VERSION 5.8 ;
BUSBITCHARS "[]" ;
DIVIDERCHAR "/" ;
UNITS
    DATABASE MICRONS 1000 ;
END UNITS

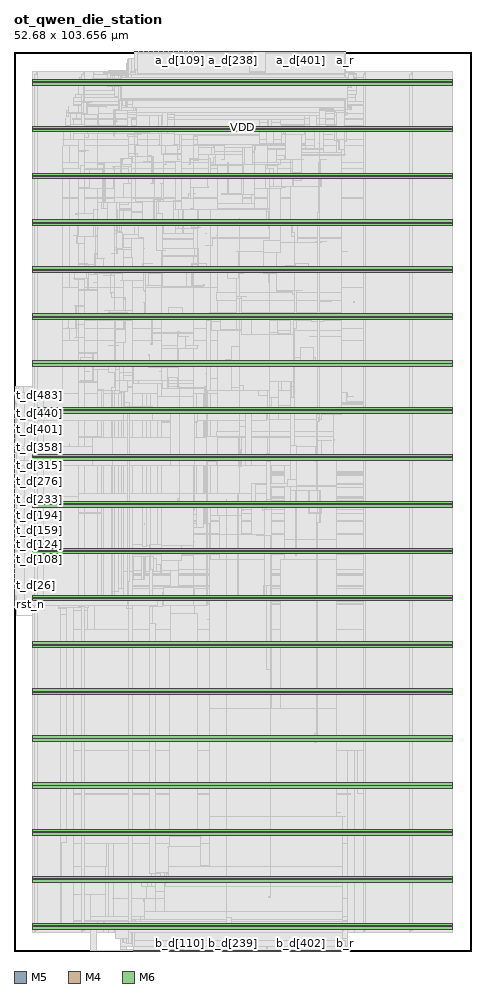
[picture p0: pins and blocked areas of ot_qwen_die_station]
MACRO ot_qwen_die_station
  FOREIGN ot_qwen_die_station 0 0 ;
  CLASS BLOCK ;
  SIZE 52.68 BY 103.656 ;
  PIN a_d[0]
    DIRECTION INPUT ;
    USE SIGNAL ;
    PORT
      LAYER M5 ;
        RECT  13.824 103.572 13.848 103.656 ;
    END
  END a_d[0]
  PIN a_d[100]
    DIRECTION INPUT ;
    USE SIGNAL ;
    PORT
      LAYER M5 ;
        RECT  18.624 103.572 18.648 103.656 ;
    END
  END a_d[100]
  PIN a_d[101]
    DIRECTION INPUT ;
    USE SIGNAL ;
    PORT
      LAYER M5 ;
        RECT  18.672 103.572 18.696 103.656 ;
    END
  END a_d[101]
  PIN a_d[102]
    DIRECTION INPUT ;
    USE SIGNAL ;
    PORT
      LAYER M5 ;
        RECT  18.72 103.572 18.744 103.656 ;
    END
  END a_d[102]
  PIN a_d[103]
    DIRECTION INPUT ;
    USE SIGNAL ;
    PORT
      LAYER M5 ;
        RECT  18.768 103.572 18.792 103.656 ;
    END
  END a_d[103]
  PIN a_d[104]
    DIRECTION INPUT ;
    USE SIGNAL ;
    PORT
      LAYER M5 ;
        RECT  18.816 103.572 18.84 103.656 ;
    END
  END a_d[104]
  PIN a_d[105]
    DIRECTION INPUT ;
    USE SIGNAL ;
    PORT
      LAYER M5 ;
        RECT  18.864 103.572 18.888 103.656 ;
    END
  END a_d[105]
  PIN a_d[106]
    DIRECTION INPUT ;
    USE SIGNAL ;
    PORT
      LAYER M5 ;
        RECT  18.912 103.572 18.936 103.656 ;
    END
  END a_d[106]
  PIN a_d[107]
    DIRECTION INPUT ;
    USE SIGNAL ;
    PORT
      LAYER M5 ;
        RECT  18.96 103.572 18.984 103.656 ;
    END
  END a_d[107]
  PIN a_d[108]
    DIRECTION INPUT ;
    USE SIGNAL ;
    PORT
      LAYER M5 ;
        RECT  19.008 103.572 19.032 103.656 ;
    END
  END a_d[108]
  PIN a_d[109]
    DIRECTION INPUT ;
    USE SIGNAL ;
    PORT
      LAYER M5 ;
        RECT  19.056 103.572 19.08 103.656 ;
    END
  END a_d[109]
  PIN a_d[10]
    DIRECTION INPUT ;
    USE SIGNAL ;
    PORT
      LAYER M5 ;
        RECT  14.304 103.572 14.328 103.656 ;
    END
  END a_d[10]
  PIN a_d[110]
    DIRECTION INPUT ;
    USE SIGNAL ;
    PORT
      LAYER M5 ;
        RECT  19.104 103.572 19.128 103.656 ;
    END
  END a_d[110]
  PIN a_d[111]
    DIRECTION INPUT ;
    USE SIGNAL ;
    PORT
      LAYER M5 ;
        RECT  19.152 103.572 19.176 103.656 ;
    END
  END a_d[111]
  PIN a_d[112]
    DIRECTION INPUT ;
    USE SIGNAL ;
    PORT
      LAYER M5 ;
        RECT  19.2 103.572 19.224 103.656 ;
    END
  END a_d[112]
  PIN a_d[113]
    DIRECTION INPUT ;
    USE SIGNAL ;
    PORT
      LAYER M5 ;
        RECT  19.248 103.572 19.272 103.656 ;
    END
  END a_d[113]
  PIN a_d[114]
    DIRECTION INPUT ;
    USE SIGNAL ;
    PORT
      LAYER M5 ;
        RECT  19.296 103.572 19.32 103.656 ;
    END
  END a_d[114]
  PIN a_d[115]
    DIRECTION INPUT ;
    USE SIGNAL ;
    PORT
      LAYER M5 ;
        RECT  19.344 103.572 19.368 103.656 ;
    END
  END a_d[115]
  PIN a_d[116]
    DIRECTION INPUT ;
    USE SIGNAL ;
    PORT
      LAYER M5 ;
        RECT  19.392 103.572 19.416 103.656 ;
    END
  END a_d[116]
  PIN a_d[117]
    DIRECTION INPUT ;
    USE SIGNAL ;
    PORT
      LAYER M5 ;
        RECT  19.44 103.572 19.464 103.656 ;
    END
  END a_d[117]
  PIN a_d[118]
    DIRECTION INPUT ;
    USE SIGNAL ;
    PORT
      LAYER M5 ;
        RECT  19.488 103.572 19.512 103.656 ;
    END
  END a_d[118]
  PIN a_d[119]
    DIRECTION INPUT ;
    USE SIGNAL ;
    PORT
      LAYER M5 ;
        RECT  19.536 103.572 19.56 103.656 ;
    END
  END a_d[119]
  PIN a_d[11]
    DIRECTION INPUT ;
    USE SIGNAL ;
    PORT
      LAYER M5 ;
        RECT  14.352 103.572 14.376 103.656 ;
    END
  END a_d[11]
  PIN a_d[120]
    DIRECTION INPUT ;
    USE SIGNAL ;
    PORT
      LAYER M5 ;
        RECT  19.584 103.572 19.608 103.656 ;
    END
  END a_d[120]
  PIN a_d[121]
    DIRECTION INPUT ;
    USE SIGNAL ;
    PORT
      LAYER M5 ;
        RECT  19.632 103.572 19.656 103.656 ;
    END
  END a_d[121]
  PIN a_d[122]
    DIRECTION INPUT ;
    USE SIGNAL ;
    PORT
      LAYER M5 ;
        RECT  19.68 103.572 19.704 103.656 ;
    END
  END a_d[122]
  PIN a_d[123]
    DIRECTION INPUT ;
    USE SIGNAL ;
    PORT
      LAYER M5 ;
        RECT  19.728 103.572 19.752 103.656 ;
    END
  END a_d[123]
  PIN a_d[124]
    DIRECTION INPUT ;
    USE SIGNAL ;
    PORT
      LAYER M5 ;
        RECT  19.776 103.572 19.8 103.656 ;
    END
  END a_d[124]
  PIN a_d[125]
    DIRECTION INPUT ;
    USE SIGNAL ;
    PORT
      LAYER M5 ;
        RECT  19.824 103.572 19.848 103.656 ;
    END
  END a_d[125]
  PIN a_d[126]
    DIRECTION INPUT ;
    USE SIGNAL ;
    PORT
      LAYER M5 ;
        RECT  19.872 103.572 19.896 103.656 ;
    END
  END a_d[126]
  PIN a_d[127]
    DIRECTION INPUT ;
    USE SIGNAL ;
    PORT
      LAYER M5 ;
        RECT  19.92 103.572 19.944 103.656 ;
    END
  END a_d[127]
  PIN a_d[128]
    DIRECTION INPUT ;
    USE SIGNAL ;
    PORT
      LAYER M5 ;
        RECT  19.968 103.572 19.992 103.656 ;
    END
  END a_d[128]
  PIN a_d[129]
    DIRECTION INPUT ;
    USE SIGNAL ;
    PORT
      LAYER M5 ;
        RECT  20.016 103.572 20.04 103.656 ;
    END
  END a_d[129]
  PIN a_d[12]
    DIRECTION INPUT ;
    USE SIGNAL ;
    PORT
      LAYER M5 ;
        RECT  14.4 103.572 14.424 103.656 ;
    END
  END a_d[12]
  PIN a_d[130]
    DIRECTION INPUT ;
    USE SIGNAL ;
    PORT
      LAYER M5 ;
        RECT  20.064 103.572 20.088 103.656 ;
    END
  END a_d[130]
  PIN a_d[131]
    DIRECTION INPUT ;
    USE SIGNAL ;
    PORT
      LAYER M5 ;
        RECT  20.112 103.572 20.136 103.656 ;
    END
  END a_d[131]
  PIN a_d[132]
    DIRECTION INPUT ;
    USE SIGNAL ;
    PORT
      LAYER M5 ;
        RECT  20.16 103.572 20.184 103.656 ;
    END
  END a_d[132]
  PIN a_d[133]
    DIRECTION INPUT ;
    USE SIGNAL ;
    PORT
      LAYER M5 ;
        RECT  20.208 103.572 20.232 103.656 ;
    END
  END a_d[133]
  PIN a_d[134]
    DIRECTION INPUT ;
    USE SIGNAL ;
    PORT
      LAYER M5 ;
        RECT  20.256 103.572 20.28 103.656 ;
    END
  END a_d[134]
  PIN a_d[135]
    DIRECTION INPUT ;
    USE SIGNAL ;
    PORT
      LAYER M5 ;
        RECT  20.304 103.572 20.328 103.656 ;
    END
  END a_d[135]
  PIN a_d[136]
    DIRECTION INPUT ;
    USE SIGNAL ;
    PORT
      LAYER M5 ;
        RECT  20.352 103.572 20.376 103.656 ;
    END
  END a_d[136]
  PIN a_d[137]
    DIRECTION INPUT ;
    USE SIGNAL ;
    PORT
      LAYER M5 ;
        RECT  20.4 103.572 20.424 103.656 ;
    END
  END a_d[137]
  PIN a_d[138]
    DIRECTION INPUT ;
    USE SIGNAL ;
    PORT
      LAYER M5 ;
        RECT  20.448 103.572 20.472 103.656 ;
    END
  END a_d[138]
  PIN a_d[139]
    DIRECTION INPUT ;
    USE SIGNAL ;
    PORT
      LAYER M5 ;
        RECT  20.496 103.572 20.52 103.656 ;
    END
  END a_d[139]
  PIN a_d[13]
    DIRECTION INPUT ;
    USE SIGNAL ;
    PORT
      LAYER M5 ;
        RECT  14.448 103.572 14.472 103.656 ;
    END
  END a_d[13]
  PIN a_d[140]
    DIRECTION INPUT ;
    USE SIGNAL ;
    PORT
      LAYER M5 ;
        RECT  20.544 103.572 20.568 103.656 ;
    END
  END a_d[140]
  PIN a_d[141]
    DIRECTION INPUT ;
    USE SIGNAL ;
    PORT
      LAYER M5 ;
        RECT  20.592 103.572 20.616 103.656 ;
    END
  END a_d[141]
  PIN a_d[142]
    DIRECTION INPUT ;
    USE SIGNAL ;
    PORT
      LAYER M5 ;
        RECT  20.64 103.572 20.664 103.656 ;
    END
  END a_d[142]
  PIN a_d[143]
    DIRECTION INPUT ;
    USE SIGNAL ;
    PORT
      LAYER M5 ;
        RECT  20.688 103.572 20.712 103.656 ;
    END
  END a_d[143]
  PIN a_d[144]
    DIRECTION INPUT ;
    USE SIGNAL ;
    PORT
      LAYER M5 ;
        RECT  20.736 103.572 20.76 103.656 ;
    END
  END a_d[144]
  PIN a_d[145]
    DIRECTION INPUT ;
    USE SIGNAL ;
    PORT
      LAYER M5 ;
        RECT  20.784 103.572 20.808 103.656 ;
    END
  END a_d[145]
  PIN a_d[146]
    DIRECTION INPUT ;
    USE SIGNAL ;
    PORT
      LAYER M5 ;
        RECT  20.832 103.572 20.856 103.656 ;
    END
  END a_d[146]
  PIN a_d[147]
    DIRECTION INPUT ;
    USE SIGNAL ;
    PORT
      LAYER M5 ;
        RECT  20.88 103.572 20.904 103.656 ;
    END
  END a_d[147]
  PIN a_d[148]
    DIRECTION INPUT ;
    USE SIGNAL ;
    PORT
      LAYER M5 ;
        RECT  20.928 103.572 20.952 103.656 ;
    END
  END a_d[148]
  PIN a_d[149]
    DIRECTION INPUT ;
    USE SIGNAL ;
    PORT
      LAYER M5 ;
        RECT  20.976 103.572 21 103.656 ;
    END
  END a_d[149]
  PIN a_d[14]
    DIRECTION INPUT ;
    USE SIGNAL ;
    PORT
      LAYER M5 ;
        RECT  14.496 103.572 14.52 103.656 ;
    END
  END a_d[14]
  PIN a_d[150]
    DIRECTION INPUT ;
    USE SIGNAL ;
    PORT
      LAYER M5 ;
        RECT  21.024 103.572 21.048 103.656 ;
    END
  END a_d[150]
  PIN a_d[151]
    DIRECTION INPUT ;
    USE SIGNAL ;
    PORT
      LAYER M5 ;
        RECT  21.072 103.572 21.096 103.656 ;
    END
  END a_d[151]
  PIN a_d[152]
    DIRECTION INPUT ;
    USE SIGNAL ;
    PORT
      LAYER M5 ;
        RECT  21.12 103.572 21.144 103.656 ;
    END
  END a_d[152]
  PIN a_d[153]
    DIRECTION INPUT ;
    USE SIGNAL ;
    PORT
      LAYER M5 ;
        RECT  21.168 103.572 21.192 103.656 ;
    END
  END a_d[153]
  PIN a_d[154]
    DIRECTION INPUT ;
    USE SIGNAL ;
    PORT
      LAYER M5 ;
        RECT  21.216 103.572 21.24 103.656 ;
    END
  END a_d[154]
  PIN a_d[155]
    DIRECTION INPUT ;
    USE SIGNAL ;
    PORT
      LAYER M5 ;
        RECT  21.264 103.572 21.288 103.656 ;
    END
  END a_d[155]
  PIN a_d[156]
    DIRECTION INPUT ;
    USE SIGNAL ;
    PORT
      LAYER M5 ;
        RECT  21.312 103.572 21.336 103.656 ;
    END
  END a_d[156]
  PIN a_d[157]
    DIRECTION INPUT ;
    USE SIGNAL ;
    PORT
      LAYER M5 ;
        RECT  21.36 103.572 21.384 103.656 ;
    END
  END a_d[157]
  PIN a_d[158]
    DIRECTION INPUT ;
    USE SIGNAL ;
    PORT
      LAYER M5 ;
        RECT  21.408 103.572 21.432 103.656 ;
    END
  END a_d[158]
  PIN a_d[159]
    DIRECTION INPUT ;
    USE SIGNAL ;
    PORT
      LAYER M5 ;
        RECT  21.456 103.572 21.48 103.656 ;
    END
  END a_d[159]
  PIN a_d[15]
    DIRECTION INPUT ;
    USE SIGNAL ;
    PORT
      LAYER M5 ;
        RECT  14.544 103.572 14.568 103.656 ;
    END
  END a_d[15]
  PIN a_d[160]
    DIRECTION INPUT ;
    USE SIGNAL ;
    PORT
      LAYER M5 ;
        RECT  21.504 103.572 21.528 103.656 ;
    END
  END a_d[160]
  PIN a_d[161]
    DIRECTION INPUT ;
    USE SIGNAL ;
    PORT
      LAYER M5 ;
        RECT  21.552 103.572 21.576 103.656 ;
    END
  END a_d[161]
  PIN a_d[162]
    DIRECTION INPUT ;
    USE SIGNAL ;
    PORT
      LAYER M5 ;
        RECT  21.6 103.572 21.624 103.656 ;
    END
  END a_d[162]
  PIN a_d[163]
    DIRECTION INPUT ;
    USE SIGNAL ;
    PORT
      LAYER M5 ;
        RECT  21.648 103.572 21.672 103.656 ;
    END
  END a_d[163]
  PIN a_d[164]
    DIRECTION INPUT ;
    USE SIGNAL ;
    PORT
      LAYER M5 ;
        RECT  21.696 103.572 21.72 103.656 ;
    END
  END a_d[164]
  PIN a_d[165]
    DIRECTION INPUT ;
    USE SIGNAL ;
    PORT
      LAYER M5 ;
        RECT  21.744 103.572 21.768 103.656 ;
    END
  END a_d[165]
  PIN a_d[166]
    DIRECTION INPUT ;
    USE SIGNAL ;
    PORT
      LAYER M5 ;
        RECT  21.792 103.572 21.816 103.656 ;
    END
  END a_d[166]
  PIN a_d[167]
    DIRECTION INPUT ;
    USE SIGNAL ;
    PORT
      LAYER M5 ;
        RECT  21.84 103.572 21.864 103.656 ;
    END
  END a_d[167]
  PIN a_d[168]
    DIRECTION INPUT ;
    USE SIGNAL ;
    PORT
      LAYER M5 ;
        RECT  21.888 103.572 21.912 103.656 ;
    END
  END a_d[168]
  PIN a_d[169]
    DIRECTION INPUT ;
    USE SIGNAL ;
    PORT
      LAYER M5 ;
        RECT  21.936 103.572 21.96 103.656 ;
    END
  END a_d[169]
  PIN a_d[16]
    DIRECTION INPUT ;
    USE SIGNAL ;
    PORT
      LAYER M5 ;
        RECT  14.592 103.572 14.616 103.656 ;
    END
  END a_d[16]
  PIN a_d[170]
    DIRECTION INPUT ;
    USE SIGNAL ;
    PORT
      LAYER M5 ;
        RECT  21.984 103.572 22.008 103.656 ;
    END
  END a_d[170]
  PIN a_d[171]
    DIRECTION INPUT ;
    USE SIGNAL ;
    PORT
      LAYER M5 ;
        RECT  22.032 103.572 22.056 103.656 ;
    END
  END a_d[171]
  PIN a_d[172]
    DIRECTION INPUT ;
    USE SIGNAL ;
    PORT
      LAYER M5 ;
        RECT  22.08 103.572 22.104 103.656 ;
    END
  END a_d[172]
  PIN a_d[173]
    DIRECTION INPUT ;
    USE SIGNAL ;
    PORT
      LAYER M5 ;
        RECT  22.128 103.572 22.152 103.656 ;
    END
  END a_d[173]
  PIN a_d[174]
    DIRECTION INPUT ;
    USE SIGNAL ;
    PORT
      LAYER M5 ;
        RECT  22.176 103.572 22.2 103.656 ;
    END
  END a_d[174]
  PIN a_d[175]
    DIRECTION INPUT ;
    USE SIGNAL ;
    PORT
      LAYER M5 ;
        RECT  22.224 103.572 22.248 103.656 ;
    END
  END a_d[175]
  PIN a_d[176]
    DIRECTION INPUT ;
    USE SIGNAL ;
    PORT
      LAYER M5 ;
        RECT  22.272 103.572 22.296 103.656 ;
    END
  END a_d[176]
  PIN a_d[177]
    DIRECTION INPUT ;
    USE SIGNAL ;
    PORT
      LAYER M5 ;
        RECT  22.32 103.572 22.344 103.656 ;
    END
  END a_d[177]
  PIN a_d[178]
    DIRECTION INPUT ;
    USE SIGNAL ;
    PORT
      LAYER M5 ;
        RECT  22.368 103.572 22.392 103.656 ;
    END
  END a_d[178]
  PIN a_d[179]
    DIRECTION INPUT ;
    USE SIGNAL ;
    PORT
      LAYER M5 ;
        RECT  22.416 103.572 22.44 103.656 ;
    END
  END a_d[179]
  PIN a_d[17]
    DIRECTION INPUT ;
    USE SIGNAL ;
    PORT
      LAYER M5 ;
        RECT  14.64 103.572 14.664 103.656 ;
    END
  END a_d[17]
  PIN a_d[180]
    DIRECTION INPUT ;
    USE SIGNAL ;
    PORT
      LAYER M5 ;
        RECT  22.464 103.572 22.488 103.656 ;
    END
  END a_d[180]
  PIN a_d[181]
    DIRECTION INPUT ;
    USE SIGNAL ;
    PORT
      LAYER M5 ;
        RECT  22.512 103.572 22.536 103.656 ;
    END
  END a_d[181]
  PIN a_d[182]
    DIRECTION INPUT ;
    USE SIGNAL ;
    PORT
      LAYER M5 ;
        RECT  22.56 103.572 22.584 103.656 ;
    END
  END a_d[182]
  PIN a_d[183]
    DIRECTION INPUT ;
    USE SIGNAL ;
    PORT
      LAYER M5 ;
        RECT  22.608 103.572 22.632 103.656 ;
    END
  END a_d[183]
  PIN a_d[184]
    DIRECTION INPUT ;
    USE SIGNAL ;
    PORT
      LAYER M5 ;
        RECT  22.656 103.572 22.68 103.656 ;
    END
  END a_d[184]
  PIN a_d[185]
    DIRECTION INPUT ;
    USE SIGNAL ;
    PORT
      LAYER M5 ;
        RECT  22.704 103.572 22.728 103.656 ;
    END
  END a_d[185]
  PIN a_d[186]
    DIRECTION INPUT ;
    USE SIGNAL ;
    PORT
      LAYER M5 ;
        RECT  22.752 103.572 22.776 103.656 ;
    END
  END a_d[186]
  PIN a_d[187]
    DIRECTION INPUT ;
    USE SIGNAL ;
    PORT
      LAYER M5 ;
        RECT  22.8 103.572 22.824 103.656 ;
    END
  END a_d[187]
  PIN a_d[188]
    DIRECTION INPUT ;
    USE SIGNAL ;
    PORT
      LAYER M5 ;
        RECT  22.848 103.572 22.872 103.656 ;
    END
  END a_d[188]
  PIN a_d[189]
    DIRECTION INPUT ;
    USE SIGNAL ;
    PORT
      LAYER M5 ;
        RECT  22.896 103.572 22.92 103.656 ;
    END
  END a_d[189]
  PIN a_d[18]
    DIRECTION INPUT ;
    USE SIGNAL ;
    PORT
      LAYER M5 ;
        RECT  14.688 103.572 14.712 103.656 ;
    END
  END a_d[18]
  PIN a_d[190]
    DIRECTION INPUT ;
    USE SIGNAL ;
    PORT
      LAYER M5 ;
        RECT  22.944 103.572 22.968 103.656 ;
    END
  END a_d[190]
  PIN a_d[191]
    DIRECTION INPUT ;
    USE SIGNAL ;
    PORT
      LAYER M5 ;
        RECT  22.992 103.572 23.016 103.656 ;
    END
  END a_d[191]
  PIN a_d[192]
    DIRECTION INPUT ;
    USE SIGNAL ;
    PORT
      LAYER M5 ;
        RECT  23.04 103.572 23.064 103.656 ;
    END
  END a_d[192]
  PIN a_d[193]
    DIRECTION INPUT ;
    USE SIGNAL ;
    PORT
      LAYER M5 ;
        RECT  23.088 103.572 23.112 103.656 ;
    END
  END a_d[193]
  PIN a_d[194]
    DIRECTION INPUT ;
    USE SIGNAL ;
    PORT
      LAYER M5 ;
        RECT  23.136 103.572 23.16 103.656 ;
    END
  END a_d[194]
  PIN a_d[195]
    DIRECTION INPUT ;
    USE SIGNAL ;
    PORT
      LAYER M5 ;
        RECT  23.184 103.572 23.208 103.656 ;
    END
  END a_d[195]
  PIN a_d[196]
    DIRECTION INPUT ;
    USE SIGNAL ;
    PORT
      LAYER M5 ;
        RECT  23.232 103.572 23.256 103.656 ;
    END
  END a_d[196]
  PIN a_d[197]
    DIRECTION INPUT ;
    USE SIGNAL ;
    PORT
      LAYER M5 ;
        RECT  23.28 103.572 23.304 103.656 ;
    END
  END a_d[197]
  PIN a_d[198]
    DIRECTION INPUT ;
    USE SIGNAL ;
    PORT
      LAYER M5 ;
        RECT  23.328 103.572 23.352 103.656 ;
    END
  END a_d[198]
  PIN a_d[199]
    DIRECTION INPUT ;
    USE SIGNAL ;
    PORT
      LAYER M5 ;
        RECT  23.376 103.572 23.4 103.656 ;
    END
  END a_d[199]
  PIN a_d[19]
    DIRECTION INPUT ;
    USE SIGNAL ;
    PORT
      LAYER M5 ;
        RECT  14.736 103.572 14.76 103.656 ;
    END
  END a_d[19]
  PIN a_d[1]
    DIRECTION INPUT ;
    USE SIGNAL ;
    PORT
      LAYER M5 ;
        RECT  13.872 103.572 13.896 103.656 ;
    END
  END a_d[1]
  PIN a_d[200]
    DIRECTION INPUT ;
    USE SIGNAL ;
    PORT
      LAYER M5 ;
        RECT  23.424 103.572 23.448 103.656 ;
    END
  END a_d[200]
  PIN a_d[201]
    DIRECTION INPUT ;
    USE SIGNAL ;
    PORT
      LAYER M5 ;
        RECT  23.472 103.572 23.496 103.656 ;
    END
  END a_d[201]
  PIN a_d[202]
    DIRECTION INPUT ;
    USE SIGNAL ;
    PORT
      LAYER M5 ;
        RECT  23.52 103.572 23.544 103.656 ;
    END
  END a_d[202]
  PIN a_d[203]
    DIRECTION INPUT ;
    USE SIGNAL ;
    PORT
      LAYER M5 ;
        RECT  23.568 103.572 23.592 103.656 ;
    END
  END a_d[203]
  PIN a_d[204]
    DIRECTION INPUT ;
    USE SIGNAL ;
    PORT
      LAYER M5 ;
        RECT  23.616 103.572 23.64 103.656 ;
    END
  END a_d[204]
  PIN a_d[205]
    DIRECTION INPUT ;
    USE SIGNAL ;
    PORT
      LAYER M5 ;
        RECT  23.664 103.572 23.688 103.656 ;
    END
  END a_d[205]
  PIN a_d[206]
    DIRECTION INPUT ;
    USE SIGNAL ;
    PORT
      LAYER M5 ;
        RECT  23.712 103.572 23.736 103.656 ;
    END
  END a_d[206]
  PIN a_d[207]
    DIRECTION INPUT ;
    USE SIGNAL ;
    PORT
      LAYER M5 ;
        RECT  23.76 103.572 23.784 103.656 ;
    END
  END a_d[207]
  PIN a_d[208]
    DIRECTION INPUT ;
    USE SIGNAL ;
    PORT
      LAYER M5 ;
        RECT  23.808 103.572 23.832 103.656 ;
    END
  END a_d[208]
  PIN a_d[209]
    DIRECTION INPUT ;
    USE SIGNAL ;
    PORT
      LAYER M5 ;
        RECT  23.856 103.572 23.88 103.656 ;
    END
  END a_d[209]
  PIN a_d[20]
    DIRECTION INPUT ;
    USE SIGNAL ;
    PORT
      LAYER M5 ;
        RECT  14.784 103.572 14.808 103.656 ;
    END
  END a_d[20]
  PIN a_d[210]
    DIRECTION INPUT ;
    USE SIGNAL ;
    PORT
      LAYER M5 ;
        RECT  23.904 103.572 23.928 103.656 ;
    END
  END a_d[210]
  PIN a_d[211]
    DIRECTION INPUT ;
    USE SIGNAL ;
    PORT
      LAYER M5 ;
        RECT  23.952 103.572 23.976 103.656 ;
    END
  END a_d[211]
  PIN a_d[212]
    DIRECTION INPUT ;
    USE SIGNAL ;
    PORT
      LAYER M5 ;
        RECT  24 103.572 24.024 103.656 ;
    END
  END a_d[212]
  PIN a_d[213]
    DIRECTION INPUT ;
    USE SIGNAL ;
    PORT
      LAYER M5 ;
        RECT  24.048 103.572 24.072 103.656 ;
    END
  END a_d[213]
  PIN a_d[214]
    DIRECTION INPUT ;
    USE SIGNAL ;
    PORT
      LAYER M5 ;
        RECT  24.096 103.572 24.12 103.656 ;
    END
  END a_d[214]
  PIN a_d[215]
    DIRECTION INPUT ;
    USE SIGNAL ;
    PORT
      LAYER M5 ;
        RECT  24.144 103.572 24.168 103.656 ;
    END
  END a_d[215]
  PIN a_d[216]
    DIRECTION INPUT ;
    USE SIGNAL ;
    PORT
      LAYER M5 ;
        RECT  24.192 103.572 24.216 103.656 ;
    END
  END a_d[216]
  PIN a_d[217]
    DIRECTION INPUT ;
    USE SIGNAL ;
    PORT
      LAYER M5 ;
        RECT  24.24 103.572 24.264 103.656 ;
    END
  END a_d[217]
  PIN a_d[218]
    DIRECTION INPUT ;
    USE SIGNAL ;
    PORT
      LAYER M5 ;
        RECT  24.288 103.572 24.312 103.656 ;
    END
  END a_d[218]
  PIN a_d[219]
    DIRECTION INPUT ;
    USE SIGNAL ;
    PORT
      LAYER M5 ;
        RECT  24.336 103.572 24.36 103.656 ;
    END
  END a_d[219]
  PIN a_d[21]
    DIRECTION INPUT ;
    USE SIGNAL ;
    PORT
      LAYER M5 ;
        RECT  14.832 103.572 14.856 103.656 ;
    END
  END a_d[21]
  PIN a_d[220]
    DIRECTION INPUT ;
    USE SIGNAL ;
    PORT
      LAYER M5 ;
        RECT  24.384 103.572 24.408 103.656 ;
    END
  END a_d[220]
  PIN a_d[221]
    DIRECTION INPUT ;
    USE SIGNAL ;
    PORT
      LAYER M5 ;
        RECT  24.432 103.572 24.456 103.656 ;
    END
  END a_d[221]
  PIN a_d[222]
    DIRECTION INPUT ;
    USE SIGNAL ;
    PORT
      LAYER M5 ;
        RECT  24.48 103.572 24.504 103.656 ;
    END
  END a_d[222]
  PIN a_d[223]
    DIRECTION INPUT ;
    USE SIGNAL ;
    PORT
      LAYER M5 ;
        RECT  24.528 103.572 24.552 103.656 ;
    END
  END a_d[223]
  PIN a_d[224]
    DIRECTION INPUT ;
    USE SIGNAL ;
    PORT
      LAYER M5 ;
        RECT  24.576 103.572 24.6 103.656 ;
    END
  END a_d[224]
  PIN a_d[225]
    DIRECTION INPUT ;
    USE SIGNAL ;
    PORT
      LAYER M5 ;
        RECT  24.624 103.572 24.648 103.656 ;
    END
  END a_d[225]
  PIN a_d[226]
    DIRECTION INPUT ;
    USE SIGNAL ;
    PORT
      LAYER M5 ;
        RECT  24.672 103.572 24.696 103.656 ;
    END
  END a_d[226]
  PIN a_d[227]
    DIRECTION INPUT ;
    USE SIGNAL ;
    PORT
      LAYER M5 ;
        RECT  24.72 103.572 24.744 103.656 ;
    END
  END a_d[227]
  PIN a_d[228]
    DIRECTION INPUT ;
    USE SIGNAL ;
    PORT
      LAYER M5 ;
        RECT  24.768 103.572 24.792 103.656 ;
    END
  END a_d[228]
  PIN a_d[229]
    DIRECTION INPUT ;
    USE SIGNAL ;
    PORT
      LAYER M5 ;
        RECT  24.816 103.572 24.84 103.656 ;
    END
  END a_d[229]
  PIN a_d[22]
    DIRECTION INPUT ;
    USE SIGNAL ;
    PORT
      LAYER M5 ;
        RECT  14.88 103.572 14.904 103.656 ;
    END
  END a_d[22]
  PIN a_d[230]
    DIRECTION INPUT ;
    USE SIGNAL ;
    PORT
      LAYER M5 ;
        RECT  24.864 103.572 24.888 103.656 ;
    END
  END a_d[230]
  PIN a_d[231]
    DIRECTION INPUT ;
    USE SIGNAL ;
    PORT
      LAYER M5 ;
        RECT  24.912 103.572 24.936 103.656 ;
    END
  END a_d[231]
  PIN a_d[232]
    DIRECTION INPUT ;
    USE SIGNAL ;
    PORT
      LAYER M5 ;
        RECT  24.96 103.572 24.984 103.656 ;
    END
  END a_d[232]
  PIN a_d[233]
    DIRECTION INPUT ;
    USE SIGNAL ;
    PORT
      LAYER M5 ;
        RECT  25.008 103.572 25.032 103.656 ;
    END
  END a_d[233]
  PIN a_d[234]
    DIRECTION INPUT ;
    USE SIGNAL ;
    PORT
      LAYER M5 ;
        RECT  25.056 103.572 25.08 103.656 ;
    END
  END a_d[234]
  PIN a_d[235]
    DIRECTION INPUT ;
    USE SIGNAL ;
    PORT
      LAYER M5 ;
        RECT  25.104 103.572 25.128 103.656 ;
    END
  END a_d[235]
  PIN a_d[236]
    DIRECTION INPUT ;
    USE SIGNAL ;
    PORT
      LAYER M5 ;
        RECT  25.152 103.572 25.176 103.656 ;
    END
  END a_d[236]
  PIN a_d[237]
    DIRECTION INPUT ;
    USE SIGNAL ;
    PORT
      LAYER M5 ;
        RECT  25.2 103.572 25.224 103.656 ;
    END
  END a_d[237]
  PIN a_d[238]
    DIRECTION INPUT ;
    USE SIGNAL ;
    PORT
      LAYER M5 ;
        RECT  25.248 103.572 25.272 103.656 ;
    END
  END a_d[238]
  PIN a_d[239]
    DIRECTION INPUT ;
    USE SIGNAL ;
    PORT
      LAYER M5 ;
        RECT  25.296 103.572 25.32 103.656 ;
    END
  END a_d[239]
  PIN a_d[23]
    DIRECTION INPUT ;
    USE SIGNAL ;
    PORT
      LAYER M5 ;
        RECT  14.928 103.572 14.952 103.656 ;
    END
  END a_d[23]
  PIN a_d[240]
    DIRECTION INPUT ;
    USE SIGNAL ;
    PORT
      LAYER M5 ;
        RECT  25.344 103.572 25.368 103.656 ;
    END
  END a_d[240]
  PIN a_d[241]
    DIRECTION INPUT ;
    USE SIGNAL ;
    PORT
      LAYER M5 ;
        RECT  25.392 103.572 25.416 103.656 ;
    END
  END a_d[241]
  PIN a_d[242]
    DIRECTION INPUT ;
    USE SIGNAL ;
    PORT
      LAYER M5 ;
        RECT  25.44 103.572 25.464 103.656 ;
    END
  END a_d[242]
  PIN a_d[243]
    DIRECTION INPUT ;
    USE SIGNAL ;
    PORT
      LAYER M5 ;
        RECT  25.488 103.572 25.512 103.656 ;
    END
  END a_d[243]
  PIN a_d[244]
    DIRECTION INPUT ;
    USE SIGNAL ;
    PORT
      LAYER M5 ;
        RECT  25.536 103.572 25.56 103.656 ;
    END
  END a_d[244]
  PIN a_d[245]
    DIRECTION INPUT ;
    USE SIGNAL ;
    PORT
      LAYER M5 ;
        RECT  25.584 103.572 25.608 103.656 ;
    END
  END a_d[245]
  PIN a_d[246]
    DIRECTION INPUT ;
    USE SIGNAL ;
    PORT
      LAYER M5 ;
        RECT  25.632 103.572 25.656 103.656 ;
    END
  END a_d[246]
  PIN a_d[247]
    DIRECTION INPUT ;
    USE SIGNAL ;
    PORT
      LAYER M5 ;
        RECT  25.68 103.572 25.704 103.656 ;
    END
  END a_d[247]
  PIN a_d[248]
    DIRECTION INPUT ;
    USE SIGNAL ;
    PORT
      LAYER M5 ;
        RECT  25.728 103.572 25.752 103.656 ;
    END
  END a_d[248]
  PIN a_d[249]
    DIRECTION INPUT ;
    USE SIGNAL ;
    PORT
      LAYER M5 ;
        RECT  25.776 103.572 25.8 103.656 ;
    END
  END a_d[249]
  PIN a_d[24]
    DIRECTION INPUT ;
    USE SIGNAL ;
    PORT
      LAYER M5 ;
        RECT  14.976 103.572 15 103.656 ;
    END
  END a_d[24]
  PIN a_d[250]
    DIRECTION INPUT ;
    USE SIGNAL ;
    PORT
      LAYER M5 ;
        RECT  25.824 103.572 25.848 103.656 ;
    END
  END a_d[250]
  PIN a_d[251]
    DIRECTION INPUT ;
    USE SIGNAL ;
    PORT
      LAYER M5 ;
        RECT  25.872 103.572 25.896 103.656 ;
    END
  END a_d[251]
  PIN a_d[252]
    DIRECTION INPUT ;
    USE SIGNAL ;
    PORT
      LAYER M5 ;
        RECT  25.92 103.572 25.944 103.656 ;
    END
  END a_d[252]
  PIN a_d[253]
    DIRECTION INPUT ;
    USE SIGNAL ;
    PORT
      LAYER M5 ;
        RECT  25.968 103.572 25.992 103.656 ;
    END
  END a_d[253]
  PIN a_d[254]
    DIRECTION INPUT ;
    USE SIGNAL ;
    PORT
      LAYER M5 ;
        RECT  26.016 103.572 26.04 103.656 ;
    END
  END a_d[254]
  PIN a_d[255]
    DIRECTION INPUT ;
    USE SIGNAL ;
    PORT
      LAYER M5 ;
        RECT  26.064 103.572 26.088 103.656 ;
    END
  END a_d[255]
  PIN a_d[256]
    DIRECTION INPUT ;
    USE SIGNAL ;
    PORT
      LAYER M5 ;
        RECT  26.112 103.572 26.136 103.656 ;
    END
  END a_d[256]
  PIN a_d[257]
    DIRECTION INPUT ;
    USE SIGNAL ;
    PORT
      LAYER M5 ;
        RECT  26.16 103.572 26.184 103.656 ;
    END
  END a_d[257]
  PIN a_d[258]
    DIRECTION INPUT ;
    USE SIGNAL ;
    PORT
      LAYER M5 ;
        RECT  26.208 103.572 26.232 103.656 ;
    END
  END a_d[258]
  PIN a_d[259]
    DIRECTION INPUT ;
    USE SIGNAL ;
    PORT
      LAYER M5 ;
        RECT  26.256 103.572 26.28 103.656 ;
    END
  END a_d[259]
  PIN a_d[25]
    DIRECTION INPUT ;
    USE SIGNAL ;
    PORT
      LAYER M5 ;
        RECT  15.024 103.572 15.048 103.656 ;
    END
  END a_d[25]
  PIN a_d[260]
    DIRECTION INPUT ;
    USE SIGNAL ;
    PORT
      LAYER M5 ;
        RECT  26.304 103.572 26.328 103.656 ;
    END
  END a_d[260]
  PIN a_d[261]
    DIRECTION INPUT ;
    USE SIGNAL ;
    PORT
      LAYER M5 ;
        RECT  26.352 103.572 26.376 103.656 ;
    END
  END a_d[261]
  PIN a_d[262]
    DIRECTION INPUT ;
    USE SIGNAL ;
    PORT
      LAYER M5 ;
        RECT  26.4 103.572 26.424 103.656 ;
    END
  END a_d[262]
  PIN a_d[263]
    DIRECTION INPUT ;
    USE SIGNAL ;
    PORT
      LAYER M5 ;
        RECT  26.448 103.572 26.472 103.656 ;
    END
  END a_d[263]
  PIN a_d[264]
    DIRECTION INPUT ;
    USE SIGNAL ;
    PORT
      LAYER M5 ;
        RECT  26.496 103.572 26.52 103.656 ;
    END
  END a_d[264]
  PIN a_d[265]
    DIRECTION INPUT ;
    USE SIGNAL ;
    PORT
      LAYER M5 ;
        RECT  26.544 103.572 26.568 103.656 ;
    END
  END a_d[265]
  PIN a_d[266]
    DIRECTION INPUT ;
    USE SIGNAL ;
    PORT
      LAYER M5 ;
        RECT  26.592 103.572 26.616 103.656 ;
    END
  END a_d[266]
  PIN a_d[267]
    DIRECTION INPUT ;
    USE SIGNAL ;
    PORT
      LAYER M5 ;
        RECT  26.64 103.572 26.664 103.656 ;
    END
  END a_d[267]
  PIN a_d[268]
    DIRECTION INPUT ;
    USE SIGNAL ;
    PORT
      LAYER M5 ;
        RECT  26.688 103.572 26.712 103.656 ;
    END
  END a_d[268]
  PIN a_d[269]
    DIRECTION INPUT ;
    USE SIGNAL ;
    PORT
      LAYER M5 ;
        RECT  26.736 103.572 26.76 103.656 ;
    END
  END a_d[269]
  PIN a_d[26]
    DIRECTION INPUT ;
    USE SIGNAL ;
    PORT
      LAYER M5 ;
        RECT  15.072 103.572 15.096 103.656 ;
    END
  END a_d[26]
  PIN a_d[270]
    DIRECTION INPUT ;
    USE SIGNAL ;
    PORT
      LAYER M5 ;
        RECT  26.784 103.572 26.808 103.656 ;
    END
  END a_d[270]
  PIN a_d[271]
    DIRECTION INPUT ;
    USE SIGNAL ;
    PORT
      LAYER M5 ;
        RECT  26.832 103.572 26.856 103.656 ;
    END
  END a_d[271]
  PIN a_d[272]
    DIRECTION INPUT ;
    USE SIGNAL ;
    PORT
      LAYER M5 ;
        RECT  26.88 103.572 26.904 103.656 ;
    END
  END a_d[272]
  PIN a_d[273]
    DIRECTION INPUT ;
    USE SIGNAL ;
    PORT
      LAYER M5 ;
        RECT  26.928 103.572 26.952 103.656 ;
    END
  END a_d[273]
  PIN a_d[274]
    DIRECTION INPUT ;
    USE SIGNAL ;
    PORT
      LAYER M5 ;
        RECT  26.976 103.572 27 103.656 ;
    END
  END a_d[274]
  PIN a_d[275]
    DIRECTION INPUT ;
    USE SIGNAL ;
    PORT
      LAYER M5 ;
        RECT  27.024 103.572 27.048 103.656 ;
    END
  END a_d[275]
  PIN a_d[276]
    DIRECTION INPUT ;
    USE SIGNAL ;
    PORT
      LAYER M5 ;
        RECT  27.072 103.572 27.096 103.656 ;
    END
  END a_d[276]
  PIN a_d[277]
    DIRECTION INPUT ;
    USE SIGNAL ;
    PORT
      LAYER M5 ;
        RECT  27.12 103.572 27.144 103.656 ;
    END
  END a_d[277]
  PIN a_d[278]
    DIRECTION INPUT ;
    USE SIGNAL ;
    PORT
      LAYER M5 ;
        RECT  27.168 103.572 27.192 103.656 ;
    END
  END a_d[278]
  PIN a_d[279]
    DIRECTION INPUT ;
    USE SIGNAL ;
    PORT
      LAYER M5 ;
        RECT  27.216 103.572 27.24 103.656 ;
    END
  END a_d[279]
  PIN a_d[27]
    DIRECTION INPUT ;
    USE SIGNAL ;
    PORT
      LAYER M5 ;
        RECT  15.12 103.572 15.144 103.656 ;
    END
  END a_d[27]
  PIN a_d[280]
    DIRECTION INPUT ;
    USE SIGNAL ;
    PORT
      LAYER M5 ;
        RECT  27.264 103.572 27.288 103.656 ;
    END
  END a_d[280]
  PIN a_d[281]
    DIRECTION INPUT ;
    USE SIGNAL ;
    PORT
      LAYER M5 ;
        RECT  27.312 103.572 27.336 103.656 ;
    END
  END a_d[281]
  PIN a_d[282]
    DIRECTION INPUT ;
    USE SIGNAL ;
    PORT
      LAYER M5 ;
        RECT  27.36 103.572 27.384 103.656 ;
    END
  END a_d[282]
  PIN a_d[283]
    DIRECTION INPUT ;
    USE SIGNAL ;
    PORT
      LAYER M5 ;
        RECT  27.408 103.572 27.432 103.656 ;
    END
  END a_d[283]
  PIN a_d[284]
    DIRECTION INPUT ;
    USE SIGNAL ;
    PORT
      LAYER M5 ;
        RECT  27.456 103.572 27.48 103.656 ;
    END
  END a_d[284]
  PIN a_d[285]
    DIRECTION INPUT ;
    USE SIGNAL ;
    PORT
      LAYER M5 ;
        RECT  27.504 103.572 27.528 103.656 ;
    END
  END a_d[285]
  PIN a_d[286]
    DIRECTION INPUT ;
    USE SIGNAL ;
    PORT
      LAYER M5 ;
        RECT  27.552 103.572 27.576 103.656 ;
    END
  END a_d[286]
  PIN a_d[287]
    DIRECTION INPUT ;
    USE SIGNAL ;
    PORT
      LAYER M5 ;
        RECT  27.6 103.572 27.624 103.656 ;
    END
  END a_d[287]
  PIN a_d[288]
    DIRECTION INPUT ;
    USE SIGNAL ;
    PORT
      LAYER M5 ;
        RECT  27.648 103.572 27.672 103.656 ;
    END
  END a_d[288]
  PIN a_d[289]
    DIRECTION INPUT ;
    USE SIGNAL ;
    PORT
      LAYER M5 ;
        RECT  27.696 103.572 27.72 103.656 ;
    END
  END a_d[289]
  PIN a_d[28]
    DIRECTION INPUT ;
    USE SIGNAL ;
    PORT
      LAYER M5 ;
        RECT  15.168 103.572 15.192 103.656 ;
    END
  END a_d[28]
  PIN a_d[290]
    DIRECTION INPUT ;
    USE SIGNAL ;
    PORT
      LAYER M5 ;
        RECT  27.744 103.572 27.768 103.656 ;
    END
  END a_d[290]
  PIN a_d[291]
    DIRECTION INPUT ;
    USE SIGNAL ;
    PORT
      LAYER M5 ;
        RECT  27.792 103.572 27.816 103.656 ;
    END
  END a_d[291]
  PIN a_d[292]
    DIRECTION INPUT ;
    USE SIGNAL ;
    PORT
      LAYER M5 ;
        RECT  27.84 103.572 27.864 103.656 ;
    END
  END a_d[292]
  PIN a_d[293]
    DIRECTION INPUT ;
    USE SIGNAL ;
    PORT
      LAYER M5 ;
        RECT  27.888 103.572 27.912 103.656 ;
    END
  END a_d[293]
  PIN a_d[294]
    DIRECTION INPUT ;
    USE SIGNAL ;
    PORT
      LAYER M5 ;
        RECT  27.936 103.572 27.96 103.656 ;
    END
  END a_d[294]
  PIN a_d[295]
    DIRECTION INPUT ;
    USE SIGNAL ;
    PORT
      LAYER M5 ;
        RECT  27.984 103.572 28.008 103.656 ;
    END
  END a_d[295]
  PIN a_d[296]
    DIRECTION INPUT ;
    USE SIGNAL ;
    PORT
      LAYER M5 ;
        RECT  28.032 103.572 28.056 103.656 ;
    END
  END a_d[296]
  PIN a_d[297]
    DIRECTION INPUT ;
    USE SIGNAL ;
    PORT
      LAYER M5 ;
        RECT  28.08 103.572 28.104 103.656 ;
    END
  END a_d[297]
  PIN a_d[298]
    DIRECTION INPUT ;
    USE SIGNAL ;
    PORT
      LAYER M5 ;
        RECT  28.128 103.572 28.152 103.656 ;
    END
  END a_d[298]
  PIN a_d[299]
    DIRECTION INPUT ;
    USE SIGNAL ;
    PORT
      LAYER M5 ;
        RECT  28.176 103.572 28.2 103.656 ;
    END
  END a_d[299]
  PIN a_d[29]
    DIRECTION INPUT ;
    USE SIGNAL ;
    PORT
      LAYER M5 ;
        RECT  15.216 103.572 15.24 103.656 ;
    END
  END a_d[29]
  PIN a_d[2]
    DIRECTION INPUT ;
    USE SIGNAL ;
    PORT
      LAYER M5 ;
        RECT  13.92 103.572 13.944 103.656 ;
    END
  END a_d[2]
  PIN a_d[300]
    DIRECTION INPUT ;
    USE SIGNAL ;
    PORT
      LAYER M5 ;
        RECT  28.224 103.572 28.248 103.656 ;
    END
  END a_d[300]
  PIN a_d[301]
    DIRECTION INPUT ;
    USE SIGNAL ;
    PORT
      LAYER M5 ;
        RECT  28.272 103.572 28.296 103.656 ;
    END
  END a_d[301]
  PIN a_d[302]
    DIRECTION INPUT ;
    USE SIGNAL ;
    PORT
      LAYER M5 ;
        RECT  28.32 103.572 28.344 103.656 ;
    END
  END a_d[302]
  PIN a_d[303]
    DIRECTION INPUT ;
    USE SIGNAL ;
    PORT
      LAYER M5 ;
        RECT  28.368 103.572 28.392 103.656 ;
    END
  END a_d[303]
  PIN a_d[304]
    DIRECTION INPUT ;
    USE SIGNAL ;
    PORT
      LAYER M5 ;
        RECT  28.416 103.572 28.44 103.656 ;
    END
  END a_d[304]
  PIN a_d[305]
    DIRECTION INPUT ;
    USE SIGNAL ;
    PORT
      LAYER M5 ;
        RECT  28.464 103.572 28.488 103.656 ;
    END
  END a_d[305]
  PIN a_d[306]
    DIRECTION INPUT ;
    USE SIGNAL ;
    PORT
      LAYER M5 ;
        RECT  28.512 103.572 28.536 103.656 ;
    END
  END a_d[306]
  PIN a_d[307]
    DIRECTION INPUT ;
    USE SIGNAL ;
    PORT
      LAYER M5 ;
        RECT  28.56 103.572 28.584 103.656 ;
    END
  END a_d[307]
  PIN a_d[308]
    DIRECTION INPUT ;
    USE SIGNAL ;
    PORT
      LAYER M5 ;
        RECT  28.608 103.572 28.632 103.656 ;
    END
  END a_d[308]
  PIN a_d[309]
    DIRECTION INPUT ;
    USE SIGNAL ;
    PORT
      LAYER M5 ;
        RECT  28.656 103.572 28.68 103.656 ;
    END
  END a_d[309]
  PIN a_d[30]
    DIRECTION INPUT ;
    USE SIGNAL ;
    PORT
      LAYER M5 ;
        RECT  15.264 103.572 15.288 103.656 ;
    END
  END a_d[30]
  PIN a_d[310]
    DIRECTION INPUT ;
    USE SIGNAL ;
    PORT
      LAYER M5 ;
        RECT  28.704 103.572 28.728 103.656 ;
    END
  END a_d[310]
  PIN a_d[311]
    DIRECTION INPUT ;
    USE SIGNAL ;
    PORT
      LAYER M5 ;
        RECT  28.752 103.572 28.776 103.656 ;
    END
  END a_d[311]
  PIN a_d[312]
    DIRECTION INPUT ;
    USE SIGNAL ;
    PORT
      LAYER M5 ;
        RECT  28.8 103.572 28.824 103.656 ;
    END
  END a_d[312]
  PIN a_d[313]
    DIRECTION INPUT ;
    USE SIGNAL ;
    PORT
      LAYER M5 ;
        RECT  28.848 103.572 28.872 103.656 ;
    END
  END a_d[313]
  PIN a_d[314]
    DIRECTION INPUT ;
    USE SIGNAL ;
    PORT
      LAYER M5 ;
        RECT  28.896 103.572 28.92 103.656 ;
    END
  END a_d[314]
  PIN a_d[315]
    DIRECTION INPUT ;
    USE SIGNAL ;
    PORT
      LAYER M5 ;
        RECT  28.944 103.572 28.968 103.656 ;
    END
  END a_d[315]
  PIN a_d[316]
    DIRECTION INPUT ;
    USE SIGNAL ;
    PORT
      LAYER M5 ;
        RECT  28.992 103.572 29.016 103.656 ;
    END
  END a_d[316]
  PIN a_d[317]
    DIRECTION INPUT ;
    USE SIGNAL ;
    PORT
      LAYER M5 ;
        RECT  29.04 103.572 29.064 103.656 ;
    END
  END a_d[317]
  PIN a_d[318]
    DIRECTION INPUT ;
    USE SIGNAL ;
    PORT
      LAYER M5 ;
        RECT  29.088 103.572 29.112 103.656 ;
    END
  END a_d[318]
  PIN a_d[319]
    DIRECTION INPUT ;
    USE SIGNAL ;
    PORT
      LAYER M5 ;
        RECT  29.136 103.572 29.16 103.656 ;
    END
  END a_d[319]
  PIN a_d[31]
    DIRECTION INPUT ;
    USE SIGNAL ;
    PORT
      LAYER M5 ;
        RECT  15.312 103.572 15.336 103.656 ;
    END
  END a_d[31]
  PIN a_d[320]
    DIRECTION INPUT ;
    USE SIGNAL ;
    PORT
      LAYER M5 ;
        RECT  29.184 103.572 29.208 103.656 ;
    END
  END a_d[320]
  PIN a_d[321]
    DIRECTION INPUT ;
    USE SIGNAL ;
    PORT
      LAYER M5 ;
        RECT  29.232 103.572 29.256 103.656 ;
    END
  END a_d[321]
  PIN a_d[322]
    DIRECTION INPUT ;
    USE SIGNAL ;
    PORT
      LAYER M5 ;
        RECT  29.28 103.572 29.304 103.656 ;
    END
  END a_d[322]
  PIN a_d[323]
    DIRECTION INPUT ;
    USE SIGNAL ;
    PORT
      LAYER M5 ;
        RECT  29.328 103.572 29.352 103.656 ;
    END
  END a_d[323]
  PIN a_d[324]
    DIRECTION INPUT ;
    USE SIGNAL ;
    PORT
      LAYER M5 ;
        RECT  29.376 103.572 29.4 103.656 ;
    END
  END a_d[324]
  PIN a_d[325]
    DIRECTION INPUT ;
    USE SIGNAL ;
    PORT
      LAYER M5 ;
        RECT  29.424 103.572 29.448 103.656 ;
    END
  END a_d[325]
  PIN a_d[326]
    DIRECTION INPUT ;
    USE SIGNAL ;
    PORT
      LAYER M5 ;
        RECT  29.472 103.572 29.496 103.656 ;
    END
  END a_d[326]
  PIN a_d[327]
    DIRECTION INPUT ;
    USE SIGNAL ;
    PORT
      LAYER M5 ;
        RECT  29.52 103.572 29.544 103.656 ;
    END
  END a_d[327]
  PIN a_d[328]
    DIRECTION INPUT ;
    USE SIGNAL ;
    PORT
      LAYER M5 ;
        RECT  29.568 103.572 29.592 103.656 ;
    END
  END a_d[328]
  PIN a_d[329]
    DIRECTION INPUT ;
    USE SIGNAL ;
    PORT
      LAYER M5 ;
        RECT  29.616 103.572 29.64 103.656 ;
    END
  END a_d[329]
  PIN a_d[32]
    DIRECTION INPUT ;
    USE SIGNAL ;
    PORT
      LAYER M5 ;
        RECT  15.36 103.572 15.384 103.656 ;
    END
  END a_d[32]
  PIN a_d[330]
    DIRECTION INPUT ;
    USE SIGNAL ;
    PORT
      LAYER M5 ;
        RECT  29.664 103.572 29.688 103.656 ;
    END
  END a_d[330]
  PIN a_d[331]
    DIRECTION INPUT ;
    USE SIGNAL ;
    PORT
      LAYER M5 ;
        RECT  29.712 103.572 29.736 103.656 ;
    END
  END a_d[331]
  PIN a_d[332]
    DIRECTION INPUT ;
    USE SIGNAL ;
    PORT
      LAYER M5 ;
        RECT  29.76 103.572 29.784 103.656 ;
    END
  END a_d[332]
  PIN a_d[333]
    DIRECTION INPUT ;
    USE SIGNAL ;
    PORT
      LAYER M5 ;
        RECT  29.808 103.572 29.832 103.656 ;
    END
  END a_d[333]
  PIN a_d[334]
    DIRECTION INPUT ;
    USE SIGNAL ;
    PORT
      LAYER M5 ;
        RECT  29.856 103.572 29.88 103.656 ;
    END
  END a_d[334]
  PIN a_d[335]
    DIRECTION INPUT ;
    USE SIGNAL ;
    PORT
      LAYER M5 ;
        RECT  29.904 103.572 29.928 103.656 ;
    END
  END a_d[335]
  PIN a_d[336]
    DIRECTION INPUT ;
    USE SIGNAL ;
    PORT
      LAYER M5 ;
        RECT  29.952 103.572 29.976 103.656 ;
    END
  END a_d[336]
  PIN a_d[337]
    DIRECTION INPUT ;
    USE SIGNAL ;
    PORT
      LAYER M5 ;
        RECT  30 103.572 30.024 103.656 ;
    END
  END a_d[337]
  PIN a_d[338]
    DIRECTION INPUT ;
    USE SIGNAL ;
    PORT
      LAYER M5 ;
        RECT  30.048 103.572 30.072 103.656 ;
    END
  END a_d[338]
  PIN a_d[339]
    DIRECTION INPUT ;
    USE SIGNAL ;
    PORT
      LAYER M5 ;
        RECT  30.096 103.572 30.12 103.656 ;
    END
  END a_d[339]
  PIN a_d[33]
    DIRECTION INPUT ;
    USE SIGNAL ;
    PORT
      LAYER M5 ;
        RECT  15.408 103.572 15.432 103.656 ;
    END
  END a_d[33]
  PIN a_d[340]
    DIRECTION INPUT ;
    USE SIGNAL ;
    PORT
      LAYER M5 ;
        RECT  30.144 103.572 30.168 103.656 ;
    END
  END a_d[340]
  PIN a_d[341]
    DIRECTION INPUT ;
    USE SIGNAL ;
    PORT
      LAYER M5 ;
        RECT  30.192 103.572 30.216 103.656 ;
    END
  END a_d[341]
  PIN a_d[342]
    DIRECTION INPUT ;
    USE SIGNAL ;
    PORT
      LAYER M5 ;
        RECT  30.24 103.572 30.264 103.656 ;
    END
  END a_d[342]
  PIN a_d[343]
    DIRECTION INPUT ;
    USE SIGNAL ;
    PORT
      LAYER M5 ;
        RECT  30.288 103.572 30.312 103.656 ;
    END
  END a_d[343]
  PIN a_d[344]
    DIRECTION INPUT ;
    USE SIGNAL ;
    PORT
      LAYER M5 ;
        RECT  30.336 103.572 30.36 103.656 ;
    END
  END a_d[344]
  PIN a_d[345]
    DIRECTION INPUT ;
    USE SIGNAL ;
    PORT
      LAYER M5 ;
        RECT  30.384 103.572 30.408 103.656 ;
    END
  END a_d[345]
  PIN a_d[346]
    DIRECTION INPUT ;
    USE SIGNAL ;
    PORT
      LAYER M5 ;
        RECT  30.432 103.572 30.456 103.656 ;
    END
  END a_d[346]
  PIN a_d[347]
    DIRECTION INPUT ;
    USE SIGNAL ;
    PORT
      LAYER M5 ;
        RECT  30.48 103.572 30.504 103.656 ;
    END
  END a_d[347]
  PIN a_d[348]
    DIRECTION INPUT ;
    USE SIGNAL ;
    PORT
      LAYER M5 ;
        RECT  30.528 103.572 30.552 103.656 ;
    END
  END a_d[348]
  PIN a_d[349]
    DIRECTION INPUT ;
    USE SIGNAL ;
    PORT
      LAYER M5 ;
        RECT  30.576 103.572 30.6 103.656 ;
    END
  END a_d[349]
  PIN a_d[34]
    DIRECTION INPUT ;
    USE SIGNAL ;
    PORT
      LAYER M5 ;
        RECT  15.456 103.572 15.48 103.656 ;
    END
  END a_d[34]
  PIN a_d[350]
    DIRECTION INPUT ;
    USE SIGNAL ;
    PORT
      LAYER M5 ;
        RECT  30.624 103.572 30.648 103.656 ;
    END
  END a_d[350]
  PIN a_d[351]
    DIRECTION INPUT ;
    USE SIGNAL ;
    PORT
      LAYER M5 ;
        RECT  30.672 103.572 30.696 103.656 ;
    END
  END a_d[351]
  PIN a_d[352]
    DIRECTION INPUT ;
    USE SIGNAL ;
    PORT
      LAYER M5 ;
        RECT  30.72 103.572 30.744 103.656 ;
    END
  END a_d[352]
  PIN a_d[353]
    DIRECTION INPUT ;
    USE SIGNAL ;
    PORT
      LAYER M5 ;
        RECT  30.768 103.572 30.792 103.656 ;
    END
  END a_d[353]
  PIN a_d[354]
    DIRECTION INPUT ;
    USE SIGNAL ;
    PORT
      LAYER M5 ;
        RECT  30.816 103.572 30.84 103.656 ;
    END
  END a_d[354]
  PIN a_d[355]
    DIRECTION INPUT ;
    USE SIGNAL ;
    PORT
      LAYER M5 ;
        RECT  30.864 103.572 30.888 103.656 ;
    END
  END a_d[355]
  PIN a_d[356]
    DIRECTION INPUT ;
    USE SIGNAL ;
    PORT
      LAYER M5 ;
        RECT  30.912 103.572 30.936 103.656 ;
    END
  END a_d[356]
  PIN a_d[357]
    DIRECTION INPUT ;
    USE SIGNAL ;
    PORT
      LAYER M5 ;
        RECT  30.96 103.572 30.984 103.656 ;
    END
  END a_d[357]
  PIN a_d[358]
    DIRECTION INPUT ;
    USE SIGNAL ;
    PORT
      LAYER M5 ;
        RECT  31.008 103.572 31.032 103.656 ;
    END
  END a_d[358]
  PIN a_d[359]
    DIRECTION INPUT ;
    USE SIGNAL ;
    PORT
      LAYER M5 ;
        RECT  31.056 103.572 31.08 103.656 ;
    END
  END a_d[359]
  PIN a_d[35]
    DIRECTION INPUT ;
    USE SIGNAL ;
    PORT
      LAYER M5 ;
        RECT  15.504 103.572 15.528 103.656 ;
    END
  END a_d[35]
  PIN a_d[360]
    DIRECTION INPUT ;
    USE SIGNAL ;
    PORT
      LAYER M5 ;
        RECT  31.104 103.572 31.128 103.656 ;
    END
  END a_d[360]
  PIN a_d[361]
    DIRECTION INPUT ;
    USE SIGNAL ;
    PORT
      LAYER M5 ;
        RECT  31.152 103.572 31.176 103.656 ;
    END
  END a_d[361]
  PIN a_d[362]
    DIRECTION INPUT ;
    USE SIGNAL ;
    PORT
      LAYER M5 ;
        RECT  31.2 103.572 31.224 103.656 ;
    END
  END a_d[362]
  PIN a_d[363]
    DIRECTION INPUT ;
    USE SIGNAL ;
    PORT
      LAYER M5 ;
        RECT  31.248 103.572 31.272 103.656 ;
    END
  END a_d[363]
  PIN a_d[364]
    DIRECTION INPUT ;
    USE SIGNAL ;
    PORT
      LAYER M5 ;
        RECT  31.296 103.572 31.32 103.656 ;
    END
  END a_d[364]
  PIN a_d[365]
    DIRECTION INPUT ;
    USE SIGNAL ;
    PORT
      LAYER M5 ;
        RECT  31.344 103.572 31.368 103.656 ;
    END
  END a_d[365]
  PIN a_d[366]
    DIRECTION INPUT ;
    USE SIGNAL ;
    PORT
      LAYER M5 ;
        RECT  31.392 103.572 31.416 103.656 ;
    END
  END a_d[366]
  PIN a_d[367]
    DIRECTION INPUT ;
    USE SIGNAL ;
    PORT
      LAYER M5 ;
        RECT  31.44 103.572 31.464 103.656 ;
    END
  END a_d[367]
  PIN a_d[368]
    DIRECTION INPUT ;
    USE SIGNAL ;
    PORT
      LAYER M5 ;
        RECT  31.488 103.572 31.512 103.656 ;
    END
  END a_d[368]
  PIN a_d[369]
    DIRECTION INPUT ;
    USE SIGNAL ;
    PORT
      LAYER M5 ;
        RECT  31.536 103.572 31.56 103.656 ;
    END
  END a_d[369]
  PIN a_d[36]
    DIRECTION INPUT ;
    USE SIGNAL ;
    PORT
      LAYER M5 ;
        RECT  15.552 103.572 15.576 103.656 ;
    END
  END a_d[36]
  PIN a_d[370]
    DIRECTION INPUT ;
    USE SIGNAL ;
    PORT
      LAYER M5 ;
        RECT  31.584 103.572 31.608 103.656 ;
    END
  END a_d[370]
  PIN a_d[371]
    DIRECTION INPUT ;
    USE SIGNAL ;
    PORT
      LAYER M5 ;
        RECT  31.632 103.572 31.656 103.656 ;
    END
  END a_d[371]
  PIN a_d[372]
    DIRECTION INPUT ;
    USE SIGNAL ;
    PORT
      LAYER M5 ;
        RECT  31.68 103.572 31.704 103.656 ;
    END
  END a_d[372]
  PIN a_d[373]
    DIRECTION INPUT ;
    USE SIGNAL ;
    PORT
      LAYER M5 ;
        RECT  31.728 103.572 31.752 103.656 ;
    END
  END a_d[373]
  PIN a_d[374]
    DIRECTION INPUT ;
    USE SIGNAL ;
    PORT
      LAYER M5 ;
        RECT  31.776 103.572 31.8 103.656 ;
    END
  END a_d[374]
  PIN a_d[375]
    DIRECTION INPUT ;
    USE SIGNAL ;
    PORT
      LAYER M5 ;
        RECT  31.824 103.572 31.848 103.656 ;
    END
  END a_d[375]
  PIN a_d[376]
    DIRECTION INPUT ;
    USE SIGNAL ;
    PORT
      LAYER M5 ;
        RECT  31.872 103.572 31.896 103.656 ;
    END
  END a_d[376]
  PIN a_d[377]
    DIRECTION INPUT ;
    USE SIGNAL ;
    PORT
      LAYER M5 ;
        RECT  31.92 103.572 31.944 103.656 ;
    END
  END a_d[377]
  PIN a_d[378]
    DIRECTION INPUT ;
    USE SIGNAL ;
    PORT
      LAYER M5 ;
        RECT  31.968 103.572 31.992 103.656 ;
    END
  END a_d[378]
  PIN a_d[379]
    DIRECTION INPUT ;
    USE SIGNAL ;
    PORT
      LAYER M5 ;
        RECT  32.016 103.572 32.04 103.656 ;
    END
  END a_d[379]
  PIN a_d[37]
    DIRECTION INPUT ;
    USE SIGNAL ;
    PORT
      LAYER M5 ;
        RECT  15.6 103.572 15.624 103.656 ;
    END
  END a_d[37]
  PIN a_d[380]
    DIRECTION INPUT ;
    USE SIGNAL ;
    PORT
      LAYER M5 ;
        RECT  32.064 103.572 32.088 103.656 ;
    END
  END a_d[380]
  PIN a_d[381]
    DIRECTION INPUT ;
    USE SIGNAL ;
    PORT
      LAYER M5 ;
        RECT  32.112 103.572 32.136 103.656 ;
    END
  END a_d[381]
  PIN a_d[382]
    DIRECTION INPUT ;
    USE SIGNAL ;
    PORT
      LAYER M5 ;
        RECT  32.16 103.572 32.184 103.656 ;
    END
  END a_d[382]
  PIN a_d[383]
    DIRECTION INPUT ;
    USE SIGNAL ;
    PORT
      LAYER M5 ;
        RECT  32.208 103.572 32.232 103.656 ;
    END
  END a_d[383]
  PIN a_d[384]
    DIRECTION INPUT ;
    USE SIGNAL ;
    PORT
      LAYER M5 ;
        RECT  32.256 103.572 32.28 103.656 ;
    END
  END a_d[384]
  PIN a_d[385]
    DIRECTION INPUT ;
    USE SIGNAL ;
    PORT
      LAYER M5 ;
        RECT  32.304 103.572 32.328 103.656 ;
    END
  END a_d[385]
  PIN a_d[386]
    DIRECTION INPUT ;
    USE SIGNAL ;
    PORT
      LAYER M5 ;
        RECT  32.352 103.572 32.376 103.656 ;
    END
  END a_d[386]
  PIN a_d[387]
    DIRECTION INPUT ;
    USE SIGNAL ;
    PORT
      LAYER M5 ;
        RECT  32.4 103.572 32.424 103.656 ;
    END
  END a_d[387]
  PIN a_d[388]
    DIRECTION INPUT ;
    USE SIGNAL ;
    PORT
      LAYER M5 ;
        RECT  32.448 103.572 32.472 103.656 ;
    END
  END a_d[388]
  PIN a_d[389]
    DIRECTION INPUT ;
    USE SIGNAL ;
    PORT
      LAYER M5 ;
        RECT  32.496 103.572 32.52 103.656 ;
    END
  END a_d[389]
  PIN a_d[38]
    DIRECTION INPUT ;
    USE SIGNAL ;
    PORT
      LAYER M5 ;
        RECT  15.648 103.572 15.672 103.656 ;
    END
  END a_d[38]
  PIN a_d[390]
    DIRECTION INPUT ;
    USE SIGNAL ;
    PORT
      LAYER M5 ;
        RECT  32.544 103.572 32.568 103.656 ;
    END
  END a_d[390]
  PIN a_d[391]
    DIRECTION INPUT ;
    USE SIGNAL ;
    PORT
      LAYER M5 ;
        RECT  32.592 103.572 32.616 103.656 ;
    END
  END a_d[391]
  PIN a_d[392]
    DIRECTION INPUT ;
    USE SIGNAL ;
    PORT
      LAYER M5 ;
        RECT  32.64 103.572 32.664 103.656 ;
    END
  END a_d[392]
  PIN a_d[393]
    DIRECTION INPUT ;
    USE SIGNAL ;
    PORT
      LAYER M5 ;
        RECT  32.688 103.572 32.712 103.656 ;
    END
  END a_d[393]
  PIN a_d[394]
    DIRECTION INPUT ;
    USE SIGNAL ;
    PORT
      LAYER M5 ;
        RECT  32.736 103.572 32.76 103.656 ;
    END
  END a_d[394]
  PIN a_d[395]
    DIRECTION INPUT ;
    USE SIGNAL ;
    PORT
      LAYER M5 ;
        RECT  32.784 103.572 32.808 103.656 ;
    END
  END a_d[395]
  PIN a_d[396]
    DIRECTION INPUT ;
    USE SIGNAL ;
    PORT
      LAYER M5 ;
        RECT  32.832 103.572 32.856 103.656 ;
    END
  END a_d[396]
  PIN a_d[397]
    DIRECTION INPUT ;
    USE SIGNAL ;
    PORT
      LAYER M5 ;
        RECT  32.88 103.572 32.904 103.656 ;
    END
  END a_d[397]
  PIN a_d[398]
    DIRECTION INPUT ;
    USE SIGNAL ;
    PORT
      LAYER M5 ;
        RECT  32.928 103.572 32.952 103.656 ;
    END
  END a_d[398]
  PIN a_d[399]
    DIRECTION INPUT ;
    USE SIGNAL ;
    PORT
      LAYER M5 ;
        RECT  32.976 103.572 33 103.656 ;
    END
  END a_d[399]
  PIN a_d[39]
    DIRECTION INPUT ;
    USE SIGNAL ;
    PORT
      LAYER M5 ;
        RECT  15.696 103.572 15.72 103.656 ;
    END
  END a_d[39]
  PIN a_d[3]
    DIRECTION INPUT ;
    USE SIGNAL ;
    PORT
      LAYER M5 ;
        RECT  13.968 103.572 13.992 103.656 ;
    END
  END a_d[3]
  PIN a_d[400]
    DIRECTION INPUT ;
    USE SIGNAL ;
    PORT
      LAYER M5 ;
        RECT  33.024 103.572 33.048 103.656 ;
    END
  END a_d[400]
  PIN a_d[401]
    DIRECTION INPUT ;
    USE SIGNAL ;
    PORT
      LAYER M5 ;
        RECT  33.072 103.572 33.096 103.656 ;
    END
  END a_d[401]
  PIN a_d[402]
    DIRECTION INPUT ;
    USE SIGNAL ;
    PORT
      LAYER M5 ;
        RECT  33.12 103.572 33.144 103.656 ;
    END
  END a_d[402]
  PIN a_d[403]
    DIRECTION INPUT ;
    USE SIGNAL ;
    PORT
      LAYER M5 ;
        RECT  33.168 103.572 33.192 103.656 ;
    END
  END a_d[403]
  PIN a_d[404]
    DIRECTION INPUT ;
    USE SIGNAL ;
    PORT
      LAYER M5 ;
        RECT  33.216 103.572 33.24 103.656 ;
    END
  END a_d[404]
  PIN a_d[405]
    DIRECTION INPUT ;
    USE SIGNAL ;
    PORT
      LAYER M5 ;
        RECT  33.264 103.572 33.288 103.656 ;
    END
  END a_d[405]
  PIN a_d[406]
    DIRECTION INPUT ;
    USE SIGNAL ;
    PORT
      LAYER M5 ;
        RECT  33.312 103.572 33.336 103.656 ;
    END
  END a_d[406]
  PIN a_d[407]
    DIRECTION INPUT ;
    USE SIGNAL ;
    PORT
      LAYER M5 ;
        RECT  33.36 103.572 33.384 103.656 ;
    END
  END a_d[407]
  PIN a_d[408]
    DIRECTION INPUT ;
    USE SIGNAL ;
    PORT
      LAYER M5 ;
        RECT  33.408 103.572 33.432 103.656 ;
    END
  END a_d[408]
  PIN a_d[409]
    DIRECTION INPUT ;
    USE SIGNAL ;
    PORT
      LAYER M5 ;
        RECT  33.456 103.572 33.48 103.656 ;
    END
  END a_d[409]
  PIN a_d[40]
    DIRECTION INPUT ;
    USE SIGNAL ;
    PORT
      LAYER M5 ;
        RECT  15.744 103.572 15.768 103.656 ;
    END
  END a_d[40]
  PIN a_d[410]
    DIRECTION INPUT ;
    USE SIGNAL ;
    PORT
      LAYER M5 ;
        RECT  33.504 103.572 33.528 103.656 ;
    END
  END a_d[410]
  PIN a_d[411]
    DIRECTION INPUT ;
    USE SIGNAL ;
    PORT
      LAYER M5 ;
        RECT  33.552 103.572 33.576 103.656 ;
    END
  END a_d[411]
  PIN a_d[412]
    DIRECTION INPUT ;
    USE SIGNAL ;
    PORT
      LAYER M5 ;
        RECT  33.6 103.572 33.624 103.656 ;
    END
  END a_d[412]
  PIN a_d[413]
    DIRECTION INPUT ;
    USE SIGNAL ;
    PORT
      LAYER M5 ;
        RECT  33.648 103.572 33.672 103.656 ;
    END
  END a_d[413]
  PIN a_d[414]
    DIRECTION INPUT ;
    USE SIGNAL ;
    PORT
      LAYER M5 ;
        RECT  33.696 103.572 33.72 103.656 ;
    END
  END a_d[414]
  PIN a_d[415]
    DIRECTION INPUT ;
    USE SIGNAL ;
    PORT
      LAYER M5 ;
        RECT  33.744 103.572 33.768 103.656 ;
    END
  END a_d[415]
  PIN a_d[416]
    DIRECTION INPUT ;
    USE SIGNAL ;
    PORT
      LAYER M5 ;
        RECT  33.792 103.572 33.816 103.656 ;
    END
  END a_d[416]
  PIN a_d[417]
    DIRECTION INPUT ;
    USE SIGNAL ;
    PORT
      LAYER M5 ;
        RECT  33.84 103.572 33.864 103.656 ;
    END
  END a_d[417]
  PIN a_d[418]
    DIRECTION INPUT ;
    USE SIGNAL ;
    PORT
      LAYER M5 ;
        RECT  33.888 103.572 33.912 103.656 ;
    END
  END a_d[418]
  PIN a_d[419]
    DIRECTION INPUT ;
    USE SIGNAL ;
    PORT
      LAYER M5 ;
        RECT  33.936 103.572 33.96 103.656 ;
    END
  END a_d[419]
  PIN a_d[41]
    DIRECTION INPUT ;
    USE SIGNAL ;
    PORT
      LAYER M5 ;
        RECT  15.792 103.572 15.816 103.656 ;
    END
  END a_d[41]
  PIN a_d[420]
    DIRECTION INPUT ;
    USE SIGNAL ;
    PORT
      LAYER M5 ;
        RECT  33.984 103.572 34.008 103.656 ;
    END
  END a_d[420]
  PIN a_d[421]
    DIRECTION INPUT ;
    USE SIGNAL ;
    PORT
      LAYER M5 ;
        RECT  34.032 103.572 34.056 103.656 ;
    END
  END a_d[421]
  PIN a_d[422]
    DIRECTION INPUT ;
    USE SIGNAL ;
    PORT
      LAYER M5 ;
        RECT  34.08 103.572 34.104 103.656 ;
    END
  END a_d[422]
  PIN a_d[423]
    DIRECTION INPUT ;
    USE SIGNAL ;
    PORT
      LAYER M5 ;
        RECT  34.128 103.572 34.152 103.656 ;
    END
  END a_d[423]
  PIN a_d[424]
    DIRECTION INPUT ;
    USE SIGNAL ;
    PORT
      LAYER M5 ;
        RECT  34.176 103.572 34.2 103.656 ;
    END
  END a_d[424]
  PIN a_d[425]
    DIRECTION INPUT ;
    USE SIGNAL ;
    PORT
      LAYER M5 ;
        RECT  34.224 103.572 34.248 103.656 ;
    END
  END a_d[425]
  PIN a_d[426]
    DIRECTION INPUT ;
    USE SIGNAL ;
    PORT
      LAYER M5 ;
        RECT  34.272 103.572 34.296 103.656 ;
    END
  END a_d[426]
  PIN a_d[427]
    DIRECTION INPUT ;
    USE SIGNAL ;
    PORT
      LAYER M5 ;
        RECT  34.32 103.572 34.344 103.656 ;
    END
  END a_d[427]
  PIN a_d[428]
    DIRECTION INPUT ;
    USE SIGNAL ;
    PORT
      LAYER M5 ;
        RECT  34.368 103.572 34.392 103.656 ;
    END
  END a_d[428]
  PIN a_d[429]
    DIRECTION INPUT ;
    USE SIGNAL ;
    PORT
      LAYER M5 ;
        RECT  34.416 103.572 34.44 103.656 ;
    END
  END a_d[429]
  PIN a_d[42]
    DIRECTION INPUT ;
    USE SIGNAL ;
    PORT
      LAYER M5 ;
        RECT  15.84 103.572 15.864 103.656 ;
    END
  END a_d[42]
  PIN a_d[430]
    DIRECTION INPUT ;
    USE SIGNAL ;
    PORT
      LAYER M5 ;
        RECT  34.464 103.572 34.488 103.656 ;
    END
  END a_d[430]
  PIN a_d[431]
    DIRECTION INPUT ;
    USE SIGNAL ;
    PORT
      LAYER M5 ;
        RECT  34.512 103.572 34.536 103.656 ;
    END
  END a_d[431]
  PIN a_d[432]
    DIRECTION INPUT ;
    USE SIGNAL ;
    PORT
      LAYER M5 ;
        RECT  34.56 103.572 34.584 103.656 ;
    END
  END a_d[432]
  PIN a_d[433]
    DIRECTION INPUT ;
    USE SIGNAL ;
    PORT
      LAYER M5 ;
        RECT  34.608 103.572 34.632 103.656 ;
    END
  END a_d[433]
  PIN a_d[434]
    DIRECTION INPUT ;
    USE SIGNAL ;
    PORT
      LAYER M5 ;
        RECT  34.656 103.572 34.68 103.656 ;
    END
  END a_d[434]
  PIN a_d[435]
    DIRECTION INPUT ;
    USE SIGNAL ;
    PORT
      LAYER M5 ;
        RECT  34.704 103.572 34.728 103.656 ;
    END
  END a_d[435]
  PIN a_d[436]
    DIRECTION INPUT ;
    USE SIGNAL ;
    PORT
      LAYER M5 ;
        RECT  34.752 103.572 34.776 103.656 ;
    END
  END a_d[436]
  PIN a_d[437]
    DIRECTION INPUT ;
    USE SIGNAL ;
    PORT
      LAYER M5 ;
        RECT  34.8 103.572 34.824 103.656 ;
    END
  END a_d[437]
  PIN a_d[438]
    DIRECTION INPUT ;
    USE SIGNAL ;
    PORT
      LAYER M5 ;
        RECT  34.848 103.572 34.872 103.656 ;
    END
  END a_d[438]
  PIN a_d[439]
    DIRECTION INPUT ;
    USE SIGNAL ;
    PORT
      LAYER M5 ;
        RECT  34.896 103.572 34.92 103.656 ;
    END
  END a_d[439]
  PIN a_d[43]
    DIRECTION INPUT ;
    USE SIGNAL ;
    PORT
      LAYER M5 ;
        RECT  15.888 103.572 15.912 103.656 ;
    END
  END a_d[43]
  PIN a_d[440]
    DIRECTION INPUT ;
    USE SIGNAL ;
    PORT
      LAYER M5 ;
        RECT  34.944 103.572 34.968 103.656 ;
    END
  END a_d[440]
  PIN a_d[441]
    DIRECTION INPUT ;
    USE SIGNAL ;
    PORT
      LAYER M5 ;
        RECT  34.992 103.572 35.016 103.656 ;
    END
  END a_d[441]
  PIN a_d[442]
    DIRECTION INPUT ;
    USE SIGNAL ;
    PORT
      LAYER M5 ;
        RECT  35.04 103.572 35.064 103.656 ;
    END
  END a_d[442]
  PIN a_d[443]
    DIRECTION INPUT ;
    USE SIGNAL ;
    PORT
      LAYER M5 ;
        RECT  35.088 103.572 35.112 103.656 ;
    END
  END a_d[443]
  PIN a_d[444]
    DIRECTION INPUT ;
    USE SIGNAL ;
    PORT
      LAYER M5 ;
        RECT  35.136 103.572 35.16 103.656 ;
    END
  END a_d[444]
  PIN a_d[445]
    DIRECTION INPUT ;
    USE SIGNAL ;
    PORT
      LAYER M5 ;
        RECT  35.184 103.572 35.208 103.656 ;
    END
  END a_d[445]
  PIN a_d[446]
    DIRECTION INPUT ;
    USE SIGNAL ;
    PORT
      LAYER M5 ;
        RECT  35.232 103.572 35.256 103.656 ;
    END
  END a_d[446]
  PIN a_d[447]
    DIRECTION INPUT ;
    USE SIGNAL ;
    PORT
      LAYER M5 ;
        RECT  35.28 103.572 35.304 103.656 ;
    END
  END a_d[447]
  PIN a_d[448]
    DIRECTION INPUT ;
    USE SIGNAL ;
    PORT
      LAYER M5 ;
        RECT  35.328 103.572 35.352 103.656 ;
    END
  END a_d[448]
  PIN a_d[449]
    DIRECTION INPUT ;
    USE SIGNAL ;
    PORT
      LAYER M5 ;
        RECT  35.376 103.572 35.4 103.656 ;
    END
  END a_d[449]
  PIN a_d[44]
    DIRECTION INPUT ;
    USE SIGNAL ;
    PORT
      LAYER M5 ;
        RECT  15.936 103.572 15.96 103.656 ;
    END
  END a_d[44]
  PIN a_d[450]
    DIRECTION INPUT ;
    USE SIGNAL ;
    PORT
      LAYER M5 ;
        RECT  35.424 103.572 35.448 103.656 ;
    END
  END a_d[450]
  PIN a_d[451]
    DIRECTION INPUT ;
    USE SIGNAL ;
    PORT
      LAYER M5 ;
        RECT  35.472 103.572 35.496 103.656 ;
    END
  END a_d[451]
  PIN a_d[452]
    DIRECTION INPUT ;
    USE SIGNAL ;
    PORT
      LAYER M5 ;
        RECT  35.52 103.572 35.544 103.656 ;
    END
  END a_d[452]
  PIN a_d[453]
    DIRECTION INPUT ;
    USE SIGNAL ;
    PORT
      LAYER M5 ;
        RECT  35.568 103.572 35.592 103.656 ;
    END
  END a_d[453]
  PIN a_d[454]
    DIRECTION INPUT ;
    USE SIGNAL ;
    PORT
      LAYER M5 ;
        RECT  35.616 103.572 35.64 103.656 ;
    END
  END a_d[454]
  PIN a_d[455]
    DIRECTION INPUT ;
    USE SIGNAL ;
    PORT
      LAYER M5 ;
        RECT  35.664 103.572 35.688 103.656 ;
    END
  END a_d[455]
  PIN a_d[456]
    DIRECTION INPUT ;
    USE SIGNAL ;
    PORT
      LAYER M5 ;
        RECT  35.712 103.572 35.736 103.656 ;
    END
  END a_d[456]
  PIN a_d[457]
    DIRECTION INPUT ;
    USE SIGNAL ;
    PORT
      LAYER M5 ;
        RECT  35.76 103.572 35.784 103.656 ;
    END
  END a_d[457]
  PIN a_d[458]
    DIRECTION INPUT ;
    USE SIGNAL ;
    PORT
      LAYER M5 ;
        RECT  35.808 103.572 35.832 103.656 ;
    END
  END a_d[458]
  PIN a_d[459]
    DIRECTION INPUT ;
    USE SIGNAL ;
    PORT
      LAYER M5 ;
        RECT  35.856 103.572 35.88 103.656 ;
    END
  END a_d[459]
  PIN a_d[45]
    DIRECTION INPUT ;
    USE SIGNAL ;
    PORT
      LAYER M5 ;
        RECT  15.984 103.572 16.008 103.656 ;
    END
  END a_d[45]
  PIN a_d[460]
    DIRECTION INPUT ;
    USE SIGNAL ;
    PORT
      LAYER M5 ;
        RECT  35.904 103.572 35.928 103.656 ;
    END
  END a_d[460]
  PIN a_d[461]
    DIRECTION INPUT ;
    USE SIGNAL ;
    PORT
      LAYER M5 ;
        RECT  35.952 103.572 35.976 103.656 ;
    END
  END a_d[461]
  PIN a_d[462]
    DIRECTION INPUT ;
    USE SIGNAL ;
    PORT
      LAYER M5 ;
        RECT  36 103.572 36.024 103.656 ;
    END
  END a_d[462]
  PIN a_d[463]
    DIRECTION INPUT ;
    USE SIGNAL ;
    PORT
      LAYER M5 ;
        RECT  36.048 103.572 36.072 103.656 ;
    END
  END a_d[463]
  PIN a_d[464]
    DIRECTION INPUT ;
    USE SIGNAL ;
    PORT
      LAYER M5 ;
        RECT  36.096 103.572 36.12 103.656 ;
    END
  END a_d[464]
  PIN a_d[465]
    DIRECTION INPUT ;
    USE SIGNAL ;
    PORT
      LAYER M5 ;
        RECT  36.144 103.572 36.168 103.656 ;
    END
  END a_d[465]
  PIN a_d[466]
    DIRECTION INPUT ;
    USE SIGNAL ;
    PORT
      LAYER M5 ;
        RECT  36.192 103.572 36.216 103.656 ;
    END
  END a_d[466]
  PIN a_d[467]
    DIRECTION INPUT ;
    USE SIGNAL ;
    PORT
      LAYER M5 ;
        RECT  36.24 103.572 36.264 103.656 ;
    END
  END a_d[467]
  PIN a_d[468]
    DIRECTION INPUT ;
    USE SIGNAL ;
    PORT
      LAYER M5 ;
        RECT  36.288 103.572 36.312 103.656 ;
    END
  END a_d[468]
  PIN a_d[469]
    DIRECTION INPUT ;
    USE SIGNAL ;
    PORT
      LAYER M5 ;
        RECT  36.336 103.572 36.36 103.656 ;
    END
  END a_d[469]
  PIN a_d[46]
    DIRECTION INPUT ;
    USE SIGNAL ;
    PORT
      LAYER M5 ;
        RECT  16.032 103.572 16.056 103.656 ;
    END
  END a_d[46]
  PIN a_d[470]
    DIRECTION INPUT ;
    USE SIGNAL ;
    PORT
      LAYER M5 ;
        RECT  36.384 103.572 36.408 103.656 ;
    END
  END a_d[470]
  PIN a_d[471]
    DIRECTION INPUT ;
    USE SIGNAL ;
    PORT
      LAYER M5 ;
        RECT  36.432 103.572 36.456 103.656 ;
    END
  END a_d[471]
  PIN a_d[472]
    DIRECTION INPUT ;
    USE SIGNAL ;
    PORT
      LAYER M5 ;
        RECT  36.48 103.572 36.504 103.656 ;
    END
  END a_d[472]
  PIN a_d[473]
    DIRECTION INPUT ;
    USE SIGNAL ;
    PORT
      LAYER M5 ;
        RECT  36.528 103.572 36.552 103.656 ;
    END
  END a_d[473]
  PIN a_d[474]
    DIRECTION INPUT ;
    USE SIGNAL ;
    PORT
      LAYER M5 ;
        RECT  36.576 103.572 36.6 103.656 ;
    END
  END a_d[474]
  PIN a_d[475]
    DIRECTION INPUT ;
    USE SIGNAL ;
    PORT
      LAYER M5 ;
        RECT  36.624 103.572 36.648 103.656 ;
    END
  END a_d[475]
  PIN a_d[476]
    DIRECTION INPUT ;
    USE SIGNAL ;
    PORT
      LAYER M5 ;
        RECT  36.672 103.572 36.696 103.656 ;
    END
  END a_d[476]
  PIN a_d[477]
    DIRECTION INPUT ;
    USE SIGNAL ;
    PORT
      LAYER M5 ;
        RECT  36.72 103.572 36.744 103.656 ;
    END
  END a_d[477]
  PIN a_d[478]
    DIRECTION INPUT ;
    USE SIGNAL ;
    PORT
      LAYER M5 ;
        RECT  36.768 103.572 36.792 103.656 ;
    END
  END a_d[478]
  PIN a_d[479]
    DIRECTION INPUT ;
    USE SIGNAL ;
    PORT
      LAYER M5 ;
        RECT  36.816 103.572 36.84 103.656 ;
    END
  END a_d[479]
  PIN a_d[47]
    DIRECTION INPUT ;
    USE SIGNAL ;
    PORT
      LAYER M5 ;
        RECT  16.08 103.572 16.104 103.656 ;
    END
  END a_d[47]
  PIN a_d[480]
    DIRECTION INPUT ;
    USE SIGNAL ;
    PORT
      LAYER M5 ;
        RECT  36.864 103.572 36.888 103.656 ;
    END
  END a_d[480]
  PIN a_d[481]
    DIRECTION INPUT ;
    USE SIGNAL ;
    PORT
      LAYER M5 ;
        RECT  36.912 103.572 36.936 103.656 ;
    END
  END a_d[481]
  PIN a_d[482]
    DIRECTION INPUT ;
    USE SIGNAL ;
    PORT
      LAYER M5 ;
        RECT  36.96 103.572 36.984 103.656 ;
    END
  END a_d[482]
  PIN a_d[483]
    DIRECTION INPUT ;
    USE SIGNAL ;
    PORT
      LAYER M5 ;
        RECT  37.008 103.572 37.032 103.656 ;
    END
  END a_d[483]
  PIN a_d[484]
    DIRECTION INPUT ;
    USE SIGNAL ;
    PORT
      LAYER M5 ;
        RECT  37.056 103.572 37.08 103.656 ;
    END
  END a_d[484]
  PIN a_d[485]
    DIRECTION INPUT ;
    USE SIGNAL ;
    PORT
      LAYER M5 ;
        RECT  37.104 103.572 37.128 103.656 ;
    END
  END a_d[485]
  PIN a_d[486]
    DIRECTION INPUT ;
    USE SIGNAL ;
    PORT
      LAYER M5 ;
        RECT  37.152 103.572 37.176 103.656 ;
    END
  END a_d[486]
  PIN a_d[487]
    DIRECTION INPUT ;
    USE SIGNAL ;
    PORT
      LAYER M5 ;
        RECT  37.2 103.572 37.224 103.656 ;
    END
  END a_d[487]
  PIN a_d[488]
    DIRECTION INPUT ;
    USE SIGNAL ;
    PORT
      LAYER M5 ;
        RECT  37.248 103.572 37.272 103.656 ;
    END
  END a_d[488]
  PIN a_d[489]
    DIRECTION INPUT ;
    USE SIGNAL ;
    PORT
      LAYER M5 ;
        RECT  37.296 103.572 37.32 103.656 ;
    END
  END a_d[489]
  PIN a_d[48]
    DIRECTION INPUT ;
    USE SIGNAL ;
    PORT
      LAYER M5 ;
        RECT  16.128 103.572 16.152 103.656 ;
    END
  END a_d[48]
  PIN a_d[490]
    DIRECTION INPUT ;
    USE SIGNAL ;
    PORT
      LAYER M5 ;
        RECT  37.344 103.572 37.368 103.656 ;
    END
  END a_d[490]
  PIN a_d[491]
    DIRECTION INPUT ;
    USE SIGNAL ;
    PORT
      LAYER M5 ;
        RECT  37.392 103.572 37.416 103.656 ;
    END
  END a_d[491]
  PIN a_d[492]
    DIRECTION INPUT ;
    USE SIGNAL ;
    PORT
      LAYER M5 ;
        RECT  37.44 103.572 37.464 103.656 ;
    END
  END a_d[492]
  PIN a_d[493]
    DIRECTION INPUT ;
    USE SIGNAL ;
    PORT
      LAYER M5 ;
        RECT  37.488 103.572 37.512 103.656 ;
    END
  END a_d[493]
  PIN a_d[494]
    DIRECTION INPUT ;
    USE SIGNAL ;
    PORT
      LAYER M5 ;
        RECT  37.536 103.572 37.56 103.656 ;
    END
  END a_d[494]
  PIN a_d[495]
    DIRECTION INPUT ;
    USE SIGNAL ;
    PORT
      LAYER M5 ;
        RECT  37.584 103.572 37.608 103.656 ;
    END
  END a_d[495]
  PIN a_d[496]
    DIRECTION INPUT ;
    USE SIGNAL ;
    PORT
      LAYER M5 ;
        RECT  37.632 103.572 37.656 103.656 ;
    END
  END a_d[496]
  PIN a_d[497]
    DIRECTION INPUT ;
    USE SIGNAL ;
    PORT
      LAYER M5 ;
        RECT  37.68 103.572 37.704 103.656 ;
    END
  END a_d[497]
  PIN a_d[498]
    DIRECTION INPUT ;
    USE SIGNAL ;
    PORT
      LAYER M5 ;
        RECT  37.728 103.572 37.752 103.656 ;
    END
  END a_d[498]
  PIN a_d[499]
    DIRECTION INPUT ;
    USE SIGNAL ;
    PORT
      LAYER M5 ;
        RECT  37.776 103.572 37.8 103.656 ;
    END
  END a_d[499]
  PIN a_d[49]
    DIRECTION INPUT ;
    USE SIGNAL ;
    PORT
      LAYER M5 ;
        RECT  16.176 103.572 16.2 103.656 ;
    END
  END a_d[49]
  PIN a_d[4]
    DIRECTION INPUT ;
    USE SIGNAL ;
    PORT
      LAYER M5 ;
        RECT  14.016 103.572 14.04 103.656 ;
    END
  END a_d[4]
  PIN a_d[500]
    DIRECTION INPUT ;
    USE SIGNAL ;
    PORT
      LAYER M5 ;
        RECT  37.824 103.572 37.848 103.656 ;
    END
  END a_d[500]
  PIN a_d[501]
    DIRECTION INPUT ;
    USE SIGNAL ;
    PORT
      LAYER M5 ;
        RECT  37.872 103.572 37.896 103.656 ;
    END
  END a_d[501]
  PIN a_d[502]
    DIRECTION INPUT ;
    USE SIGNAL ;
    PORT
      LAYER M5 ;
        RECT  37.92 103.572 37.944 103.656 ;
    END
  END a_d[502]
  PIN a_d[503]
    DIRECTION INPUT ;
    USE SIGNAL ;
    PORT
      LAYER M5 ;
        RECT  37.968 103.572 37.992 103.656 ;
    END
  END a_d[503]
  PIN a_d[504]
    DIRECTION INPUT ;
    USE SIGNAL ;
    PORT
      LAYER M5 ;
        RECT  38.016 103.572 38.04 103.656 ;
    END
  END a_d[504]
  PIN a_d[505]
    DIRECTION INPUT ;
    USE SIGNAL ;
    PORT
      LAYER M5 ;
        RECT  38.064 103.572 38.088 103.656 ;
    END
  END a_d[505]
  PIN a_d[506]
    DIRECTION INPUT ;
    USE SIGNAL ;
    PORT
      LAYER M5 ;
        RECT  38.112 103.572 38.136 103.656 ;
    END
  END a_d[506]
  PIN a_d[507]
    DIRECTION INPUT ;
    USE SIGNAL ;
    PORT
      LAYER M5 ;
        RECT  38.16 103.572 38.184 103.656 ;
    END
  END a_d[507]
  PIN a_d[50]
    DIRECTION INPUT ;
    USE SIGNAL ;
    PORT
      LAYER M5 ;
        RECT  16.224 103.572 16.248 103.656 ;
    END
  END a_d[50]
  PIN a_d[51]
    DIRECTION INPUT ;
    USE SIGNAL ;
    PORT
      LAYER M5 ;
        RECT  16.272 103.572 16.296 103.656 ;
    END
  END a_d[51]
  PIN a_d[52]
    DIRECTION INPUT ;
    USE SIGNAL ;
    PORT
      LAYER M5 ;
        RECT  16.32 103.572 16.344 103.656 ;
    END
  END a_d[52]
  PIN a_d[53]
    DIRECTION INPUT ;
    USE SIGNAL ;
    PORT
      LAYER M5 ;
        RECT  16.368 103.572 16.392 103.656 ;
    END
  END a_d[53]
  PIN a_d[54]
    DIRECTION INPUT ;
    USE SIGNAL ;
    PORT
      LAYER M5 ;
        RECT  16.416 103.572 16.44 103.656 ;
    END
  END a_d[54]
  PIN a_d[55]
    DIRECTION INPUT ;
    USE SIGNAL ;
    PORT
      LAYER M5 ;
        RECT  16.464 103.572 16.488 103.656 ;
    END
  END a_d[55]
  PIN a_d[56]
    DIRECTION INPUT ;
    USE SIGNAL ;
    PORT
      LAYER M5 ;
        RECT  16.512 103.572 16.536 103.656 ;
    END
  END a_d[56]
  PIN a_d[57]
    DIRECTION INPUT ;
    USE SIGNAL ;
    PORT
      LAYER M5 ;
        RECT  16.56 103.572 16.584 103.656 ;
    END
  END a_d[57]
  PIN a_d[58]
    DIRECTION INPUT ;
    USE SIGNAL ;
    PORT
      LAYER M5 ;
        RECT  16.608 103.572 16.632 103.656 ;
    END
  END a_d[58]
  PIN a_d[59]
    DIRECTION INPUT ;
    USE SIGNAL ;
    PORT
      LAYER M5 ;
        RECT  16.656 103.572 16.68 103.656 ;
    END
  END a_d[59]
  PIN a_d[5]
    DIRECTION INPUT ;
    USE SIGNAL ;
    PORT
      LAYER M5 ;
        RECT  14.064 103.572 14.088 103.656 ;
    END
  END a_d[5]
  PIN a_d[60]
    DIRECTION INPUT ;
    USE SIGNAL ;
    PORT
      LAYER M5 ;
        RECT  16.704 103.572 16.728 103.656 ;
    END
  END a_d[60]
  PIN a_d[61]
    DIRECTION INPUT ;
    USE SIGNAL ;
    PORT
      LAYER M5 ;
        RECT  16.752 103.572 16.776 103.656 ;
    END
  END a_d[61]
  PIN a_d[62]
    DIRECTION INPUT ;
    USE SIGNAL ;
    PORT
      LAYER M5 ;
        RECT  16.8 103.572 16.824 103.656 ;
    END
  END a_d[62]
  PIN a_d[63]
    DIRECTION INPUT ;
    USE SIGNAL ;
    PORT
      LAYER M5 ;
        RECT  16.848 103.572 16.872 103.656 ;
    END
  END a_d[63]
  PIN a_d[64]
    DIRECTION INPUT ;
    USE SIGNAL ;
    PORT
      LAYER M5 ;
        RECT  16.896 103.572 16.92 103.656 ;
    END
  END a_d[64]
  PIN a_d[65]
    DIRECTION INPUT ;
    USE SIGNAL ;
    PORT
      LAYER M5 ;
        RECT  16.944 103.572 16.968 103.656 ;
    END
  END a_d[65]
  PIN a_d[66]
    DIRECTION INPUT ;
    USE SIGNAL ;
    PORT
      LAYER M5 ;
        RECT  16.992 103.572 17.016 103.656 ;
    END
  END a_d[66]
  PIN a_d[67]
    DIRECTION INPUT ;
    USE SIGNAL ;
    PORT
      LAYER M5 ;
        RECT  17.04 103.572 17.064 103.656 ;
    END
  END a_d[67]
  PIN a_d[68]
    DIRECTION INPUT ;
    USE SIGNAL ;
    PORT
      LAYER M5 ;
        RECT  17.088 103.572 17.112 103.656 ;
    END
  END a_d[68]
  PIN a_d[69]
    DIRECTION INPUT ;
    USE SIGNAL ;
    PORT
      LAYER M5 ;
        RECT  17.136 103.572 17.16 103.656 ;
    END
  END a_d[69]
  PIN a_d[6]
    DIRECTION INPUT ;
    USE SIGNAL ;
    PORT
      LAYER M5 ;
        RECT  14.112 103.572 14.136 103.656 ;
    END
  END a_d[6]
  PIN a_d[70]
    DIRECTION INPUT ;
    USE SIGNAL ;
    PORT
      LAYER M5 ;
        RECT  17.184 103.572 17.208 103.656 ;
    END
  END a_d[70]
  PIN a_d[71]
    DIRECTION INPUT ;
    USE SIGNAL ;
    PORT
      LAYER M5 ;
        RECT  17.232 103.572 17.256 103.656 ;
    END
  END a_d[71]
  PIN a_d[72]
    DIRECTION INPUT ;
    USE SIGNAL ;
    PORT
      LAYER M5 ;
        RECT  17.28 103.572 17.304 103.656 ;
    END
  END a_d[72]
  PIN a_d[73]
    DIRECTION INPUT ;
    USE SIGNAL ;
    PORT
      LAYER M5 ;
        RECT  17.328 103.572 17.352 103.656 ;
    END
  END a_d[73]
  PIN a_d[74]
    DIRECTION INPUT ;
    USE SIGNAL ;
    PORT
      LAYER M5 ;
        RECT  17.376 103.572 17.4 103.656 ;
    END
  END a_d[74]
  PIN a_d[75]
    DIRECTION INPUT ;
    USE SIGNAL ;
    PORT
      LAYER M5 ;
        RECT  17.424 103.572 17.448 103.656 ;
    END
  END a_d[75]
  PIN a_d[76]
    DIRECTION INPUT ;
    USE SIGNAL ;
    PORT
      LAYER M5 ;
        RECT  17.472 103.572 17.496 103.656 ;
    END
  END a_d[76]
  PIN a_d[77]
    DIRECTION INPUT ;
    USE SIGNAL ;
    PORT
      LAYER M5 ;
        RECT  17.52 103.572 17.544 103.656 ;
    END
  END a_d[77]
  PIN a_d[78]
    DIRECTION INPUT ;
    USE SIGNAL ;
    PORT
      LAYER M5 ;
        RECT  17.568 103.572 17.592 103.656 ;
    END
  END a_d[78]
  PIN a_d[79]
    DIRECTION INPUT ;
    USE SIGNAL ;
    PORT
      LAYER M5 ;
        RECT  17.616 103.572 17.64 103.656 ;
    END
  END a_d[79]
  PIN a_d[7]
    DIRECTION INPUT ;
    USE SIGNAL ;
    PORT
      LAYER M5 ;
        RECT  14.16 103.572 14.184 103.656 ;
    END
  END a_d[7]
  PIN a_d[80]
    DIRECTION INPUT ;
    USE SIGNAL ;
    PORT
      LAYER M5 ;
        RECT  17.664 103.572 17.688 103.656 ;
    END
  END a_d[80]
  PIN a_d[81]
    DIRECTION INPUT ;
    USE SIGNAL ;
    PORT
      LAYER M5 ;
        RECT  17.712 103.572 17.736 103.656 ;
    END
  END a_d[81]
  PIN a_d[82]
    DIRECTION INPUT ;
    USE SIGNAL ;
    PORT
      LAYER M5 ;
        RECT  17.76 103.572 17.784 103.656 ;
    END
  END a_d[82]
  PIN a_d[83]
    DIRECTION INPUT ;
    USE SIGNAL ;
    PORT
      LAYER M5 ;
        RECT  17.808 103.572 17.832 103.656 ;
    END
  END a_d[83]
  PIN a_d[84]
    DIRECTION INPUT ;
    USE SIGNAL ;
    PORT
      LAYER M5 ;
        RECT  17.856 103.572 17.88 103.656 ;
    END
  END a_d[84]
  PIN a_d[85]
    DIRECTION INPUT ;
    USE SIGNAL ;
    PORT
      LAYER M5 ;
        RECT  17.904 103.572 17.928 103.656 ;
    END
  END a_d[85]
  PIN a_d[86]
    DIRECTION INPUT ;
    USE SIGNAL ;
    PORT
      LAYER M5 ;
        RECT  17.952 103.572 17.976 103.656 ;
    END
  END a_d[86]
  PIN a_d[87]
    DIRECTION INPUT ;
    USE SIGNAL ;
    PORT
      LAYER M5 ;
        RECT  18 103.572 18.024 103.656 ;
    END
  END a_d[87]
  PIN a_d[88]
    DIRECTION INPUT ;
    USE SIGNAL ;
    PORT
      LAYER M5 ;
        RECT  18.048 103.572 18.072 103.656 ;
    END
  END a_d[88]
  PIN a_d[89]
    DIRECTION INPUT ;
    USE SIGNAL ;
    PORT
      LAYER M5 ;
        RECT  18.096 103.572 18.12 103.656 ;
    END
  END a_d[89]
  PIN a_d[8]
    DIRECTION INPUT ;
    USE SIGNAL ;
    PORT
      LAYER M5 ;
        RECT  14.208 103.572 14.232 103.656 ;
    END
  END a_d[8]
  PIN a_d[90]
    DIRECTION INPUT ;
    USE SIGNAL ;
    PORT
      LAYER M5 ;
        RECT  18.144 103.572 18.168 103.656 ;
    END
  END a_d[90]
  PIN a_d[91]
    DIRECTION INPUT ;
    USE SIGNAL ;
    PORT
      LAYER M5 ;
        RECT  18.192 103.572 18.216 103.656 ;
    END
  END a_d[91]
  PIN a_d[92]
    DIRECTION INPUT ;
    USE SIGNAL ;
    PORT
      LAYER M5 ;
        RECT  18.24 103.572 18.264 103.656 ;
    END
  END a_d[92]
  PIN a_d[93]
    DIRECTION INPUT ;
    USE SIGNAL ;
    PORT
      LAYER M5 ;
        RECT  18.288 103.572 18.312 103.656 ;
    END
  END a_d[93]
  PIN a_d[94]
    DIRECTION INPUT ;
    USE SIGNAL ;
    PORT
      LAYER M5 ;
        RECT  18.336 103.572 18.36 103.656 ;
    END
  END a_d[94]
  PIN a_d[95]
    DIRECTION INPUT ;
    USE SIGNAL ;
    PORT
      LAYER M5 ;
        RECT  18.384 103.572 18.408 103.656 ;
    END
  END a_d[95]
  PIN a_d[96]
    DIRECTION INPUT ;
    USE SIGNAL ;
    PORT
      LAYER M5 ;
        RECT  18.432 103.572 18.456 103.656 ;
    END
  END a_d[96]
  PIN a_d[97]
    DIRECTION INPUT ;
    USE SIGNAL ;
    PORT
      LAYER M5 ;
        RECT  18.48 103.572 18.504 103.656 ;
    END
  END a_d[97]
  PIN a_d[98]
    DIRECTION INPUT ;
    USE SIGNAL ;
    PORT
      LAYER M5 ;
        RECT  18.528 103.572 18.552 103.656 ;
    END
  END a_d[98]
  PIN a_d[99]
    DIRECTION INPUT ;
    USE SIGNAL ;
    PORT
      LAYER M5 ;
        RECT  18.576 103.572 18.6 103.656 ;
    END
  END a_d[99]
  PIN a_d[9]
    DIRECTION INPUT ;
    USE SIGNAL ;
    PORT
      LAYER M5 ;
        RECT  14.256 103.572 14.28 103.656 ;
    END
  END a_d[9]
  PIN a_r
    DIRECTION OUTPUT ;
    USE SIGNAL ;
    PORT
      LAYER M5 ;
        RECT  38.208 103.572 38.232 103.656 ;
    END
  END a_r
  PIN b_d[0]
    DIRECTION OUTPUT ;
    USE SIGNAL ;
    PORT
      LAYER M5 ;
        RECT  13.776 0 13.8 0.084 ;
    END
  END b_d[0]
  PIN b_d[100]
    DIRECTION OUTPUT ;
    USE SIGNAL ;
    PORT
      LAYER M5 ;
        RECT  18.576 0 18.6 0.084 ;
    END
  END b_d[100]
  PIN b_d[101]
    DIRECTION OUTPUT ;
    USE SIGNAL ;
    PORT
      LAYER M5 ;
        RECT  18.624 0 18.648 0.084 ;
    END
  END b_d[101]
  PIN b_d[102]
    DIRECTION OUTPUT ;
    USE SIGNAL ;
    PORT
      LAYER M5 ;
        RECT  18.672 0 18.696 0.084 ;
    END
  END b_d[102]
  PIN b_d[103]
    DIRECTION OUTPUT ;
    USE SIGNAL ;
    PORT
      LAYER M5 ;
        RECT  18.72 0 18.744 0.084 ;
    END
  END b_d[103]
  PIN b_d[104]
    DIRECTION OUTPUT ;
    USE SIGNAL ;
    PORT
      LAYER M5 ;
        RECT  18.768 0 18.792 0.084 ;
    END
  END b_d[104]
  PIN b_d[105]
    DIRECTION OUTPUT ;
    USE SIGNAL ;
    PORT
      LAYER M5 ;
        RECT  18.816 0 18.84 0.084 ;
    END
  END b_d[105]
  PIN b_d[106]
    DIRECTION OUTPUT ;
    USE SIGNAL ;
    PORT
      LAYER M5 ;
        RECT  18.864 0 18.888 0.084 ;
    END
  END b_d[106]
  PIN b_d[107]
    DIRECTION OUTPUT ;
    USE SIGNAL ;
    PORT
      LAYER M5 ;
        RECT  18.912 0 18.936 0.084 ;
    END
  END b_d[107]
  PIN b_d[108]
    DIRECTION OUTPUT ;
    USE SIGNAL ;
    PORT
      LAYER M5 ;
        RECT  18.96 0 18.984 0.084 ;
    END
  END b_d[108]
  PIN b_d[109]
    DIRECTION OUTPUT ;
    USE SIGNAL ;
    PORT
      LAYER M5 ;
        RECT  19.008 0 19.032 0.084 ;
    END
  END b_d[109]
  PIN b_d[10]
    DIRECTION OUTPUT ;
    USE SIGNAL ;
    PORT
      LAYER M5 ;
        RECT  14.256 0 14.28 0.084 ;
    END
  END b_d[10]
  PIN b_d[110]
    DIRECTION OUTPUT ;
    USE SIGNAL ;
    PORT
      LAYER M5 ;
        RECT  19.056 0 19.08 0.084 ;
    END
  END b_d[110]
  PIN b_d[111]
    DIRECTION OUTPUT ;
    USE SIGNAL ;
    PORT
      LAYER M5 ;
        RECT  19.104 0 19.128 0.084 ;
    END
  END b_d[111]
  PIN b_d[112]
    DIRECTION OUTPUT ;
    USE SIGNAL ;
    PORT
      LAYER M5 ;
        RECT  19.152 0 19.176 0.084 ;
    END
  END b_d[112]
  PIN b_d[113]
    DIRECTION OUTPUT ;
    USE SIGNAL ;
    PORT
      LAYER M5 ;
        RECT  19.2 0 19.224 0.084 ;
    END
  END b_d[113]
  PIN b_d[114]
    DIRECTION OUTPUT ;
    USE SIGNAL ;
    PORT
      LAYER M5 ;
        RECT  19.248 0 19.272 0.084 ;
    END
  END b_d[114]
  PIN b_d[115]
    DIRECTION OUTPUT ;
    USE SIGNAL ;
    PORT
      LAYER M5 ;
        RECT  19.296 0 19.32 0.084 ;
    END
  END b_d[115]
  PIN b_d[116]
    DIRECTION OUTPUT ;
    USE SIGNAL ;
    PORT
      LAYER M5 ;
        RECT  19.344 0 19.368 0.084 ;
    END
  END b_d[116]
  PIN b_d[117]
    DIRECTION OUTPUT ;
    USE SIGNAL ;
    PORT
      LAYER M5 ;
        RECT  19.392 0 19.416 0.084 ;
    END
  END b_d[117]
  PIN b_d[118]
    DIRECTION OUTPUT ;
    USE SIGNAL ;
    PORT
      LAYER M5 ;
        RECT  19.44 0 19.464 0.084 ;
    END
  END b_d[118]
  PIN b_d[119]
    DIRECTION OUTPUT ;
    USE SIGNAL ;
    PORT
      LAYER M5 ;
        RECT  19.488 0 19.512 0.084 ;
    END
  END b_d[119]
  PIN b_d[11]
    DIRECTION OUTPUT ;
    USE SIGNAL ;
    PORT
      LAYER M5 ;
        RECT  14.304 0 14.328 0.084 ;
    END
  END b_d[11]
  PIN b_d[120]
    DIRECTION OUTPUT ;
    USE SIGNAL ;
    PORT
      LAYER M5 ;
        RECT  19.536 0 19.56 0.084 ;
    END
  END b_d[120]
  PIN b_d[121]
    DIRECTION OUTPUT ;
    USE SIGNAL ;
    PORT
      LAYER M5 ;
        RECT  19.584 0 19.608 0.084 ;
    END
  END b_d[121]
  PIN b_d[122]
    DIRECTION OUTPUT ;
    USE SIGNAL ;
    PORT
      LAYER M5 ;
        RECT  19.632 0 19.656 0.084 ;
    END
  END b_d[122]
  PIN b_d[123]
    DIRECTION OUTPUT ;
    USE SIGNAL ;
    PORT
      LAYER M5 ;
        RECT  19.68 0 19.704 0.084 ;
    END
  END b_d[123]
  PIN b_d[124]
    DIRECTION OUTPUT ;
    USE SIGNAL ;
    PORT
      LAYER M5 ;
        RECT  19.728 0 19.752 0.084 ;
    END
  END b_d[124]
  PIN b_d[125]
    DIRECTION OUTPUT ;
    USE SIGNAL ;
    PORT
      LAYER M5 ;
        RECT  19.776 0 19.8 0.084 ;
    END
  END b_d[125]
  PIN b_d[126]
    DIRECTION OUTPUT ;
    USE SIGNAL ;
    PORT
      LAYER M5 ;
        RECT  19.824 0 19.848 0.084 ;
    END
  END b_d[126]
  PIN b_d[127]
    DIRECTION OUTPUT ;
    USE SIGNAL ;
    PORT
      LAYER M5 ;
        RECT  19.872 0 19.896 0.084 ;
    END
  END b_d[127]
  PIN b_d[128]
    DIRECTION OUTPUT ;
    USE SIGNAL ;
    PORT
      LAYER M5 ;
        RECT  19.92 0 19.944 0.084 ;
    END
  END b_d[128]
  PIN b_d[129]
    DIRECTION OUTPUT ;
    USE SIGNAL ;
    PORT
      LAYER M5 ;
        RECT  19.968 0 19.992 0.084 ;
    END
  END b_d[129]
  PIN b_d[12]
    DIRECTION OUTPUT ;
    USE SIGNAL ;
    PORT
      LAYER M5 ;
        RECT  14.352 0 14.376 0.084 ;
    END
  END b_d[12]
  PIN b_d[130]
    DIRECTION OUTPUT ;
    USE SIGNAL ;
    PORT
      LAYER M5 ;
        RECT  20.016 0 20.04 0.084 ;
    END
  END b_d[130]
  PIN b_d[131]
    DIRECTION OUTPUT ;
    USE SIGNAL ;
    PORT
      LAYER M5 ;
        RECT  20.064 0 20.088 0.084 ;
    END
  END b_d[131]
  PIN b_d[132]
    DIRECTION OUTPUT ;
    USE SIGNAL ;
    PORT
      LAYER M5 ;
        RECT  20.112 0 20.136 0.084 ;
    END
  END b_d[132]
  PIN b_d[133]
    DIRECTION OUTPUT ;
    USE SIGNAL ;
    PORT
      LAYER M5 ;
        RECT  20.16 0 20.184 0.084 ;
    END
  END b_d[133]
  PIN b_d[134]
    DIRECTION OUTPUT ;
    USE SIGNAL ;
    PORT
      LAYER M5 ;
        RECT  20.208 0 20.232 0.084 ;
    END
  END b_d[134]
  PIN b_d[135]
    DIRECTION OUTPUT ;
    USE SIGNAL ;
    PORT
      LAYER M5 ;
        RECT  20.256 0 20.28 0.084 ;
    END
  END b_d[135]
  PIN b_d[136]
    DIRECTION OUTPUT ;
    USE SIGNAL ;
    PORT
      LAYER M5 ;
        RECT  20.304 0 20.328 0.084 ;
    END
  END b_d[136]
  PIN b_d[137]
    DIRECTION OUTPUT ;
    USE SIGNAL ;
    PORT
      LAYER M5 ;
        RECT  20.352 0 20.376 0.084 ;
    END
  END b_d[137]
  PIN b_d[138]
    DIRECTION OUTPUT ;
    USE SIGNAL ;
    PORT
      LAYER M5 ;
        RECT  20.4 0 20.424 0.084 ;
    END
  END b_d[138]
  PIN b_d[139]
    DIRECTION OUTPUT ;
    USE SIGNAL ;
    PORT
      LAYER M5 ;
        RECT  20.448 0 20.472 0.084 ;
    END
  END b_d[139]
  PIN b_d[13]
    DIRECTION OUTPUT ;
    USE SIGNAL ;
    PORT
      LAYER M5 ;
        RECT  14.4 0 14.424 0.084 ;
    END
  END b_d[13]
  PIN b_d[140]
    DIRECTION OUTPUT ;
    USE SIGNAL ;
    PORT
      LAYER M5 ;
        RECT  20.496 0 20.52 0.084 ;
    END
  END b_d[140]
  PIN b_d[141]
    DIRECTION OUTPUT ;
    USE SIGNAL ;
    PORT
      LAYER M5 ;
        RECT  20.544 0 20.568 0.084 ;
    END
  END b_d[141]
  PIN b_d[142]
    DIRECTION OUTPUT ;
    USE SIGNAL ;
    PORT
      LAYER M5 ;
        RECT  20.592 0 20.616 0.084 ;
    END
  END b_d[142]
  PIN b_d[143]
    DIRECTION OUTPUT ;
    USE SIGNAL ;
    PORT
      LAYER M5 ;
        RECT  20.64 0 20.664 0.084 ;
    END
  END b_d[143]
  PIN b_d[144]
    DIRECTION OUTPUT ;
    USE SIGNAL ;
    PORT
      LAYER M5 ;
        RECT  20.688 0 20.712 0.084 ;
    END
  END b_d[144]
  PIN b_d[145]
    DIRECTION OUTPUT ;
    USE SIGNAL ;
    PORT
      LAYER M5 ;
        RECT  20.736 0 20.76 0.084 ;
    END
  END b_d[145]
  PIN b_d[146]
    DIRECTION OUTPUT ;
    USE SIGNAL ;
    PORT
      LAYER M5 ;
        RECT  20.784 0 20.808 0.084 ;
    END
  END b_d[146]
  PIN b_d[147]
    DIRECTION OUTPUT ;
    USE SIGNAL ;
    PORT
      LAYER M5 ;
        RECT  20.832 0 20.856 0.084 ;
    END
  END b_d[147]
  PIN b_d[148]
    DIRECTION OUTPUT ;
    USE SIGNAL ;
    PORT
      LAYER M5 ;
        RECT  20.88 0 20.904 0.084 ;
    END
  END b_d[148]
  PIN b_d[149]
    DIRECTION OUTPUT ;
    USE SIGNAL ;
    PORT
      LAYER M5 ;
        RECT  20.928 0 20.952 0.084 ;
    END
  END b_d[149]
  PIN b_d[14]
    DIRECTION OUTPUT ;
    USE SIGNAL ;
    PORT
      LAYER M5 ;
        RECT  14.448 0 14.472 0.084 ;
    END
  END b_d[14]
  PIN b_d[150]
    DIRECTION OUTPUT ;
    USE SIGNAL ;
    PORT
      LAYER M5 ;
        RECT  20.976 0 21 0.084 ;
    END
  END b_d[150]
  PIN b_d[151]
    DIRECTION OUTPUT ;
    USE SIGNAL ;
    PORT
      LAYER M5 ;
        RECT  21.024 0 21.048 0.084 ;
    END
  END b_d[151]
  PIN b_d[152]
    DIRECTION OUTPUT ;
    USE SIGNAL ;
    PORT
      LAYER M5 ;
        RECT  21.072 0 21.096 0.084 ;
    END
  END b_d[152]
  PIN b_d[153]
    DIRECTION OUTPUT ;
    USE SIGNAL ;
    PORT
      LAYER M5 ;
        RECT  21.12 0 21.144 0.084 ;
    END
  END b_d[153]
  PIN b_d[154]
    DIRECTION OUTPUT ;
    USE SIGNAL ;
    PORT
      LAYER M5 ;
        RECT  21.168 0 21.192 0.084 ;
    END
  END b_d[154]
  PIN b_d[155]
    DIRECTION OUTPUT ;
    USE SIGNAL ;
    PORT
      LAYER M5 ;
        RECT  21.216 0 21.24 0.084 ;
    END
  END b_d[155]
  PIN b_d[156]
    DIRECTION OUTPUT ;
    USE SIGNAL ;
    PORT
      LAYER M5 ;
        RECT  21.264 0 21.288 0.084 ;
    END
  END b_d[156]
  PIN b_d[157]
    DIRECTION OUTPUT ;
    USE SIGNAL ;
    PORT
      LAYER M5 ;
        RECT  21.312 0 21.336 0.084 ;
    END
  END b_d[157]
  PIN b_d[158]
    DIRECTION OUTPUT ;
    USE SIGNAL ;
    PORT
      LAYER M5 ;
        RECT  21.36 0 21.384 0.084 ;
    END
  END b_d[158]
  PIN b_d[159]
    DIRECTION OUTPUT ;
    USE SIGNAL ;
    PORT
      LAYER M5 ;
        RECT  21.408 0 21.432 0.084 ;
    END
  END b_d[159]
  PIN b_d[15]
    DIRECTION OUTPUT ;
    USE SIGNAL ;
    PORT
      LAYER M5 ;
        RECT  14.496 0 14.52 0.084 ;
    END
  END b_d[15]
  PIN b_d[160]
    DIRECTION OUTPUT ;
    USE SIGNAL ;
    PORT
      LAYER M5 ;
        RECT  21.456 0 21.48 0.084 ;
    END
  END b_d[160]
  PIN b_d[161]
    DIRECTION OUTPUT ;
    USE SIGNAL ;
    PORT
      LAYER M5 ;
        RECT  21.504 0 21.528 0.084 ;
    END
  END b_d[161]
  PIN b_d[162]
    DIRECTION OUTPUT ;
    USE SIGNAL ;
    PORT
      LAYER M5 ;
        RECT  21.552 0 21.576 0.084 ;
    END
  END b_d[162]
  PIN b_d[163]
    DIRECTION OUTPUT ;
    USE SIGNAL ;
    PORT
      LAYER M5 ;
        RECT  21.6 0 21.624 0.084 ;
    END
  END b_d[163]
  PIN b_d[164]
    DIRECTION OUTPUT ;
    USE SIGNAL ;
    PORT
      LAYER M5 ;
        RECT  21.648 0 21.672 0.084 ;
    END
  END b_d[164]
  PIN b_d[165]
    DIRECTION OUTPUT ;
    USE SIGNAL ;
    PORT
      LAYER M5 ;
        RECT  21.696 0 21.72 0.084 ;
    END
  END b_d[165]
  PIN b_d[166]
    DIRECTION OUTPUT ;
    USE SIGNAL ;
    PORT
      LAYER M5 ;
        RECT  21.744 0 21.768 0.084 ;
    END
  END b_d[166]
  PIN b_d[167]
    DIRECTION OUTPUT ;
    USE SIGNAL ;
    PORT
      LAYER M5 ;
        RECT  21.792 0 21.816 0.084 ;
    END
  END b_d[167]
  PIN b_d[168]
    DIRECTION OUTPUT ;
    USE SIGNAL ;
    PORT
      LAYER M5 ;
        RECT  21.84 0 21.864 0.084 ;
    END
  END b_d[168]
  PIN b_d[169]
    DIRECTION OUTPUT ;
    USE SIGNAL ;
    PORT
      LAYER M5 ;
        RECT  21.888 0 21.912 0.084 ;
    END
  END b_d[169]
  PIN b_d[16]
    DIRECTION OUTPUT ;
    USE SIGNAL ;
    PORT
      LAYER M5 ;
        RECT  14.544 0 14.568 0.084 ;
    END
  END b_d[16]
  PIN b_d[170]
    DIRECTION OUTPUT ;
    USE SIGNAL ;
    PORT
      LAYER M5 ;
        RECT  21.936 0 21.96 0.084 ;
    END
  END b_d[170]
  PIN b_d[171]
    DIRECTION OUTPUT ;
    USE SIGNAL ;
    PORT
      LAYER M5 ;
        RECT  21.984 0 22.008 0.084 ;
    END
  END b_d[171]
  PIN b_d[172]
    DIRECTION OUTPUT ;
    USE SIGNAL ;
    PORT
      LAYER M5 ;
        RECT  22.032 0 22.056 0.084 ;
    END
  END b_d[172]
  PIN b_d[173]
    DIRECTION OUTPUT ;
    USE SIGNAL ;
    PORT
      LAYER M5 ;
        RECT  22.08 0 22.104 0.084 ;
    END
  END b_d[173]
  PIN b_d[174]
    DIRECTION OUTPUT ;
    USE SIGNAL ;
    PORT
      LAYER M5 ;
        RECT  22.128 0 22.152 0.084 ;
    END
  END b_d[174]
  PIN b_d[175]
    DIRECTION OUTPUT ;
    USE SIGNAL ;
    PORT
      LAYER M5 ;
        RECT  22.176 0 22.2 0.084 ;
    END
  END b_d[175]
  PIN b_d[176]
    DIRECTION OUTPUT ;
    USE SIGNAL ;
    PORT
      LAYER M5 ;
        RECT  22.224 0 22.248 0.084 ;
    END
  END b_d[176]
  PIN b_d[177]
    DIRECTION OUTPUT ;
    USE SIGNAL ;
    PORT
      LAYER M5 ;
        RECT  22.272 0 22.296 0.084 ;
    END
  END b_d[177]
  PIN b_d[178]
    DIRECTION OUTPUT ;
    USE SIGNAL ;
    PORT
      LAYER M5 ;
        RECT  22.32 0 22.344 0.084 ;
    END
  END b_d[178]
  PIN b_d[179]
    DIRECTION OUTPUT ;
    USE SIGNAL ;
    PORT
      LAYER M5 ;
        RECT  22.368 0 22.392 0.084 ;
    END
  END b_d[179]
  PIN b_d[17]
    DIRECTION OUTPUT ;
    USE SIGNAL ;
    PORT
      LAYER M5 ;
        RECT  14.592 0 14.616 0.084 ;
    END
  END b_d[17]
  PIN b_d[180]
    DIRECTION OUTPUT ;
    USE SIGNAL ;
    PORT
      LAYER M5 ;
        RECT  22.416 0 22.44 0.084 ;
    END
  END b_d[180]
  PIN b_d[181]
    DIRECTION OUTPUT ;
    USE SIGNAL ;
    PORT
      LAYER M5 ;
        RECT  22.464 0 22.488 0.084 ;
    END
  END b_d[181]
  PIN b_d[182]
    DIRECTION OUTPUT ;
    USE SIGNAL ;
    PORT
      LAYER M5 ;
        RECT  22.512 0 22.536 0.084 ;
    END
  END b_d[182]
  PIN b_d[183]
    DIRECTION OUTPUT ;
    USE SIGNAL ;
    PORT
      LAYER M5 ;
        RECT  22.56 0 22.584 0.084 ;
    END
  END b_d[183]
  PIN b_d[184]
    DIRECTION OUTPUT ;
    USE SIGNAL ;
    PORT
      LAYER M5 ;
        RECT  22.608 0 22.632 0.084 ;
    END
  END b_d[184]
  PIN b_d[185]
    DIRECTION OUTPUT ;
    USE SIGNAL ;
    PORT
      LAYER M5 ;
        RECT  22.656 0 22.68 0.084 ;
    END
  END b_d[185]
  PIN b_d[186]
    DIRECTION OUTPUT ;
    USE SIGNAL ;
    PORT
      LAYER M5 ;
        RECT  22.704 0 22.728 0.084 ;
    END
  END b_d[186]
  PIN b_d[187]
    DIRECTION OUTPUT ;
    USE SIGNAL ;
    PORT
      LAYER M5 ;
        RECT  22.752 0 22.776 0.084 ;
    END
  END b_d[187]
  PIN b_d[188]
    DIRECTION OUTPUT ;
    USE SIGNAL ;
    PORT
      LAYER M5 ;
        RECT  22.8 0 22.824 0.084 ;
    END
  END b_d[188]
  PIN b_d[189]
    DIRECTION OUTPUT ;
    USE SIGNAL ;
    PORT
      LAYER M5 ;
        RECT  22.848 0 22.872 0.084 ;
    END
  END b_d[189]
  PIN b_d[18]
    DIRECTION OUTPUT ;
    USE SIGNAL ;
    PORT
      LAYER M5 ;
        RECT  14.64 0 14.664 0.084 ;
    END
  END b_d[18]
  PIN b_d[190]
    DIRECTION OUTPUT ;
    USE SIGNAL ;
    PORT
      LAYER M5 ;
        RECT  22.896 0 22.92 0.084 ;
    END
  END b_d[190]
  PIN b_d[191]
    DIRECTION OUTPUT ;
    USE SIGNAL ;
    PORT
      LAYER M5 ;
        RECT  22.944 0 22.968 0.084 ;
    END
  END b_d[191]
  PIN b_d[192]
    DIRECTION OUTPUT ;
    USE SIGNAL ;
    PORT
      LAYER M5 ;
        RECT  22.992 0 23.016 0.084 ;
    END
  END b_d[192]
  PIN b_d[193]
    DIRECTION OUTPUT ;
    USE SIGNAL ;
    PORT
      LAYER M5 ;
        RECT  23.04 0 23.064 0.084 ;
    END
  END b_d[193]
  PIN b_d[194]
    DIRECTION OUTPUT ;
    USE SIGNAL ;
    PORT
      LAYER M5 ;
        RECT  23.088 0 23.112 0.084 ;
    END
  END b_d[194]
  PIN b_d[195]
    DIRECTION OUTPUT ;
    USE SIGNAL ;
    PORT
      LAYER M5 ;
        RECT  23.136 0 23.16 0.084 ;
    END
  END b_d[195]
  PIN b_d[196]
    DIRECTION OUTPUT ;
    USE SIGNAL ;
    PORT
      LAYER M5 ;
        RECT  23.184 0 23.208 0.084 ;
    END
  END b_d[196]
  PIN b_d[197]
    DIRECTION OUTPUT ;
    USE SIGNAL ;
    PORT
      LAYER M5 ;
        RECT  23.232 0 23.256 0.084 ;
    END
  END b_d[197]
  PIN b_d[198]
    DIRECTION OUTPUT ;
    USE SIGNAL ;
    PORT
      LAYER M5 ;
        RECT  23.28 0 23.304 0.084 ;
    END
  END b_d[198]
  PIN b_d[199]
    DIRECTION OUTPUT ;
    USE SIGNAL ;
    PORT
      LAYER M5 ;
        RECT  23.328 0 23.352 0.084 ;
    END
  END b_d[199]
  PIN b_d[19]
    DIRECTION OUTPUT ;
    USE SIGNAL ;
    PORT
      LAYER M5 ;
        RECT  14.688 0 14.712 0.084 ;
    END
  END b_d[19]
  PIN b_d[1]
    DIRECTION OUTPUT ;
    USE SIGNAL ;
    PORT
      LAYER M5 ;
        RECT  13.824 0 13.848 0.084 ;
    END
  END b_d[1]
  PIN b_d[200]
    DIRECTION OUTPUT ;
    USE SIGNAL ;
    PORT
      LAYER M5 ;
        RECT  23.376 0 23.4 0.084 ;
    END
  END b_d[200]
  PIN b_d[201]
    DIRECTION OUTPUT ;
    USE SIGNAL ;
    PORT
      LAYER M5 ;
        RECT  23.424 0 23.448 0.084 ;
    END
  END b_d[201]
  PIN b_d[202]
    DIRECTION OUTPUT ;
    USE SIGNAL ;
    PORT
      LAYER M5 ;
        RECT  23.472 0 23.496 0.084 ;
    END
  END b_d[202]
  PIN b_d[203]
    DIRECTION OUTPUT ;
    USE SIGNAL ;
    PORT
      LAYER M5 ;
        RECT  23.52 0 23.544 0.084 ;
    END
  END b_d[203]
  PIN b_d[204]
    DIRECTION OUTPUT ;
    USE SIGNAL ;
    PORT
      LAYER M5 ;
        RECT  23.568 0 23.592 0.084 ;
    END
  END b_d[204]
  PIN b_d[205]
    DIRECTION OUTPUT ;
    USE SIGNAL ;
    PORT
      LAYER M5 ;
        RECT  23.616 0 23.64 0.084 ;
    END
  END b_d[205]
  PIN b_d[206]
    DIRECTION OUTPUT ;
    USE SIGNAL ;
    PORT
      LAYER M5 ;
        RECT  23.664 0 23.688 0.084 ;
    END
  END b_d[206]
  PIN b_d[207]
    DIRECTION OUTPUT ;
    USE SIGNAL ;
    PORT
      LAYER M5 ;
        RECT  23.712 0 23.736 0.084 ;
    END
  END b_d[207]
  PIN b_d[208]
    DIRECTION OUTPUT ;
    USE SIGNAL ;
    PORT
      LAYER M5 ;
        RECT  23.76 0 23.784 0.084 ;
    END
  END b_d[208]
  PIN b_d[209]
    DIRECTION OUTPUT ;
    USE SIGNAL ;
    PORT
      LAYER M5 ;
        RECT  23.808 0 23.832 0.084 ;
    END
  END b_d[209]
  PIN b_d[20]
    DIRECTION OUTPUT ;
    USE SIGNAL ;
    PORT
      LAYER M5 ;
        RECT  14.736 0 14.76 0.084 ;
    END
  END b_d[20]
  PIN b_d[210]
    DIRECTION OUTPUT ;
    USE SIGNAL ;
    PORT
      LAYER M5 ;
        RECT  23.856 0 23.88 0.084 ;
    END
  END b_d[210]
  PIN b_d[211]
    DIRECTION OUTPUT ;
    USE SIGNAL ;
    PORT
      LAYER M5 ;
        RECT  23.904 0 23.928 0.084 ;
    END
  END b_d[211]
  PIN b_d[212]
    DIRECTION OUTPUT ;
    USE SIGNAL ;
    PORT
      LAYER M5 ;
        RECT  23.952 0 23.976 0.084 ;
    END
  END b_d[212]
  PIN b_d[213]
    DIRECTION OUTPUT ;
    USE SIGNAL ;
    PORT
      LAYER M5 ;
        RECT  24 0 24.024 0.084 ;
    END
  END b_d[213]
  PIN b_d[214]
    DIRECTION OUTPUT ;
    USE SIGNAL ;
    PORT
      LAYER M5 ;
        RECT  24.048 0 24.072 0.084 ;
    END
  END b_d[214]
  PIN b_d[215]
    DIRECTION OUTPUT ;
    USE SIGNAL ;
    PORT
      LAYER M5 ;
        RECT  24.096 0 24.12 0.084 ;
    END
  END b_d[215]
  PIN b_d[216]
    DIRECTION OUTPUT ;
    USE SIGNAL ;
    PORT
      LAYER M5 ;
        RECT  24.144 0 24.168 0.084 ;
    END
  END b_d[216]
  PIN b_d[217]
    DIRECTION OUTPUT ;
    USE SIGNAL ;
    PORT
      LAYER M5 ;
        RECT  24.192 0 24.216 0.084 ;
    END
  END b_d[217]
  PIN b_d[218]
    DIRECTION OUTPUT ;
    USE SIGNAL ;
    PORT
      LAYER M5 ;
        RECT  24.24 0 24.264 0.084 ;
    END
  END b_d[218]
  PIN b_d[219]
    DIRECTION OUTPUT ;
    USE SIGNAL ;
    PORT
      LAYER M5 ;
        RECT  24.288 0 24.312 0.084 ;
    END
  END b_d[219]
  PIN b_d[21]
    DIRECTION OUTPUT ;
    USE SIGNAL ;
    PORT
      LAYER M5 ;
        RECT  14.784 0 14.808 0.084 ;
    END
  END b_d[21]
  PIN b_d[220]
    DIRECTION OUTPUT ;
    USE SIGNAL ;
    PORT
      LAYER M5 ;
        RECT  24.336 0 24.36 0.084 ;
    END
  END b_d[220]
  PIN b_d[221]
    DIRECTION OUTPUT ;
    USE SIGNAL ;
    PORT
      LAYER M5 ;
        RECT  24.384 0 24.408 0.084 ;
    END
  END b_d[221]
  PIN b_d[222]
    DIRECTION OUTPUT ;
    USE SIGNAL ;
    PORT
      LAYER M5 ;
        RECT  24.432 0 24.456 0.084 ;
    END
  END b_d[222]
  PIN b_d[223]
    DIRECTION OUTPUT ;
    USE SIGNAL ;
    PORT
      LAYER M5 ;
        RECT  24.48 0 24.504 0.084 ;
    END
  END b_d[223]
  PIN b_d[224]
    DIRECTION OUTPUT ;
    USE SIGNAL ;
    PORT
      LAYER M5 ;
        RECT  24.528 0 24.552 0.084 ;
    END
  END b_d[224]
  PIN b_d[225]
    DIRECTION OUTPUT ;
    USE SIGNAL ;
    PORT
      LAYER M5 ;
        RECT  24.576 0 24.6 0.084 ;
    END
  END b_d[225]
  PIN b_d[226]
    DIRECTION OUTPUT ;
    USE SIGNAL ;
    PORT
      LAYER M5 ;
        RECT  24.624 0 24.648 0.084 ;
    END
  END b_d[226]
  PIN b_d[227]
    DIRECTION OUTPUT ;
    USE SIGNAL ;
    PORT
      LAYER M5 ;
        RECT  24.672 0 24.696 0.084 ;
    END
  END b_d[227]
  PIN b_d[228]
    DIRECTION OUTPUT ;
    USE SIGNAL ;
    PORT
      LAYER M5 ;
        RECT  24.72 0 24.744 0.084 ;
    END
  END b_d[228]
  PIN b_d[229]
    DIRECTION OUTPUT ;
    USE SIGNAL ;
    PORT
      LAYER M5 ;
        RECT  24.768 0 24.792 0.084 ;
    END
  END b_d[229]
  PIN b_d[22]
    DIRECTION OUTPUT ;
    USE SIGNAL ;
    PORT
      LAYER M5 ;
        RECT  14.832 0 14.856 0.084 ;
    END
  END b_d[22]
  PIN b_d[230]
    DIRECTION OUTPUT ;
    USE SIGNAL ;
    PORT
      LAYER M5 ;
        RECT  24.816 0 24.84 0.084 ;
    END
  END b_d[230]
  PIN b_d[231]
    DIRECTION OUTPUT ;
    USE SIGNAL ;
    PORT
      LAYER M5 ;
        RECT  24.864 0 24.888 0.084 ;
    END
  END b_d[231]
  PIN b_d[232]
    DIRECTION OUTPUT ;
    USE SIGNAL ;
    PORT
      LAYER M5 ;
        RECT  24.912 0 24.936 0.084 ;
    END
  END b_d[232]
  PIN b_d[233]
    DIRECTION OUTPUT ;
    USE SIGNAL ;
    PORT
      LAYER M5 ;
        RECT  24.96 0 24.984 0.084 ;
    END
  END b_d[233]
  PIN b_d[234]
    DIRECTION OUTPUT ;
    USE SIGNAL ;
    PORT
      LAYER M5 ;
        RECT  25.008 0 25.032 0.084 ;
    END
  END b_d[234]
  PIN b_d[235]
    DIRECTION OUTPUT ;
    USE SIGNAL ;
    PORT
      LAYER M5 ;
        RECT  25.056 0 25.08 0.084 ;
    END
  END b_d[235]
  PIN b_d[236]
    DIRECTION OUTPUT ;
    USE SIGNAL ;
    PORT
      LAYER M5 ;
        RECT  25.104 0 25.128 0.084 ;
    END
  END b_d[236]
  PIN b_d[237]
    DIRECTION OUTPUT ;
    USE SIGNAL ;
    PORT
      LAYER M5 ;
        RECT  25.152 0 25.176 0.084 ;
    END
  END b_d[237]
  PIN b_d[238]
    DIRECTION OUTPUT ;
    USE SIGNAL ;
    PORT
      LAYER M5 ;
        RECT  25.2 0 25.224 0.084 ;
    END
  END b_d[238]
  PIN b_d[239]
    DIRECTION OUTPUT ;
    USE SIGNAL ;
    PORT
      LAYER M5 ;
        RECT  25.248 0 25.272 0.084 ;
    END
  END b_d[239]
  PIN b_d[23]
    DIRECTION OUTPUT ;
    USE SIGNAL ;
    PORT
      LAYER M5 ;
        RECT  14.88 0 14.904 0.084 ;
    END
  END b_d[23]
  PIN b_d[240]
    DIRECTION OUTPUT ;
    USE SIGNAL ;
    PORT
      LAYER M5 ;
        RECT  25.296 0 25.32 0.084 ;
    END
  END b_d[240]
  PIN b_d[241]
    DIRECTION OUTPUT ;
    USE SIGNAL ;
    PORT
      LAYER M5 ;
        RECT  25.344 0 25.368 0.084 ;
    END
  END b_d[241]
  PIN b_d[242]
    DIRECTION OUTPUT ;
    USE SIGNAL ;
    PORT
      LAYER M5 ;
        RECT  25.392 0 25.416 0.084 ;
    END
  END b_d[242]
  PIN b_d[243]
    DIRECTION OUTPUT ;
    USE SIGNAL ;
    PORT
      LAYER M5 ;
        RECT  25.44 0 25.464 0.084 ;
    END
  END b_d[243]
  PIN b_d[244]
    DIRECTION OUTPUT ;
    USE SIGNAL ;
    PORT
      LAYER M5 ;
        RECT  25.488 0 25.512 0.084 ;
    END
  END b_d[244]
  PIN b_d[245]
    DIRECTION OUTPUT ;
    USE SIGNAL ;
    PORT
      LAYER M5 ;
        RECT  25.536 0 25.56 0.084 ;
    END
  END b_d[245]
  PIN b_d[246]
    DIRECTION OUTPUT ;
    USE SIGNAL ;
    PORT
      LAYER M5 ;
        RECT  25.584 0 25.608 0.084 ;
    END
  END b_d[246]
  PIN b_d[247]
    DIRECTION OUTPUT ;
    USE SIGNAL ;
    PORT
      LAYER M5 ;
        RECT  25.632 0 25.656 0.084 ;
    END
  END b_d[247]
  PIN b_d[248]
    DIRECTION OUTPUT ;
    USE SIGNAL ;
    PORT
      LAYER M5 ;
        RECT  25.68 0 25.704 0.084 ;
    END
  END b_d[248]
  PIN b_d[249]
    DIRECTION OUTPUT ;
    USE SIGNAL ;
    PORT
      LAYER M5 ;
        RECT  25.728 0 25.752 0.084 ;
    END
  END b_d[249]
  PIN b_d[24]
    DIRECTION OUTPUT ;
    USE SIGNAL ;
    PORT
      LAYER M5 ;
        RECT  14.928 0 14.952 0.084 ;
    END
  END b_d[24]
  PIN b_d[250]
    DIRECTION OUTPUT ;
    USE SIGNAL ;
    PORT
      LAYER M5 ;
        RECT  25.776 0 25.8 0.084 ;
    END
  END b_d[250]
  PIN b_d[251]
    DIRECTION OUTPUT ;
    USE SIGNAL ;
    PORT
      LAYER M5 ;
        RECT  25.824 0 25.848 0.084 ;
    END
  END b_d[251]
  PIN b_d[252]
    DIRECTION OUTPUT ;
    USE SIGNAL ;
    PORT
      LAYER M5 ;
        RECT  25.872 0 25.896 0.084 ;
    END
  END b_d[252]
  PIN b_d[253]
    DIRECTION OUTPUT ;
    USE SIGNAL ;
    PORT
      LAYER M5 ;
        RECT  25.92 0 25.944 0.084 ;
    END
  END b_d[253]
  PIN b_d[254]
    DIRECTION OUTPUT ;
    USE SIGNAL ;
    PORT
      LAYER M5 ;
        RECT  25.968 0 25.992 0.084 ;
    END
  END b_d[254]
  PIN b_d[255]
    DIRECTION OUTPUT ;
    USE SIGNAL ;
    PORT
      LAYER M5 ;
        RECT  26.016 0 26.04 0.084 ;
    END
  END b_d[255]
  PIN b_d[256]
    DIRECTION OUTPUT ;
    USE SIGNAL ;
    PORT
      LAYER M5 ;
        RECT  26.064 0 26.088 0.084 ;
    END
  END b_d[256]
  PIN b_d[257]
    DIRECTION OUTPUT ;
    USE SIGNAL ;
    PORT
      LAYER M5 ;
        RECT  26.112 0 26.136 0.084 ;
    END
  END b_d[257]
  PIN b_d[258]
    DIRECTION OUTPUT ;
    USE SIGNAL ;
    PORT
      LAYER M5 ;
        RECT  26.16 0 26.184 0.084 ;
    END
  END b_d[258]
  PIN b_d[259]
    DIRECTION OUTPUT ;
    USE SIGNAL ;
    PORT
      LAYER M5 ;
        RECT  26.208 0 26.232 0.084 ;
    END
  END b_d[259]
  PIN b_d[25]
    DIRECTION OUTPUT ;
    USE SIGNAL ;
    PORT
      LAYER M5 ;
        RECT  14.976 0 15 0.084 ;
    END
  END b_d[25]
  PIN b_d[260]
    DIRECTION OUTPUT ;
    USE SIGNAL ;
    PORT
      LAYER M5 ;
        RECT  26.256 0 26.28 0.084 ;
    END
  END b_d[260]
  PIN b_d[261]
    DIRECTION OUTPUT ;
    USE SIGNAL ;
    PORT
      LAYER M5 ;
        RECT  26.304 0 26.328 0.084 ;
    END
  END b_d[261]
  PIN b_d[262]
    DIRECTION OUTPUT ;
    USE SIGNAL ;
    PORT
      LAYER M5 ;
        RECT  26.352 0 26.376 0.084 ;
    END
  END b_d[262]
  PIN b_d[263]
    DIRECTION OUTPUT ;
    USE SIGNAL ;
    PORT
      LAYER M5 ;
        RECT  26.4 0 26.424 0.084 ;
    END
  END b_d[263]
  PIN b_d[264]
    DIRECTION OUTPUT ;
    USE SIGNAL ;
    PORT
      LAYER M5 ;
        RECT  26.448 0 26.472 0.084 ;
    END
  END b_d[264]
  PIN b_d[265]
    DIRECTION OUTPUT ;
    USE SIGNAL ;
    PORT
      LAYER M5 ;
        RECT  26.496 0 26.52 0.084 ;
    END
  END b_d[265]
  PIN b_d[266]
    DIRECTION OUTPUT ;
    USE SIGNAL ;
    PORT
      LAYER M5 ;
        RECT  26.544 0 26.568 0.084 ;
    END
  END b_d[266]
  PIN b_d[267]
    DIRECTION OUTPUT ;
    USE SIGNAL ;
    PORT
      LAYER M5 ;
        RECT  26.592 0 26.616 0.084 ;
    END
  END b_d[267]
  PIN b_d[268]
    DIRECTION OUTPUT ;
    USE SIGNAL ;
    PORT
      LAYER M5 ;
        RECT  26.64 0 26.664 0.084 ;
    END
  END b_d[268]
  PIN b_d[269]
    DIRECTION OUTPUT ;
    USE SIGNAL ;
    PORT
      LAYER M5 ;
        RECT  26.688 0 26.712 0.084 ;
    END
  END b_d[269]
  PIN b_d[26]
    DIRECTION OUTPUT ;
    USE SIGNAL ;
    PORT
      LAYER M5 ;
        RECT  15.024 0 15.048 0.084 ;
    END
  END b_d[26]
  PIN b_d[270]
    DIRECTION OUTPUT ;
    USE SIGNAL ;
    PORT
      LAYER M5 ;
        RECT  26.736 0 26.76 0.084 ;
    END
  END b_d[270]
  PIN b_d[271]
    DIRECTION OUTPUT ;
    USE SIGNAL ;
    PORT
      LAYER M5 ;
        RECT  26.784 0 26.808 0.084 ;
    END
  END b_d[271]
  PIN b_d[272]
    DIRECTION OUTPUT ;
    USE SIGNAL ;
    PORT
      LAYER M5 ;
        RECT  26.832 0 26.856 0.084 ;
    END
  END b_d[272]
  PIN b_d[273]
    DIRECTION OUTPUT ;
    USE SIGNAL ;
    PORT
      LAYER M5 ;
        RECT  26.88 0 26.904 0.084 ;
    END
  END b_d[273]
  PIN b_d[274]
    DIRECTION OUTPUT ;
    USE SIGNAL ;
    PORT
      LAYER M5 ;
        RECT  26.928 0 26.952 0.084 ;
    END
  END b_d[274]
  PIN b_d[275]
    DIRECTION OUTPUT ;
    USE SIGNAL ;
    PORT
      LAYER M5 ;
        RECT  26.976 0 27 0.084 ;
    END
  END b_d[275]
  PIN b_d[276]
    DIRECTION OUTPUT ;
    USE SIGNAL ;
    PORT
      LAYER M5 ;
        RECT  27.024 0 27.048 0.084 ;
    END
  END b_d[276]
  PIN b_d[277]
    DIRECTION OUTPUT ;
    USE SIGNAL ;
    PORT
      LAYER M5 ;
        RECT  27.072 0 27.096 0.084 ;
    END
  END b_d[277]
  PIN b_d[278]
    DIRECTION OUTPUT ;
    USE SIGNAL ;
    PORT
      LAYER M5 ;
        RECT  27.12 0 27.144 0.084 ;
    END
  END b_d[278]
  PIN b_d[279]
    DIRECTION OUTPUT ;
    USE SIGNAL ;
    PORT
      LAYER M5 ;
        RECT  27.168 0 27.192 0.084 ;
    END
  END b_d[279]
  PIN b_d[27]
    DIRECTION OUTPUT ;
    USE SIGNAL ;
    PORT
      LAYER M5 ;
        RECT  15.072 0 15.096 0.084 ;
    END
  END b_d[27]
  PIN b_d[280]
    DIRECTION OUTPUT ;
    USE SIGNAL ;
    PORT
      LAYER M5 ;
        RECT  27.216 0 27.24 0.084 ;
    END
  END b_d[280]
  PIN b_d[281]
    DIRECTION OUTPUT ;
    USE SIGNAL ;
    PORT
      LAYER M5 ;
        RECT  27.264 0 27.288 0.084 ;
    END
  END b_d[281]
  PIN b_d[282]
    DIRECTION OUTPUT ;
    USE SIGNAL ;
    PORT
      LAYER M5 ;
        RECT  27.312 0 27.336 0.084 ;
    END
  END b_d[282]
  PIN b_d[283]
    DIRECTION OUTPUT ;
    USE SIGNAL ;
    PORT
      LAYER M5 ;
        RECT  27.36 0 27.384 0.084 ;
    END
  END b_d[283]
  PIN b_d[284]
    DIRECTION OUTPUT ;
    USE SIGNAL ;
    PORT
      LAYER M5 ;
        RECT  27.408 0 27.432 0.084 ;
    END
  END b_d[284]
  PIN b_d[285]
    DIRECTION OUTPUT ;
    USE SIGNAL ;
    PORT
      LAYER M5 ;
        RECT  27.456 0 27.48 0.084 ;
    END
  END b_d[285]
  PIN b_d[286]
    DIRECTION OUTPUT ;
    USE SIGNAL ;
    PORT
      LAYER M5 ;
        RECT  27.504 0 27.528 0.084 ;
    END
  END b_d[286]
  PIN b_d[287]
    DIRECTION OUTPUT ;
    USE SIGNAL ;
    PORT
      LAYER M5 ;
        RECT  27.552 0 27.576 0.084 ;
    END
  END b_d[287]
  PIN b_d[288]
    DIRECTION OUTPUT ;
    USE SIGNAL ;
    PORT
      LAYER M5 ;
        RECT  27.6 0 27.624 0.084 ;
    END
  END b_d[288]
  PIN b_d[289]
    DIRECTION OUTPUT ;
    USE SIGNAL ;
    PORT
      LAYER M5 ;
        RECT  27.648 0 27.672 0.084 ;
    END
  END b_d[289]
  PIN b_d[28]
    DIRECTION OUTPUT ;
    USE SIGNAL ;
    PORT
      LAYER M5 ;
        RECT  15.12 0 15.144 0.084 ;
    END
  END b_d[28]
  PIN b_d[290]
    DIRECTION OUTPUT ;
    USE SIGNAL ;
    PORT
      LAYER M5 ;
        RECT  27.696 0 27.72 0.084 ;
    END
  END b_d[290]
  PIN b_d[291]
    DIRECTION OUTPUT ;
    USE SIGNAL ;
    PORT
      LAYER M5 ;
        RECT  27.744 0 27.768 0.084 ;
    END
  END b_d[291]
  PIN b_d[292]
    DIRECTION OUTPUT ;
    USE SIGNAL ;
    PORT
      LAYER M5 ;
        RECT  27.792 0 27.816 0.084 ;
    END
  END b_d[292]
  PIN b_d[293]
    DIRECTION OUTPUT ;
    USE SIGNAL ;
    PORT
      LAYER M5 ;
        RECT  27.84 0 27.864 0.084 ;
    END
  END b_d[293]
  PIN b_d[294]
    DIRECTION OUTPUT ;
    USE SIGNAL ;
    PORT
      LAYER M5 ;
        RECT  27.888 0 27.912 0.084 ;
    END
  END b_d[294]
  PIN b_d[295]
    DIRECTION OUTPUT ;
    USE SIGNAL ;
    PORT
      LAYER M5 ;
        RECT  27.936 0 27.96 0.084 ;
    END
  END b_d[295]
  PIN b_d[296]
    DIRECTION OUTPUT ;
    USE SIGNAL ;
    PORT
      LAYER M5 ;
        RECT  27.984 0 28.008 0.084 ;
    END
  END b_d[296]
  PIN b_d[297]
    DIRECTION OUTPUT ;
    USE SIGNAL ;
    PORT
      LAYER M5 ;
        RECT  28.032 0 28.056 0.084 ;
    END
  END b_d[297]
  PIN b_d[298]
    DIRECTION OUTPUT ;
    USE SIGNAL ;
    PORT
      LAYER M5 ;
        RECT  28.08 0 28.104 0.084 ;
    END
  END b_d[298]
  PIN b_d[299]
    DIRECTION OUTPUT ;
    USE SIGNAL ;
    PORT
      LAYER M5 ;
        RECT  28.128 0 28.152 0.084 ;
    END
  END b_d[299]
  PIN b_d[29]
    DIRECTION OUTPUT ;
    USE SIGNAL ;
    PORT
      LAYER M5 ;
        RECT  15.168 0 15.192 0.084 ;
    END
  END b_d[29]
  PIN b_d[2]
    DIRECTION OUTPUT ;
    USE SIGNAL ;
    PORT
      LAYER M5 ;
        RECT  13.872 0 13.896 0.084 ;
    END
  END b_d[2]
  PIN b_d[300]
    DIRECTION OUTPUT ;
    USE SIGNAL ;
    PORT
      LAYER M5 ;
        RECT  28.176 0 28.2 0.084 ;
    END
  END b_d[300]
  PIN b_d[301]
    DIRECTION OUTPUT ;
    USE SIGNAL ;
    PORT
      LAYER M5 ;
        RECT  28.224 0 28.248 0.084 ;
    END
  END b_d[301]
  PIN b_d[302]
    DIRECTION OUTPUT ;
    USE SIGNAL ;
    PORT
      LAYER M5 ;
        RECT  28.272 0 28.296 0.084 ;
    END
  END b_d[302]
  PIN b_d[303]
    DIRECTION OUTPUT ;
    USE SIGNAL ;
    PORT
      LAYER M5 ;
        RECT  28.32 0 28.344 0.084 ;
    END
  END b_d[303]
  PIN b_d[304]
    DIRECTION OUTPUT ;
    USE SIGNAL ;
    PORT
      LAYER M5 ;
        RECT  28.368 0 28.392 0.084 ;
    END
  END b_d[304]
  PIN b_d[305]
    DIRECTION OUTPUT ;
    USE SIGNAL ;
    PORT
      LAYER M5 ;
        RECT  28.416 0 28.44 0.084 ;
    END
  END b_d[305]
  PIN b_d[306]
    DIRECTION OUTPUT ;
    USE SIGNAL ;
    PORT
      LAYER M5 ;
        RECT  28.464 0 28.488 0.084 ;
    END
  END b_d[306]
  PIN b_d[307]
    DIRECTION OUTPUT ;
    USE SIGNAL ;
    PORT
      LAYER M5 ;
        RECT  28.512 0 28.536 0.084 ;
    END
  END b_d[307]
  PIN b_d[308]
    DIRECTION OUTPUT ;
    USE SIGNAL ;
    PORT
      LAYER M5 ;
        RECT  28.56 0 28.584 0.084 ;
    END
  END b_d[308]
  PIN b_d[309]
    DIRECTION OUTPUT ;
    USE SIGNAL ;
    PORT
      LAYER M5 ;
        RECT  28.608 0 28.632 0.084 ;
    END
  END b_d[309]
  PIN b_d[30]
    DIRECTION OUTPUT ;
    USE SIGNAL ;
    PORT
      LAYER M5 ;
        RECT  15.216 0 15.24 0.084 ;
    END
  END b_d[30]
  PIN b_d[310]
    DIRECTION OUTPUT ;
    USE SIGNAL ;
    PORT
      LAYER M5 ;
        RECT  28.656 0 28.68 0.084 ;
    END
  END b_d[310]
  PIN b_d[311]
    DIRECTION OUTPUT ;
    USE SIGNAL ;
    PORT
      LAYER M5 ;
        RECT  28.704 0 28.728 0.084 ;
    END
  END b_d[311]
  PIN b_d[312]
    DIRECTION OUTPUT ;
    USE SIGNAL ;
    PORT
      LAYER M5 ;
        RECT  28.752 0 28.776 0.084 ;
    END
  END b_d[312]
  PIN b_d[313]
    DIRECTION OUTPUT ;
    USE SIGNAL ;
    PORT
      LAYER M5 ;
        RECT  28.8 0 28.824 0.084 ;
    END
  END b_d[313]
  PIN b_d[314]
    DIRECTION OUTPUT ;
    USE SIGNAL ;
    PORT
      LAYER M5 ;
        RECT  28.848 0 28.872 0.084 ;
    END
  END b_d[314]
  PIN b_d[315]
    DIRECTION OUTPUT ;
    USE SIGNAL ;
    PORT
      LAYER M5 ;
        RECT  28.896 0 28.92 0.084 ;
    END
  END b_d[315]
  PIN b_d[316]
    DIRECTION OUTPUT ;
    USE SIGNAL ;
    PORT
      LAYER M5 ;
        RECT  28.944 0 28.968 0.084 ;
    END
  END b_d[316]
  PIN b_d[317]
    DIRECTION OUTPUT ;
    USE SIGNAL ;
    PORT
      LAYER M5 ;
        RECT  28.992 0 29.016 0.084 ;
    END
  END b_d[317]
  PIN b_d[318]
    DIRECTION OUTPUT ;
    USE SIGNAL ;
    PORT
      LAYER M5 ;
        RECT  29.04 0 29.064 0.084 ;
    END
  END b_d[318]
  PIN b_d[319]
    DIRECTION OUTPUT ;
    USE SIGNAL ;
    PORT
      LAYER M5 ;
        RECT  29.088 0 29.112 0.084 ;
    END
  END b_d[319]
  PIN b_d[31]
    DIRECTION OUTPUT ;
    USE SIGNAL ;
    PORT
      LAYER M5 ;
        RECT  15.264 0 15.288 0.084 ;
    END
  END b_d[31]
  PIN b_d[320]
    DIRECTION OUTPUT ;
    USE SIGNAL ;
    PORT
      LAYER M5 ;
        RECT  29.136 0 29.16 0.084 ;
    END
  END b_d[320]
  PIN b_d[321]
    DIRECTION OUTPUT ;
    USE SIGNAL ;
    PORT
      LAYER M5 ;
        RECT  29.184 0 29.208 0.084 ;
    END
  END b_d[321]
  PIN b_d[322]
    DIRECTION OUTPUT ;
    USE SIGNAL ;
    PORT
      LAYER M5 ;
        RECT  29.232 0 29.256 0.084 ;
    END
  END b_d[322]
  PIN b_d[323]
    DIRECTION OUTPUT ;
    USE SIGNAL ;
    PORT
      LAYER M5 ;
        RECT  29.28 0 29.304 0.084 ;
    END
  END b_d[323]
  PIN b_d[324]
    DIRECTION OUTPUT ;
    USE SIGNAL ;
    PORT
      LAYER M5 ;
        RECT  29.328 0 29.352 0.084 ;
    END
  END b_d[324]
  PIN b_d[325]
    DIRECTION OUTPUT ;
    USE SIGNAL ;
    PORT
      LAYER M5 ;
        RECT  29.376 0 29.4 0.084 ;
    END
  END b_d[325]
  PIN b_d[326]
    DIRECTION OUTPUT ;
    USE SIGNAL ;
    PORT
      LAYER M5 ;
        RECT  29.424 0 29.448 0.084 ;
    END
  END b_d[326]
  PIN b_d[327]
    DIRECTION OUTPUT ;
    USE SIGNAL ;
    PORT
      LAYER M5 ;
        RECT  29.472 0 29.496 0.084 ;
    END
  END b_d[327]
  PIN b_d[328]
    DIRECTION OUTPUT ;
    USE SIGNAL ;
    PORT
      LAYER M5 ;
        RECT  29.52 0 29.544 0.084 ;
    END
  END b_d[328]
  PIN b_d[329]
    DIRECTION OUTPUT ;
    USE SIGNAL ;
    PORT
      LAYER M5 ;
        RECT  29.568 0 29.592 0.084 ;
    END
  END b_d[329]
  PIN b_d[32]
    DIRECTION OUTPUT ;
    USE SIGNAL ;
    PORT
      LAYER M5 ;
        RECT  15.312 0 15.336 0.084 ;
    END
  END b_d[32]
  PIN b_d[330]
    DIRECTION OUTPUT ;
    USE SIGNAL ;
    PORT
      LAYER M5 ;
        RECT  29.616 0 29.64 0.084 ;
    END
  END b_d[330]
  PIN b_d[331]
    DIRECTION OUTPUT ;
    USE SIGNAL ;
    PORT
      LAYER M5 ;
        RECT  29.664 0 29.688 0.084 ;
    END
  END b_d[331]
  PIN b_d[332]
    DIRECTION OUTPUT ;
    USE SIGNAL ;
    PORT
      LAYER M5 ;
        RECT  29.712 0 29.736 0.084 ;
    END
  END b_d[332]
  PIN b_d[333]
    DIRECTION OUTPUT ;
    USE SIGNAL ;
    PORT
      LAYER M5 ;
        RECT  29.76 0 29.784 0.084 ;
    END
  END b_d[333]
  PIN b_d[334]
    DIRECTION OUTPUT ;
    USE SIGNAL ;
    PORT
      LAYER M5 ;
        RECT  29.808 0 29.832 0.084 ;
    END
  END b_d[334]
  PIN b_d[335]
    DIRECTION OUTPUT ;
    USE SIGNAL ;
    PORT
      LAYER M5 ;
        RECT  29.856 0 29.88 0.084 ;
    END
  END b_d[335]
  PIN b_d[336]
    DIRECTION OUTPUT ;
    USE SIGNAL ;
    PORT
      LAYER M5 ;
        RECT  29.904 0 29.928 0.084 ;
    END
  END b_d[336]
  PIN b_d[337]
    DIRECTION OUTPUT ;
    USE SIGNAL ;
    PORT
      LAYER M5 ;
        RECT  29.952 0 29.976 0.084 ;
    END
  END b_d[337]
  PIN b_d[338]
    DIRECTION OUTPUT ;
    USE SIGNAL ;
    PORT
      LAYER M5 ;
        RECT  30 0 30.024 0.084 ;
    END
  END b_d[338]
  PIN b_d[339]
    DIRECTION OUTPUT ;
    USE SIGNAL ;
    PORT
      LAYER M5 ;
        RECT  30.048 0 30.072 0.084 ;
    END
  END b_d[339]
  PIN b_d[33]
    DIRECTION OUTPUT ;
    USE SIGNAL ;
    PORT
      LAYER M5 ;
        RECT  15.36 0 15.384 0.084 ;
    END
  END b_d[33]
  PIN b_d[340]
    DIRECTION OUTPUT ;
    USE SIGNAL ;
    PORT
      LAYER M5 ;
        RECT  30.096 0 30.12 0.084 ;
    END
  END b_d[340]
  PIN b_d[341]
    DIRECTION OUTPUT ;
    USE SIGNAL ;
    PORT
      LAYER M5 ;
        RECT  30.144 0 30.168 0.084 ;
    END
  END b_d[341]
  PIN b_d[342]
    DIRECTION OUTPUT ;
    USE SIGNAL ;
    PORT
      LAYER M5 ;
        RECT  30.192 0 30.216 0.084 ;
    END
  END b_d[342]
  PIN b_d[343]
    DIRECTION OUTPUT ;
    USE SIGNAL ;
    PORT
      LAYER M5 ;
        RECT  30.24 0 30.264 0.084 ;
    END
  END b_d[343]
  PIN b_d[344]
    DIRECTION OUTPUT ;
    USE SIGNAL ;
    PORT
      LAYER M5 ;
        RECT  30.288 0 30.312 0.084 ;
    END
  END b_d[344]
  PIN b_d[345]
    DIRECTION OUTPUT ;
    USE SIGNAL ;
    PORT
      LAYER M5 ;
        RECT  30.336 0 30.36 0.084 ;
    END
  END b_d[345]
  PIN b_d[346]
    DIRECTION OUTPUT ;
    USE SIGNAL ;
    PORT
      LAYER M5 ;
        RECT  30.384 0 30.408 0.084 ;
    END
  END b_d[346]
  PIN b_d[347]
    DIRECTION OUTPUT ;
    USE SIGNAL ;
    PORT
      LAYER M5 ;
        RECT  30.432 0 30.456 0.084 ;
    END
  END b_d[347]
  PIN b_d[348]
    DIRECTION OUTPUT ;
    USE SIGNAL ;
    PORT
      LAYER M5 ;
        RECT  30.48 0 30.504 0.084 ;
    END
  END b_d[348]
  PIN b_d[349]
    DIRECTION OUTPUT ;
    USE SIGNAL ;
    PORT
      LAYER M5 ;
        RECT  30.528 0 30.552 0.084 ;
    END
  END b_d[349]
  PIN b_d[34]
    DIRECTION OUTPUT ;
    USE SIGNAL ;
    PORT
      LAYER M5 ;
        RECT  15.408 0 15.432 0.084 ;
    END
  END b_d[34]
  PIN b_d[350]
    DIRECTION OUTPUT ;
    USE SIGNAL ;
    PORT
      LAYER M5 ;
        RECT  30.576 0 30.6 0.084 ;
    END
  END b_d[350]
  PIN b_d[351]
    DIRECTION OUTPUT ;
    USE SIGNAL ;
    PORT
      LAYER M5 ;
        RECT  30.624 0 30.648 0.084 ;
    END
  END b_d[351]
  PIN b_d[352]
    DIRECTION OUTPUT ;
    USE SIGNAL ;
    PORT
      LAYER M5 ;
        RECT  30.672 0 30.696 0.084 ;
    END
  END b_d[352]
  PIN b_d[353]
    DIRECTION OUTPUT ;
    USE SIGNAL ;
    PORT
      LAYER M5 ;
        RECT  30.72 0 30.744 0.084 ;
    END
  END b_d[353]
  PIN b_d[354]
    DIRECTION OUTPUT ;
    USE SIGNAL ;
    PORT
      LAYER M5 ;
        RECT  30.768 0 30.792 0.084 ;
    END
  END b_d[354]
  PIN b_d[355]
    DIRECTION OUTPUT ;
    USE SIGNAL ;
    PORT
      LAYER M5 ;
        RECT  30.816 0 30.84 0.084 ;
    END
  END b_d[355]
  PIN b_d[356]
    DIRECTION OUTPUT ;
    USE SIGNAL ;
    PORT
      LAYER M5 ;
        RECT  30.864 0 30.888 0.084 ;
    END
  END b_d[356]
  PIN b_d[357]
    DIRECTION OUTPUT ;
    USE SIGNAL ;
    PORT
      LAYER M5 ;
        RECT  30.912 0 30.936 0.084 ;
    END
  END b_d[357]
  PIN b_d[358]
    DIRECTION OUTPUT ;
    USE SIGNAL ;
    PORT
      LAYER M5 ;
        RECT  30.96 0 30.984 0.084 ;
    END
  END b_d[358]
  PIN b_d[359]
    DIRECTION OUTPUT ;
    USE SIGNAL ;
    PORT
      LAYER M5 ;
        RECT  31.008 0 31.032 0.084 ;
    END
  END b_d[359]
  PIN b_d[35]
    DIRECTION OUTPUT ;
    USE SIGNAL ;
    PORT
      LAYER M5 ;
        RECT  15.456 0 15.48 0.084 ;
    END
  END b_d[35]
  PIN b_d[360]
    DIRECTION OUTPUT ;
    USE SIGNAL ;
    PORT
      LAYER M5 ;
        RECT  31.056 0 31.08 0.084 ;
    END
  END b_d[360]
  PIN b_d[361]
    DIRECTION OUTPUT ;
    USE SIGNAL ;
    PORT
      LAYER M5 ;
        RECT  31.104 0 31.128 0.084 ;
    END
  END b_d[361]
  PIN b_d[362]
    DIRECTION OUTPUT ;
    USE SIGNAL ;
    PORT
      LAYER M5 ;
        RECT  31.152 0 31.176 0.084 ;
    END
  END b_d[362]
  PIN b_d[363]
    DIRECTION OUTPUT ;
    USE SIGNAL ;
    PORT
      LAYER M5 ;
        RECT  31.2 0 31.224 0.084 ;
    END
  END b_d[363]
  PIN b_d[364]
    DIRECTION OUTPUT ;
    USE SIGNAL ;
    PORT
      LAYER M5 ;
        RECT  31.248 0 31.272 0.084 ;
    END
  END b_d[364]
  PIN b_d[365]
    DIRECTION OUTPUT ;
    USE SIGNAL ;
    PORT
      LAYER M5 ;
        RECT  31.296 0 31.32 0.084 ;
    END
  END b_d[365]
  PIN b_d[366]
    DIRECTION OUTPUT ;
    USE SIGNAL ;
    PORT
      LAYER M5 ;
        RECT  31.344 0 31.368 0.084 ;
    END
  END b_d[366]
  PIN b_d[367]
    DIRECTION OUTPUT ;
    USE SIGNAL ;
    PORT
      LAYER M5 ;
        RECT  31.392 0 31.416 0.084 ;
    END
  END b_d[367]
  PIN b_d[368]
    DIRECTION OUTPUT ;
    USE SIGNAL ;
    PORT
      LAYER M5 ;
        RECT  31.44 0 31.464 0.084 ;
    END
  END b_d[368]
  PIN b_d[369]
    DIRECTION OUTPUT ;
    USE SIGNAL ;
    PORT
      LAYER M5 ;
        RECT  31.488 0 31.512 0.084 ;
    END
  END b_d[369]
  PIN b_d[36]
    DIRECTION OUTPUT ;
    USE SIGNAL ;
    PORT
      LAYER M5 ;
        RECT  15.504 0 15.528 0.084 ;
    END
  END b_d[36]
  PIN b_d[370]
    DIRECTION OUTPUT ;
    USE SIGNAL ;
    PORT
      LAYER M5 ;
        RECT  31.536 0 31.56 0.084 ;
    END
  END b_d[370]
  PIN b_d[371]
    DIRECTION OUTPUT ;
    USE SIGNAL ;
    PORT
      LAYER M5 ;
        RECT  31.584 0 31.608 0.084 ;
    END
  END b_d[371]
  PIN b_d[372]
    DIRECTION OUTPUT ;
    USE SIGNAL ;
    PORT
      LAYER M5 ;
        RECT  31.632 0 31.656 0.084 ;
    END
  END b_d[372]
  PIN b_d[373]
    DIRECTION OUTPUT ;
    USE SIGNAL ;
    PORT
      LAYER M5 ;
        RECT  31.68 0 31.704 0.084 ;
    END
  END b_d[373]
  PIN b_d[374]
    DIRECTION OUTPUT ;
    USE SIGNAL ;
    PORT
      LAYER M5 ;
        RECT  31.728 0 31.752 0.084 ;
    END
  END b_d[374]
  PIN b_d[375]
    DIRECTION OUTPUT ;
    USE SIGNAL ;
    PORT
      LAYER M5 ;
        RECT  31.776 0 31.8 0.084 ;
    END
  END b_d[375]
  PIN b_d[376]
    DIRECTION OUTPUT ;
    USE SIGNAL ;
    PORT
      LAYER M5 ;
        RECT  31.824 0 31.848 0.084 ;
    END
  END b_d[376]
  PIN b_d[377]
    DIRECTION OUTPUT ;
    USE SIGNAL ;
    PORT
      LAYER M5 ;
        RECT  31.872 0 31.896 0.084 ;
    END
  END b_d[377]
  PIN b_d[378]
    DIRECTION OUTPUT ;
    USE SIGNAL ;
    PORT
      LAYER M5 ;
        RECT  31.92 0 31.944 0.084 ;
    END
  END b_d[378]
  PIN b_d[379]
    DIRECTION OUTPUT ;
    USE SIGNAL ;
    PORT
      LAYER M5 ;
        RECT  31.968 0 31.992 0.084 ;
    END
  END b_d[379]
  PIN b_d[37]
    DIRECTION OUTPUT ;
    USE SIGNAL ;
    PORT
      LAYER M5 ;
        RECT  15.552 0 15.576 0.084 ;
    END
  END b_d[37]
  PIN b_d[380]
    DIRECTION OUTPUT ;
    USE SIGNAL ;
    PORT
      LAYER M5 ;
        RECT  32.016 0 32.04 0.084 ;
    END
  END b_d[380]
  PIN b_d[381]
    DIRECTION OUTPUT ;
    USE SIGNAL ;
    PORT
      LAYER M5 ;
        RECT  32.064 0 32.088 0.084 ;
    END
  END b_d[381]
  PIN b_d[382]
    DIRECTION OUTPUT ;
    USE SIGNAL ;
    PORT
      LAYER M5 ;
        RECT  32.112 0 32.136 0.084 ;
    END
  END b_d[382]
  PIN b_d[383]
    DIRECTION OUTPUT ;
    USE SIGNAL ;
    PORT
      LAYER M5 ;
        RECT  32.16 0 32.184 0.084 ;
    END
  END b_d[383]
  PIN b_d[384]
    DIRECTION OUTPUT ;
    USE SIGNAL ;
    PORT
      LAYER M5 ;
        RECT  32.208 0 32.232 0.084 ;
    END
  END b_d[384]
  PIN b_d[385]
    DIRECTION OUTPUT ;
    USE SIGNAL ;
    PORT
      LAYER M5 ;
        RECT  32.256 0 32.28 0.084 ;
    END
  END b_d[385]
  PIN b_d[386]
    DIRECTION OUTPUT ;
    USE SIGNAL ;
    PORT
      LAYER M5 ;
        RECT  32.304 0 32.328 0.084 ;
    END
  END b_d[386]
  PIN b_d[387]
    DIRECTION OUTPUT ;
    USE SIGNAL ;
    PORT
      LAYER M5 ;
        RECT  32.352 0 32.376 0.084 ;
    END
  END b_d[387]
  PIN b_d[388]
    DIRECTION OUTPUT ;
    USE SIGNAL ;
    PORT
      LAYER M5 ;
        RECT  32.4 0 32.424 0.084 ;
    END
  END b_d[388]
  PIN b_d[389]
    DIRECTION OUTPUT ;
    USE SIGNAL ;
    PORT
      LAYER M5 ;
        RECT  32.448 0 32.472 0.084 ;
    END
  END b_d[389]
  PIN b_d[38]
    DIRECTION OUTPUT ;
    USE SIGNAL ;
    PORT
      LAYER M5 ;
        RECT  15.6 0 15.624 0.084 ;
    END
  END b_d[38]
  PIN b_d[390]
    DIRECTION OUTPUT ;
    USE SIGNAL ;
    PORT
      LAYER M5 ;
        RECT  32.496 0 32.52 0.084 ;
    END
  END b_d[390]
  PIN b_d[391]
    DIRECTION OUTPUT ;
    USE SIGNAL ;
    PORT
      LAYER M5 ;
        RECT  32.544 0 32.568 0.084 ;
    END
  END b_d[391]
  PIN b_d[392]
    DIRECTION OUTPUT ;
    USE SIGNAL ;
    PORT
      LAYER M5 ;
        RECT  32.592 0 32.616 0.084 ;
    END
  END b_d[392]
  PIN b_d[393]
    DIRECTION OUTPUT ;
    USE SIGNAL ;
    PORT
      LAYER M5 ;
        RECT  32.64 0 32.664 0.084 ;
    END
  END b_d[393]
  PIN b_d[394]
    DIRECTION OUTPUT ;
    USE SIGNAL ;
    PORT
      LAYER M5 ;
        RECT  32.688 0 32.712 0.084 ;
    END
  END b_d[394]
  PIN b_d[395]
    DIRECTION OUTPUT ;
    USE SIGNAL ;
    PORT
      LAYER M5 ;
        RECT  32.736 0 32.76 0.084 ;
    END
  END b_d[395]
  PIN b_d[396]
    DIRECTION OUTPUT ;
    USE SIGNAL ;
    PORT
      LAYER M5 ;
        RECT  32.784 0 32.808 0.084 ;
    END
  END b_d[396]
  PIN b_d[397]
    DIRECTION OUTPUT ;
    USE SIGNAL ;
    PORT
      LAYER M5 ;
        RECT  32.832 0 32.856 0.084 ;
    END
  END b_d[397]
  PIN b_d[398]
    DIRECTION OUTPUT ;
    USE SIGNAL ;
    PORT
      LAYER M5 ;
        RECT  32.88 0 32.904 0.084 ;
    END
  END b_d[398]
  PIN b_d[399]
    DIRECTION OUTPUT ;
    USE SIGNAL ;
    PORT
      LAYER M5 ;
        RECT  32.928 0 32.952 0.084 ;
    END
  END b_d[399]
  PIN b_d[39]
    DIRECTION OUTPUT ;
    USE SIGNAL ;
    PORT
      LAYER M5 ;
        RECT  15.648 0 15.672 0.084 ;
    END
  END b_d[39]
  PIN b_d[3]
    DIRECTION OUTPUT ;
    USE SIGNAL ;
    PORT
      LAYER M5 ;
        RECT  13.92 0 13.944 0.084 ;
    END
  END b_d[3]
  PIN b_d[400]
    DIRECTION OUTPUT ;
    USE SIGNAL ;
    PORT
      LAYER M5 ;
        RECT  32.976 0 33 0.084 ;
    END
  END b_d[400]
  PIN b_d[401]
    DIRECTION OUTPUT ;
    USE SIGNAL ;
    PORT
      LAYER M5 ;
        RECT  33.024 0 33.048 0.084 ;
    END
  END b_d[401]
  PIN b_d[402]
    DIRECTION OUTPUT ;
    USE SIGNAL ;
    PORT
      LAYER M5 ;
        RECT  33.072 0 33.096 0.084 ;
    END
  END b_d[402]
  PIN b_d[403]
    DIRECTION OUTPUT ;
    USE SIGNAL ;
    PORT
      LAYER M5 ;
        RECT  33.12 0 33.144 0.084 ;
    END
  END b_d[403]
  PIN b_d[404]
    DIRECTION OUTPUT ;
    USE SIGNAL ;
    PORT
      LAYER M5 ;
        RECT  33.168 0 33.192 0.084 ;
    END
  END b_d[404]
  PIN b_d[405]
    DIRECTION OUTPUT ;
    USE SIGNAL ;
    PORT
      LAYER M5 ;
        RECT  33.216 0 33.24 0.084 ;
    END
  END b_d[405]
  PIN b_d[406]
    DIRECTION OUTPUT ;
    USE SIGNAL ;
    PORT
      LAYER M5 ;
        RECT  33.264 0 33.288 0.084 ;
    END
  END b_d[406]
  PIN b_d[407]
    DIRECTION OUTPUT ;
    USE SIGNAL ;
    PORT
      LAYER M5 ;
        RECT  33.312 0 33.336 0.084 ;
    END
  END b_d[407]
  PIN b_d[408]
    DIRECTION OUTPUT ;
    USE SIGNAL ;
    PORT
      LAYER M5 ;
        RECT  33.36 0 33.384 0.084 ;
    END
  END b_d[408]
  PIN b_d[409]
    DIRECTION OUTPUT ;
    USE SIGNAL ;
    PORT
      LAYER M5 ;
        RECT  33.408 0 33.432 0.084 ;
    END
  END b_d[409]
  PIN b_d[40]
    DIRECTION OUTPUT ;
    USE SIGNAL ;
    PORT
      LAYER M5 ;
        RECT  15.696 0 15.72 0.084 ;
    END
  END b_d[40]
  PIN b_d[410]
    DIRECTION OUTPUT ;
    USE SIGNAL ;
    PORT
      LAYER M5 ;
        RECT  33.456 0 33.48 0.084 ;
    END
  END b_d[410]
  PIN b_d[411]
    DIRECTION OUTPUT ;
    USE SIGNAL ;
    PORT
      LAYER M5 ;
        RECT  33.504 0 33.528 0.084 ;
    END
  END b_d[411]
  PIN b_d[412]
    DIRECTION OUTPUT ;
    USE SIGNAL ;
    PORT
      LAYER M5 ;
        RECT  33.552 0 33.576 0.084 ;
    END
  END b_d[412]
  PIN b_d[413]
    DIRECTION OUTPUT ;
    USE SIGNAL ;
    PORT
      LAYER M5 ;
        RECT  33.6 0 33.624 0.084 ;
    END
  END b_d[413]
  PIN b_d[414]
    DIRECTION OUTPUT ;
    USE SIGNAL ;
    PORT
      LAYER M5 ;
        RECT  33.648 0 33.672 0.084 ;
    END
  END b_d[414]
  PIN b_d[415]
    DIRECTION OUTPUT ;
    USE SIGNAL ;
    PORT
      LAYER M5 ;
        RECT  33.696 0 33.72 0.084 ;
    END
  END b_d[415]
  PIN b_d[416]
    DIRECTION OUTPUT ;
    USE SIGNAL ;
    PORT
      LAYER M5 ;
        RECT  33.744 0 33.768 0.084 ;
    END
  END b_d[416]
  PIN b_d[417]
    DIRECTION OUTPUT ;
    USE SIGNAL ;
    PORT
      LAYER M5 ;
        RECT  33.792 0 33.816 0.084 ;
    END
  END b_d[417]
  PIN b_d[418]
    DIRECTION OUTPUT ;
    USE SIGNAL ;
    PORT
      LAYER M5 ;
        RECT  33.84 0 33.864 0.084 ;
    END
  END b_d[418]
  PIN b_d[419]
    DIRECTION OUTPUT ;
    USE SIGNAL ;
    PORT
      LAYER M5 ;
        RECT  33.888 0 33.912 0.084 ;
    END
  END b_d[419]
  PIN b_d[41]
    DIRECTION OUTPUT ;
    USE SIGNAL ;
    PORT
      LAYER M5 ;
        RECT  15.744 0 15.768 0.084 ;
    END
  END b_d[41]
  PIN b_d[420]
    DIRECTION OUTPUT ;
    USE SIGNAL ;
    PORT
      LAYER M5 ;
        RECT  33.936 0 33.96 0.084 ;
    END
  END b_d[420]
  PIN b_d[421]
    DIRECTION OUTPUT ;
    USE SIGNAL ;
    PORT
      LAYER M5 ;
        RECT  33.984 0 34.008 0.084 ;
    END
  END b_d[421]
  PIN b_d[422]
    DIRECTION OUTPUT ;
    USE SIGNAL ;
    PORT
      LAYER M5 ;
        RECT  34.032 0 34.056 0.084 ;
    END
  END b_d[422]
  PIN b_d[423]
    DIRECTION OUTPUT ;
    USE SIGNAL ;
    PORT
      LAYER M5 ;
        RECT  34.08 0 34.104 0.084 ;
    END
  END b_d[423]
  PIN b_d[424]
    DIRECTION OUTPUT ;
    USE SIGNAL ;
    PORT
      LAYER M5 ;
        RECT  34.128 0 34.152 0.084 ;
    END
  END b_d[424]
  PIN b_d[425]
    DIRECTION OUTPUT ;
    USE SIGNAL ;
    PORT
      LAYER M5 ;
        RECT  34.176 0 34.2 0.084 ;
    END
  END b_d[425]
  PIN b_d[426]
    DIRECTION OUTPUT ;
    USE SIGNAL ;
    PORT
      LAYER M5 ;
        RECT  34.224 0 34.248 0.084 ;
    END
  END b_d[426]
  PIN b_d[427]
    DIRECTION OUTPUT ;
    USE SIGNAL ;
    PORT
      LAYER M5 ;
        RECT  34.272 0 34.296 0.084 ;
    END
  END b_d[427]
  PIN b_d[428]
    DIRECTION OUTPUT ;
    USE SIGNAL ;
    PORT
      LAYER M5 ;
        RECT  34.32 0 34.344 0.084 ;
    END
  END b_d[428]
  PIN b_d[429]
    DIRECTION OUTPUT ;
    USE SIGNAL ;
    PORT
      LAYER M5 ;
        RECT  34.368 0 34.392 0.084 ;
    END
  END b_d[429]
  PIN b_d[42]
    DIRECTION OUTPUT ;
    USE SIGNAL ;
    PORT
      LAYER M5 ;
        RECT  15.792 0 15.816 0.084 ;
    END
  END b_d[42]
  PIN b_d[430]
    DIRECTION OUTPUT ;
    USE SIGNAL ;
    PORT
      LAYER M5 ;
        RECT  34.416 0 34.44 0.084 ;
    END
  END b_d[430]
  PIN b_d[431]
    DIRECTION OUTPUT ;
    USE SIGNAL ;
    PORT
      LAYER M5 ;
        RECT  34.464 0 34.488 0.084 ;
    END
  END b_d[431]
  PIN b_d[432]
    DIRECTION OUTPUT ;
    USE SIGNAL ;
    PORT
      LAYER M5 ;
        RECT  34.512 0 34.536 0.084 ;
    END
  END b_d[432]
  PIN b_d[433]
    DIRECTION OUTPUT ;
    USE SIGNAL ;
    PORT
      LAYER M5 ;
        RECT  34.56 0 34.584 0.084 ;
    END
  END b_d[433]
  PIN b_d[434]
    DIRECTION OUTPUT ;
    USE SIGNAL ;
    PORT
      LAYER M5 ;
        RECT  34.608 0 34.632 0.084 ;
    END
  END b_d[434]
  PIN b_d[435]
    DIRECTION OUTPUT ;
    USE SIGNAL ;
    PORT
      LAYER M5 ;
        RECT  34.656 0 34.68 0.084 ;
    END
  END b_d[435]
  PIN b_d[436]
    DIRECTION OUTPUT ;
    USE SIGNAL ;
    PORT
      LAYER M5 ;
        RECT  34.704 0 34.728 0.084 ;
    END
  END b_d[436]
  PIN b_d[437]
    DIRECTION OUTPUT ;
    USE SIGNAL ;
    PORT
      LAYER M5 ;
        RECT  34.752 0 34.776 0.084 ;
    END
  END b_d[437]
  PIN b_d[438]
    DIRECTION OUTPUT ;
    USE SIGNAL ;
    PORT
      LAYER M5 ;
        RECT  34.8 0 34.824 0.084 ;
    END
  END b_d[438]
  PIN b_d[439]
    DIRECTION OUTPUT ;
    USE SIGNAL ;
    PORT
      LAYER M5 ;
        RECT  34.848 0 34.872 0.084 ;
    END
  END b_d[439]
  PIN b_d[43]
    DIRECTION OUTPUT ;
    USE SIGNAL ;
    PORT
      LAYER M5 ;
        RECT  15.84 0 15.864 0.084 ;
    END
  END b_d[43]
  PIN b_d[440]
    DIRECTION OUTPUT ;
    USE SIGNAL ;
    PORT
      LAYER M5 ;
        RECT  34.896 0 34.92 0.084 ;
    END
  END b_d[440]
  PIN b_d[441]
    DIRECTION OUTPUT ;
    USE SIGNAL ;
    PORT
      LAYER M5 ;
        RECT  34.944 0 34.968 0.084 ;
    END
  END b_d[441]
  PIN b_d[442]
    DIRECTION OUTPUT ;
    USE SIGNAL ;
    PORT
      LAYER M5 ;
        RECT  34.992 0 35.016 0.084 ;
    END
  END b_d[442]
  PIN b_d[443]
    DIRECTION OUTPUT ;
    USE SIGNAL ;
    PORT
      LAYER M5 ;
        RECT  35.04 0 35.064 0.084 ;
    END
  END b_d[443]
  PIN b_d[444]
    DIRECTION OUTPUT ;
    USE SIGNAL ;
    PORT
      LAYER M5 ;
        RECT  35.088 0 35.112 0.084 ;
    END
  END b_d[444]
  PIN b_d[445]
    DIRECTION OUTPUT ;
    USE SIGNAL ;
    PORT
      LAYER M5 ;
        RECT  35.136 0 35.16 0.084 ;
    END
  END b_d[445]
  PIN b_d[446]
    DIRECTION OUTPUT ;
    USE SIGNAL ;
    PORT
      LAYER M5 ;
        RECT  35.184 0 35.208 0.084 ;
    END
  END b_d[446]
  PIN b_d[447]
    DIRECTION OUTPUT ;
    USE SIGNAL ;
    PORT
      LAYER M5 ;
        RECT  35.232 0 35.256 0.084 ;
    END
  END b_d[447]
  PIN b_d[448]
    DIRECTION OUTPUT ;
    USE SIGNAL ;
    PORT
      LAYER M5 ;
        RECT  35.28 0 35.304 0.084 ;
    END
  END b_d[448]
  PIN b_d[449]
    DIRECTION OUTPUT ;
    USE SIGNAL ;
    PORT
      LAYER M5 ;
        RECT  35.328 0 35.352 0.084 ;
    END
  END b_d[449]
  PIN b_d[44]
    DIRECTION OUTPUT ;
    USE SIGNAL ;
    PORT
      LAYER M5 ;
        RECT  15.888 0 15.912 0.084 ;
    END
  END b_d[44]
  PIN b_d[450]
    DIRECTION OUTPUT ;
    USE SIGNAL ;
    PORT
      LAYER M5 ;
        RECT  35.376 0 35.4 0.084 ;
    END
  END b_d[450]
  PIN b_d[451]
    DIRECTION OUTPUT ;
    USE SIGNAL ;
    PORT
      LAYER M5 ;
        RECT  35.424 0 35.448 0.084 ;
    END
  END b_d[451]
  PIN b_d[452]
    DIRECTION OUTPUT ;
    USE SIGNAL ;
    PORT
      LAYER M5 ;
        RECT  35.472 0 35.496 0.084 ;
    END
  END b_d[452]
  PIN b_d[453]
    DIRECTION OUTPUT ;
    USE SIGNAL ;
    PORT
      LAYER M5 ;
        RECT  35.52 0 35.544 0.084 ;
    END
  END b_d[453]
  PIN b_d[454]
    DIRECTION OUTPUT ;
    USE SIGNAL ;
    PORT
      LAYER M5 ;
        RECT  35.568 0 35.592 0.084 ;
    END
  END b_d[454]
  PIN b_d[455]
    DIRECTION OUTPUT ;
    USE SIGNAL ;
    PORT
      LAYER M5 ;
        RECT  35.616 0 35.64 0.084 ;
    END
  END b_d[455]
  PIN b_d[456]
    DIRECTION OUTPUT ;
    USE SIGNAL ;
    PORT
      LAYER M5 ;
        RECT  35.664 0 35.688 0.084 ;
    END
  END b_d[456]
  PIN b_d[457]
    DIRECTION OUTPUT ;
    USE SIGNAL ;
    PORT
      LAYER M5 ;
        RECT  35.712 0 35.736 0.084 ;
    END
  END b_d[457]
  PIN b_d[458]
    DIRECTION OUTPUT ;
    USE SIGNAL ;
    PORT
      LAYER M5 ;
        RECT  35.76 0 35.784 0.084 ;
    END
  END b_d[458]
  PIN b_d[459]
    DIRECTION OUTPUT ;
    USE SIGNAL ;
    PORT
      LAYER M5 ;
        RECT  35.808 0 35.832 0.084 ;
    END
  END b_d[459]
  PIN b_d[45]
    DIRECTION OUTPUT ;
    USE SIGNAL ;
    PORT
      LAYER M5 ;
        RECT  15.936 0 15.96 0.084 ;
    END
  END b_d[45]
  PIN b_d[460]
    DIRECTION OUTPUT ;
    USE SIGNAL ;
    PORT
      LAYER M5 ;
        RECT  35.856 0 35.88 0.084 ;
    END
  END b_d[460]
  PIN b_d[461]
    DIRECTION OUTPUT ;
    USE SIGNAL ;
    PORT
      LAYER M5 ;
        RECT  35.904 0 35.928 0.084 ;
    END
  END b_d[461]
  PIN b_d[462]
    DIRECTION OUTPUT ;
    USE SIGNAL ;
    PORT
      LAYER M5 ;
        RECT  35.952 0 35.976 0.084 ;
    END
  END b_d[462]
  PIN b_d[463]
    DIRECTION OUTPUT ;
    USE SIGNAL ;
    PORT
      LAYER M5 ;
        RECT  36 0 36.024 0.084 ;
    END
  END b_d[463]
  PIN b_d[464]
    DIRECTION OUTPUT ;
    USE SIGNAL ;
    PORT
      LAYER M5 ;
        RECT  36.048 0 36.072 0.084 ;
    END
  END b_d[464]
  PIN b_d[465]
    DIRECTION OUTPUT ;
    USE SIGNAL ;
    PORT
      LAYER M5 ;
        RECT  36.096 0 36.12 0.084 ;
    END
  END b_d[465]
  PIN b_d[466]
    DIRECTION OUTPUT ;
    USE SIGNAL ;
    PORT
      LAYER M5 ;
        RECT  36.144 0 36.168 0.084 ;
    END
  END b_d[466]
  PIN b_d[467]
    DIRECTION OUTPUT ;
    USE SIGNAL ;
    PORT
      LAYER M5 ;
        RECT  36.192 0 36.216 0.084 ;
    END
  END b_d[467]
  PIN b_d[468]
    DIRECTION OUTPUT ;
    USE SIGNAL ;
    PORT
      LAYER M5 ;
        RECT  36.24 0 36.264 0.084 ;
    END
  END b_d[468]
  PIN b_d[469]
    DIRECTION OUTPUT ;
    USE SIGNAL ;
    PORT
      LAYER M5 ;
        RECT  36.288 0 36.312 0.084 ;
    END
  END b_d[469]
  PIN b_d[46]
    DIRECTION OUTPUT ;
    USE SIGNAL ;
    PORT
      LAYER M5 ;
        RECT  15.984 0 16.008 0.084 ;
    END
  END b_d[46]
  PIN b_d[470]
    DIRECTION OUTPUT ;
    USE SIGNAL ;
    PORT
      LAYER M5 ;
        RECT  36.336 0 36.36 0.084 ;
    END
  END b_d[470]
  PIN b_d[471]
    DIRECTION OUTPUT ;
    USE SIGNAL ;
    PORT
      LAYER M5 ;
        RECT  36.384 0 36.408 0.084 ;
    END
  END b_d[471]
  PIN b_d[472]
    DIRECTION OUTPUT ;
    USE SIGNAL ;
    PORT
      LAYER M5 ;
        RECT  36.432 0 36.456 0.084 ;
    END
  END b_d[472]
  PIN b_d[473]
    DIRECTION OUTPUT ;
    USE SIGNAL ;
    PORT
      LAYER M5 ;
        RECT  36.48 0 36.504 0.084 ;
    END
  END b_d[473]
  PIN b_d[474]
    DIRECTION OUTPUT ;
    USE SIGNAL ;
    PORT
      LAYER M5 ;
        RECT  36.528 0 36.552 0.084 ;
    END
  END b_d[474]
  PIN b_d[475]
    DIRECTION OUTPUT ;
    USE SIGNAL ;
    PORT
      LAYER M5 ;
        RECT  36.576 0 36.6 0.084 ;
    END
  END b_d[475]
  PIN b_d[476]
    DIRECTION OUTPUT ;
    USE SIGNAL ;
    PORT
      LAYER M5 ;
        RECT  36.624 0 36.648 0.084 ;
    END
  END b_d[476]
  PIN b_d[477]
    DIRECTION OUTPUT ;
    USE SIGNAL ;
    PORT
      LAYER M5 ;
        RECT  36.672 0 36.696 0.084 ;
    END
  END b_d[477]
  PIN b_d[478]
    DIRECTION OUTPUT ;
    USE SIGNAL ;
    PORT
      LAYER M5 ;
        RECT  36.72 0 36.744 0.084 ;
    END
  END b_d[478]
  PIN b_d[479]
    DIRECTION OUTPUT ;
    USE SIGNAL ;
    PORT
      LAYER M5 ;
        RECT  36.768 0 36.792 0.084 ;
    END
  END b_d[479]
  PIN b_d[47]
    DIRECTION OUTPUT ;
    USE SIGNAL ;
    PORT
      LAYER M5 ;
        RECT  16.032 0 16.056 0.084 ;
    END
  END b_d[47]
  PIN b_d[480]
    DIRECTION OUTPUT ;
    USE SIGNAL ;
    PORT
      LAYER M5 ;
        RECT  36.816 0 36.84 0.084 ;
    END
  END b_d[480]
  PIN b_d[481]
    DIRECTION OUTPUT ;
    USE SIGNAL ;
    PORT
      LAYER M5 ;
        RECT  36.864 0 36.888 0.084 ;
    END
  END b_d[481]
  PIN b_d[482]
    DIRECTION OUTPUT ;
    USE SIGNAL ;
    PORT
      LAYER M5 ;
        RECT  36.912 0 36.936 0.084 ;
    END
  END b_d[482]
  PIN b_d[483]
    DIRECTION OUTPUT ;
    USE SIGNAL ;
    PORT
      LAYER M5 ;
        RECT  36.96 0 36.984 0.084 ;
    END
  END b_d[483]
  PIN b_d[484]
    DIRECTION OUTPUT ;
    USE SIGNAL ;
    PORT
      LAYER M5 ;
        RECT  37.008 0 37.032 0.084 ;
    END
  END b_d[484]
  PIN b_d[485]
    DIRECTION OUTPUT ;
    USE SIGNAL ;
    PORT
      LAYER M5 ;
        RECT  37.056 0 37.08 0.084 ;
    END
  END b_d[485]
  PIN b_d[486]
    DIRECTION OUTPUT ;
    USE SIGNAL ;
    PORT
      LAYER M5 ;
        RECT  37.104 0 37.128 0.084 ;
    END
  END b_d[486]
  PIN b_d[487]
    DIRECTION OUTPUT ;
    USE SIGNAL ;
    PORT
      LAYER M5 ;
        RECT  37.152 0 37.176 0.084 ;
    END
  END b_d[487]
  PIN b_d[488]
    DIRECTION OUTPUT ;
    USE SIGNAL ;
    PORT
      LAYER M5 ;
        RECT  37.2 0 37.224 0.084 ;
    END
  END b_d[488]
  PIN b_d[489]
    DIRECTION OUTPUT ;
    USE SIGNAL ;
    PORT
      LAYER M5 ;
        RECT  37.248 0 37.272 0.084 ;
    END
  END b_d[489]
  PIN b_d[48]
    DIRECTION OUTPUT ;
    USE SIGNAL ;
    PORT
      LAYER M5 ;
        RECT  16.08 0 16.104 0.084 ;
    END
  END b_d[48]
  PIN b_d[490]
    DIRECTION OUTPUT ;
    USE SIGNAL ;
    PORT
      LAYER M5 ;
        RECT  37.296 0 37.32 0.084 ;
    END
  END b_d[490]
  PIN b_d[491]
    DIRECTION OUTPUT ;
    USE SIGNAL ;
    PORT
      LAYER M5 ;
        RECT  37.344 0 37.368 0.084 ;
    END
  END b_d[491]
  PIN b_d[492]
    DIRECTION OUTPUT ;
    USE SIGNAL ;
    PORT
      LAYER M5 ;
        RECT  37.392 0 37.416 0.084 ;
    END
  END b_d[492]
  PIN b_d[493]
    DIRECTION OUTPUT ;
    USE SIGNAL ;
    PORT
      LAYER M5 ;
        RECT  37.44 0 37.464 0.084 ;
    END
  END b_d[493]
  PIN b_d[494]
    DIRECTION OUTPUT ;
    USE SIGNAL ;
    PORT
      LAYER M5 ;
        RECT  37.488 0 37.512 0.084 ;
    END
  END b_d[494]
  PIN b_d[495]
    DIRECTION OUTPUT ;
    USE SIGNAL ;
    PORT
      LAYER M5 ;
        RECT  37.536 0 37.56 0.084 ;
    END
  END b_d[495]
  PIN b_d[496]
    DIRECTION OUTPUT ;
    USE SIGNAL ;
    PORT
      LAYER M5 ;
        RECT  37.584 0 37.608 0.084 ;
    END
  END b_d[496]
  PIN b_d[497]
    DIRECTION OUTPUT ;
    USE SIGNAL ;
    PORT
      LAYER M5 ;
        RECT  37.632 0 37.656 0.084 ;
    END
  END b_d[497]
  PIN b_d[498]
    DIRECTION OUTPUT ;
    USE SIGNAL ;
    PORT
      LAYER M5 ;
        RECT  37.68 0 37.704 0.084 ;
    END
  END b_d[498]
  PIN b_d[499]
    DIRECTION OUTPUT ;
    USE SIGNAL ;
    PORT
      LAYER M5 ;
        RECT  37.728 0 37.752 0.084 ;
    END
  END b_d[499]
  PIN b_d[49]
    DIRECTION OUTPUT ;
    USE SIGNAL ;
    PORT
      LAYER M5 ;
        RECT  16.128 0 16.152 0.084 ;
    END
  END b_d[49]
  PIN b_d[4]
    DIRECTION OUTPUT ;
    USE SIGNAL ;
    PORT
      LAYER M5 ;
        RECT  13.968 0 13.992 0.084 ;
    END
  END b_d[4]
  PIN b_d[500]
    DIRECTION OUTPUT ;
    USE SIGNAL ;
    PORT
      LAYER M5 ;
        RECT  37.776 0 37.8 0.084 ;
    END
  END b_d[500]
  PIN b_d[501]
    DIRECTION OUTPUT ;
    USE SIGNAL ;
    PORT
      LAYER M5 ;
        RECT  37.824 0 37.848 0.084 ;
    END
  END b_d[501]
  PIN b_d[502]
    DIRECTION OUTPUT ;
    USE SIGNAL ;
    PORT
      LAYER M5 ;
        RECT  37.872 0 37.896 0.084 ;
    END
  END b_d[502]
  PIN b_d[503]
    DIRECTION OUTPUT ;
    USE SIGNAL ;
    PORT
      LAYER M5 ;
        RECT  37.92 0 37.944 0.084 ;
    END
  END b_d[503]
  PIN b_d[504]
    DIRECTION OUTPUT ;
    USE SIGNAL ;
    PORT
      LAYER M5 ;
        RECT  37.968 0 37.992 0.084 ;
    END
  END b_d[504]
  PIN b_d[505]
    DIRECTION OUTPUT ;
    USE SIGNAL ;
    PORT
      LAYER M5 ;
        RECT  38.016 0 38.04 0.084 ;
    END
  END b_d[505]
  PIN b_d[506]
    DIRECTION OUTPUT ;
    USE SIGNAL ;
    PORT
      LAYER M5 ;
        RECT  38.064 0 38.088 0.084 ;
    END
  END b_d[506]
  PIN b_d[507]
    DIRECTION OUTPUT ;
    USE SIGNAL ;
    PORT
      LAYER M5 ;
        RECT  38.112 0 38.136 0.084 ;
    END
  END b_d[507]
  PIN b_d[50]
    DIRECTION OUTPUT ;
    USE SIGNAL ;
    PORT
      LAYER M5 ;
        RECT  16.176 0 16.2 0.084 ;
    END
  END b_d[50]
  PIN b_d[51]
    DIRECTION OUTPUT ;
    USE SIGNAL ;
    PORT
      LAYER M5 ;
        RECT  16.224 0 16.248 0.084 ;
    END
  END b_d[51]
  PIN b_d[52]
    DIRECTION OUTPUT ;
    USE SIGNAL ;
    PORT
      LAYER M5 ;
        RECT  16.272 0 16.296 0.084 ;
    END
  END b_d[52]
  PIN b_d[53]
    DIRECTION OUTPUT ;
    USE SIGNAL ;
    PORT
      LAYER M5 ;
        RECT  16.32 0 16.344 0.084 ;
    END
  END b_d[53]
  PIN b_d[54]
    DIRECTION OUTPUT ;
    USE SIGNAL ;
    PORT
      LAYER M5 ;
        RECT  16.368 0 16.392 0.084 ;
    END
  END b_d[54]
  PIN b_d[55]
    DIRECTION OUTPUT ;
    USE SIGNAL ;
    PORT
      LAYER M5 ;
        RECT  16.416 0 16.44 0.084 ;
    END
  END b_d[55]
  PIN b_d[56]
    DIRECTION OUTPUT ;
    USE SIGNAL ;
    PORT
      LAYER M5 ;
        RECT  16.464 0 16.488 0.084 ;
    END
  END b_d[56]
  PIN b_d[57]
    DIRECTION OUTPUT ;
    USE SIGNAL ;
    PORT
      LAYER M5 ;
        RECT  16.512 0 16.536 0.084 ;
    END
  END b_d[57]
  PIN b_d[58]
    DIRECTION OUTPUT ;
    USE SIGNAL ;
    PORT
      LAYER M5 ;
        RECT  16.56 0 16.584 0.084 ;
    END
  END b_d[58]
  PIN b_d[59]
    DIRECTION OUTPUT ;
    USE SIGNAL ;
    PORT
      LAYER M5 ;
        RECT  16.608 0 16.632 0.084 ;
    END
  END b_d[59]
  PIN b_d[5]
    DIRECTION OUTPUT ;
    USE SIGNAL ;
    PORT
      LAYER M5 ;
        RECT  14.016 0 14.04 0.084 ;
    END
  END b_d[5]
  PIN b_d[60]
    DIRECTION OUTPUT ;
    USE SIGNAL ;
    PORT
      LAYER M5 ;
        RECT  16.656 0 16.68 0.084 ;
    END
  END b_d[60]
  PIN b_d[61]
    DIRECTION OUTPUT ;
    USE SIGNAL ;
    PORT
      LAYER M5 ;
        RECT  16.704 0 16.728 0.084 ;
    END
  END b_d[61]
  PIN b_d[62]
    DIRECTION OUTPUT ;
    USE SIGNAL ;
    PORT
      LAYER M5 ;
        RECT  16.752 0 16.776 0.084 ;
    END
  END b_d[62]
  PIN b_d[63]
    DIRECTION OUTPUT ;
    USE SIGNAL ;
    PORT
      LAYER M5 ;
        RECT  16.8 0 16.824 0.084 ;
    END
  END b_d[63]
  PIN b_d[64]
    DIRECTION OUTPUT ;
    USE SIGNAL ;
    PORT
      LAYER M5 ;
        RECT  16.848 0 16.872 0.084 ;
    END
  END b_d[64]
  PIN b_d[65]
    DIRECTION OUTPUT ;
    USE SIGNAL ;
    PORT
      LAYER M5 ;
        RECT  16.896 0 16.92 0.084 ;
    END
  END b_d[65]
  PIN b_d[66]
    DIRECTION OUTPUT ;
    USE SIGNAL ;
    PORT
      LAYER M5 ;
        RECT  16.944 0 16.968 0.084 ;
    END
  END b_d[66]
  PIN b_d[67]
    DIRECTION OUTPUT ;
    USE SIGNAL ;
    PORT
      LAYER M5 ;
        RECT  16.992 0 17.016 0.084 ;
    END
  END b_d[67]
  PIN b_d[68]
    DIRECTION OUTPUT ;
    USE SIGNAL ;
    PORT
      LAYER M5 ;
        RECT  17.04 0 17.064 0.084 ;
    END
  END b_d[68]
  PIN b_d[69]
    DIRECTION OUTPUT ;
    USE SIGNAL ;
    PORT
      LAYER M5 ;
        RECT  17.088 0 17.112 0.084 ;
    END
  END b_d[69]
  PIN b_d[6]
    DIRECTION OUTPUT ;
    USE SIGNAL ;
    PORT
      LAYER M5 ;
        RECT  14.064 0 14.088 0.084 ;
    END
  END b_d[6]
  PIN b_d[70]
    DIRECTION OUTPUT ;
    USE SIGNAL ;
    PORT
      LAYER M5 ;
        RECT  17.136 0 17.16 0.084 ;
    END
  END b_d[70]
  PIN b_d[71]
    DIRECTION OUTPUT ;
    USE SIGNAL ;
    PORT
      LAYER M5 ;
        RECT  17.184 0 17.208 0.084 ;
    END
  END b_d[71]
  PIN b_d[72]
    DIRECTION OUTPUT ;
    USE SIGNAL ;
    PORT
      LAYER M5 ;
        RECT  17.232 0 17.256 0.084 ;
    END
  END b_d[72]
  PIN b_d[73]
    DIRECTION OUTPUT ;
    USE SIGNAL ;
    PORT
      LAYER M5 ;
        RECT  17.28 0 17.304 0.084 ;
    END
  END b_d[73]
  PIN b_d[74]
    DIRECTION OUTPUT ;
    USE SIGNAL ;
    PORT
      LAYER M5 ;
        RECT  17.328 0 17.352 0.084 ;
    END
  END b_d[74]
  PIN b_d[75]
    DIRECTION OUTPUT ;
    USE SIGNAL ;
    PORT
      LAYER M5 ;
        RECT  17.376 0 17.4 0.084 ;
    END
  END b_d[75]
  PIN b_d[76]
    DIRECTION OUTPUT ;
    USE SIGNAL ;
    PORT
      LAYER M5 ;
        RECT  17.424 0 17.448 0.084 ;
    END
  END b_d[76]
  PIN b_d[77]
    DIRECTION OUTPUT ;
    USE SIGNAL ;
    PORT
      LAYER M5 ;
        RECT  17.472 0 17.496 0.084 ;
    END
  END b_d[77]
  PIN b_d[78]
    DIRECTION OUTPUT ;
    USE SIGNAL ;
    PORT
      LAYER M5 ;
        RECT  17.52 0 17.544 0.084 ;
    END
  END b_d[78]
  PIN b_d[79]
    DIRECTION OUTPUT ;
    USE SIGNAL ;
    PORT
      LAYER M5 ;
        RECT  17.568 0 17.592 0.084 ;
    END
  END b_d[79]
  PIN b_d[7]
    DIRECTION OUTPUT ;
    USE SIGNAL ;
    PORT
      LAYER M5 ;
        RECT  14.112 0 14.136 0.084 ;
    END
  END b_d[7]
  PIN b_d[80]
    DIRECTION OUTPUT ;
    USE SIGNAL ;
    PORT
      LAYER M5 ;
        RECT  17.616 0 17.64 0.084 ;
    END
  END b_d[80]
  PIN b_d[81]
    DIRECTION OUTPUT ;
    USE SIGNAL ;
    PORT
      LAYER M5 ;
        RECT  17.664 0 17.688 0.084 ;
    END
  END b_d[81]
  PIN b_d[82]
    DIRECTION OUTPUT ;
    USE SIGNAL ;
    PORT
      LAYER M5 ;
        RECT  17.712 0 17.736 0.084 ;
    END
  END b_d[82]
  PIN b_d[83]
    DIRECTION OUTPUT ;
    USE SIGNAL ;
    PORT
      LAYER M5 ;
        RECT  17.76 0 17.784 0.084 ;
    END
  END b_d[83]
  PIN b_d[84]
    DIRECTION OUTPUT ;
    USE SIGNAL ;
    PORT
      LAYER M5 ;
        RECT  17.808 0 17.832 0.084 ;
    END
  END b_d[84]
  PIN b_d[85]
    DIRECTION OUTPUT ;
    USE SIGNAL ;
    PORT
      LAYER M5 ;
        RECT  17.856 0 17.88 0.084 ;
    END
  END b_d[85]
  PIN b_d[86]
    DIRECTION OUTPUT ;
    USE SIGNAL ;
    PORT
      LAYER M5 ;
        RECT  17.904 0 17.928 0.084 ;
    END
  END b_d[86]
  PIN b_d[87]
    DIRECTION OUTPUT ;
    USE SIGNAL ;
    PORT
      LAYER M5 ;
        RECT  17.952 0 17.976 0.084 ;
    END
  END b_d[87]
  PIN b_d[88]
    DIRECTION OUTPUT ;
    USE SIGNAL ;
    PORT
      LAYER M5 ;
        RECT  18 0 18.024 0.084 ;
    END
  END b_d[88]
  PIN b_d[89]
    DIRECTION OUTPUT ;
    USE SIGNAL ;
    PORT
      LAYER M5 ;
        RECT  18.048 0 18.072 0.084 ;
    END
  END b_d[89]
  PIN b_d[8]
    DIRECTION OUTPUT ;
    USE SIGNAL ;
    PORT
      LAYER M5 ;
        RECT  14.16 0 14.184 0.084 ;
    END
  END b_d[8]
  PIN b_d[90]
    DIRECTION OUTPUT ;
    USE SIGNAL ;
    PORT
      LAYER M5 ;
        RECT  18.096 0 18.12 0.084 ;
    END
  END b_d[90]
  PIN b_d[91]
    DIRECTION OUTPUT ;
    USE SIGNAL ;
    PORT
      LAYER M5 ;
        RECT  18.144 0 18.168 0.084 ;
    END
  END b_d[91]
  PIN b_d[92]
    DIRECTION OUTPUT ;
    USE SIGNAL ;
    PORT
      LAYER M5 ;
        RECT  18.192 0 18.216 0.084 ;
    END
  END b_d[92]
  PIN b_d[93]
    DIRECTION OUTPUT ;
    USE SIGNAL ;
    PORT
      LAYER M5 ;
        RECT  18.24 0 18.264 0.084 ;
    END
  END b_d[93]
  PIN b_d[94]
    DIRECTION OUTPUT ;
    USE SIGNAL ;
    PORT
      LAYER M5 ;
        RECT  18.288 0 18.312 0.084 ;
    END
  END b_d[94]
  PIN b_d[95]
    DIRECTION OUTPUT ;
    USE SIGNAL ;
    PORT
      LAYER M5 ;
        RECT  18.336 0 18.36 0.084 ;
    END
  END b_d[95]
  PIN b_d[96]
    DIRECTION OUTPUT ;
    USE SIGNAL ;
    PORT
      LAYER M5 ;
        RECT  18.384 0 18.408 0.084 ;
    END
  END b_d[96]
  PIN b_d[97]
    DIRECTION OUTPUT ;
    USE SIGNAL ;
    PORT
      LAYER M5 ;
        RECT  18.432 0 18.456 0.084 ;
    END
  END b_d[97]
  PIN b_d[98]
    DIRECTION OUTPUT ;
    USE SIGNAL ;
    PORT
      LAYER M5 ;
        RECT  18.48 0 18.504 0.084 ;
    END
  END b_d[98]
  PIN b_d[99]
    DIRECTION OUTPUT ;
    USE SIGNAL ;
    PORT
      LAYER M5 ;
        RECT  18.528 0 18.552 0.084 ;
    END
  END b_d[99]
  PIN b_d[9]
    DIRECTION OUTPUT ;
    USE SIGNAL ;
    PORT
      LAYER M5 ;
        RECT  14.208 0 14.232 0.084 ;
    END
  END b_d[9]
  PIN b_r
    DIRECTION INPUT ;
    USE SIGNAL ;
    PORT
      LAYER M5 ;
        RECT  38.16 0 38.184 0.084 ;
    END
  END b_r
  PIN c_d[0]
    DIRECTION OUTPUT ;
    USE SIGNAL ;
    PORT
      LAYER M4 ;
        RECT  0 39.696 0.084 39.72 ;
    END
  END c_d[0]
  PIN c_r
    DIRECTION INPUT ;
    USE SIGNAL ;
    PORT
      LAYER M4 ;
        RECT  0 39.744 0.084 39.768 ;
    END
  END c_r
  PIN clk
    DIRECTION INPUT ;
    USE SIGNAL ;
    PORT
      LAYER M4 ;
        RECT  0 39.792 0.084 39.816 ;
    END
  END clk
  PIN rst_n
    DIRECTION INPUT ;
    USE SIGNAL ;
    PORT
      LAYER M4 ;
        RECT  0 39.84 0.084 39.864 ;
    END
  END rst_n
  PIN t_d[0]
    DIRECTION OUTPUT ;
    USE SIGNAL ;
    PORT
      LAYER M4 ;
        RECT  0 39.888 0.084 39.912 ;
    END
  END t_d[0]
  PIN t_d[100]
    DIRECTION OUTPUT ;
    USE SIGNAL ;
    PORT
      LAYER M4 ;
        RECT  0 44.688 0.084 44.712 ;
    END
  END t_d[100]
  PIN t_d[101]
    DIRECTION OUTPUT ;
    USE SIGNAL ;
    PORT
      LAYER M4 ;
        RECT  0 44.736 0.084 44.76 ;
    END
  END t_d[101]
  PIN t_d[102]
    DIRECTION OUTPUT ;
    USE SIGNAL ;
    PORT
      LAYER M4 ;
        RECT  0 44.784 0.084 44.808 ;
    END
  END t_d[102]
  PIN t_d[103]
    DIRECTION OUTPUT ;
    USE SIGNAL ;
    PORT
      LAYER M4 ;
        RECT  0 44.832 0.084 44.856 ;
    END
  END t_d[103]
  PIN t_d[104]
    DIRECTION OUTPUT ;
    USE SIGNAL ;
    PORT
      LAYER M4 ;
        RECT  0 44.88 0.084 44.904 ;
    END
  END t_d[104]
  PIN t_d[105]
    DIRECTION OUTPUT ;
    USE SIGNAL ;
    PORT
      LAYER M4 ;
        RECT  0 44.928 0.084 44.952 ;
    END
  END t_d[105]
  PIN t_d[106]
    DIRECTION OUTPUT ;
    USE SIGNAL ;
    PORT
      LAYER M4 ;
        RECT  0 44.976 0.084 45 ;
    END
  END t_d[106]
  PIN t_d[107]
    DIRECTION OUTPUT ;
    USE SIGNAL ;
    PORT
      LAYER M4 ;
        RECT  0 45.024 0.084 45.048 ;
    END
  END t_d[107]
  PIN t_d[108]
    DIRECTION OUTPUT ;
    USE SIGNAL ;
    PORT
      LAYER M4 ;
        RECT  0 45.072 0.084 45.096 ;
    END
  END t_d[108]
  PIN t_d[109]
    DIRECTION OUTPUT ;
    USE SIGNAL ;
    PORT
      LAYER M4 ;
        RECT  0 45.12 0.084 45.144 ;
    END
  END t_d[109]
  PIN t_d[10]
    DIRECTION OUTPUT ;
    USE SIGNAL ;
    PORT
      LAYER M4 ;
        RECT  0 40.368 0.084 40.392 ;
    END
  END t_d[10]
  PIN t_d[110]
    DIRECTION OUTPUT ;
    USE SIGNAL ;
    PORT
      LAYER M4 ;
        RECT  0 45.168 0.084 45.192 ;
    END
  END t_d[110]
  PIN t_d[111]
    DIRECTION OUTPUT ;
    USE SIGNAL ;
    PORT
      LAYER M4 ;
        RECT  0 45.216 0.084 45.24 ;
    END
  END t_d[111]
  PIN t_d[112]
    DIRECTION OUTPUT ;
    USE SIGNAL ;
    PORT
      LAYER M4 ;
        RECT  0 45.264 0.084 45.288 ;
    END
  END t_d[112]
  PIN t_d[113]
    DIRECTION OUTPUT ;
    USE SIGNAL ;
    PORT
      LAYER M4 ;
        RECT  0 45.312 0.084 45.336 ;
    END
  END t_d[113]
  PIN t_d[114]
    DIRECTION OUTPUT ;
    USE SIGNAL ;
    PORT
      LAYER M4 ;
        RECT  0 45.36 0.084 45.384 ;
    END
  END t_d[114]
  PIN t_d[115]
    DIRECTION OUTPUT ;
    USE SIGNAL ;
    PORT
      LAYER M4 ;
        RECT  0 45.408 0.084 45.432 ;
    END
  END t_d[115]
  PIN t_d[116]
    DIRECTION OUTPUT ;
    USE SIGNAL ;
    PORT
      LAYER M4 ;
        RECT  0 45.456 0.084 45.48 ;
    END
  END t_d[116]
  PIN t_d[117]
    DIRECTION OUTPUT ;
    USE SIGNAL ;
    PORT
      LAYER M4 ;
        RECT  0 45.504 0.084 45.528 ;
    END
  END t_d[117]
  PIN t_d[118]
    DIRECTION OUTPUT ;
    USE SIGNAL ;
    PORT
      LAYER M4 ;
        RECT  0 45.552 0.084 45.576 ;
    END
  END t_d[118]
  PIN t_d[119]
    DIRECTION OUTPUT ;
    USE SIGNAL ;
    PORT
      LAYER M4 ;
        RECT  0 45.6 0.084 45.624 ;
    END
  END t_d[119]
  PIN t_d[11]
    DIRECTION OUTPUT ;
    USE SIGNAL ;
    PORT
      LAYER M4 ;
        RECT  0 40.416 0.084 40.44 ;
    END
  END t_d[11]
  PIN t_d[120]
    DIRECTION OUTPUT ;
    USE SIGNAL ;
    PORT
      LAYER M4 ;
        RECT  0 45.648 0.084 45.672 ;
    END
  END t_d[120]
  PIN t_d[121]
    DIRECTION OUTPUT ;
    USE SIGNAL ;
    PORT
      LAYER M4 ;
        RECT  0 45.696 0.084 45.72 ;
    END
  END t_d[121]
  PIN t_d[122]
    DIRECTION OUTPUT ;
    USE SIGNAL ;
    PORT
      LAYER M4 ;
        RECT  0 45.744 0.084 45.768 ;
    END
  END t_d[122]
  PIN t_d[123]
    DIRECTION OUTPUT ;
    USE SIGNAL ;
    PORT
      LAYER M4 ;
        RECT  0 45.792 0.084 45.816 ;
    END
  END t_d[123]
  PIN t_d[124]
    DIRECTION OUTPUT ;
    USE SIGNAL ;
    PORT
      LAYER M4 ;
        RECT  0 45.84 0.084 45.864 ;
    END
  END t_d[124]
  PIN t_d[125]
    DIRECTION OUTPUT ;
    USE SIGNAL ;
    PORT
      LAYER M4 ;
        RECT  0 45.888 0.084 45.912 ;
    END
  END t_d[125]
  PIN t_d[126]
    DIRECTION OUTPUT ;
    USE SIGNAL ;
    PORT
      LAYER M4 ;
        RECT  0 45.936 0.084 45.96 ;
    END
  END t_d[126]
  PIN t_d[127]
    DIRECTION OUTPUT ;
    USE SIGNAL ;
    PORT
      LAYER M4 ;
        RECT  0 45.984 0.084 46.008 ;
    END
  END t_d[127]
  PIN t_d[128]
    DIRECTION OUTPUT ;
    USE SIGNAL ;
    PORT
      LAYER M4 ;
        RECT  0 46.032 0.084 46.056 ;
    END
  END t_d[128]
  PIN t_d[129]
    DIRECTION OUTPUT ;
    USE SIGNAL ;
    PORT
      LAYER M4 ;
        RECT  0 46.08 0.084 46.104 ;
    END
  END t_d[129]
  PIN t_d[12]
    DIRECTION OUTPUT ;
    USE SIGNAL ;
    PORT
      LAYER M4 ;
        RECT  0 40.464 0.084 40.488 ;
    END
  END t_d[12]
  PIN t_d[130]
    DIRECTION OUTPUT ;
    USE SIGNAL ;
    PORT
      LAYER M4 ;
        RECT  0 46.128 0.084 46.152 ;
    END
  END t_d[130]
  PIN t_d[131]
    DIRECTION OUTPUT ;
    USE SIGNAL ;
    PORT
      LAYER M4 ;
        RECT  0 46.176 0.084 46.2 ;
    END
  END t_d[131]
  PIN t_d[132]
    DIRECTION OUTPUT ;
    USE SIGNAL ;
    PORT
      LAYER M4 ;
        RECT  0 46.224 0.084 46.248 ;
    END
  END t_d[132]
  PIN t_d[133]
    DIRECTION OUTPUT ;
    USE SIGNAL ;
    PORT
      LAYER M4 ;
        RECT  0 46.272 0.084 46.296 ;
    END
  END t_d[133]
  PIN t_d[134]
    DIRECTION OUTPUT ;
    USE SIGNAL ;
    PORT
      LAYER M4 ;
        RECT  0 46.32 0.084 46.344 ;
    END
  END t_d[134]
  PIN t_d[135]
    DIRECTION OUTPUT ;
    USE SIGNAL ;
    PORT
      LAYER M4 ;
        RECT  0 46.368 0.084 46.392 ;
    END
  END t_d[135]
  PIN t_d[136]
    DIRECTION OUTPUT ;
    USE SIGNAL ;
    PORT
      LAYER M4 ;
        RECT  0 46.416 0.084 46.44 ;
    END
  END t_d[136]
  PIN t_d[137]
    DIRECTION OUTPUT ;
    USE SIGNAL ;
    PORT
      LAYER M4 ;
        RECT  0 46.464 0.084 46.488 ;
    END
  END t_d[137]
  PIN t_d[138]
    DIRECTION OUTPUT ;
    USE SIGNAL ;
    PORT
      LAYER M4 ;
        RECT  0 46.512 0.084 46.536 ;
    END
  END t_d[138]
  PIN t_d[139]
    DIRECTION OUTPUT ;
    USE SIGNAL ;
    PORT
      LAYER M4 ;
        RECT  0 46.56 0.084 46.584 ;
    END
  END t_d[139]
  PIN t_d[13]
    DIRECTION OUTPUT ;
    USE SIGNAL ;
    PORT
      LAYER M4 ;
        RECT  0 40.512 0.084 40.536 ;
    END
  END t_d[13]
  PIN t_d[140]
    DIRECTION OUTPUT ;
    USE SIGNAL ;
    PORT
      LAYER M4 ;
        RECT  0 46.608 0.084 46.632 ;
    END
  END t_d[140]
  PIN t_d[141]
    DIRECTION OUTPUT ;
    USE SIGNAL ;
    PORT
      LAYER M4 ;
        RECT  0 46.656 0.084 46.68 ;
    END
  END t_d[141]
  PIN t_d[142]
    DIRECTION OUTPUT ;
    USE SIGNAL ;
    PORT
      LAYER M4 ;
        RECT  0 46.704 0.084 46.728 ;
    END
  END t_d[142]
  PIN t_d[143]
    DIRECTION OUTPUT ;
    USE SIGNAL ;
    PORT
      LAYER M4 ;
        RECT  0 46.752 0.084 46.776 ;
    END
  END t_d[143]
  PIN t_d[144]
    DIRECTION OUTPUT ;
    USE SIGNAL ;
    PORT
      LAYER M4 ;
        RECT  0 46.8 0.084 46.824 ;
    END
  END t_d[144]
  PIN t_d[145]
    DIRECTION OUTPUT ;
    USE SIGNAL ;
    PORT
      LAYER M4 ;
        RECT  0 46.848 0.084 46.872 ;
    END
  END t_d[145]
  PIN t_d[146]
    DIRECTION OUTPUT ;
    USE SIGNAL ;
    PORT
      LAYER M4 ;
        RECT  0 46.896 0.084 46.92 ;
    END
  END t_d[146]
  PIN t_d[147]
    DIRECTION OUTPUT ;
    USE SIGNAL ;
    PORT
      LAYER M4 ;
        RECT  0 46.944 0.084 46.968 ;
    END
  END t_d[147]
  PIN t_d[148]
    DIRECTION OUTPUT ;
    USE SIGNAL ;
    PORT
      LAYER M4 ;
        RECT  0 46.992 0.084 47.016 ;
    END
  END t_d[148]
  PIN t_d[149]
    DIRECTION OUTPUT ;
    USE SIGNAL ;
    PORT
      LAYER M4 ;
        RECT  0 47.04 0.084 47.064 ;
    END
  END t_d[149]
  PIN t_d[14]
    DIRECTION OUTPUT ;
    USE SIGNAL ;
    PORT
      LAYER M4 ;
        RECT  0 40.56 0.084 40.584 ;
    END
  END t_d[14]
  PIN t_d[150]
    DIRECTION OUTPUT ;
    USE SIGNAL ;
    PORT
      LAYER M4 ;
        RECT  0 47.088 0.084 47.112 ;
    END
  END t_d[150]
  PIN t_d[151]
    DIRECTION OUTPUT ;
    USE SIGNAL ;
    PORT
      LAYER M4 ;
        RECT  0 47.136 0.084 47.16 ;
    END
  END t_d[151]
  PIN t_d[152]
    DIRECTION OUTPUT ;
    USE SIGNAL ;
    PORT
      LAYER M4 ;
        RECT  0 47.184 0.084 47.208 ;
    END
  END t_d[152]
  PIN t_d[153]
    DIRECTION OUTPUT ;
    USE SIGNAL ;
    PORT
      LAYER M4 ;
        RECT  0 47.232 0.084 47.256 ;
    END
  END t_d[153]
  PIN t_d[154]
    DIRECTION OUTPUT ;
    USE SIGNAL ;
    PORT
      LAYER M4 ;
        RECT  0 47.28 0.084 47.304 ;
    END
  END t_d[154]
  PIN t_d[155]
    DIRECTION OUTPUT ;
    USE SIGNAL ;
    PORT
      LAYER M4 ;
        RECT  0 47.328 0.084 47.352 ;
    END
  END t_d[155]
  PIN t_d[156]
    DIRECTION OUTPUT ;
    USE SIGNAL ;
    PORT
      LAYER M4 ;
        RECT  0 47.376 0.084 47.4 ;
    END
  END t_d[156]
  PIN t_d[157]
    DIRECTION OUTPUT ;
    USE SIGNAL ;
    PORT
      LAYER M4 ;
        RECT  0 47.424 0.084 47.448 ;
    END
  END t_d[157]
  PIN t_d[158]
    DIRECTION OUTPUT ;
    USE SIGNAL ;
    PORT
      LAYER M4 ;
        RECT  0 47.472 0.084 47.496 ;
    END
  END t_d[158]
  PIN t_d[159]
    DIRECTION OUTPUT ;
    USE SIGNAL ;
    PORT
      LAYER M4 ;
        RECT  0 47.52 0.084 47.544 ;
    END
  END t_d[159]
  PIN t_d[15]
    DIRECTION OUTPUT ;
    USE SIGNAL ;
    PORT
      LAYER M4 ;
        RECT  0 40.608 0.084 40.632 ;
    END
  END t_d[15]
  PIN t_d[160]
    DIRECTION OUTPUT ;
    USE SIGNAL ;
    PORT
      LAYER M4 ;
        RECT  0 47.568 0.084 47.592 ;
    END
  END t_d[160]
  PIN t_d[161]
    DIRECTION OUTPUT ;
    USE SIGNAL ;
    PORT
      LAYER M4 ;
        RECT  0 47.616 0.084 47.64 ;
    END
  END t_d[161]
  PIN t_d[162]
    DIRECTION OUTPUT ;
    USE SIGNAL ;
    PORT
      LAYER M4 ;
        RECT  0 47.664 0.084 47.688 ;
    END
  END t_d[162]
  PIN t_d[163]
    DIRECTION OUTPUT ;
    USE SIGNAL ;
    PORT
      LAYER M4 ;
        RECT  0 47.712 0.084 47.736 ;
    END
  END t_d[163]
  PIN t_d[164]
    DIRECTION OUTPUT ;
    USE SIGNAL ;
    PORT
      LAYER M4 ;
        RECT  0 47.76 0.084 47.784 ;
    END
  END t_d[164]
  PIN t_d[165]
    DIRECTION OUTPUT ;
    USE SIGNAL ;
    PORT
      LAYER M4 ;
        RECT  0 47.808 0.084 47.832 ;
    END
  END t_d[165]
  PIN t_d[166]
    DIRECTION OUTPUT ;
    USE SIGNAL ;
    PORT
      LAYER M4 ;
        RECT  0 47.856 0.084 47.88 ;
    END
  END t_d[166]
  PIN t_d[167]
    DIRECTION OUTPUT ;
    USE SIGNAL ;
    PORT
      LAYER M4 ;
        RECT  0 47.904 0.084 47.928 ;
    END
  END t_d[167]
  PIN t_d[168]
    DIRECTION OUTPUT ;
    USE SIGNAL ;
    PORT
      LAYER M4 ;
        RECT  0 47.952 0.084 47.976 ;
    END
  END t_d[168]
  PIN t_d[169]
    DIRECTION OUTPUT ;
    USE SIGNAL ;
    PORT
      LAYER M4 ;
        RECT  0 48 0.084 48.024 ;
    END
  END t_d[169]
  PIN t_d[16]
    DIRECTION OUTPUT ;
    USE SIGNAL ;
    PORT
      LAYER M4 ;
        RECT  0 40.656 0.084 40.68 ;
    END
  END t_d[16]
  PIN t_d[170]
    DIRECTION OUTPUT ;
    USE SIGNAL ;
    PORT
      LAYER M4 ;
        RECT  0 48.048 0.084 48.072 ;
    END
  END t_d[170]
  PIN t_d[171]
    DIRECTION OUTPUT ;
    USE SIGNAL ;
    PORT
      LAYER M4 ;
        RECT  0 48.096 0.084 48.12 ;
    END
  END t_d[171]
  PIN t_d[172]
    DIRECTION OUTPUT ;
    USE SIGNAL ;
    PORT
      LAYER M4 ;
        RECT  0 48.144 0.084 48.168 ;
    END
  END t_d[172]
  PIN t_d[173]
    DIRECTION OUTPUT ;
    USE SIGNAL ;
    PORT
      LAYER M4 ;
        RECT  0 48.192 0.084 48.216 ;
    END
  END t_d[173]
  PIN t_d[174]
    DIRECTION OUTPUT ;
    USE SIGNAL ;
    PORT
      LAYER M4 ;
        RECT  0 48.24 0.084 48.264 ;
    END
  END t_d[174]
  PIN t_d[175]
    DIRECTION OUTPUT ;
    USE SIGNAL ;
    PORT
      LAYER M4 ;
        RECT  0 48.288 0.084 48.312 ;
    END
  END t_d[175]
  PIN t_d[176]
    DIRECTION OUTPUT ;
    USE SIGNAL ;
    PORT
      LAYER M4 ;
        RECT  0 48.336 0.084 48.36 ;
    END
  END t_d[176]
  PIN t_d[177]
    DIRECTION OUTPUT ;
    USE SIGNAL ;
    PORT
      LAYER M4 ;
        RECT  0 48.384 0.084 48.408 ;
    END
  END t_d[177]
  PIN t_d[178]
    DIRECTION OUTPUT ;
    USE SIGNAL ;
    PORT
      LAYER M4 ;
        RECT  0 48.432 0.084 48.456 ;
    END
  END t_d[178]
  PIN t_d[179]
    DIRECTION OUTPUT ;
    USE SIGNAL ;
    PORT
      LAYER M4 ;
        RECT  0 48.48 0.084 48.504 ;
    END
  END t_d[179]
  PIN t_d[17]
    DIRECTION OUTPUT ;
    USE SIGNAL ;
    PORT
      LAYER M4 ;
        RECT  0 40.704 0.084 40.728 ;
    END
  END t_d[17]
  PIN t_d[180]
    DIRECTION OUTPUT ;
    USE SIGNAL ;
    PORT
      LAYER M4 ;
        RECT  0 48.528 0.084 48.552 ;
    END
  END t_d[180]
  PIN t_d[181]
    DIRECTION OUTPUT ;
    USE SIGNAL ;
    PORT
      LAYER M4 ;
        RECT  0 48.576 0.084 48.6 ;
    END
  END t_d[181]
  PIN t_d[182]
    DIRECTION OUTPUT ;
    USE SIGNAL ;
    PORT
      LAYER M4 ;
        RECT  0 48.624 0.084 48.648 ;
    END
  END t_d[182]
  PIN t_d[183]
    DIRECTION OUTPUT ;
    USE SIGNAL ;
    PORT
      LAYER M4 ;
        RECT  0 48.672 0.084 48.696 ;
    END
  END t_d[183]
  PIN t_d[184]
    DIRECTION OUTPUT ;
    USE SIGNAL ;
    PORT
      LAYER M4 ;
        RECT  0 48.72 0.084 48.744 ;
    END
  END t_d[184]
  PIN t_d[185]
    DIRECTION OUTPUT ;
    USE SIGNAL ;
    PORT
      LAYER M4 ;
        RECT  0 48.768 0.084 48.792 ;
    END
  END t_d[185]
  PIN t_d[186]
    DIRECTION OUTPUT ;
    USE SIGNAL ;
    PORT
      LAYER M4 ;
        RECT  0 48.816 0.084 48.84 ;
    END
  END t_d[186]
  PIN t_d[187]
    DIRECTION OUTPUT ;
    USE SIGNAL ;
    PORT
      LAYER M4 ;
        RECT  0 48.864 0.084 48.888 ;
    END
  END t_d[187]
  PIN t_d[188]
    DIRECTION OUTPUT ;
    USE SIGNAL ;
    PORT
      LAYER M4 ;
        RECT  0 48.912 0.084 48.936 ;
    END
  END t_d[188]
  PIN t_d[189]
    DIRECTION OUTPUT ;
    USE SIGNAL ;
    PORT
      LAYER M4 ;
        RECT  0 48.96 0.084 48.984 ;
    END
  END t_d[189]
  PIN t_d[18]
    DIRECTION OUTPUT ;
    USE SIGNAL ;
    PORT
      LAYER M4 ;
        RECT  0 40.752 0.084 40.776 ;
    END
  END t_d[18]
  PIN t_d[190]
    DIRECTION OUTPUT ;
    USE SIGNAL ;
    PORT
      LAYER M4 ;
        RECT  0 49.008 0.084 49.032 ;
    END
  END t_d[190]
  PIN t_d[191]
    DIRECTION OUTPUT ;
    USE SIGNAL ;
    PORT
      LAYER M4 ;
        RECT  0 49.056 0.084 49.08 ;
    END
  END t_d[191]
  PIN t_d[192]
    DIRECTION OUTPUT ;
    USE SIGNAL ;
    PORT
      LAYER M4 ;
        RECT  0 49.104 0.084 49.128 ;
    END
  END t_d[192]
  PIN t_d[193]
    DIRECTION OUTPUT ;
    USE SIGNAL ;
    PORT
      LAYER M4 ;
        RECT  0 49.152 0.084 49.176 ;
    END
  END t_d[193]
  PIN t_d[194]
    DIRECTION OUTPUT ;
    USE SIGNAL ;
    PORT
      LAYER M4 ;
        RECT  0 49.2 0.084 49.224 ;
    END
  END t_d[194]
  PIN t_d[195]
    DIRECTION OUTPUT ;
    USE SIGNAL ;
    PORT
      LAYER M4 ;
        RECT  0 49.248 0.084 49.272 ;
    END
  END t_d[195]
  PIN t_d[196]
    DIRECTION OUTPUT ;
    USE SIGNAL ;
    PORT
      LAYER M4 ;
        RECT  0 49.296 0.084 49.32 ;
    END
  END t_d[196]
  PIN t_d[197]
    DIRECTION OUTPUT ;
    USE SIGNAL ;
    PORT
      LAYER M4 ;
        RECT  0 49.344 0.084 49.368 ;
    END
  END t_d[197]
  PIN t_d[198]
    DIRECTION OUTPUT ;
    USE SIGNAL ;
    PORT
      LAYER M4 ;
        RECT  0 49.392 0.084 49.416 ;
    END
  END t_d[198]
  PIN t_d[199]
    DIRECTION OUTPUT ;
    USE SIGNAL ;
    PORT
      LAYER M4 ;
        RECT  0 49.44 0.084 49.464 ;
    END
  END t_d[199]
  PIN t_d[19]
    DIRECTION OUTPUT ;
    USE SIGNAL ;
    PORT
      LAYER M4 ;
        RECT  0 40.8 0.084 40.824 ;
    END
  END t_d[19]
  PIN t_d[1]
    DIRECTION OUTPUT ;
    USE SIGNAL ;
    PORT
      LAYER M4 ;
        RECT  0 39.936 0.084 39.96 ;
    END
  END t_d[1]
  PIN t_d[200]
    DIRECTION OUTPUT ;
    USE SIGNAL ;
    PORT
      LAYER M4 ;
        RECT  0 49.488 0.084 49.512 ;
    END
  END t_d[200]
  PIN t_d[201]
    DIRECTION OUTPUT ;
    USE SIGNAL ;
    PORT
      LAYER M4 ;
        RECT  0 49.536 0.084 49.56 ;
    END
  END t_d[201]
  PIN t_d[202]
    DIRECTION OUTPUT ;
    USE SIGNAL ;
    PORT
      LAYER M4 ;
        RECT  0 49.584 0.084 49.608 ;
    END
  END t_d[202]
  PIN t_d[203]
    DIRECTION OUTPUT ;
    USE SIGNAL ;
    PORT
      LAYER M4 ;
        RECT  0 49.632 0.084 49.656 ;
    END
  END t_d[203]
  PIN t_d[204]
    DIRECTION OUTPUT ;
    USE SIGNAL ;
    PORT
      LAYER M4 ;
        RECT  0 49.68 0.084 49.704 ;
    END
  END t_d[204]
  PIN t_d[205]
    DIRECTION OUTPUT ;
    USE SIGNAL ;
    PORT
      LAYER M4 ;
        RECT  0 49.728 0.084 49.752 ;
    END
  END t_d[205]
  PIN t_d[206]
    DIRECTION OUTPUT ;
    USE SIGNAL ;
    PORT
      LAYER M4 ;
        RECT  0 49.776 0.084 49.8 ;
    END
  END t_d[206]
  PIN t_d[207]
    DIRECTION OUTPUT ;
    USE SIGNAL ;
    PORT
      LAYER M4 ;
        RECT  0 49.824 0.084 49.848 ;
    END
  END t_d[207]
  PIN t_d[208]
    DIRECTION OUTPUT ;
    USE SIGNAL ;
    PORT
      LAYER M4 ;
        RECT  0 49.872 0.084 49.896 ;
    END
  END t_d[208]
  PIN t_d[209]
    DIRECTION OUTPUT ;
    USE SIGNAL ;
    PORT
      LAYER M4 ;
        RECT  0 49.92 0.084 49.944 ;
    END
  END t_d[209]
  PIN t_d[20]
    DIRECTION OUTPUT ;
    USE SIGNAL ;
    PORT
      LAYER M4 ;
        RECT  0 40.848 0.084 40.872 ;
    END
  END t_d[20]
  PIN t_d[210]
    DIRECTION OUTPUT ;
    USE SIGNAL ;
    PORT
      LAYER M4 ;
        RECT  0 49.968 0.084 49.992 ;
    END
  END t_d[210]
  PIN t_d[211]
    DIRECTION OUTPUT ;
    USE SIGNAL ;
    PORT
      LAYER M4 ;
        RECT  0 50.016 0.084 50.04 ;
    END
  END t_d[211]
  PIN t_d[212]
    DIRECTION OUTPUT ;
    USE SIGNAL ;
    PORT
      LAYER M4 ;
        RECT  0 50.064 0.084 50.088 ;
    END
  END t_d[212]
  PIN t_d[213]
    DIRECTION OUTPUT ;
    USE SIGNAL ;
    PORT
      LAYER M4 ;
        RECT  0 50.112 0.084 50.136 ;
    END
  END t_d[213]
  PIN t_d[214]
    DIRECTION OUTPUT ;
    USE SIGNAL ;
    PORT
      LAYER M4 ;
        RECT  0 50.16 0.084 50.184 ;
    END
  END t_d[214]
  PIN t_d[215]
    DIRECTION OUTPUT ;
    USE SIGNAL ;
    PORT
      LAYER M4 ;
        RECT  0 50.208 0.084 50.232 ;
    END
  END t_d[215]
  PIN t_d[216]
    DIRECTION OUTPUT ;
    USE SIGNAL ;
    PORT
      LAYER M4 ;
        RECT  0 50.256 0.084 50.28 ;
    END
  END t_d[216]
  PIN t_d[217]
    DIRECTION OUTPUT ;
    USE SIGNAL ;
    PORT
      LAYER M4 ;
        RECT  0 50.304 0.084 50.328 ;
    END
  END t_d[217]
  PIN t_d[218]
    DIRECTION OUTPUT ;
    USE SIGNAL ;
    PORT
      LAYER M4 ;
        RECT  0 50.352 0.084 50.376 ;
    END
  END t_d[218]
  PIN t_d[219]
    DIRECTION OUTPUT ;
    USE SIGNAL ;
    PORT
      LAYER M4 ;
        RECT  0 50.4 0.084 50.424 ;
    END
  END t_d[219]
  PIN t_d[21]
    DIRECTION OUTPUT ;
    USE SIGNAL ;
    PORT
      LAYER M4 ;
        RECT  0 40.896 0.084 40.92 ;
    END
  END t_d[21]
  PIN t_d[220]
    DIRECTION OUTPUT ;
    USE SIGNAL ;
    PORT
      LAYER M4 ;
        RECT  0 50.448 0.084 50.472 ;
    END
  END t_d[220]
  PIN t_d[221]
    DIRECTION OUTPUT ;
    USE SIGNAL ;
    PORT
      LAYER M4 ;
        RECT  0 50.496 0.084 50.52 ;
    END
  END t_d[221]
  PIN t_d[222]
    DIRECTION OUTPUT ;
    USE SIGNAL ;
    PORT
      LAYER M4 ;
        RECT  0 50.544 0.084 50.568 ;
    END
  END t_d[222]
  PIN t_d[223]
    DIRECTION OUTPUT ;
    USE SIGNAL ;
    PORT
      LAYER M4 ;
        RECT  0 50.592 0.084 50.616 ;
    END
  END t_d[223]
  PIN t_d[224]
    DIRECTION OUTPUT ;
    USE SIGNAL ;
    PORT
      LAYER M4 ;
        RECT  0 50.64 0.084 50.664 ;
    END
  END t_d[224]
  PIN t_d[225]
    DIRECTION OUTPUT ;
    USE SIGNAL ;
    PORT
      LAYER M4 ;
        RECT  0 50.688 0.084 50.712 ;
    END
  END t_d[225]
  PIN t_d[226]
    DIRECTION OUTPUT ;
    USE SIGNAL ;
    PORT
      LAYER M4 ;
        RECT  0 50.736 0.084 50.76 ;
    END
  END t_d[226]
  PIN t_d[227]
    DIRECTION OUTPUT ;
    USE SIGNAL ;
    PORT
      LAYER M4 ;
        RECT  0 50.784 0.084 50.808 ;
    END
  END t_d[227]
  PIN t_d[228]
    DIRECTION OUTPUT ;
    USE SIGNAL ;
    PORT
      LAYER M4 ;
        RECT  0 50.832 0.084 50.856 ;
    END
  END t_d[228]
  PIN t_d[229]
    DIRECTION OUTPUT ;
    USE SIGNAL ;
    PORT
      LAYER M4 ;
        RECT  0 50.88 0.084 50.904 ;
    END
  END t_d[229]
  PIN t_d[22]
    DIRECTION OUTPUT ;
    USE SIGNAL ;
    PORT
      LAYER M4 ;
        RECT  0 40.944 0.084 40.968 ;
    END
  END t_d[22]
  PIN t_d[230]
    DIRECTION OUTPUT ;
    USE SIGNAL ;
    PORT
      LAYER M4 ;
        RECT  0 50.928 0.084 50.952 ;
    END
  END t_d[230]
  PIN t_d[231]
    DIRECTION OUTPUT ;
    USE SIGNAL ;
    PORT
      LAYER M4 ;
        RECT  0 50.976 0.084 51 ;
    END
  END t_d[231]
  PIN t_d[232]
    DIRECTION OUTPUT ;
    USE SIGNAL ;
    PORT
      LAYER M4 ;
        RECT  0 51.024 0.084 51.048 ;
    END
  END t_d[232]
  PIN t_d[233]
    DIRECTION OUTPUT ;
    USE SIGNAL ;
    PORT
      LAYER M4 ;
        RECT  0 51.072 0.084 51.096 ;
    END
  END t_d[233]
  PIN t_d[234]
    DIRECTION OUTPUT ;
    USE SIGNAL ;
    PORT
      LAYER M4 ;
        RECT  0 51.12 0.084 51.144 ;
    END
  END t_d[234]
  PIN t_d[235]
    DIRECTION OUTPUT ;
    USE SIGNAL ;
    PORT
      LAYER M4 ;
        RECT  0 51.168 0.084 51.192 ;
    END
  END t_d[235]
  PIN t_d[236]
    DIRECTION OUTPUT ;
    USE SIGNAL ;
    PORT
      LAYER M4 ;
        RECT  0 51.216 0.084 51.24 ;
    END
  END t_d[236]
  PIN t_d[237]
    DIRECTION OUTPUT ;
    USE SIGNAL ;
    PORT
      LAYER M4 ;
        RECT  0 51.264 0.084 51.288 ;
    END
  END t_d[237]
  PIN t_d[238]
    DIRECTION OUTPUT ;
    USE SIGNAL ;
    PORT
      LAYER M4 ;
        RECT  0 51.312 0.084 51.336 ;
    END
  END t_d[238]
  PIN t_d[239]
    DIRECTION OUTPUT ;
    USE SIGNAL ;
    PORT
      LAYER M4 ;
        RECT  0 51.36 0.084 51.384 ;
    END
  END t_d[239]
  PIN t_d[23]
    DIRECTION OUTPUT ;
    USE SIGNAL ;
    PORT
      LAYER M4 ;
        RECT  0 40.992 0.084 41.016 ;
    END
  END t_d[23]
  PIN t_d[240]
    DIRECTION OUTPUT ;
    USE SIGNAL ;
    PORT
      LAYER M4 ;
        RECT  0 51.408 0.084 51.432 ;
    END
  END t_d[240]
  PIN t_d[241]
    DIRECTION OUTPUT ;
    USE SIGNAL ;
    PORT
      LAYER M4 ;
        RECT  0 51.456 0.084 51.48 ;
    END
  END t_d[241]
  PIN t_d[242]
    DIRECTION OUTPUT ;
    USE SIGNAL ;
    PORT
      LAYER M4 ;
        RECT  0 51.504 0.084 51.528 ;
    END
  END t_d[242]
  PIN t_d[243]
    DIRECTION OUTPUT ;
    USE SIGNAL ;
    PORT
      LAYER M4 ;
        RECT  0 51.552 0.084 51.576 ;
    END
  END t_d[243]
  PIN t_d[244]
    DIRECTION OUTPUT ;
    USE SIGNAL ;
    PORT
      LAYER M4 ;
        RECT  0 51.6 0.084 51.624 ;
    END
  END t_d[244]
  PIN t_d[245]
    DIRECTION OUTPUT ;
    USE SIGNAL ;
    PORT
      LAYER M4 ;
        RECT  0 51.648 0.084 51.672 ;
    END
  END t_d[245]
  PIN t_d[246]
    DIRECTION OUTPUT ;
    USE SIGNAL ;
    PORT
      LAYER M4 ;
        RECT  0 51.696 0.084 51.72 ;
    END
  END t_d[246]
  PIN t_d[247]
    DIRECTION OUTPUT ;
    USE SIGNAL ;
    PORT
      LAYER M4 ;
        RECT  0 51.744 0.084 51.768 ;
    END
  END t_d[247]
  PIN t_d[248]
    DIRECTION OUTPUT ;
    USE SIGNAL ;
    PORT
      LAYER M4 ;
        RECT  0 51.792 0.084 51.816 ;
    END
  END t_d[248]
  PIN t_d[249]
    DIRECTION OUTPUT ;
    USE SIGNAL ;
    PORT
      LAYER M4 ;
        RECT  0 51.84 0.084 51.864 ;
    END
  END t_d[249]
  PIN t_d[24]
    DIRECTION OUTPUT ;
    USE SIGNAL ;
    PORT
      LAYER M4 ;
        RECT  0 41.04 0.084 41.064 ;
    END
  END t_d[24]
  PIN t_d[250]
    DIRECTION OUTPUT ;
    USE SIGNAL ;
    PORT
      LAYER M4 ;
        RECT  0 51.888 0.084 51.912 ;
    END
  END t_d[250]
  PIN t_d[251]
    DIRECTION OUTPUT ;
    USE SIGNAL ;
    PORT
      LAYER M4 ;
        RECT  0 51.936 0.084 51.96 ;
    END
  END t_d[251]
  PIN t_d[252]
    DIRECTION OUTPUT ;
    USE SIGNAL ;
    PORT
      LAYER M4 ;
        RECT  0 51.984 0.084 52.008 ;
    END
  END t_d[252]
  PIN t_d[253]
    DIRECTION OUTPUT ;
    USE SIGNAL ;
    PORT
      LAYER M4 ;
        RECT  0 52.032 0.084 52.056 ;
    END
  END t_d[253]
  PIN t_d[254]
    DIRECTION OUTPUT ;
    USE SIGNAL ;
    PORT
      LAYER M4 ;
        RECT  0 52.08 0.084 52.104 ;
    END
  END t_d[254]
  PIN t_d[255]
    DIRECTION OUTPUT ;
    USE SIGNAL ;
    PORT
      LAYER M4 ;
        RECT  0 52.128 0.084 52.152 ;
    END
  END t_d[255]
  PIN t_d[256]
    DIRECTION OUTPUT ;
    USE SIGNAL ;
    PORT
      LAYER M4 ;
        RECT  0 52.176 0.084 52.2 ;
    END
  END t_d[256]
  PIN t_d[257]
    DIRECTION OUTPUT ;
    USE SIGNAL ;
    PORT
      LAYER M4 ;
        RECT  0 52.224 0.084 52.248 ;
    END
  END t_d[257]
  PIN t_d[258]
    DIRECTION OUTPUT ;
    USE SIGNAL ;
    PORT
      LAYER M4 ;
        RECT  0 52.272 0.084 52.296 ;
    END
  END t_d[258]
  PIN t_d[259]
    DIRECTION OUTPUT ;
    USE SIGNAL ;
    PORT
      LAYER M4 ;
        RECT  0 52.32 0.084 52.344 ;
    END
  END t_d[259]
  PIN t_d[25]
    DIRECTION OUTPUT ;
    USE SIGNAL ;
    PORT
      LAYER M4 ;
        RECT  0 41.088 0.084 41.112 ;
    END
  END t_d[25]
  PIN t_d[260]
    DIRECTION OUTPUT ;
    USE SIGNAL ;
    PORT
      LAYER M4 ;
        RECT  0 52.368 0.084 52.392 ;
    END
  END t_d[260]
  PIN t_d[261]
    DIRECTION OUTPUT ;
    USE SIGNAL ;
    PORT
      LAYER M4 ;
        RECT  0 52.416 0.084 52.44 ;
    END
  END t_d[261]
  PIN t_d[262]
    DIRECTION OUTPUT ;
    USE SIGNAL ;
    PORT
      LAYER M4 ;
        RECT  0 52.464 0.084 52.488 ;
    END
  END t_d[262]
  PIN t_d[263]
    DIRECTION OUTPUT ;
    USE SIGNAL ;
    PORT
      LAYER M4 ;
        RECT  0 52.512 0.084 52.536 ;
    END
  END t_d[263]
  PIN t_d[264]
    DIRECTION OUTPUT ;
    USE SIGNAL ;
    PORT
      LAYER M4 ;
        RECT  0 52.56 0.084 52.584 ;
    END
  END t_d[264]
  PIN t_d[265]
    DIRECTION OUTPUT ;
    USE SIGNAL ;
    PORT
      LAYER M4 ;
        RECT  0 52.608 0.084 52.632 ;
    END
  END t_d[265]
  PIN t_d[266]
    DIRECTION OUTPUT ;
    USE SIGNAL ;
    PORT
      LAYER M4 ;
        RECT  0 52.656 0.084 52.68 ;
    END
  END t_d[266]
  PIN t_d[267]
    DIRECTION OUTPUT ;
    USE SIGNAL ;
    PORT
      LAYER M4 ;
        RECT  0 52.704 0.084 52.728 ;
    END
  END t_d[267]
  PIN t_d[268]
    DIRECTION OUTPUT ;
    USE SIGNAL ;
    PORT
      LAYER M4 ;
        RECT  0 52.752 0.084 52.776 ;
    END
  END t_d[268]
  PIN t_d[269]
    DIRECTION OUTPUT ;
    USE SIGNAL ;
    PORT
      LAYER M4 ;
        RECT  0 52.8 0.084 52.824 ;
    END
  END t_d[269]
  PIN t_d[26]
    DIRECTION OUTPUT ;
    USE SIGNAL ;
    PORT
      LAYER M4 ;
        RECT  0 41.136 0.084 41.16 ;
    END
  END t_d[26]
  PIN t_d[270]
    DIRECTION OUTPUT ;
    USE SIGNAL ;
    PORT
      LAYER M4 ;
        RECT  0 52.848 0.084 52.872 ;
    END
  END t_d[270]
  PIN t_d[271]
    DIRECTION OUTPUT ;
    USE SIGNAL ;
    PORT
      LAYER M4 ;
        RECT  0 52.896 0.084 52.92 ;
    END
  END t_d[271]
  PIN t_d[272]
    DIRECTION OUTPUT ;
    USE SIGNAL ;
    PORT
      LAYER M4 ;
        RECT  0 52.944 0.084 52.968 ;
    END
  END t_d[272]
  PIN t_d[273]
    DIRECTION OUTPUT ;
    USE SIGNAL ;
    PORT
      LAYER M4 ;
        RECT  0 52.992 0.084 53.016 ;
    END
  END t_d[273]
  PIN t_d[274]
    DIRECTION OUTPUT ;
    USE SIGNAL ;
    PORT
      LAYER M4 ;
        RECT  0 53.04 0.084 53.064 ;
    END
  END t_d[274]
  PIN t_d[275]
    DIRECTION OUTPUT ;
    USE SIGNAL ;
    PORT
      LAYER M4 ;
        RECT  0 53.088 0.084 53.112 ;
    END
  END t_d[275]
  PIN t_d[276]
    DIRECTION OUTPUT ;
    USE SIGNAL ;
    PORT
      LAYER M4 ;
        RECT  0 53.136 0.084 53.16 ;
    END
  END t_d[276]
  PIN t_d[277]
    DIRECTION OUTPUT ;
    USE SIGNAL ;
    PORT
      LAYER M4 ;
        RECT  0 53.184 0.084 53.208 ;
    END
  END t_d[277]
  PIN t_d[278]
    DIRECTION OUTPUT ;
    USE SIGNAL ;
    PORT
      LAYER M4 ;
        RECT  0 53.232 0.084 53.256 ;
    END
  END t_d[278]
  PIN t_d[279]
    DIRECTION OUTPUT ;
    USE SIGNAL ;
    PORT
      LAYER M4 ;
        RECT  0 53.28 0.084 53.304 ;
    END
  END t_d[279]
  PIN t_d[27]
    DIRECTION OUTPUT ;
    USE SIGNAL ;
    PORT
      LAYER M4 ;
        RECT  0 41.184 0.084 41.208 ;
    END
  END t_d[27]
  PIN t_d[280]
    DIRECTION OUTPUT ;
    USE SIGNAL ;
    PORT
      LAYER M4 ;
        RECT  0 53.328 0.084 53.352 ;
    END
  END t_d[280]
  PIN t_d[281]
    DIRECTION OUTPUT ;
    USE SIGNAL ;
    PORT
      LAYER M4 ;
        RECT  0 53.376 0.084 53.4 ;
    END
  END t_d[281]
  PIN t_d[282]
    DIRECTION OUTPUT ;
    USE SIGNAL ;
    PORT
      LAYER M4 ;
        RECT  0 53.424 0.084 53.448 ;
    END
  END t_d[282]
  PIN t_d[283]
    DIRECTION OUTPUT ;
    USE SIGNAL ;
    PORT
      LAYER M4 ;
        RECT  0 53.472 0.084 53.496 ;
    END
  END t_d[283]
  PIN t_d[284]
    DIRECTION OUTPUT ;
    USE SIGNAL ;
    PORT
      LAYER M4 ;
        RECT  0 53.52 0.084 53.544 ;
    END
  END t_d[284]
  PIN t_d[285]
    DIRECTION OUTPUT ;
    USE SIGNAL ;
    PORT
      LAYER M4 ;
        RECT  0 53.568 0.084 53.592 ;
    END
  END t_d[285]
  PIN t_d[286]
    DIRECTION OUTPUT ;
    USE SIGNAL ;
    PORT
      LAYER M4 ;
        RECT  0 53.616 0.084 53.64 ;
    END
  END t_d[286]
  PIN t_d[287]
    DIRECTION OUTPUT ;
    USE SIGNAL ;
    PORT
      LAYER M4 ;
        RECT  0 53.664 0.084 53.688 ;
    END
  END t_d[287]
  PIN t_d[288]
    DIRECTION OUTPUT ;
    USE SIGNAL ;
    PORT
      LAYER M4 ;
        RECT  0 53.712 0.084 53.736 ;
    END
  END t_d[288]
  PIN t_d[289]
    DIRECTION OUTPUT ;
    USE SIGNAL ;
    PORT
      LAYER M4 ;
        RECT  0 53.76 0.084 53.784 ;
    END
  END t_d[289]
  PIN t_d[28]
    DIRECTION OUTPUT ;
    USE SIGNAL ;
    PORT
      LAYER M4 ;
        RECT  0 41.232 0.084 41.256 ;
    END
  END t_d[28]
  PIN t_d[290]
    DIRECTION OUTPUT ;
    USE SIGNAL ;
    PORT
      LAYER M4 ;
        RECT  0 53.808 0.084 53.832 ;
    END
  END t_d[290]
  PIN t_d[291]
    DIRECTION OUTPUT ;
    USE SIGNAL ;
    PORT
      LAYER M4 ;
        RECT  0 53.856 0.084 53.88 ;
    END
  END t_d[291]
  PIN t_d[292]
    DIRECTION OUTPUT ;
    USE SIGNAL ;
    PORT
      LAYER M4 ;
        RECT  0 53.904 0.084 53.928 ;
    END
  END t_d[292]
  PIN t_d[293]
    DIRECTION OUTPUT ;
    USE SIGNAL ;
    PORT
      LAYER M4 ;
        RECT  0 53.952 0.084 53.976 ;
    END
  END t_d[293]
  PIN t_d[294]
    DIRECTION OUTPUT ;
    USE SIGNAL ;
    PORT
      LAYER M4 ;
        RECT  0 54 0.084 54.024 ;
    END
  END t_d[294]
  PIN t_d[295]
    DIRECTION OUTPUT ;
    USE SIGNAL ;
    PORT
      LAYER M4 ;
        RECT  0 54.048 0.084 54.072 ;
    END
  END t_d[295]
  PIN t_d[296]
    DIRECTION OUTPUT ;
    USE SIGNAL ;
    PORT
      LAYER M4 ;
        RECT  0 54.096 0.084 54.12 ;
    END
  END t_d[296]
  PIN t_d[297]
    DIRECTION OUTPUT ;
    USE SIGNAL ;
    PORT
      LAYER M4 ;
        RECT  0 54.144 0.084 54.168 ;
    END
  END t_d[297]
  PIN t_d[298]
    DIRECTION OUTPUT ;
    USE SIGNAL ;
    PORT
      LAYER M4 ;
        RECT  0 54.192 0.084 54.216 ;
    END
  END t_d[298]
  PIN t_d[299]
    DIRECTION OUTPUT ;
    USE SIGNAL ;
    PORT
      LAYER M4 ;
        RECT  0 54.24 0.084 54.264 ;
    END
  END t_d[299]
  PIN t_d[29]
    DIRECTION OUTPUT ;
    USE SIGNAL ;
    PORT
      LAYER M4 ;
        RECT  0 41.28 0.084 41.304 ;
    END
  END t_d[29]
  PIN t_d[2]
    DIRECTION OUTPUT ;
    USE SIGNAL ;
    PORT
      LAYER M4 ;
        RECT  0 39.984 0.084 40.008 ;
    END
  END t_d[2]
  PIN t_d[300]
    DIRECTION OUTPUT ;
    USE SIGNAL ;
    PORT
      LAYER M4 ;
        RECT  0 54.288 0.084 54.312 ;
    END
  END t_d[300]
  PIN t_d[301]
    DIRECTION OUTPUT ;
    USE SIGNAL ;
    PORT
      LAYER M4 ;
        RECT  0 54.336 0.084 54.36 ;
    END
  END t_d[301]
  PIN t_d[302]
    DIRECTION OUTPUT ;
    USE SIGNAL ;
    PORT
      LAYER M4 ;
        RECT  0 54.384 0.084 54.408 ;
    END
  END t_d[302]
  PIN t_d[303]
    DIRECTION OUTPUT ;
    USE SIGNAL ;
    PORT
      LAYER M4 ;
        RECT  0 54.432 0.084 54.456 ;
    END
  END t_d[303]
  PIN t_d[304]
    DIRECTION OUTPUT ;
    USE SIGNAL ;
    PORT
      LAYER M4 ;
        RECT  0 54.48 0.084 54.504 ;
    END
  END t_d[304]
  PIN t_d[305]
    DIRECTION OUTPUT ;
    USE SIGNAL ;
    PORT
      LAYER M4 ;
        RECT  0 54.528 0.084 54.552 ;
    END
  END t_d[305]
  PIN t_d[306]
    DIRECTION OUTPUT ;
    USE SIGNAL ;
    PORT
      LAYER M4 ;
        RECT  0 54.576 0.084 54.6 ;
    END
  END t_d[306]
  PIN t_d[307]
    DIRECTION OUTPUT ;
    USE SIGNAL ;
    PORT
      LAYER M4 ;
        RECT  0 54.624 0.084 54.648 ;
    END
  END t_d[307]
  PIN t_d[308]
    DIRECTION OUTPUT ;
    USE SIGNAL ;
    PORT
      LAYER M4 ;
        RECT  0 54.672 0.084 54.696 ;
    END
  END t_d[308]
  PIN t_d[309]
    DIRECTION OUTPUT ;
    USE SIGNAL ;
    PORT
      LAYER M4 ;
        RECT  0 54.72 0.084 54.744 ;
    END
  END t_d[309]
  PIN t_d[30]
    DIRECTION OUTPUT ;
    USE SIGNAL ;
    PORT
      LAYER M4 ;
        RECT  0 41.328 0.084 41.352 ;
    END
  END t_d[30]
  PIN t_d[310]
    DIRECTION OUTPUT ;
    USE SIGNAL ;
    PORT
      LAYER M4 ;
        RECT  0 54.768 0.084 54.792 ;
    END
  END t_d[310]
  PIN t_d[311]
    DIRECTION OUTPUT ;
    USE SIGNAL ;
    PORT
      LAYER M4 ;
        RECT  0 54.816 0.084 54.84 ;
    END
  END t_d[311]
  PIN t_d[312]
    DIRECTION OUTPUT ;
    USE SIGNAL ;
    PORT
      LAYER M4 ;
        RECT  0 54.864 0.084 54.888 ;
    END
  END t_d[312]
  PIN t_d[313]
    DIRECTION OUTPUT ;
    USE SIGNAL ;
    PORT
      LAYER M4 ;
        RECT  0 54.912 0.084 54.936 ;
    END
  END t_d[313]
  PIN t_d[314]
    DIRECTION OUTPUT ;
    USE SIGNAL ;
    PORT
      LAYER M4 ;
        RECT  0 54.96 0.084 54.984 ;
    END
  END t_d[314]
  PIN t_d[315]
    DIRECTION OUTPUT ;
    USE SIGNAL ;
    PORT
      LAYER M4 ;
        RECT  0 55.008 0.084 55.032 ;
    END
  END t_d[315]
  PIN t_d[316]
    DIRECTION OUTPUT ;
    USE SIGNAL ;
    PORT
      LAYER M4 ;
        RECT  0 55.056 0.084 55.08 ;
    END
  END t_d[316]
  PIN t_d[317]
    DIRECTION OUTPUT ;
    USE SIGNAL ;
    PORT
      LAYER M4 ;
        RECT  0 55.104 0.084 55.128 ;
    END
  END t_d[317]
  PIN t_d[318]
    DIRECTION OUTPUT ;
    USE SIGNAL ;
    PORT
      LAYER M4 ;
        RECT  0 55.152 0.084 55.176 ;
    END
  END t_d[318]
  PIN t_d[319]
    DIRECTION OUTPUT ;
    USE SIGNAL ;
    PORT
      LAYER M4 ;
        RECT  0 55.2 0.084 55.224 ;
    END
  END t_d[319]
  PIN t_d[31]
    DIRECTION OUTPUT ;
    USE SIGNAL ;
    PORT
      LAYER M4 ;
        RECT  0 41.376 0.084 41.4 ;
    END
  END t_d[31]
  PIN t_d[320]
    DIRECTION OUTPUT ;
    USE SIGNAL ;
    PORT
      LAYER M4 ;
        RECT  0 55.248 0.084 55.272 ;
    END
  END t_d[320]
  PIN t_d[321]
    DIRECTION OUTPUT ;
    USE SIGNAL ;
    PORT
      LAYER M4 ;
        RECT  0 55.296 0.084 55.32 ;
    END
  END t_d[321]
  PIN t_d[322]
    DIRECTION OUTPUT ;
    USE SIGNAL ;
    PORT
      LAYER M4 ;
        RECT  0 55.344 0.084 55.368 ;
    END
  END t_d[322]
  PIN t_d[323]
    DIRECTION OUTPUT ;
    USE SIGNAL ;
    PORT
      LAYER M4 ;
        RECT  0 55.392 0.084 55.416 ;
    END
  END t_d[323]
  PIN t_d[324]
    DIRECTION OUTPUT ;
    USE SIGNAL ;
    PORT
      LAYER M4 ;
        RECT  0 55.44 0.084 55.464 ;
    END
  END t_d[324]
  PIN t_d[325]
    DIRECTION OUTPUT ;
    USE SIGNAL ;
    PORT
      LAYER M4 ;
        RECT  0 55.488 0.084 55.512 ;
    END
  END t_d[325]
  PIN t_d[326]
    DIRECTION OUTPUT ;
    USE SIGNAL ;
    PORT
      LAYER M4 ;
        RECT  0 55.536 0.084 55.56 ;
    END
  END t_d[326]
  PIN t_d[327]
    DIRECTION OUTPUT ;
    USE SIGNAL ;
    PORT
      LAYER M4 ;
        RECT  0 55.584 0.084 55.608 ;
    END
  END t_d[327]
  PIN t_d[328]
    DIRECTION OUTPUT ;
    USE SIGNAL ;
    PORT
      LAYER M4 ;
        RECT  0 55.632 0.084 55.656 ;
    END
  END t_d[328]
  PIN t_d[329]
    DIRECTION OUTPUT ;
    USE SIGNAL ;
    PORT
      LAYER M4 ;
        RECT  0 55.68 0.084 55.704 ;
    END
  END t_d[329]
  PIN t_d[32]
    DIRECTION OUTPUT ;
    USE SIGNAL ;
    PORT
      LAYER M4 ;
        RECT  0 41.424 0.084 41.448 ;
    END
  END t_d[32]
  PIN t_d[330]
    DIRECTION OUTPUT ;
    USE SIGNAL ;
    PORT
      LAYER M4 ;
        RECT  0 55.728 0.084 55.752 ;
    END
  END t_d[330]
  PIN t_d[331]
    DIRECTION OUTPUT ;
    USE SIGNAL ;
    PORT
      LAYER M4 ;
        RECT  0 55.776 0.084 55.8 ;
    END
  END t_d[331]
  PIN t_d[332]
    DIRECTION OUTPUT ;
    USE SIGNAL ;
    PORT
      LAYER M4 ;
        RECT  0 55.824 0.084 55.848 ;
    END
  END t_d[332]
  PIN t_d[333]
    DIRECTION OUTPUT ;
    USE SIGNAL ;
    PORT
      LAYER M4 ;
        RECT  0 55.872 0.084 55.896 ;
    END
  END t_d[333]
  PIN t_d[334]
    DIRECTION OUTPUT ;
    USE SIGNAL ;
    PORT
      LAYER M4 ;
        RECT  0 55.92 0.084 55.944 ;
    END
  END t_d[334]
  PIN t_d[335]
    DIRECTION OUTPUT ;
    USE SIGNAL ;
    PORT
      LAYER M4 ;
        RECT  0 55.968 0.084 55.992 ;
    END
  END t_d[335]
  PIN t_d[336]
    DIRECTION OUTPUT ;
    USE SIGNAL ;
    PORT
      LAYER M4 ;
        RECT  0 56.016 0.084 56.04 ;
    END
  END t_d[336]
  PIN t_d[337]
    DIRECTION OUTPUT ;
    USE SIGNAL ;
    PORT
      LAYER M4 ;
        RECT  0 56.064 0.084 56.088 ;
    END
  END t_d[337]
  PIN t_d[338]
    DIRECTION OUTPUT ;
    USE SIGNAL ;
    PORT
      LAYER M4 ;
        RECT  0 56.112 0.084 56.136 ;
    END
  END t_d[338]
  PIN t_d[339]
    DIRECTION OUTPUT ;
    USE SIGNAL ;
    PORT
      LAYER M4 ;
        RECT  0 56.16 0.084 56.184 ;
    END
  END t_d[339]
  PIN t_d[33]
    DIRECTION OUTPUT ;
    USE SIGNAL ;
    PORT
      LAYER M4 ;
        RECT  0 41.472 0.084 41.496 ;
    END
  END t_d[33]
  PIN t_d[340]
    DIRECTION OUTPUT ;
    USE SIGNAL ;
    PORT
      LAYER M4 ;
        RECT  0 56.208 0.084 56.232 ;
    END
  END t_d[340]
  PIN t_d[341]
    DIRECTION OUTPUT ;
    USE SIGNAL ;
    PORT
      LAYER M4 ;
        RECT  0 56.256 0.084 56.28 ;
    END
  END t_d[341]
  PIN t_d[342]
    DIRECTION OUTPUT ;
    USE SIGNAL ;
    PORT
      LAYER M4 ;
        RECT  0 56.304 0.084 56.328 ;
    END
  END t_d[342]
  PIN t_d[343]
    DIRECTION OUTPUT ;
    USE SIGNAL ;
    PORT
      LAYER M4 ;
        RECT  0 56.352 0.084 56.376 ;
    END
  END t_d[343]
  PIN t_d[344]
    DIRECTION OUTPUT ;
    USE SIGNAL ;
    PORT
      LAYER M4 ;
        RECT  0 56.4 0.084 56.424 ;
    END
  END t_d[344]
  PIN t_d[345]
    DIRECTION OUTPUT ;
    USE SIGNAL ;
    PORT
      LAYER M4 ;
        RECT  0 56.448 0.084 56.472 ;
    END
  END t_d[345]
  PIN t_d[346]
    DIRECTION OUTPUT ;
    USE SIGNAL ;
    PORT
      LAYER M4 ;
        RECT  0 56.496 0.084 56.52 ;
    END
  END t_d[346]
  PIN t_d[347]
    DIRECTION OUTPUT ;
    USE SIGNAL ;
    PORT
      LAYER M4 ;
        RECT  0 56.544 0.084 56.568 ;
    END
  END t_d[347]
  PIN t_d[348]
    DIRECTION OUTPUT ;
    USE SIGNAL ;
    PORT
      LAYER M4 ;
        RECT  0 56.592 0.084 56.616 ;
    END
  END t_d[348]
  PIN t_d[349]
    DIRECTION OUTPUT ;
    USE SIGNAL ;
    PORT
      LAYER M4 ;
        RECT  0 56.64 0.084 56.664 ;
    END
  END t_d[349]
  PIN t_d[34]
    DIRECTION OUTPUT ;
    USE SIGNAL ;
    PORT
      LAYER M4 ;
        RECT  0 41.52 0.084 41.544 ;
    END
  END t_d[34]
  PIN t_d[350]
    DIRECTION OUTPUT ;
    USE SIGNAL ;
    PORT
      LAYER M4 ;
        RECT  0 56.688 0.084 56.712 ;
    END
  END t_d[350]
  PIN t_d[351]
    DIRECTION OUTPUT ;
    USE SIGNAL ;
    PORT
      LAYER M4 ;
        RECT  0 56.736 0.084 56.76 ;
    END
  END t_d[351]
  PIN t_d[352]
    DIRECTION OUTPUT ;
    USE SIGNAL ;
    PORT
      LAYER M4 ;
        RECT  0 56.784 0.084 56.808 ;
    END
  END t_d[352]
  PIN t_d[353]
    DIRECTION OUTPUT ;
    USE SIGNAL ;
    PORT
      LAYER M4 ;
        RECT  0 56.832 0.084 56.856 ;
    END
  END t_d[353]
  PIN t_d[354]
    DIRECTION OUTPUT ;
    USE SIGNAL ;
    PORT
      LAYER M4 ;
        RECT  0 56.88 0.084 56.904 ;
    END
  END t_d[354]
  PIN t_d[355]
    DIRECTION OUTPUT ;
    USE SIGNAL ;
    PORT
      LAYER M4 ;
        RECT  0 56.928 0.084 56.952 ;
    END
  END t_d[355]
  PIN t_d[356]
    DIRECTION OUTPUT ;
    USE SIGNAL ;
    PORT
      LAYER M4 ;
        RECT  0 56.976 0.084 57 ;
    END
  END t_d[356]
  PIN t_d[357]
    DIRECTION OUTPUT ;
    USE SIGNAL ;
    PORT
      LAYER M4 ;
        RECT  0 57.024 0.084 57.048 ;
    END
  END t_d[357]
  PIN t_d[358]
    DIRECTION OUTPUT ;
    USE SIGNAL ;
    PORT
      LAYER M4 ;
        RECT  0 57.072 0.084 57.096 ;
    END
  END t_d[358]
  PIN t_d[359]
    DIRECTION OUTPUT ;
    USE SIGNAL ;
    PORT
      LAYER M4 ;
        RECT  0 57.12 0.084 57.144 ;
    END
  END t_d[359]
  PIN t_d[35]
    DIRECTION OUTPUT ;
    USE SIGNAL ;
    PORT
      LAYER M4 ;
        RECT  0 41.568 0.084 41.592 ;
    END
  END t_d[35]
  PIN t_d[360]
    DIRECTION OUTPUT ;
    USE SIGNAL ;
    PORT
      LAYER M4 ;
        RECT  0 57.168 0.084 57.192 ;
    END
  END t_d[360]
  PIN t_d[361]
    DIRECTION OUTPUT ;
    USE SIGNAL ;
    PORT
      LAYER M4 ;
        RECT  0 57.216 0.084 57.24 ;
    END
  END t_d[361]
  PIN t_d[362]
    DIRECTION OUTPUT ;
    USE SIGNAL ;
    PORT
      LAYER M4 ;
        RECT  0 57.264 0.084 57.288 ;
    END
  END t_d[362]
  PIN t_d[363]
    DIRECTION OUTPUT ;
    USE SIGNAL ;
    PORT
      LAYER M4 ;
        RECT  0 57.312 0.084 57.336 ;
    END
  END t_d[363]
  PIN t_d[364]
    DIRECTION OUTPUT ;
    USE SIGNAL ;
    PORT
      LAYER M4 ;
        RECT  0 57.36 0.084 57.384 ;
    END
  END t_d[364]
  PIN t_d[365]
    DIRECTION OUTPUT ;
    USE SIGNAL ;
    PORT
      LAYER M4 ;
        RECT  0 57.408 0.084 57.432 ;
    END
  END t_d[365]
  PIN t_d[366]
    DIRECTION OUTPUT ;
    USE SIGNAL ;
    PORT
      LAYER M4 ;
        RECT  0 57.456 0.084 57.48 ;
    END
  END t_d[366]
  PIN t_d[367]
    DIRECTION OUTPUT ;
    USE SIGNAL ;
    PORT
      LAYER M4 ;
        RECT  0 57.504 0.084 57.528 ;
    END
  END t_d[367]
  PIN t_d[368]
    DIRECTION OUTPUT ;
    USE SIGNAL ;
    PORT
      LAYER M4 ;
        RECT  0 57.552 0.084 57.576 ;
    END
  END t_d[368]
  PIN t_d[369]
    DIRECTION OUTPUT ;
    USE SIGNAL ;
    PORT
      LAYER M4 ;
        RECT  0 57.6 0.084 57.624 ;
    END
  END t_d[369]
  PIN t_d[36]
    DIRECTION OUTPUT ;
    USE SIGNAL ;
    PORT
      LAYER M4 ;
        RECT  0 41.616 0.084 41.64 ;
    END
  END t_d[36]
  PIN t_d[370]
    DIRECTION OUTPUT ;
    USE SIGNAL ;
    PORT
      LAYER M4 ;
        RECT  0 57.648 0.084 57.672 ;
    END
  END t_d[370]
  PIN t_d[371]
    DIRECTION OUTPUT ;
    USE SIGNAL ;
    PORT
      LAYER M4 ;
        RECT  0 57.696 0.084 57.72 ;
    END
  END t_d[371]
  PIN t_d[372]
    DIRECTION OUTPUT ;
    USE SIGNAL ;
    PORT
      LAYER M4 ;
        RECT  0 57.744 0.084 57.768 ;
    END
  END t_d[372]
  PIN t_d[373]
    DIRECTION OUTPUT ;
    USE SIGNAL ;
    PORT
      LAYER M4 ;
        RECT  0 57.792 0.084 57.816 ;
    END
  END t_d[373]
  PIN t_d[374]
    DIRECTION OUTPUT ;
    USE SIGNAL ;
    PORT
      LAYER M4 ;
        RECT  0 57.84 0.084 57.864 ;
    END
  END t_d[374]
  PIN t_d[375]
    DIRECTION OUTPUT ;
    USE SIGNAL ;
    PORT
      LAYER M4 ;
        RECT  0 57.888 0.084 57.912 ;
    END
  END t_d[375]
  PIN t_d[376]
    DIRECTION OUTPUT ;
    USE SIGNAL ;
    PORT
      LAYER M4 ;
        RECT  0 57.936 0.084 57.96 ;
    END
  END t_d[376]
  PIN t_d[377]
    DIRECTION OUTPUT ;
    USE SIGNAL ;
    PORT
      LAYER M4 ;
        RECT  0 57.984 0.084 58.008 ;
    END
  END t_d[377]
  PIN t_d[378]
    DIRECTION OUTPUT ;
    USE SIGNAL ;
    PORT
      LAYER M4 ;
        RECT  0 58.032 0.084 58.056 ;
    END
  END t_d[378]
  PIN t_d[379]
    DIRECTION OUTPUT ;
    USE SIGNAL ;
    PORT
      LAYER M4 ;
        RECT  0 58.08 0.084 58.104 ;
    END
  END t_d[379]
  PIN t_d[37]
    DIRECTION OUTPUT ;
    USE SIGNAL ;
    PORT
      LAYER M4 ;
        RECT  0 41.664 0.084 41.688 ;
    END
  END t_d[37]
  PIN t_d[380]
    DIRECTION OUTPUT ;
    USE SIGNAL ;
    PORT
      LAYER M4 ;
        RECT  0 58.128 0.084 58.152 ;
    END
  END t_d[380]
  PIN t_d[381]
    DIRECTION OUTPUT ;
    USE SIGNAL ;
    PORT
      LAYER M4 ;
        RECT  0 58.176 0.084 58.2 ;
    END
  END t_d[381]
  PIN t_d[382]
    DIRECTION OUTPUT ;
    USE SIGNAL ;
    PORT
      LAYER M4 ;
        RECT  0 58.224 0.084 58.248 ;
    END
  END t_d[382]
  PIN t_d[383]
    DIRECTION OUTPUT ;
    USE SIGNAL ;
    PORT
      LAYER M4 ;
        RECT  0 58.272 0.084 58.296 ;
    END
  END t_d[383]
  PIN t_d[384]
    DIRECTION OUTPUT ;
    USE SIGNAL ;
    PORT
      LAYER M4 ;
        RECT  0 58.32 0.084 58.344 ;
    END
  END t_d[384]
  PIN t_d[385]
    DIRECTION OUTPUT ;
    USE SIGNAL ;
    PORT
      LAYER M4 ;
        RECT  0 58.368 0.084 58.392 ;
    END
  END t_d[385]
  PIN t_d[386]
    DIRECTION OUTPUT ;
    USE SIGNAL ;
    PORT
      LAYER M4 ;
        RECT  0 58.416 0.084 58.44 ;
    END
  END t_d[386]
  PIN t_d[387]
    DIRECTION OUTPUT ;
    USE SIGNAL ;
    PORT
      LAYER M4 ;
        RECT  0 58.464 0.084 58.488 ;
    END
  END t_d[387]
  PIN t_d[388]
    DIRECTION OUTPUT ;
    USE SIGNAL ;
    PORT
      LAYER M4 ;
        RECT  0 58.512 0.084 58.536 ;
    END
  END t_d[388]
  PIN t_d[389]
    DIRECTION OUTPUT ;
    USE SIGNAL ;
    PORT
      LAYER M4 ;
        RECT  0 58.56 0.084 58.584 ;
    END
  END t_d[389]
  PIN t_d[38]
    DIRECTION OUTPUT ;
    USE SIGNAL ;
    PORT
      LAYER M4 ;
        RECT  0 41.712 0.084 41.736 ;
    END
  END t_d[38]
  PIN t_d[390]
    DIRECTION OUTPUT ;
    USE SIGNAL ;
    PORT
      LAYER M4 ;
        RECT  0 58.608 0.084 58.632 ;
    END
  END t_d[390]
  PIN t_d[391]
    DIRECTION OUTPUT ;
    USE SIGNAL ;
    PORT
      LAYER M4 ;
        RECT  0 58.656 0.084 58.68 ;
    END
  END t_d[391]
  PIN t_d[392]
    DIRECTION OUTPUT ;
    USE SIGNAL ;
    PORT
      LAYER M4 ;
        RECT  0 58.704 0.084 58.728 ;
    END
  END t_d[392]
  PIN t_d[393]
    DIRECTION OUTPUT ;
    USE SIGNAL ;
    PORT
      LAYER M4 ;
        RECT  0 58.752 0.084 58.776 ;
    END
  END t_d[393]
  PIN t_d[394]
    DIRECTION OUTPUT ;
    USE SIGNAL ;
    PORT
      LAYER M4 ;
        RECT  0 58.8 0.084 58.824 ;
    END
  END t_d[394]
  PIN t_d[395]
    DIRECTION OUTPUT ;
    USE SIGNAL ;
    PORT
      LAYER M4 ;
        RECT  0 58.848 0.084 58.872 ;
    END
  END t_d[395]
  PIN t_d[396]
    DIRECTION OUTPUT ;
    USE SIGNAL ;
    PORT
      LAYER M4 ;
        RECT  0 58.896 0.084 58.92 ;
    END
  END t_d[396]
  PIN t_d[397]
    DIRECTION OUTPUT ;
    USE SIGNAL ;
    PORT
      LAYER M4 ;
        RECT  0 58.944 0.084 58.968 ;
    END
  END t_d[397]
  PIN t_d[398]
    DIRECTION OUTPUT ;
    USE SIGNAL ;
    PORT
      LAYER M4 ;
        RECT  0 58.992 0.084 59.016 ;
    END
  END t_d[398]
  PIN t_d[399]
    DIRECTION OUTPUT ;
    USE SIGNAL ;
    PORT
      LAYER M4 ;
        RECT  0 59.04 0.084 59.064 ;
    END
  END t_d[399]
  PIN t_d[39]
    DIRECTION OUTPUT ;
    USE SIGNAL ;
    PORT
      LAYER M4 ;
        RECT  0 41.76 0.084 41.784 ;
    END
  END t_d[39]
  PIN t_d[3]
    DIRECTION OUTPUT ;
    USE SIGNAL ;
    PORT
      LAYER M4 ;
        RECT  0 40.032 0.084 40.056 ;
    END
  END t_d[3]
  PIN t_d[400]
    DIRECTION OUTPUT ;
    USE SIGNAL ;
    PORT
      LAYER M4 ;
        RECT  0 59.088 0.084 59.112 ;
    END
  END t_d[400]
  PIN t_d[401]
    DIRECTION OUTPUT ;
    USE SIGNAL ;
    PORT
      LAYER M4 ;
        RECT  0 59.136 0.084 59.16 ;
    END
  END t_d[401]
  PIN t_d[402]
    DIRECTION OUTPUT ;
    USE SIGNAL ;
    PORT
      LAYER M4 ;
        RECT  0 59.184 0.084 59.208 ;
    END
  END t_d[402]
  PIN t_d[403]
    DIRECTION OUTPUT ;
    USE SIGNAL ;
    PORT
      LAYER M4 ;
        RECT  0 59.232 0.084 59.256 ;
    END
  END t_d[403]
  PIN t_d[404]
    DIRECTION OUTPUT ;
    USE SIGNAL ;
    PORT
      LAYER M4 ;
        RECT  0 59.28 0.084 59.304 ;
    END
  END t_d[404]
  PIN t_d[405]
    DIRECTION OUTPUT ;
    USE SIGNAL ;
    PORT
      LAYER M4 ;
        RECT  0 59.328 0.084 59.352 ;
    END
  END t_d[405]
  PIN t_d[406]
    DIRECTION OUTPUT ;
    USE SIGNAL ;
    PORT
      LAYER M4 ;
        RECT  0 59.376 0.084 59.4 ;
    END
  END t_d[406]
  PIN t_d[407]
    DIRECTION OUTPUT ;
    USE SIGNAL ;
    PORT
      LAYER M4 ;
        RECT  0 59.424 0.084 59.448 ;
    END
  END t_d[407]
  PIN t_d[408]
    DIRECTION OUTPUT ;
    USE SIGNAL ;
    PORT
      LAYER M4 ;
        RECT  0 59.472 0.084 59.496 ;
    END
  END t_d[408]
  PIN t_d[409]
    DIRECTION OUTPUT ;
    USE SIGNAL ;
    PORT
      LAYER M4 ;
        RECT  0 59.52 0.084 59.544 ;
    END
  END t_d[409]
  PIN t_d[40]
    DIRECTION OUTPUT ;
    USE SIGNAL ;
    PORT
      LAYER M4 ;
        RECT  0 41.808 0.084 41.832 ;
    END
  END t_d[40]
  PIN t_d[410]
    DIRECTION OUTPUT ;
    USE SIGNAL ;
    PORT
      LAYER M4 ;
        RECT  0 59.568 0.084 59.592 ;
    END
  END t_d[410]
  PIN t_d[411]
    DIRECTION OUTPUT ;
    USE SIGNAL ;
    PORT
      LAYER M4 ;
        RECT  0 59.616 0.084 59.64 ;
    END
  END t_d[411]
  PIN t_d[412]
    DIRECTION OUTPUT ;
    USE SIGNAL ;
    PORT
      LAYER M4 ;
        RECT  0 59.664 0.084 59.688 ;
    END
  END t_d[412]
  PIN t_d[413]
    DIRECTION OUTPUT ;
    USE SIGNAL ;
    PORT
      LAYER M4 ;
        RECT  0 59.712 0.084 59.736 ;
    END
  END t_d[413]
  PIN t_d[414]
    DIRECTION OUTPUT ;
    USE SIGNAL ;
    PORT
      LAYER M4 ;
        RECT  0 59.76 0.084 59.784 ;
    END
  END t_d[414]
  PIN t_d[415]
    DIRECTION OUTPUT ;
    USE SIGNAL ;
    PORT
      LAYER M4 ;
        RECT  0 59.808 0.084 59.832 ;
    END
  END t_d[415]
  PIN t_d[416]
    DIRECTION OUTPUT ;
    USE SIGNAL ;
    PORT
      LAYER M4 ;
        RECT  0 59.856 0.084 59.88 ;
    END
  END t_d[416]
  PIN t_d[417]
    DIRECTION OUTPUT ;
    USE SIGNAL ;
    PORT
      LAYER M4 ;
        RECT  0 59.904 0.084 59.928 ;
    END
  END t_d[417]
  PIN t_d[418]
    DIRECTION OUTPUT ;
    USE SIGNAL ;
    PORT
      LAYER M4 ;
        RECT  0 59.952 0.084 59.976 ;
    END
  END t_d[418]
  PIN t_d[419]
    DIRECTION OUTPUT ;
    USE SIGNAL ;
    PORT
      LAYER M4 ;
        RECT  0 60 0.084 60.024 ;
    END
  END t_d[419]
  PIN t_d[41]
    DIRECTION OUTPUT ;
    USE SIGNAL ;
    PORT
      LAYER M4 ;
        RECT  0 41.856 0.084 41.88 ;
    END
  END t_d[41]
  PIN t_d[420]
    DIRECTION OUTPUT ;
    USE SIGNAL ;
    PORT
      LAYER M4 ;
        RECT  0 60.048 0.084 60.072 ;
    END
  END t_d[420]
  PIN t_d[421]
    DIRECTION OUTPUT ;
    USE SIGNAL ;
    PORT
      LAYER M4 ;
        RECT  0 60.096 0.084 60.12 ;
    END
  END t_d[421]
  PIN t_d[422]
    DIRECTION OUTPUT ;
    USE SIGNAL ;
    PORT
      LAYER M4 ;
        RECT  0 60.144 0.084 60.168 ;
    END
  END t_d[422]
  PIN t_d[423]
    DIRECTION OUTPUT ;
    USE SIGNAL ;
    PORT
      LAYER M4 ;
        RECT  0 60.192 0.084 60.216 ;
    END
  END t_d[423]
  PIN t_d[424]
    DIRECTION OUTPUT ;
    USE SIGNAL ;
    PORT
      LAYER M4 ;
        RECT  0 60.24 0.084 60.264 ;
    END
  END t_d[424]
  PIN t_d[425]
    DIRECTION OUTPUT ;
    USE SIGNAL ;
    PORT
      LAYER M4 ;
        RECT  0 60.288 0.084 60.312 ;
    END
  END t_d[425]
  PIN t_d[426]
    DIRECTION OUTPUT ;
    USE SIGNAL ;
    PORT
      LAYER M4 ;
        RECT  0 60.336 0.084 60.36 ;
    END
  END t_d[426]
  PIN t_d[427]
    DIRECTION OUTPUT ;
    USE SIGNAL ;
    PORT
      LAYER M4 ;
        RECT  0 60.384 0.084 60.408 ;
    END
  END t_d[427]
  PIN t_d[428]
    DIRECTION OUTPUT ;
    USE SIGNAL ;
    PORT
      LAYER M4 ;
        RECT  0 60.432 0.084 60.456 ;
    END
  END t_d[428]
  PIN t_d[429]
    DIRECTION OUTPUT ;
    USE SIGNAL ;
    PORT
      LAYER M4 ;
        RECT  0 60.48 0.084 60.504 ;
    END
  END t_d[429]
  PIN t_d[42]
    DIRECTION OUTPUT ;
    USE SIGNAL ;
    PORT
      LAYER M4 ;
        RECT  0 41.904 0.084 41.928 ;
    END
  END t_d[42]
  PIN t_d[430]
    DIRECTION OUTPUT ;
    USE SIGNAL ;
    PORT
      LAYER M4 ;
        RECT  0 60.528 0.084 60.552 ;
    END
  END t_d[430]
  PIN t_d[431]
    DIRECTION OUTPUT ;
    USE SIGNAL ;
    PORT
      LAYER M4 ;
        RECT  0 60.576 0.084 60.6 ;
    END
  END t_d[431]
  PIN t_d[432]
    DIRECTION OUTPUT ;
    USE SIGNAL ;
    PORT
      LAYER M4 ;
        RECT  0 60.624 0.084 60.648 ;
    END
  END t_d[432]
  PIN t_d[433]
    DIRECTION OUTPUT ;
    USE SIGNAL ;
    PORT
      LAYER M4 ;
        RECT  0 60.672 0.084 60.696 ;
    END
  END t_d[433]
  PIN t_d[434]
    DIRECTION OUTPUT ;
    USE SIGNAL ;
    PORT
      LAYER M4 ;
        RECT  0 60.72 0.084 60.744 ;
    END
  END t_d[434]
  PIN t_d[435]
    DIRECTION OUTPUT ;
    USE SIGNAL ;
    PORT
      LAYER M4 ;
        RECT  0 60.768 0.084 60.792 ;
    END
  END t_d[435]
  PIN t_d[436]
    DIRECTION OUTPUT ;
    USE SIGNAL ;
    PORT
      LAYER M4 ;
        RECT  0 60.816 0.084 60.84 ;
    END
  END t_d[436]
  PIN t_d[437]
    DIRECTION OUTPUT ;
    USE SIGNAL ;
    PORT
      LAYER M4 ;
        RECT  0 60.864 0.084 60.888 ;
    END
  END t_d[437]
  PIN t_d[438]
    DIRECTION OUTPUT ;
    USE SIGNAL ;
    PORT
      LAYER M4 ;
        RECT  0 60.912 0.084 60.936 ;
    END
  END t_d[438]
  PIN t_d[439]
    DIRECTION OUTPUT ;
    USE SIGNAL ;
    PORT
      LAYER M4 ;
        RECT  0 60.96 0.084 60.984 ;
    END
  END t_d[439]
  PIN t_d[43]
    DIRECTION OUTPUT ;
    USE SIGNAL ;
    PORT
      LAYER M4 ;
        RECT  0 41.952 0.084 41.976 ;
    END
  END t_d[43]
  PIN t_d[440]
    DIRECTION OUTPUT ;
    USE SIGNAL ;
    PORT
      LAYER M4 ;
        RECT  0 61.008 0.084 61.032 ;
    END
  END t_d[440]
  PIN t_d[441]
    DIRECTION OUTPUT ;
    USE SIGNAL ;
    PORT
      LAYER M4 ;
        RECT  0 61.056 0.084 61.08 ;
    END
  END t_d[441]
  PIN t_d[442]
    DIRECTION OUTPUT ;
    USE SIGNAL ;
    PORT
      LAYER M4 ;
        RECT  0 61.104 0.084 61.128 ;
    END
  END t_d[442]
  PIN t_d[443]
    DIRECTION OUTPUT ;
    USE SIGNAL ;
    PORT
      LAYER M4 ;
        RECT  0 61.152 0.084 61.176 ;
    END
  END t_d[443]
  PIN t_d[444]
    DIRECTION OUTPUT ;
    USE SIGNAL ;
    PORT
      LAYER M4 ;
        RECT  0 61.2 0.084 61.224 ;
    END
  END t_d[444]
  PIN t_d[445]
    DIRECTION OUTPUT ;
    USE SIGNAL ;
    PORT
      LAYER M4 ;
        RECT  0 61.248 0.084 61.272 ;
    END
  END t_d[445]
  PIN t_d[446]
    DIRECTION OUTPUT ;
    USE SIGNAL ;
    PORT
      LAYER M4 ;
        RECT  0 61.296 0.084 61.32 ;
    END
  END t_d[446]
  PIN t_d[447]
    DIRECTION OUTPUT ;
    USE SIGNAL ;
    PORT
      LAYER M4 ;
        RECT  0 61.344 0.084 61.368 ;
    END
  END t_d[447]
  PIN t_d[448]
    DIRECTION OUTPUT ;
    USE SIGNAL ;
    PORT
      LAYER M4 ;
        RECT  0 61.392 0.084 61.416 ;
    END
  END t_d[448]
  PIN t_d[449]
    DIRECTION OUTPUT ;
    USE SIGNAL ;
    PORT
      LAYER M4 ;
        RECT  0 61.44 0.084 61.464 ;
    END
  END t_d[449]
  PIN t_d[44]
    DIRECTION OUTPUT ;
    USE SIGNAL ;
    PORT
      LAYER M4 ;
        RECT  0 42 0.084 42.024 ;
    END
  END t_d[44]
  PIN t_d[450]
    DIRECTION OUTPUT ;
    USE SIGNAL ;
    PORT
      LAYER M4 ;
        RECT  0 61.488 0.084 61.512 ;
    END
  END t_d[450]
  PIN t_d[451]
    DIRECTION OUTPUT ;
    USE SIGNAL ;
    PORT
      LAYER M4 ;
        RECT  0 61.536 0.084 61.56 ;
    END
  END t_d[451]
  PIN t_d[452]
    DIRECTION OUTPUT ;
    USE SIGNAL ;
    PORT
      LAYER M4 ;
        RECT  0 61.584 0.084 61.608 ;
    END
  END t_d[452]
  PIN t_d[453]
    DIRECTION OUTPUT ;
    USE SIGNAL ;
    PORT
      LAYER M4 ;
        RECT  0 61.632 0.084 61.656 ;
    END
  END t_d[453]
  PIN t_d[454]
    DIRECTION OUTPUT ;
    USE SIGNAL ;
    PORT
      LAYER M4 ;
        RECT  0 61.68 0.084 61.704 ;
    END
  END t_d[454]
  PIN t_d[455]
    DIRECTION OUTPUT ;
    USE SIGNAL ;
    PORT
      LAYER M4 ;
        RECT  0 61.728 0.084 61.752 ;
    END
  END t_d[455]
  PIN t_d[456]
    DIRECTION OUTPUT ;
    USE SIGNAL ;
    PORT
      LAYER M4 ;
        RECT  0 61.776 0.084 61.8 ;
    END
  END t_d[456]
  PIN t_d[457]
    DIRECTION OUTPUT ;
    USE SIGNAL ;
    PORT
      LAYER M4 ;
        RECT  0 61.824 0.084 61.848 ;
    END
  END t_d[457]
  PIN t_d[458]
    DIRECTION OUTPUT ;
    USE SIGNAL ;
    PORT
      LAYER M4 ;
        RECT  0 61.872 0.084 61.896 ;
    END
  END t_d[458]
  PIN t_d[459]
    DIRECTION OUTPUT ;
    USE SIGNAL ;
    PORT
      LAYER M4 ;
        RECT  0 61.92 0.084 61.944 ;
    END
  END t_d[459]
  PIN t_d[45]
    DIRECTION OUTPUT ;
    USE SIGNAL ;
    PORT
      LAYER M4 ;
        RECT  0 42.048 0.084 42.072 ;
    END
  END t_d[45]
  PIN t_d[460]
    DIRECTION OUTPUT ;
    USE SIGNAL ;
    PORT
      LAYER M4 ;
        RECT  0 61.968 0.084 61.992 ;
    END
  END t_d[460]
  PIN t_d[461]
    DIRECTION OUTPUT ;
    USE SIGNAL ;
    PORT
      LAYER M4 ;
        RECT  0 62.016 0.084 62.04 ;
    END
  END t_d[461]
  PIN t_d[462]
    DIRECTION OUTPUT ;
    USE SIGNAL ;
    PORT
      LAYER M4 ;
        RECT  0 62.064 0.084 62.088 ;
    END
  END t_d[462]
  PIN t_d[463]
    DIRECTION OUTPUT ;
    USE SIGNAL ;
    PORT
      LAYER M4 ;
        RECT  0 62.112 0.084 62.136 ;
    END
  END t_d[463]
  PIN t_d[464]
    DIRECTION OUTPUT ;
    USE SIGNAL ;
    PORT
      LAYER M4 ;
        RECT  0 62.16 0.084 62.184 ;
    END
  END t_d[464]
  PIN t_d[465]
    DIRECTION OUTPUT ;
    USE SIGNAL ;
    PORT
      LAYER M4 ;
        RECT  0 62.208 0.084 62.232 ;
    END
  END t_d[465]
  PIN t_d[466]
    DIRECTION OUTPUT ;
    USE SIGNAL ;
    PORT
      LAYER M4 ;
        RECT  0 62.256 0.084 62.28 ;
    END
  END t_d[466]
  PIN t_d[467]
    DIRECTION OUTPUT ;
    USE SIGNAL ;
    PORT
      LAYER M4 ;
        RECT  0 62.304 0.084 62.328 ;
    END
  END t_d[467]
  PIN t_d[468]
    DIRECTION OUTPUT ;
    USE SIGNAL ;
    PORT
      LAYER M4 ;
        RECT  0 62.352 0.084 62.376 ;
    END
  END t_d[468]
  PIN t_d[469]
    DIRECTION OUTPUT ;
    USE SIGNAL ;
    PORT
      LAYER M4 ;
        RECT  0 62.4 0.084 62.424 ;
    END
  END t_d[469]
  PIN t_d[46]
    DIRECTION OUTPUT ;
    USE SIGNAL ;
    PORT
      LAYER M4 ;
        RECT  0 42.096 0.084 42.12 ;
    END
  END t_d[46]
  PIN t_d[470]
    DIRECTION OUTPUT ;
    USE SIGNAL ;
    PORT
      LAYER M4 ;
        RECT  0 62.448 0.084 62.472 ;
    END
  END t_d[470]
  PIN t_d[471]
    DIRECTION OUTPUT ;
    USE SIGNAL ;
    PORT
      LAYER M4 ;
        RECT  0 62.496 0.084 62.52 ;
    END
  END t_d[471]
  PIN t_d[472]
    DIRECTION OUTPUT ;
    USE SIGNAL ;
    PORT
      LAYER M4 ;
        RECT  0 62.544 0.084 62.568 ;
    END
  END t_d[472]
  PIN t_d[473]
    DIRECTION OUTPUT ;
    USE SIGNAL ;
    PORT
      LAYER M4 ;
        RECT  0 62.592 0.084 62.616 ;
    END
  END t_d[473]
  PIN t_d[474]
    DIRECTION OUTPUT ;
    USE SIGNAL ;
    PORT
      LAYER M4 ;
        RECT  0 62.64 0.084 62.664 ;
    END
  END t_d[474]
  PIN t_d[475]
    DIRECTION OUTPUT ;
    USE SIGNAL ;
    PORT
      LAYER M4 ;
        RECT  0 62.688 0.084 62.712 ;
    END
  END t_d[475]
  PIN t_d[476]
    DIRECTION OUTPUT ;
    USE SIGNAL ;
    PORT
      LAYER M4 ;
        RECT  0 62.736 0.084 62.76 ;
    END
  END t_d[476]
  PIN t_d[477]
    DIRECTION OUTPUT ;
    USE SIGNAL ;
    PORT
      LAYER M4 ;
        RECT  0 62.784 0.084 62.808 ;
    END
  END t_d[477]
  PIN t_d[478]
    DIRECTION OUTPUT ;
    USE SIGNAL ;
    PORT
      LAYER M4 ;
        RECT  0 62.832 0.084 62.856 ;
    END
  END t_d[478]
  PIN t_d[479]
    DIRECTION OUTPUT ;
    USE SIGNAL ;
    PORT
      LAYER M4 ;
        RECT  0 62.88 0.084 62.904 ;
    END
  END t_d[479]
  PIN t_d[47]
    DIRECTION OUTPUT ;
    USE SIGNAL ;
    PORT
      LAYER M4 ;
        RECT  0 42.144 0.084 42.168 ;
    END
  END t_d[47]
  PIN t_d[480]
    DIRECTION OUTPUT ;
    USE SIGNAL ;
    PORT
      LAYER M4 ;
        RECT  0 62.928 0.084 62.952 ;
    END
  END t_d[480]
  PIN t_d[481]
    DIRECTION OUTPUT ;
    USE SIGNAL ;
    PORT
      LAYER M4 ;
        RECT  0 62.976 0.084 63 ;
    END
  END t_d[481]
  PIN t_d[482]
    DIRECTION OUTPUT ;
    USE SIGNAL ;
    PORT
      LAYER M4 ;
        RECT  0 63.024 0.084 63.048 ;
    END
  END t_d[482]
  PIN t_d[483]
    DIRECTION OUTPUT ;
    USE SIGNAL ;
    PORT
      LAYER M4 ;
        RECT  0 63.072 0.084 63.096 ;
    END
  END t_d[483]
  PIN t_d[484]
    DIRECTION OUTPUT ;
    USE SIGNAL ;
    PORT
      LAYER M4 ;
        RECT  0 63.12 0.084 63.144 ;
    END
  END t_d[484]
  PIN t_d[485]
    DIRECTION OUTPUT ;
    USE SIGNAL ;
    PORT
      LAYER M4 ;
        RECT  0 63.168 0.084 63.192 ;
    END
  END t_d[485]
  PIN t_d[486]
    DIRECTION OUTPUT ;
    USE SIGNAL ;
    PORT
      LAYER M4 ;
        RECT  0 63.216 0.084 63.24 ;
    END
  END t_d[486]
  PIN t_d[487]
    DIRECTION OUTPUT ;
    USE SIGNAL ;
    PORT
      LAYER M4 ;
        RECT  0 63.264 0.084 63.288 ;
    END
  END t_d[487]
  PIN t_d[488]
    DIRECTION OUTPUT ;
    USE SIGNAL ;
    PORT
      LAYER M4 ;
        RECT  0 63.312 0.084 63.336 ;
    END
  END t_d[488]
  PIN t_d[489]
    DIRECTION OUTPUT ;
    USE SIGNAL ;
    PORT
      LAYER M4 ;
        RECT  0 63.36 0.084 63.384 ;
    END
  END t_d[489]
  PIN t_d[48]
    DIRECTION OUTPUT ;
    USE SIGNAL ;
    PORT
      LAYER M4 ;
        RECT  0 42.192 0.084 42.216 ;
    END
  END t_d[48]
  PIN t_d[490]
    DIRECTION OUTPUT ;
    USE SIGNAL ;
    PORT
      LAYER M4 ;
        RECT  0 63.408 0.084 63.432 ;
    END
  END t_d[490]
  PIN t_d[491]
    DIRECTION OUTPUT ;
    USE SIGNAL ;
    PORT
      LAYER M4 ;
        RECT  0 63.456 0.084 63.48 ;
    END
  END t_d[491]
  PIN t_d[492]
    DIRECTION OUTPUT ;
    USE SIGNAL ;
    PORT
      LAYER M4 ;
        RECT  0 63.504 0.084 63.528 ;
    END
  END t_d[492]
  PIN t_d[493]
    DIRECTION OUTPUT ;
    USE SIGNAL ;
    PORT
      LAYER M4 ;
        RECT  0 63.552 0.084 63.576 ;
    END
  END t_d[493]
  PIN t_d[494]
    DIRECTION OUTPUT ;
    USE SIGNAL ;
    PORT
      LAYER M4 ;
        RECT  0 63.6 0.084 63.624 ;
    END
  END t_d[494]
  PIN t_d[495]
    DIRECTION OUTPUT ;
    USE SIGNAL ;
    PORT
      LAYER M4 ;
        RECT  0 63.648 0.084 63.672 ;
    END
  END t_d[495]
  PIN t_d[496]
    DIRECTION OUTPUT ;
    USE SIGNAL ;
    PORT
      LAYER M4 ;
        RECT  0 63.696 0.084 63.72 ;
    END
  END t_d[496]
  PIN t_d[497]
    DIRECTION OUTPUT ;
    USE SIGNAL ;
    PORT
      LAYER M4 ;
        RECT  0 63.744 0.084 63.768 ;
    END
  END t_d[497]
  PIN t_d[498]
    DIRECTION OUTPUT ;
    USE SIGNAL ;
    PORT
      LAYER M4 ;
        RECT  0 63.792 0.084 63.816 ;
    END
  END t_d[498]
  PIN t_d[499]
    DIRECTION OUTPUT ;
    USE SIGNAL ;
    PORT
      LAYER M4 ;
        RECT  0 63.84 0.084 63.864 ;
    END
  END t_d[499]
  PIN t_d[49]
    DIRECTION OUTPUT ;
    USE SIGNAL ;
    PORT
      LAYER M4 ;
        RECT  0 42.24 0.084 42.264 ;
    END
  END t_d[49]
  PIN t_d[4]
    DIRECTION OUTPUT ;
    USE SIGNAL ;
    PORT
      LAYER M4 ;
        RECT  0 40.08 0.084 40.104 ;
    END
  END t_d[4]
  PIN t_d[500]
    DIRECTION OUTPUT ;
    USE SIGNAL ;
    PORT
      LAYER M4 ;
        RECT  0 63.888 0.084 63.912 ;
    END
  END t_d[500]
  PIN t_d[501]
    DIRECTION OUTPUT ;
    USE SIGNAL ;
    PORT
      LAYER M4 ;
        RECT  0 63.936 0.084 63.96 ;
    END
  END t_d[501]
  PIN t_d[502]
    DIRECTION OUTPUT ;
    USE SIGNAL ;
    PORT
      LAYER M4 ;
        RECT  0 63.984 0.084 64.008 ;
    END
  END t_d[502]
  PIN t_d[503]
    DIRECTION OUTPUT ;
    USE SIGNAL ;
    PORT
      LAYER M4 ;
        RECT  0 64.032 0.084 64.056 ;
    END
  END t_d[503]
  PIN t_d[504]
    DIRECTION OUTPUT ;
    USE SIGNAL ;
    PORT
      LAYER M4 ;
        RECT  0 64.08 0.084 64.104 ;
    END
  END t_d[504]
  PIN t_d[505]
    DIRECTION OUTPUT ;
    USE SIGNAL ;
    PORT
      LAYER M4 ;
        RECT  0 64.128 0.084 64.152 ;
    END
  END t_d[505]
  PIN t_d[506]
    DIRECTION OUTPUT ;
    USE SIGNAL ;
    PORT
      LAYER M4 ;
        RECT  0 64.176 0.084 64.2 ;
    END
  END t_d[506]
  PIN t_d[507]
    DIRECTION OUTPUT ;
    USE SIGNAL ;
    PORT
      LAYER M4 ;
        RECT  0 64.224 0.084 64.248 ;
    END
  END t_d[507]
  PIN t_d[50]
    DIRECTION OUTPUT ;
    USE SIGNAL ;
    PORT
      LAYER M4 ;
        RECT  0 42.288 0.084 42.312 ;
    END
  END t_d[50]
  PIN t_d[51]
    DIRECTION OUTPUT ;
    USE SIGNAL ;
    PORT
      LAYER M4 ;
        RECT  0 42.336 0.084 42.36 ;
    END
  END t_d[51]
  PIN t_d[52]
    DIRECTION OUTPUT ;
    USE SIGNAL ;
    PORT
      LAYER M4 ;
        RECT  0 42.384 0.084 42.408 ;
    END
  END t_d[52]
  PIN t_d[53]
    DIRECTION OUTPUT ;
    USE SIGNAL ;
    PORT
      LAYER M4 ;
        RECT  0 42.432 0.084 42.456 ;
    END
  END t_d[53]
  PIN t_d[54]
    DIRECTION OUTPUT ;
    USE SIGNAL ;
    PORT
      LAYER M4 ;
        RECT  0 42.48 0.084 42.504 ;
    END
  END t_d[54]
  PIN t_d[55]
    DIRECTION OUTPUT ;
    USE SIGNAL ;
    PORT
      LAYER M4 ;
        RECT  0 42.528 0.084 42.552 ;
    END
  END t_d[55]
  PIN t_d[56]
    DIRECTION OUTPUT ;
    USE SIGNAL ;
    PORT
      LAYER M4 ;
        RECT  0 42.576 0.084 42.6 ;
    END
  END t_d[56]
  PIN t_d[57]
    DIRECTION OUTPUT ;
    USE SIGNAL ;
    PORT
      LAYER M4 ;
        RECT  0 42.624 0.084 42.648 ;
    END
  END t_d[57]
  PIN t_d[58]
    DIRECTION OUTPUT ;
    USE SIGNAL ;
    PORT
      LAYER M4 ;
        RECT  0 42.672 0.084 42.696 ;
    END
  END t_d[58]
  PIN t_d[59]
    DIRECTION OUTPUT ;
    USE SIGNAL ;
    PORT
      LAYER M4 ;
        RECT  0 42.72 0.084 42.744 ;
    END
  END t_d[59]
  PIN t_d[5]
    DIRECTION OUTPUT ;
    USE SIGNAL ;
    PORT
      LAYER M4 ;
        RECT  0 40.128 0.084 40.152 ;
    END
  END t_d[5]
  PIN t_d[60]
    DIRECTION OUTPUT ;
    USE SIGNAL ;
    PORT
      LAYER M4 ;
        RECT  0 42.768 0.084 42.792 ;
    END
  END t_d[60]
  PIN t_d[61]
    DIRECTION OUTPUT ;
    USE SIGNAL ;
    PORT
      LAYER M4 ;
        RECT  0 42.816 0.084 42.84 ;
    END
  END t_d[61]
  PIN t_d[62]
    DIRECTION OUTPUT ;
    USE SIGNAL ;
    PORT
      LAYER M4 ;
        RECT  0 42.864 0.084 42.888 ;
    END
  END t_d[62]
  PIN t_d[63]
    DIRECTION OUTPUT ;
    USE SIGNAL ;
    PORT
      LAYER M4 ;
        RECT  0 42.912 0.084 42.936 ;
    END
  END t_d[63]
  PIN t_d[64]
    DIRECTION OUTPUT ;
    USE SIGNAL ;
    PORT
      LAYER M4 ;
        RECT  0 42.96 0.084 42.984 ;
    END
  END t_d[64]
  PIN t_d[65]
    DIRECTION OUTPUT ;
    USE SIGNAL ;
    PORT
      LAYER M4 ;
        RECT  0 43.008 0.084 43.032 ;
    END
  END t_d[65]
  PIN t_d[66]
    DIRECTION OUTPUT ;
    USE SIGNAL ;
    PORT
      LAYER M4 ;
        RECT  0 43.056 0.084 43.08 ;
    END
  END t_d[66]
  PIN t_d[67]
    DIRECTION OUTPUT ;
    USE SIGNAL ;
    PORT
      LAYER M4 ;
        RECT  0 43.104 0.084 43.128 ;
    END
  END t_d[67]
  PIN t_d[68]
    DIRECTION OUTPUT ;
    USE SIGNAL ;
    PORT
      LAYER M4 ;
        RECT  0 43.152 0.084 43.176 ;
    END
  END t_d[68]
  PIN t_d[69]
    DIRECTION OUTPUT ;
    USE SIGNAL ;
    PORT
      LAYER M4 ;
        RECT  0 43.2 0.084 43.224 ;
    END
  END t_d[69]
  PIN t_d[6]
    DIRECTION OUTPUT ;
    USE SIGNAL ;
    PORT
      LAYER M4 ;
        RECT  0 40.176 0.084 40.2 ;
    END
  END t_d[6]
  PIN t_d[70]
    DIRECTION OUTPUT ;
    USE SIGNAL ;
    PORT
      LAYER M4 ;
        RECT  0 43.248 0.084 43.272 ;
    END
  END t_d[70]
  PIN t_d[71]
    DIRECTION OUTPUT ;
    USE SIGNAL ;
    PORT
      LAYER M4 ;
        RECT  0 43.296 0.084 43.32 ;
    END
  END t_d[71]
  PIN t_d[72]
    DIRECTION OUTPUT ;
    USE SIGNAL ;
    PORT
      LAYER M4 ;
        RECT  0 43.344 0.084 43.368 ;
    END
  END t_d[72]
  PIN t_d[73]
    DIRECTION OUTPUT ;
    USE SIGNAL ;
    PORT
      LAYER M4 ;
        RECT  0 43.392 0.084 43.416 ;
    END
  END t_d[73]
  PIN t_d[74]
    DIRECTION OUTPUT ;
    USE SIGNAL ;
    PORT
      LAYER M4 ;
        RECT  0 43.44 0.084 43.464 ;
    END
  END t_d[74]
  PIN t_d[75]
    DIRECTION OUTPUT ;
    USE SIGNAL ;
    PORT
      LAYER M4 ;
        RECT  0 43.488 0.084 43.512 ;
    END
  END t_d[75]
  PIN t_d[76]
    DIRECTION OUTPUT ;
    USE SIGNAL ;
    PORT
      LAYER M4 ;
        RECT  0 43.536 0.084 43.56 ;
    END
  END t_d[76]
  PIN t_d[77]
    DIRECTION OUTPUT ;
    USE SIGNAL ;
    PORT
      LAYER M4 ;
        RECT  0 43.584 0.084 43.608 ;
    END
  END t_d[77]
  PIN t_d[78]
    DIRECTION OUTPUT ;
    USE SIGNAL ;
    PORT
      LAYER M4 ;
        RECT  0 43.632 0.084 43.656 ;
    END
  END t_d[78]
  PIN t_d[79]
    DIRECTION OUTPUT ;
    USE SIGNAL ;
    PORT
      LAYER M4 ;
        RECT  0 43.68 0.084 43.704 ;
    END
  END t_d[79]
  PIN t_d[7]
    DIRECTION OUTPUT ;
    USE SIGNAL ;
    PORT
      LAYER M4 ;
        RECT  0 40.224 0.084 40.248 ;
    END
  END t_d[7]
  PIN t_d[80]
    DIRECTION OUTPUT ;
    USE SIGNAL ;
    PORT
      LAYER M4 ;
        RECT  0 43.728 0.084 43.752 ;
    END
  END t_d[80]
  PIN t_d[81]
    DIRECTION OUTPUT ;
    USE SIGNAL ;
    PORT
      LAYER M4 ;
        RECT  0 43.776 0.084 43.8 ;
    END
  END t_d[81]
  PIN t_d[82]
    DIRECTION OUTPUT ;
    USE SIGNAL ;
    PORT
      LAYER M4 ;
        RECT  0 43.824 0.084 43.848 ;
    END
  END t_d[82]
  PIN t_d[83]
    DIRECTION OUTPUT ;
    USE SIGNAL ;
    PORT
      LAYER M4 ;
        RECT  0 43.872 0.084 43.896 ;
    END
  END t_d[83]
  PIN t_d[84]
    DIRECTION OUTPUT ;
    USE SIGNAL ;
    PORT
      LAYER M4 ;
        RECT  0 43.92 0.084 43.944 ;
    END
  END t_d[84]
  PIN t_d[85]
    DIRECTION OUTPUT ;
    USE SIGNAL ;
    PORT
      LAYER M4 ;
        RECT  0 43.968 0.084 43.992 ;
    END
  END t_d[85]
  PIN t_d[86]
    DIRECTION OUTPUT ;
    USE SIGNAL ;
    PORT
      LAYER M4 ;
        RECT  0 44.016 0.084 44.04 ;
    END
  END t_d[86]
  PIN t_d[87]
    DIRECTION OUTPUT ;
    USE SIGNAL ;
    PORT
      LAYER M4 ;
        RECT  0 44.064 0.084 44.088 ;
    END
  END t_d[87]
  PIN t_d[88]
    DIRECTION OUTPUT ;
    USE SIGNAL ;
    PORT
      LAYER M4 ;
        RECT  0 44.112 0.084 44.136 ;
    END
  END t_d[88]
  PIN t_d[89]
    DIRECTION OUTPUT ;
    USE SIGNAL ;
    PORT
      LAYER M4 ;
        RECT  0 44.16 0.084 44.184 ;
    END
  END t_d[89]
  PIN t_d[8]
    DIRECTION OUTPUT ;
    USE SIGNAL ;
    PORT
      LAYER M4 ;
        RECT  0 40.272 0.084 40.296 ;
    END
  END t_d[8]
  PIN t_d[90]
    DIRECTION OUTPUT ;
    USE SIGNAL ;
    PORT
      LAYER M4 ;
        RECT  0 44.208 0.084 44.232 ;
    END
  END t_d[90]
  PIN t_d[91]
    DIRECTION OUTPUT ;
    USE SIGNAL ;
    PORT
      LAYER M4 ;
        RECT  0 44.256 0.084 44.28 ;
    END
  END t_d[91]
  PIN t_d[92]
    DIRECTION OUTPUT ;
    USE SIGNAL ;
    PORT
      LAYER M4 ;
        RECT  0 44.304 0.084 44.328 ;
    END
  END t_d[92]
  PIN t_d[93]
    DIRECTION OUTPUT ;
    USE SIGNAL ;
    PORT
      LAYER M4 ;
        RECT  0 44.352 0.084 44.376 ;
    END
  END t_d[93]
  PIN t_d[94]
    DIRECTION OUTPUT ;
    USE SIGNAL ;
    PORT
      LAYER M4 ;
        RECT  0 44.4 0.084 44.424 ;
    END
  END t_d[94]
  PIN t_d[95]
    DIRECTION OUTPUT ;
    USE SIGNAL ;
    PORT
      LAYER M4 ;
        RECT  0 44.448 0.084 44.472 ;
    END
  END t_d[95]
  PIN t_d[96]
    DIRECTION OUTPUT ;
    USE SIGNAL ;
    PORT
      LAYER M4 ;
        RECT  0 44.496 0.084 44.52 ;
    END
  END t_d[96]
  PIN t_d[97]
    DIRECTION OUTPUT ;
    USE SIGNAL ;
    PORT
      LAYER M4 ;
        RECT  0 44.544 0.084 44.568 ;
    END
  END t_d[97]
  PIN t_d[98]
    DIRECTION OUTPUT ;
    USE SIGNAL ;
    PORT
      LAYER M4 ;
        RECT  0 44.592 0.084 44.616 ;
    END
  END t_d[98]
  PIN t_d[99]
    DIRECTION OUTPUT ;
    USE SIGNAL ;
    PORT
      LAYER M4 ;
        RECT  0 44.64 0.084 44.664 ;
    END
  END t_d[99]
  PIN t_d[9]
    DIRECTION OUTPUT ;
    USE SIGNAL ;
    PORT
      LAYER M4 ;
        RECT  0 40.32 0.084 40.344 ;
    END
  END t_d[9]
  PIN t_r
    DIRECTION INPUT ;
    USE SIGNAL ;
    PORT
      LAYER M4 ;
        RECT  0 64.272 0.084 64.296 ;
    END
  END t_r
  PIN VDD
    DIRECTION INOUT ;
    USE POWER ;
    PORT
      LAYER M6 ;
        RECT  2.16 100.113 50.49 100.401 ;
        RECT  2.16 94.713 50.49 95.001 ;
        RECT  2.16 89.313 50.49 89.601 ;
        RECT  2.16 83.913 50.49 84.201 ;
        RECT  2.16 78.513 50.49 78.801 ;
        RECT  2.16 73.113 50.49 73.401 ;
        RECT  2.16 67.713 50.49 68.001 ;
        RECT  2.16 62.313 50.49 62.601 ;
        RECT  2.16 56.913 50.49 57.201 ;
        RECT  2.16 51.513 50.49 51.801 ;
        RECT  2.16 46.113 50.49 46.401 ;
        RECT  2.16 40.713 50.49 41.001 ;
        RECT  2.16 35.313 50.49 35.601 ;
        RECT  2.16 29.913 50.49 30.201 ;
        RECT  2.16 24.513 50.49 24.801 ;
        RECT  2.16 19.113 50.49 19.401 ;
        RECT  2.16 13.713 50.49 14.001 ;
        RECT  2.16 8.313 50.49 8.601 ;
        RECT  2.16 2.913 50.49 3.201 ;
    END
  END VDD
  PIN VSS
    DIRECTION INOUT ;
    USE GROUND ;
    PORT
      LAYER M6 ;
        RECT  2.16 99.729 50.49 100.017 ;
        RECT  2.16 94.329 50.49 94.617 ;
        RECT  2.16 88.929 50.49 89.217 ;
        RECT  2.16 83.529 50.49 83.817 ;
        RECT  2.16 78.129 50.49 78.417 ;
        RECT  2.16 72.729 50.49 73.017 ;
        RECT  2.16 67.329 50.49 67.617 ;
        RECT  2.16 61.929 50.49 62.217 ;
        RECT  2.16 56.529 50.49 56.817 ;
        RECT  2.16 51.129 50.49 51.417 ;
        RECT  2.16 45.729 50.49 46.017 ;
        RECT  2.16 40.329 50.49 40.617 ;
        RECT  2.16 34.929 50.49 35.217 ;
        RECT  2.16 29.529 50.49 29.817 ;
        RECT  2.16 24.129 50.49 24.417 ;
        RECT  2.16 18.729 50.49 19.017 ;
        RECT  2.16 13.329 50.49 13.617 ;
        RECT  2.16 7.929 50.49 8.217 ;
        RECT  2.16 2.529 50.49 2.817 ;
    END
  END VSS
  OBS
    LAYER RVTN ;
     RECT  2.16 2.16 50.49 2.295 ;
     RECT  2.16 2.565 50.49 2.835 ;
     RECT  2.16 3.105 50.49 3.375 ;
     RECT  2.16 3.645 50.49 3.915 ;
     RECT  2.16 4.185 50.49 4.455 ;
     RECT  2.16 4.725 50.49 4.995 ;
     RECT  2.16 5.265 50.49 5.535 ;
     RECT  2.16 5.805 50.49 6.075 ;
     RECT  2.16 6.345 50.49 6.615 ;
     RECT  2.16 6.885 50.49 7.155 ;
     RECT  2.16 7.425 50.49 7.695 ;
     RECT  2.16 7.965 50.49 8.235 ;
     RECT  2.16 8.505 50.49 8.775 ;
     RECT  2.16 9.045 50.49 9.315 ;
     RECT  2.16 9.585 50.49 9.855 ;
     RECT  2.16 10.125 50.49 10.395 ;
     RECT  2.16 10.665 50.49 10.935 ;
     RECT  2.16 11.205 50.49 11.475 ;
     RECT  2.16 11.745 50.49 12.015 ;
     RECT  2.16 12.285 50.49 12.555 ;
     RECT  2.16 12.825 50.49 13.095 ;
     RECT  2.16 13.365 50.49 13.635 ;
     RECT  2.16 13.905 50.49 14.175 ;
     RECT  2.16 14.445 50.49 14.715 ;
     RECT  2.16 14.985 50.49 15.255 ;
     RECT  2.16 15.525 50.49 15.795 ;
     RECT  2.16 16.065 50.49 16.335 ;
     RECT  2.16 16.605 50.49 16.875 ;
     RECT  2.16 17.145 50.49 17.415 ;
     RECT  2.16 17.685 50.49 17.955 ;
     RECT  2.16 18.225 50.49 18.495 ;
     RECT  2.16 18.765 50.49 19.035 ;
     RECT  2.16 19.305 50.49 19.575 ;
     RECT  2.16 19.845 50.49 20.115 ;
     RECT  2.16 20.385 50.49 20.655 ;
     RECT  2.16 20.925 50.49 21.195 ;
     RECT  2.16 21.465 50.49 21.735 ;
     RECT  2.16 22.005 50.49 22.275 ;
     RECT  2.16 22.545 50.49 22.815 ;
     RECT  2.16 23.085 50.49 23.355 ;
     RECT  2.16 23.625 50.49 23.895 ;
     RECT  2.16 24.165 50.49 24.435 ;
     RECT  2.16 24.705 50.49 24.975 ;
     RECT  2.16 25.245 50.49 25.515 ;
     RECT  2.16 25.785 50.49 26.055 ;
     RECT  2.16 26.325 50.49 26.595 ;
     RECT  2.16 26.865 50.49 27.135 ;
     RECT  2.16 27.405 50.49 27.675 ;
     RECT  2.16 27.945 50.49 28.215 ;
     RECT  2.16 28.485 50.49 28.755 ;
     RECT  2.16 29.025 50.49 29.295 ;
     RECT  2.16 29.565 50.49 29.835 ;
     RECT  2.16 30.105 50.49 30.375 ;
     RECT  2.16 30.645 50.49 30.915 ;
     RECT  2.16 31.185 50.49 31.455 ;
     RECT  2.16 31.725 50.49 31.995 ;
     RECT  2.16 32.265 50.49 32.535 ;
     RECT  2.16 32.805 50.49 33.075 ;
     RECT  2.16 33.345 50.49 33.615 ;
     RECT  2.16 33.885 50.49 34.155 ;
     RECT  2.16 34.425 50.49 34.695 ;
     RECT  2.16 34.965 50.49 35.235 ;
     RECT  2.16 35.505 50.49 35.775 ;
     RECT  2.16 36.045 50.49 36.315 ;
     RECT  2.16 36.585 50.49 36.855 ;
     RECT  2.16 37.125 50.49 37.395 ;
     RECT  2.16 37.665 50.49 37.935 ;
     RECT  2.16 38.205 50.49 38.475 ;
     RECT  2.16 38.745 50.49 39.015 ;
     RECT  2.16 39.285 50.49 39.555 ;
     RECT  2.16 39.825 50.49 40.095 ;
     RECT  2.16 40.365 50.49 40.635 ;
     RECT  2.16 40.905 50.49 41.175 ;
     RECT  2.16 41.445 50.49 41.715 ;
     RECT  2.16 41.985 50.49 42.255 ;
     RECT  2.16 42.525 50.49 42.795 ;
     RECT  2.16 43.065 50.49 43.335 ;
     RECT  2.16 43.605 50.49 43.875 ;
     RECT  2.16 44.145 50.49 44.415 ;
     RECT  2.16 44.685 50.49 44.955 ;
     RECT  2.16 45.225 50.49 45.495 ;
     RECT  2.16 45.765 50.49 46.035 ;
     RECT  2.16 46.305 50.49 46.575 ;
     RECT  2.16 46.845 50.49 47.115 ;
     RECT  2.16 47.385 50.49 47.655 ;
     RECT  2.16 47.925 50.49 48.195 ;
     RECT  2.16 48.465 50.49 48.735 ;
     RECT  2.16 49.005 50.49 49.275 ;
     RECT  2.16 49.545 50.49 49.815 ;
     RECT  2.16 50.085 50.49 50.355 ;
     RECT  2.16 50.625 50.49 50.895 ;
     RECT  2.16 51.165 50.49 51.435 ;
     RECT  2.16 51.705 50.49 51.975 ;
     RECT  2.16 52.245 50.49 52.515 ;
     RECT  2.16 52.785 50.49 53.055 ;
     RECT  2.16 53.325 50.49 53.595 ;
     RECT  2.16 53.865 50.49 54.135 ;
     RECT  2.16 54.405 50.49 54.675 ;
     RECT  2.16 54.945 50.49 55.215 ;
     RECT  2.16 55.485 50.49 55.755 ;
     RECT  2.16 56.025 50.49 56.295 ;
     RECT  2.16 56.565 50.49 56.835 ;
     RECT  2.16 57.105 50.49 57.375 ;
     RECT  2.16 57.645 50.49 57.915 ;
     RECT  2.16 58.185 50.49 58.455 ;
     RECT  2.16 58.725 50.49 58.995 ;
     RECT  2.16 59.265 50.49 59.535 ;
     RECT  2.16 59.805 50.49 60.075 ;
     RECT  2.16 60.345 50.49 60.615 ;
     RECT  2.16 60.885 50.49 61.155 ;
     RECT  2.16 61.425 50.49 61.695 ;
     RECT  2.16 61.965 50.49 62.235 ;
     RECT  2.16 62.505 50.49 62.775 ;
     RECT  2.16 63.045 50.49 63.315 ;
     RECT  2.16 63.585 50.49 63.855 ;
     RECT  2.16 64.125 50.49 64.395 ;
     RECT  2.16 64.665 50.49 64.935 ;
     RECT  2.16 65.205 50.49 65.475 ;
     RECT  2.16 65.745 50.49 66.015 ;
     RECT  2.16 66.285 50.49 66.555 ;
     RECT  2.16 66.825 50.49 67.095 ;
     RECT  2.16 67.365 50.49 67.635 ;
     RECT  2.16 67.905 50.49 68.175 ;
     RECT  2.16 68.445 50.49 68.715 ;
     RECT  2.16 68.985 50.49 69.255 ;
     RECT  2.16 69.525 50.49 69.795 ;
     RECT  2.16 70.065 50.49 70.335 ;
     RECT  2.16 70.605 50.49 70.875 ;
     RECT  2.16 71.145 50.49 71.415 ;
     RECT  2.16 71.685 50.49 71.955 ;
     RECT  2.16 72.225 50.49 72.495 ;
     RECT  2.16 72.765 50.49 73.035 ;
     RECT  2.16 73.305 50.49 73.575 ;
     RECT  2.16 73.845 50.49 74.115 ;
     RECT  2.16 74.385 50.49 74.655 ;
     RECT  2.16 74.925 50.49 75.195 ;
     RECT  2.16 75.465 50.49 75.735 ;
     RECT  2.16 76.005 50.49 76.275 ;
     RECT  2.16 76.545 50.49 76.815 ;
     RECT  2.16 77.085 50.49 77.355 ;
     RECT  2.16 77.625 50.49 77.895 ;
     RECT  2.16 78.165 50.49 78.435 ;
     RECT  2.16 78.705 50.49 78.975 ;
     RECT  2.16 79.245 50.49 79.515 ;
     RECT  2.16 79.785 50.49 80.055 ;
     RECT  2.16 80.325 50.49 80.595 ;
     RECT  2.16 80.865 50.49 81.135 ;
     RECT  2.16 81.405 50.49 81.675 ;
     RECT  2.16 81.945 50.49 82.215 ;
     RECT  2.16 82.485 50.49 82.755 ;
     RECT  2.16 83.025 50.49 83.295 ;
     RECT  2.16 83.565 50.49 83.835 ;
     RECT  2.16 84.105 50.49 84.375 ;
     RECT  2.16 84.645 50.49 84.915 ;
     RECT  2.16 85.185 50.49 85.455 ;
     RECT  2.16 85.725 50.49 85.995 ;
     RECT  2.16 86.265 50.49 86.535 ;
     RECT  2.16 86.805 50.49 87.075 ;
     RECT  2.16 87.345 50.49 87.615 ;
     RECT  2.16 87.885 50.49 88.155 ;
     RECT  2.16 88.425 50.49 88.695 ;
     RECT  2.16 88.965 50.49 89.235 ;
     RECT  2.16 89.505 50.49 89.775 ;
     RECT  2.16 90.045 50.49 90.315 ;
     RECT  2.16 90.585 50.49 90.855 ;
     RECT  2.16 91.125 50.49 91.395 ;
     RECT  2.16 91.665 50.49 91.935 ;
     RECT  2.16 92.205 50.49 92.475 ;
     RECT  2.16 92.745 50.49 93.015 ;
     RECT  2.16 93.285 50.49 93.555 ;
     RECT  2.16 93.825 50.49 94.095 ;
     RECT  2.16 94.365 50.49 94.635 ;
     RECT  2.16 94.905 50.49 95.175 ;
     RECT  2.16 95.445 50.49 95.715 ;
     RECT  2.16 95.985 50.49 96.255 ;
     RECT  2.16 96.525 50.49 96.795 ;
     RECT  2.16 97.065 50.49 97.335 ;
     RECT  2.16 97.605 50.49 97.875 ;
     RECT  2.16 98.145 50.49 98.415 ;
     RECT  2.16 98.685 50.49 98.955 ;
     RECT  2.16 99.225 50.49 99.495 ;
     RECT  2.16 99.765 50.49 100.035 ;
     RECT  2.16 100.305 50.49 100.575 ;
     RECT  2.16 100.845 50.49 101.115 ;
    LAYER RVTP ;
     RECT  2.16 2.295 50.49 2.565 ;
     RECT  2.16 2.835 50.49 3.105 ;
     RECT  2.16 3.375 50.49 3.645 ;
     RECT  2.16 3.915 50.49 4.185 ;
     RECT  2.16 4.455 50.49 4.725 ;
     RECT  2.16 4.995 50.49 5.265 ;
     RECT  2.16 5.535 50.49 5.805 ;
     RECT  2.16 6.075 50.49 6.345 ;
     RECT  2.16 6.615 50.49 6.885 ;
     RECT  2.16 7.155 50.49 7.425 ;
     RECT  2.16 7.695 50.49 7.965 ;
     RECT  2.16 8.235 50.49 8.505 ;
     RECT  2.16 8.775 50.49 9.045 ;
     RECT  2.16 9.315 50.49 9.585 ;
     RECT  2.16 9.855 50.49 10.125 ;
     RECT  2.16 10.395 50.49 10.665 ;
     RECT  2.16 10.935 50.49 11.205 ;
     RECT  2.16 11.475 50.49 11.745 ;
     RECT  2.16 12.015 50.49 12.285 ;
     RECT  2.16 12.555 50.49 12.825 ;
     RECT  2.16 13.095 50.49 13.365 ;
     RECT  2.16 13.635 50.49 13.905 ;
     RECT  2.16 14.175 50.49 14.445 ;
     RECT  2.16 14.715 50.49 14.985 ;
     RECT  2.16 15.255 50.49 15.525 ;
     RECT  2.16 15.795 50.49 16.065 ;
     RECT  2.16 16.335 50.49 16.605 ;
     RECT  2.16 16.875 50.49 17.145 ;
     RECT  2.16 17.415 50.49 17.685 ;
     RECT  2.16 17.955 50.49 18.225 ;
     RECT  2.16 18.495 50.49 18.765 ;
     RECT  2.16 19.035 50.49 19.305 ;
     RECT  2.16 19.575 50.49 19.845 ;
     RECT  2.16 20.115 50.49 20.385 ;
     RECT  2.16 20.655 50.49 20.925 ;
     RECT  2.16 21.195 50.49 21.465 ;
     RECT  2.16 21.735 50.49 22.005 ;
     RECT  2.16 22.275 50.49 22.545 ;
     RECT  2.16 22.815 50.49 23.085 ;
     RECT  2.16 23.355 50.49 23.625 ;
     RECT  2.16 23.895 50.49 24.165 ;
     RECT  2.16 24.435 50.49 24.705 ;
     RECT  2.16 24.975 50.49 25.245 ;
     RECT  2.16 25.515 50.49 25.785 ;
     RECT  2.16 26.055 50.49 26.325 ;
     RECT  2.16 26.595 50.49 26.865 ;
     RECT  2.16 27.135 50.49 27.405 ;
     RECT  2.16 27.675 50.49 27.945 ;
     RECT  2.16 28.215 50.49 28.485 ;
     RECT  2.16 28.755 50.49 29.025 ;
     RECT  2.16 29.295 50.49 29.565 ;
     RECT  2.16 29.835 50.49 30.105 ;
     RECT  2.16 30.375 50.49 30.645 ;
     RECT  2.16 30.915 50.49 31.185 ;
     RECT  2.16 31.455 50.49 31.725 ;
     RECT  2.16 31.995 50.49 32.265 ;
     RECT  2.16 32.535 50.49 32.805 ;
     RECT  2.16 33.075 50.49 33.345 ;
     RECT  2.16 33.615 50.49 33.885 ;
     RECT  2.16 34.155 50.49 34.425 ;
     RECT  2.16 34.695 50.49 34.965 ;
     RECT  2.16 35.235 50.49 35.505 ;
     RECT  2.16 35.775 50.49 36.045 ;
     RECT  2.16 36.315 50.49 36.585 ;
     RECT  2.16 36.855 50.49 37.125 ;
     RECT  2.16 37.395 50.49 37.665 ;
     RECT  2.16 37.935 50.49 38.205 ;
     RECT  2.16 38.475 50.49 38.745 ;
     RECT  2.16 39.015 50.49 39.285 ;
     RECT  2.16 39.555 50.49 39.825 ;
     RECT  2.16 40.095 50.49 40.365 ;
     RECT  2.16 40.635 50.49 40.905 ;
     RECT  2.16 41.175 50.49 41.445 ;
     RECT  2.16 41.715 50.49 41.985 ;
     RECT  2.16 42.255 50.49 42.525 ;
     RECT  2.16 42.795 50.49 43.065 ;
     RECT  2.16 43.335 50.49 43.605 ;
     RECT  2.16 43.875 50.49 44.145 ;
     RECT  2.16 44.415 50.49 44.685 ;
     RECT  2.16 44.955 50.49 45.225 ;
     RECT  2.16 45.495 50.49 45.765 ;
     RECT  2.16 46.035 50.49 46.305 ;
     RECT  2.16 46.575 50.49 46.845 ;
     RECT  2.16 47.115 50.49 47.385 ;
     RECT  2.16 47.655 50.49 47.925 ;
     RECT  2.16 48.195 50.49 48.465 ;
     RECT  2.16 48.735 50.49 49.005 ;
     RECT  2.16 49.275 50.49 49.545 ;
     RECT  2.16 49.815 50.49 50.085 ;
     RECT  2.16 50.355 50.49 50.625 ;
     RECT  2.16 50.895 50.49 51.165 ;
     RECT  2.16 51.435 50.49 51.705 ;
     RECT  2.16 51.975 50.49 52.245 ;
     RECT  2.16 52.515 50.49 52.785 ;
     RECT  2.16 53.055 50.49 53.325 ;
     RECT  2.16 53.595 50.49 53.865 ;
     RECT  2.16 54.135 50.49 54.405 ;
     RECT  2.16 54.675 50.49 54.945 ;
     RECT  2.16 55.215 50.49 55.485 ;
     RECT  2.16 55.755 50.49 56.025 ;
     RECT  2.16 56.295 50.49 56.565 ;
     RECT  2.16 56.835 50.49 57.105 ;
     RECT  2.16 57.375 50.49 57.645 ;
     RECT  2.16 57.915 50.49 58.185 ;
     RECT  2.16 58.455 50.49 58.725 ;
     RECT  2.16 58.995 50.49 59.265 ;
     RECT  2.16 59.535 50.49 59.805 ;
     RECT  2.16 60.075 50.49 60.345 ;
     RECT  2.16 60.615 50.49 60.885 ;
     RECT  2.16 61.155 50.49 61.425 ;
     RECT  2.16 61.695 50.49 61.965 ;
     RECT  2.16 62.235 50.49 62.505 ;
     RECT  2.16 62.775 50.49 63.045 ;
     RECT  2.16 63.315 50.49 63.585 ;
     RECT  2.16 63.855 50.49 64.125 ;
     RECT  2.16 64.395 50.49 64.665 ;
     RECT  2.16 64.935 50.49 65.205 ;
     RECT  2.16 65.475 50.49 65.745 ;
     RECT  2.16 66.015 50.49 66.285 ;
     RECT  2.16 66.555 50.49 66.825 ;
     RECT  2.16 67.095 50.49 67.365 ;
     RECT  2.16 67.635 50.49 67.905 ;
     RECT  2.16 68.175 50.49 68.445 ;
     RECT  2.16 68.715 50.49 68.985 ;
     RECT  2.16 69.255 50.49 69.525 ;
     RECT  2.16 69.795 50.49 70.065 ;
     RECT  2.16 70.335 50.49 70.605 ;
     RECT  2.16 70.875 50.49 71.145 ;
     RECT  2.16 71.415 50.49 71.685 ;
     RECT  2.16 71.955 50.49 72.225 ;
     RECT  2.16 72.495 50.49 72.765 ;
     RECT  2.16 73.035 50.49 73.305 ;
     RECT  2.16 73.575 50.49 73.845 ;
     RECT  2.16 74.115 50.49 74.385 ;
     RECT  2.16 74.655 50.49 74.925 ;
     RECT  2.16 75.195 50.49 75.465 ;
     RECT  2.16 75.735 50.49 76.005 ;
     RECT  2.16 76.275 50.49 76.545 ;
     RECT  2.16 76.815 50.49 77.085 ;
     RECT  2.16 77.355 50.49 77.625 ;
     RECT  2.16 77.895 50.49 78.165 ;
     RECT  2.16 78.435 50.49 78.705 ;
     RECT  2.16 78.975 50.49 79.245 ;
     RECT  2.16 79.515 50.49 79.785 ;
     RECT  2.16 80.055 50.49 80.325 ;
     RECT  2.16 80.595 50.49 80.865 ;
     RECT  2.16 81.135 50.49 81.405 ;
     RECT  2.16 81.675 50.49 81.945 ;
     RECT  2.16 82.215 50.49 82.485 ;
     RECT  2.16 82.755 50.49 83.025 ;
     RECT  2.16 83.295 50.49 83.565 ;
     RECT  2.16 83.835 50.49 84.105 ;
     RECT  2.16 84.375 50.49 84.645 ;
     RECT  2.16 84.915 50.49 85.185 ;
     RECT  2.16 85.455 50.49 85.725 ;
     RECT  2.16 85.995 50.49 86.265 ;
     RECT  2.16 86.535 50.49 86.805 ;
     RECT  2.16 87.075 50.49 87.345 ;
     RECT  2.16 87.615 50.49 87.885 ;
     RECT  2.16 88.155 50.49 88.425 ;
     RECT  2.16 88.695 50.49 88.965 ;
     RECT  2.16 89.235 50.49 89.505 ;
     RECT  2.16 89.775 50.49 90.045 ;
     RECT  2.16 90.315 50.49 90.585 ;
     RECT  2.16 90.855 50.49 91.125 ;
     RECT  2.16 91.395 50.49 91.665 ;
     RECT  2.16 91.935 50.49 92.205 ;
     RECT  2.16 92.475 50.49 92.745 ;
     RECT  2.16 93.015 50.49 93.285 ;
     RECT  2.16 93.555 50.49 93.825 ;
     RECT  2.16 94.095 50.49 94.365 ;
     RECT  2.16 94.635 50.49 94.905 ;
     RECT  2.16 95.175 50.49 95.445 ;
     RECT  2.16 95.715 50.49 95.985 ;
     RECT  2.16 96.255 50.49 96.525 ;
     RECT  2.16 96.795 50.49 97.065 ;
     RECT  2.16 97.335 50.49 97.605 ;
     RECT  2.16 97.875 50.49 98.145 ;
     RECT  2.16 98.415 50.49 98.685 ;
     RECT  2.16 98.955 50.49 99.225 ;
     RECT  2.16 99.495 50.49 99.765 ;
     RECT  2.16 100.035 50.49 100.305 ;
     RECT  2.16 100.575 50.49 100.845 ;
     RECT  2.16 101.115 50.49 101.25 ;
    LAYER M1 ;
     RECT  2.16 2.151 50.49 101.259 ;
    LAYER M2 ;
     RECT  0.031 40.374 0.103 40.392 ;
     RECT  0.067 41.571 0.103 41.589 ;
     RECT  0.031 52.326 0.103 52.344 ;
     RECT  0.103 40.374 0.139 42.012 ;
     RECT  0.067 43.236 0.139 43.254 ;
     RECT  0.067 46.701 0.139 46.719 ;
     RECT  0.103 50.526 0.139 50.769 ;
     RECT  0.103 51.876 0.139 52.344 ;
     RECT  0.067 53.991 0.139 54.009 ;
     RECT  0.103 58.086 0.139 58.104 ;
     RECT  0.103 60.741 0.139 61.299 ;
     RECT  0.139 43.191 0.175 43.254 ;
     RECT  0.139 44.118 0.175 44.136 ;
     RECT  0.103 45.234 0.175 45.252 ;
     RECT  0.139 46.044 0.175 46.719 ;
     RECT  0.139 47.556 0.175 47.574 ;
     RECT  0.139 48.816 0.175 49.374 ;
     RECT  0.139 50.526 0.175 52.344 ;
     RECT  0.139 53.874 0.175 54.009 ;
     RECT  0.139 55.116 0.175 55.584 ;
     RECT  0.139 56.34 0.175 58.446 ;
     RECT  0.103 59.346 0.175 59.832 ;
     RECT  0.139 60.741 0.175 62.496 ;
     RECT  0.139 64.062 0.175 64.08 ;
     RECT  0.139 65.016 0.175 65.034 ;
     RECT  0.175 45.234 0.203 46.719 ;
     RECT  0.175 55.116 0.211 59.832 ;
     RECT  0.175 60.66 0.211 62.694 ;
     RECT  0.175 64.062 0.211 65.034 ;
     RECT  0.175 43.191 0.247 43.326 ;
     RECT  0.175 44.118 0.247 44.442 ;
     RECT  0.175 53.451 0.283 54.009 ;
     RECT  0.211 54.99 0.283 59.832 ;
     RECT  0.211 60.66 0.283 65.034 ;
     RECT  0.139 39.834 0.391 42.012 ;
     RECT  0.391 39.726 0.463 42.012 ;
     RECT  0.247 43.191 0.463 44.442 ;
     RECT  0.203 45.432 0.463 46.719 ;
     RECT  0.175 47.556 0.463 52.344 ;
     RECT  0.283 53.451 0.535 65.034 ;
     RECT  0.463 45.432 1.147 52.614 ;
     RECT  0.535 53.37 1.147 65.034 ;
     RECT  0.463 39.492 1.687 44.442 ;
     RECT  0.283 38.646 2.16 38.664 ;
     RECT  1.687 39.492 2.16 44.514 ;
     RECT  1.147 45.432 2.16 65.034 ;
     RECT  8.815 0.036 9.463 0.054 ;
     RECT  2.16 2.151 10.327 101.259 ;
     RECT  10.327 2.151 10.831 101.304 ;
     RECT  10.831 2.151 11.587 101.376 ;
     RECT  9.463 0.036 12.271 0.09 ;
     RECT  11.587 2.151 12.875 101.448 ;
     RECT  12.271 0.036 12.991 0.126 ;
     RECT  12.875 2.151 13.631 101.376 ;
     RECT  15.439 102.132 15.539 102.15 ;
     RECT  13.631 2.151 15.547 101.259 ;
     RECT  12.991 0.036 15.943 0.162 ;
     RECT  15.547 2.151 16.259 101.304 ;
     RECT  16.259 2.151 17.203 101.259 ;
     RECT  15.943 0.036 17.879 0.234 ;
     RECT  17.879 0.216 18.275 0.234 ;
     RECT  17.203 2.151 19.787 101.304 ;
     RECT  19.939 102.132 20.039 102.15 ;
     RECT  19.787 2.151 25.303 101.259 ;
     RECT  25.303 2.151 25.439 101.304 ;
     RECT  26.023 0.531 26.563 0.549 ;
     RECT  26.563 0.45 26.663 0.549 ;
     RECT  26.663 0.531 26.735 0.549 ;
     RECT  25.439 2.151 38.047 101.259 ;
     RECT  38.047 2.151 39.191 101.304 ;
     RECT  39.191 2.151 50.49 101.259 ;
    LAYER M3 ;
     RECT  8.82 0.031 8.838 0.067 ;
     RECT  17.856 0.031 17.874 0.091 ;
     RECT  15.984 0.067 16.002 0.103 ;
     RECT  12.276 0.103 12.294 0.139 ;
     RECT  15.948 0.103 16.002 0.139 ;
     RECT  17.856 0.091 18.522 0.139 ;
     RECT  24.48 0.091 24.498 0.139 ;
     RECT  26.208 0.091 26.226 0.139 ;
     RECT  28.152 0.091 28.17 0.139 ;
     RECT  34.74 0.091 35.478 0.139 ;
     RECT  13.932 0.139 18.522 0.187 ;
     RECT  19.368 0.139 20.358 0.187 ;
     RECT  21.204 0.139 24.714 0.187 ;
     RECT  25.596 0.139 28.278 0.187 ;
     RECT  29.052 0.139 35.55 0.187 ;
     RECT  36.396 0.139 38.286 0.187 ;
     RECT  13.932 0.187 28.278 0.235 ;
     RECT  29.052 0.187 38.286 0.283 ;
     RECT  13.932 0.235 28.314 0.379 ;
     RECT  29.052 0.283 38.358 0.379 ;
     RECT  12.276 0.139 13.014 0.523 ;
     RECT  13.932 0.379 38.358 0.523 ;
     RECT  12.276 0.523 38.358 1.387 ;
     RECT  2.415 2.143 2.505 2.413 ;
     RECT  7.815 2.143 7.905 2.413 ;
     RECT  40.215 2.143 40.305 2.413 ;
     RECT  45.615 2.143 45.705 2.413 ;
     RECT  7.815 2.413 8.097 2.839 ;
     RECT  8.82 0.067 9.486 2.839 ;
     RECT  11.7 1.387 38.358 2.875 ;
     RECT  7.815 2.839 9.486 2.911 ;
     RECT  10.476 2.875 10.494 2.911 ;
     RECT  11.556 2.875 38.358 2.911 ;
     RECT  7.815 2.911 9.63 3.037 ;
     RECT  7.596 3.037 9.63 3.109 ;
     RECT  7.092 3.109 9.63 3.181 ;
     RECT  6.84 3.181 9.63 3.343 ;
     RECT  10.476 2.911 38.358 3.343 ;
     RECT  6.84 3.343 38.358 3.569 ;
     RECT  8.82 3.569 38.358 3.947 ;
     RECT  11.484 3.947 38.358 5.995 ;
     RECT  6.84 3.569 8.097 6.511 ;
     RECT  8.82 3.947 10.566 6.511 ;
     RECT  6.84 6.511 10.566 9.787 ;
     RECT  6.84 9.787 10.602 12.361 ;
     RECT  11.412 5.995 38.358 12.361 ;
     RECT  5.4 3.037 5.418 12.487 ;
     RECT  6.84 12.361 38.358 18.031 ;
     RECT  6.84 18.031 38.754 18.149 ;
     RECT  40.215 2.413 40.497 18.193 ;
     RECT  6.84 18.149 38.358 23.125 ;
     RECT  39.6 18.193 40.497 23.125 ;
     RECT  6.84 23.125 40.497 37.049 ;
     RECT  5.4 12.487 5.994 38.749 ;
     RECT  6.84 37.049 8.514 39.181 ;
     RECT  0.288 38.641 0.306 39.487 ;
     RECT  5.4 38.749 6.066 39.487 ;
     RECT  6.804 39.181 8.514 39.523 ;
     RECT  5.112 39.487 6.066 39.559 ;
     RECT  6.804 39.523 8.586 39.559 ;
     RECT  0.288 39.487 0.486 39.595 ;
     RECT  2.415 2.413 2.697 39.595 ;
     RECT  3.456 39.181 3.474 39.595 ;
     RECT  0.036 39.595 0.486 39.631 ;
     RECT  0.036 39.631 0.558 39.691 ;
     RECT  0.036 39.691 1.17 39.785 ;
     RECT  5.112 39.559 8.586 39.865 ;
     RECT  9.324 37.049 40.497 39.865 ;
     RECT  2.415 39.595 3.474 39.991 ;
     RECT  2.415 39.991 3.942 40.027 ;
     RECT  5.112 39.865 40.497 40.027 ;
     RECT  2.415 40.027 40.497 40.063 ;
     RECT  0.036 39.785 0.738 40.289 ;
     RECT  2.304 40.063 40.497 40.297 ;
     RECT  1.692 40.297 40.497 40.445 ;
     RECT  5.148 40.445 40.497 40.781 ;
     RECT  1.692 40.445 4.374 40.937 ;
     RECT  1.692 40.937 4.302 40.973 ;
     RECT  1.692 40.973 3.978 41.549 ;
     RECT  5.184 40.781 40.497 41.719 ;
     RECT  1.692 41.549 3.402 41.741 ;
     RECT  0.036 40.289 0.558 41.755 ;
     RECT  0.036 41.755 0.666 41.819 ;
     RECT  5.004 41.719 40.497 42.025 ;
     RECT  1.692 41.741 2.862 42.029 ;
     RECT  4.572 42.025 40.497 42.089 ;
     RECT  4.572 42.089 4.59 42.179 ;
     RECT  4.536 42.325 4.554 42.365 ;
     RECT  2.232 42.029 2.862 42.961 ;
     RECT  3.96 42.691 3.978 42.961 ;
     RECT  4.824 43.033 4.842 43.231 ;
     RECT  5.616 42.089 40.497 43.231 ;
     RECT  2.232 42.961 3.978 43.303 ;
     RECT  0.036 41.819 0.63 43.339 ;
     RECT  2.232 43.303 4.014 43.375 ;
     RECT  0.036 43.339 0.666 43.387 ;
     RECT  1.692 43.375 4.014 43.411 ;
     RECT  4.824 43.231 40.497 43.411 ;
     RECT  0.036 43.387 0.738 43.517 ;
     RECT  1.692 43.411 40.497 43.529 ;
     RECT  1.692 43.529 4.23 43.709 ;
     RECT  5.004 43.529 40.497 43.907 ;
     RECT  0.036 43.517 0.666 44.045 ;
     RECT  1.692 43.709 3.402 44.339 ;
     RECT  4.212 43.709 4.23 44.851 ;
     RECT  1.692 44.339 2.97 44.909 ;
     RECT  3.996 44.851 4.23 45.112 ;
     RECT  3.996 45.112 4.446 45.149 ;
     RECT  3.996 45.149 4.014 45.485 ;
     RECT  0.036 44.045 0.558 45.661 ;
     RECT  5.616 43.907 40.497 45.661 ;
     RECT  2.304 44.909 2.97 45.805 ;
     RECT  0.036 45.661 1.17 45.869 ;
     RECT  2.304 45.805 3.654 45.869 ;
     RECT  2.304 45.869 2.697 46.039 ;
     RECT  3.564 45.869 3.654 46.109 ;
     RECT  5.148 45.661 40.497 46.397 ;
     RECT  3.996 46.381 4.014 46.541 ;
     RECT  0.036 45.869 0.558 46.699 ;
     RECT  1.692 46.039 2.697 46.747 ;
     RECT  4.176 46.741 4.59 46.781 ;
     RECT  0.036 46.699 0.594 46.843 ;
     RECT  1.692 46.747 2.79 47.155 ;
     RECT  1.692 47.155 2.862 47.272 ;
     RECT  4.176 46.781 4.554 47.272 ;
     RECT  1.692 47.272 4.554 47.309 ;
     RECT  3.744 47.309 4.554 47.357 ;
     RECT  0.036 46.843 0.702 47.501 ;
     RECT  1.692 47.309 2.934 47.549 ;
     RECT  3.996 47.357 4.554 47.551 ;
     RECT  3.996 47.551 4.734 47.579 ;
     RECT  4.032 47.579 4.734 47.597 ;
     RECT  2.304 47.549 2.934 47.759 ;
     RECT  5.616 46.397 40.497 47.965 ;
     RECT  2.304 47.759 2.862 48.077 ;
     RECT  5.472 47.965 40.497 48.119 ;
     RECT  4.032 47.597 4.05 48.361 ;
     RECT  0.036 47.501 0.63 48.475 ;
     RECT  3.96 48.361 4.05 48.667 ;
     RECT  3.96 48.667 4.086 48.763 ;
     RECT  3.96 48.763 4.194 48.901 ;
     RECT  3.96 48.901 4.518 49.085 ;
     RECT  0.036 48.475 0.666 49.181 ;
     RECT  2.415 48.077 2.862 49.243 ;
     RECT  3.96 49.085 4.086 49.351 ;
     RECT  5.616 48.119 40.497 49.441 ;
     RECT  1.44 49.387 1.458 49.505 ;
     RECT  5.148 49.441 40.497 49.541 ;
     RECT  2.415 49.243 2.97 49.585 ;
     RECT  1.692 49.585 2.97 49.771 ;
     RECT  3.852 49.351 4.086 49.771 ;
     RECT  1.692 49.771 4.086 49.901 ;
     RECT  1.692 49.901 4.05 49.949 ;
     RECT  2.232 49.949 4.05 50.237 ;
     RECT  5.616 49.541 40.497 50.347 ;
     RECT  2.304 50.237 4.05 50.629 ;
     RECT  2.304 50.629 4.23 50.765 ;
     RECT  0.036 49.181 0.558 50.827 ;
     RECT  5.256 50.347 40.497 50.863 ;
     RECT  2.304 50.765 3.33 50.909 ;
     RECT  0.036 50.827 1.17 51.161 ;
     RECT  2.304 50.909 2.934 51.367 ;
     RECT  1.62 51.367 2.934 51.533 ;
     RECT  2.304 51.533 2.934 51.709 ;
     RECT  4.032 51.871 4.23 51.883 ;
     RECT  5.148 50.863 40.497 51.883 ;
     RECT  2.304 51.709 3.078 51.943 ;
     RECT  4.032 51.883 40.497 51.943 ;
     RECT  0.036 51.161 0.558 52.051 ;
     RECT  2.304 51.943 40.497 52.109 ;
     RECT  2.304 52.109 4.122 52.241 ;
     RECT  5.148 52.109 40.497 52.241 ;
     RECT  0.036 52.051 0.594 52.349 ;
     RECT  5.256 52.241 40.497 52.349 ;
     RECT  2.304 52.241 2.934 52.439 ;
     RECT  0.072 52.349 0.594 52.459 ;
     RECT  1.332 52.171 1.35 52.459 ;
     RECT  0.072 52.459 1.35 52.825 ;
     RECT  0.072 52.825 1.674 52.979 ;
     RECT  3.924 52.241 4.122 52.979 ;
     RECT  3.996 52.979 4.122 53.159 ;
     RECT  4.032 53.159 4.122 53.221 ;
     RECT  1.656 52.979 1.674 53.293 ;
     RECT  2.415 52.439 2.934 53.293 ;
     RECT  4.032 53.221 4.194 53.309 ;
     RECT  5.436 52.349 40.497 53.329 ;
     RECT  4.032 53.309 4.05 53.591 ;
     RECT  5.328 53.329 40.497 53.671 ;
     RECT  5.112 53.671 40.497 53.885 ;
     RECT  1.656 53.293 2.934 53.941 ;
     RECT  0.072 52.979 0.558 54.014 ;
     RECT  0.144 54.014 0.558 54.029 ;
     RECT  1.656 53.941 2.97 54.077 ;
     RECT  0.216 54.029 0.558 54.139 ;
     RECT  0.216 54.139 0.666 54.187 ;
     RECT  3.996 54.619 4.014 54.751 ;
     RECT  5.22 53.885 40.497 54.751 ;
     RECT  1.692 54.077 2.97 54.841 ;
     RECT  3.816 54.751 4.014 54.841 ;
     RECT  1.692 54.841 4.014 54.859 ;
     RECT  5.148 54.751 40.497 54.869 ;
     RECT  0.216 54.187 0.738 54.904 ;
     RECT  1.692 54.859 4.122 54.904 ;
     RECT  0.216 54.904 4.122 54.941 ;
     RECT  1.26 54.941 4.122 54.977 ;
     RECT  0.216 54.941 0.522 55.003 ;
     RECT  5.436 54.869 40.497 55.013 ;
     RECT  4.104 54.977 4.122 55.049 ;
     RECT  1.26 54.977 3.114 55.133 ;
     RECT  5.508 55.013 40.497 55.139 ;
     RECT  5.58 55.139 40.497 55.184 ;
     RECT  1.692 55.133 3.114 55.247 ;
     RECT  1.692 55.247 2.79 55.277 ;
     RECT  0.144 55.003 0.522 55.795 ;
     RECT  0.144 55.795 0.558 56.059 ;
     RECT  1.692 55.277 2.697 56.059 ;
     RECT  3.636 56.011 3.762 56.155 ;
     RECT  0.144 56.059 0.63 56.203 ;
     RECT  1.692 56.059 2.862 56.203 ;
     RECT  0.144 56.203 2.862 56.227 ;
     RECT  3.636 56.155 3.978 56.381 ;
     RECT  0.144 56.227 2.898 56.561 ;
     RECT  1.728 56.561 2.898 56.587 ;
     RECT  1.728 56.587 3.438 57.403 ;
     RECT  1.728 57.403 3.87 57.415 ;
     RECT  1.728 57.415 3.942 57.479 ;
     RECT  1.728 57.479 3.15 57.533 ;
     RECT  3.924 57.479 3.942 57.569 ;
     RECT  2.415 57.533 3.15 57.839 ;
     RECT  3.996 57.721 4.518 57.839 ;
     RECT  0.144 56.561 0.846 58.081 ;
     RECT  2.415 57.839 2.934 58.145 ;
     RECT  2.415 58.145 2.898 58.157 ;
     RECT  0.108 58.081 0.846 58.253 ;
     RECT  2.415 58.157 2.862 58.267 ;
     RECT  0.144 58.253 0.846 58.451 ;
     RECT  4.284 57.839 4.518 58.459 ;
     RECT  4.284 58.459 4.59 58.721 ;
     RECT  4.284 58.721 4.302 58.795 ;
     RECT  2.304 58.267 2.862 58.829 ;
     RECT  2.415 58.829 2.862 58.891 ;
     RECT  3.96 58.795 4.302 58.891 ;
     RECT  2.415 58.891 4.302 59.213 ;
     RECT  0.18 58.451 0.846 59.341 ;
     RECT  2.415 59.213 4.014 59.459 ;
     RECT  4.788 59.701 4.806 59.741 ;
     RECT  0.108 59.341 0.846 59.837 ;
     RECT  0.18 59.837 0.846 59.885 ;
     RECT  2.415 59.459 3.402 59.947 ;
     RECT  2.304 59.947 3.402 59.999 ;
     RECT  0.18 59.885 0.666 60.667 ;
     RECT  0.108 60.667 0.666 60.763 ;
     RECT  2.415 59.999 2.826 60.781 ;
     RECT  3.636 60.379 3.87 60.781 ;
     RECT  2.415 60.781 3.87 60.955 ;
     RECT  0.108 60.763 1.17 60.989 ;
     RECT  2.415 60.955 3.906 61.003 ;
     RECT  2.415 61.003 4.59 61.087 ;
     RECT  2.415 61.087 4.662 61.088 ;
     RECT  4.644 61.088 4.662 61.187 ;
     RECT  0.108 60.989 0.63 61.304 ;
     RECT  2.415 61.088 3.906 61.349 ;
     RECT  2.415 61.349 3.042 61.457 ;
     RECT  2.415 61.457 2.97 61.501 ;
     RECT  1.404 61.195 1.53 61.517 ;
     RECT  4.068 62.011 4.086 62.167 ;
     RECT  4.068 62.167 4.518 62.339 ;
     RECT  2.304 61.501 2.97 62.443 ;
     RECT  2.304 62.443 3.006 62.473 ;
     RECT  0.144 61.304 0.63 62.491 ;
     RECT  4.068 62.339 4.446 62.699 ;
     RECT  2.304 62.473 3.258 62.851 ;
     RECT  4.068 62.699 4.158 62.851 ;
     RECT  0.144 62.491 0.666 62.957 ;
     RECT  5.616 55.184 40.497 62.977 ;
     RECT  5.436 62.977 40.497 63.049 ;
     RECT  5.364 63.049 40.497 63.121 ;
     RECT  5.148 63.121 40.497 63.239 ;
     RECT  2.304 62.851 4.158 63.589 ;
     RECT  2.304 63.589 4.662 63.725 ;
     RECT  2.415 63.725 4.662 63.779 ;
     RECT  2.415 63.779 3.402 63.851 ;
     RECT  4.572 63.779 4.662 63.851 ;
     RECT  0.144 62.957 0.558 63.883 ;
     RECT  1.404 61.517 1.422 63.923 ;
     RECT  2.415 63.851 3.114 64.049 ;
     RECT  4.644 63.851 4.662 64.049 ;
     RECT  2.415 64.049 2.97 64.157 ;
     RECT  0.144 63.883 0.63 64.267 ;
     RECT  2.415 64.157 2.898 64.319 ;
     RECT  0.144 64.267 1.17 64.355 ;
     RECT  2.415 64.319 2.754 64.471 ;
     RECT  2.304 64.471 2.754 64.625 ;
     RECT  0.144 64.355 0.558 64.697 ;
     RECT  2.415 64.625 2.754 64.697 ;
     RECT  0.144 64.697 0.198 64.769 ;
     RECT  0.144 64.769 0.162 65.039 ;
     RECT  5.616 63.239 40.497 70.259 ;
     RECT  5.616 70.259 5.634 71.725 ;
     RECT  6.372 70.259 40.497 71.725 ;
     RECT  5.616 71.725 40.497 76.469 ;
     RECT  5.616 76.469 5.634 86.635 ;
     RECT  6.372 76.469 40.497 86.635 ;
     RECT  5.616 86.635 40.497 86.729 ;
     RECT  5.616 86.729 5.634 90.091 ;
     RECT  6.372 86.729 40.497 90.091 ;
     RECT  5.616 90.091 40.497 90.779 ;
     RECT  5.616 90.779 5.634 91.589 ;
     RECT  5.58 91.705 5.598 92.669 ;
     RECT  6.372 90.779 40.497 92.821 ;
     RECT  5.652 92.821 40.497 93.437 ;
     RECT  5.796 93.437 40.497 93.479 ;
     RECT  6.372 93.479 40.497 94.945 ;
     RECT  5.904 94.945 40.497 95.021 ;
     RECT  6.84 95.021 40.497 95.755 ;
     RECT  5.904 95.021 5.922 95.909 ;
     RECT  6.732 95.755 40.497 95.909 ;
     RECT  7.2 95.909 40.497 96.449 ;
     RECT  6.084 96.061 6.318 96.755 ;
     RECT  6.264 96.755 6.318 97.259 ;
     RECT  7.38 96.449 40.497 97.375 ;
     RECT  6.84 97.375 40.497 97.529 ;
     RECT  6.876 97.529 40.497 97.799 ;
     RECT  6.876 97.799 39.366 98.339 ;
     RECT  7.056 98.339 39.366 98.617 ;
     RECT  7.056 98.617 39.438 98.669 ;
     RECT  7.416 98.669 39.438 99.149 ;
     RECT  7.596 99.149 39.438 100.067 ;
     RECT  9.036 100.067 39.438 100.535 ;
     RECT  7.596 100.067 8.097 100.607 ;
     RECT  9.144 100.535 39.438 100.949 ;
     RECT  2.415 64.697 2.697 100.997 ;
     RECT  7.815 100.607 8.097 100.997 ;
     RECT  40.215 97.799 40.497 100.997 ;
     RECT  45.615 2.413 45.897 100.997 ;
     RECT  9.144 100.949 9.27 101.039 ;
     RECT  10.332 100.949 39.438 101.039 ;
     RECT  9.144 101.039 9.162 101.147 ;
     RECT  10.332 101.039 39.186 101.219 ;
     RECT  2.607 100.997 2.697 101.267 ;
     RECT  8.007 100.997 8.097 101.267 ;
     RECT  40.407 100.997 40.497 101.267 ;
     RECT  45.807 100.997 45.897 101.267 ;
     RECT  10.332 101.219 38.178 101.309 ;
     RECT  39.168 101.219 39.186 101.309 ;
     RECT  10.836 101.309 10.854 101.381 ;
     RECT  11.592 101.309 38.178 101.381 ;
     RECT  11.592 101.381 11.61 101.453 ;
     RECT  12.852 101.381 38.178 101.453 ;
     RECT  12.924 101.453 38.178 101.501 ;
     RECT  12.924 101.501 23.778 101.549 ;
     RECT  24.552 101.501 30.222 101.693 ;
     RECT  31.068 101.501 38.142 102.029 ;
     RECT  24.552 101.693 28.53 102.077 ;
     RECT  12.996 101.549 23.778 102.173 ;
     RECT  27.396 102.077 28.53 102.571 ;
     RECT  29.304 101.693 30.222 102.571 ;
     RECT  13.104 102.173 23.778 102.653 ;
     RECT  27.396 102.571 30.222 102.653 ;
     RECT  35.136 102.029 36.198 102.653 ;
     RECT  36.972 102.029 38.142 102.653 ;
     RECT  17.208 102.653 19.962 102.701 ;
     RECT  30.168 102.653 30.222 102.749 ;
     RECT  13.176 102.653 16.434 102.797 ;
     RECT  24.552 102.077 26.586 102.797 ;
     RECT  27.396 102.653 29.322 102.811 ;
     RECT  13.176 102.797 13.194 102.845 ;
     RECT  13.968 102.797 16.434 102.845 ;
     RECT  30.204 102.749 30.222 102.845 ;
     RECT  14.076 102.845 16.434 102.989 ;
     RECT  31.14 102.029 31.662 103.243 ;
     RECT  14.076 102.989 15.966 103.277 ;
     RECT  25.38 102.797 26.586 103.291 ;
     RECT  27.324 102.811 29.322 103.291 ;
     RECT  32.436 102.029 34.218 103.291 ;
     RECT  17.208 102.701 19.782 103.325 ;
     RECT  14.076 103.277 15.93 103.373 ;
     RECT  18.36 103.325 19.782 103.373 ;
     RECT  25.38 103.291 29.322 103.421 ;
     RECT  32.436 103.291 34.254 103.421 ;
     RECT  14.076 103.373 14.814 103.469 ;
     RECT  21.06 102.653 22.554 103.469 ;
     RECT  25.38 103.421 28.998 103.469 ;
     RECT  30.564 103.243 31.662 103.469 ;
     RECT  34.2 103.421 34.254 103.469 ;
     RECT  35.136 102.653 36.09 103.469 ;
     RECT  37.224 102.653 38.142 103.469 ;
     RECT  14.796 103.469 14.814 103.517 ;
     RECT  15.696 103.373 15.93 103.517 ;
     RECT  17.208 103.325 17.55 103.517 ;
     RECT  18.576 103.373 19.782 103.517 ;
     RECT  21.06 103.469 21.078 103.517 ;
     RECT  22.356 103.469 22.374 103.517 ;
     RECT  24.552 102.797 24.57 103.517 ;
     RECT  25.38 103.469 26.586 103.517 ;
     RECT  27.36 103.469 28.89 103.517 ;
     RECT  31.14 103.469 31.662 103.517 ;
     RECT  32.436 103.421 33.246 103.517 ;
     RECT  35.316 103.469 36.018 103.517 ;
     RECT  37.512 103.469 38.142 103.517 ;
     RECT  15.696 103.517 15.858 103.565 ;
     RECT  17.532 103.517 17.55 103.565 ;
     RECT  19.08 103.517 19.782 103.565 ;
     RECT  25.596 103.517 25.614 103.565 ;
     RECT  27.36 103.517 27.378 103.565 ;
     RECT  31.356 103.517 31.374 103.565 ;
     RECT  34.236 103.469 34.254 103.565 ;
     RECT  35.712 103.517 35.73 103.565 ;
    LAYER M4 ;
     RECT  0.025 39.6 0.06 39.816 ;
     RECT  0.06 39.6 0.109 64.296 ;
     RECT  0.109 39.696 1.181 64.296 ;
     RECT  1.181 39.744 2.408 64.152 ;
     RECT  2.408 2.148 2.512 100.992 ;
     RECT  2.512 2.418 2.6 100.992 ;
     RECT  2.6 2.418 2.704 101.262 ;
     RECT  2.704 39.744 3.449 64.152 ;
     RECT  5.641 90.096 5.725 90.12 ;
     RECT  5.641 93.408 5.725 93.432 ;
     RECT  6.181 71.76 6.275 71.784 ;
     RECT  6.073 96.528 6.275 96.552 ;
     RECT  6.428 94.992 6.721 95.016 ;
     RECT  6.721 94.608 6.853 95.016 ;
     RECT  6.901 82.368 7.244 82.392 ;
     RECT  3.449 39.888 7.388 64.152 ;
     RECT  6.853 93.744 7.405 95.016 ;
     RECT  6.908 77.424 7.436 77.448 ;
     RECT  6.997 89.856 7.669 89.88 ;
     RECT  7.388 39.648 7.808 64.152 ;
     RECT  7.628 65.664 7.808 65.688 ;
     RECT  7.628 68.352 7.808 68.376 ;
     RECT  6.937 70.656 7.808 70.68 ;
     RECT  7.141 72.144 7.808 72.168 ;
     RECT  7.004 74.304 7.808 74.328 ;
     RECT  7.436 76.896 7.808 77.448 ;
     RECT  7.244 81.456 7.808 82.392 ;
     RECT  7.045 84.864 7.808 84.888 ;
     RECT  6.253 86.64 7.808 86.664 ;
     RECT  7.669 89.856 7.808 90.408 ;
     RECT  7.405 93.744 7.808 95.208 ;
     RECT  7.045 98.64 7.808 98.664 ;
     RECT  7.808 2.148 7.912 100.992 ;
     RECT  7.912 2.418 8 100.992 ;
     RECT  8 2.418 8.104 101.262 ;
     RECT  8.104 96.432 8.387 96.456 ;
     RECT  8.104 79.104 8.435 79.128 ;
     RECT  8.104 93.744 8.531 94.344 ;
     RECT  8.104 92.16 8.561 92.184 ;
     RECT  8.531 93.744 8.561 93.768 ;
     RECT  8.104 66.72 8.741 66.744 ;
     RECT  8.104 87.888 8.771 87.912 ;
     RECT  8.104 82.368 8.915 82.392 ;
     RECT  8.104 97.776 8.956 97.8 ;
     RECT  8.104 76.08 9.052 76.104 ;
     RECT  8.104 65.52 9.059 65.544 ;
     RECT  8.104 68.88 9.059 68.904 ;
     RECT  8.104 90 9.107 90.024 ;
     RECT  8.104 78 9.173 78.072 ;
     RECT  9.253 66.96 9.34 66.984 ;
     RECT  9.173 78.048 9.347 78.072 ;
     RECT  9.109 84.192 9.349 84.216 ;
     RECT  9.301 80.304 9.388 80.328 ;
     RECT  9.205 76.944 9.605 76.968 ;
     RECT  9.349 83.232 9.605 84.216 ;
     RECT  9.565 96.336 9.649 96.36 ;
     RECT  9.605 83.232 9.677 83.256 ;
     RECT  9.109 85.344 9.785 85.368 ;
     RECT  9.733 95.136 9.893 95.16 ;
     RECT  8.104 39.888 10.033 64.152 ;
     RECT  10.033 39.888 10.259 64.632 ;
     RECT  10.069 85.488 10.259 86.616 ;
     RECT  9.997 100.128 10.357 100.152 ;
     RECT  10.309 79.728 10.396 79.752 ;
     RECT  10.385 90.672 10.469 90.696 ;
     RECT  10.597 97.248 10.685 97.272 ;
     RECT  10.357 99.984 10.717 100.296 ;
     RECT  10.259 85.488 10.825 85.512 ;
     RECT  10.717 99.984 10.825 101.016 ;
     RECT  10.885 66.912 10.892 66.936 ;
     RECT  10.825 84.48 10.909 85.512 ;
     RECT  10.909 85.488 10.937 85.512 ;
     RECT  10.892 66.624 10.973 66.936 ;
     RECT  10.973 66.624 10.979 66.696 ;
     RECT  8.104 72.576 10.979 72.6 ;
     RECT  10.393 73.776 10.979 73.8 ;
     RECT  10.357 77.808 11.123 77.832 ;
     RECT  11.005 86.64 11.153 86.664 ;
     RECT  10.825 99.552 11.153 101.016 ;
     RECT  10.259 39.888 11.228 64.152 ;
     RECT  11.18 75.6 11.267 75.624 ;
     RECT  11.153 99.552 11.293 100.824 ;
     RECT  11.228 39.888 11.315 64.92 ;
     RECT  11.315 39.888 11.333 64.152 ;
     RECT  10.979 66.672 11.333 66.696 ;
     RECT  11.257 80.304 11.411 80.328 ;
     RECT  11.329 90.384 11.509 90.408 ;
     RECT  11.468 93.888 11.555 93.912 ;
     RECT  11.413 87.888 11.585 87.912 ;
     RECT  11.509 90.048 11.593 90.408 ;
     RECT  11.293 99.264 11.617 100.824 ;
     RECT  11.66 73.728 11.689 73.752 ;
     RECT  11.701 95.616 11.725 95.64 ;
     RECT  11.689 72.96 11.747 73.752 ;
     RECT  11.747 72.96 11.773 72.984 ;
     RECT  11.725 95.52 11.788 95.64 ;
     RECT  11.788 95.52 11.873 95.544 ;
     RECT  11.893 82.944 11.98 82.968 ;
     RECT  10.897 69.696 12.017 69.72 ;
     RECT  11.617 98.448 12.037 100.824 ;
     RECT  12.037 85.344 12.049 85.368 ;
     RECT  11.333 41.376 12.089 64.152 ;
     RECT  12.085 86.784 12.169 86.808 ;
     RECT  12.049 85.344 12.179 85.512 ;
     RECT  12.121 66.624 12.205 66.648 ;
     RECT  12.037 98.064 12.229 100.824 ;
     RECT  12.089 41.76 12.337 64.152 ;
     RECT  12.193 82.752 12.337 82.776 ;
     RECT  12.229 97.872 12.373 100.824 ;
     RECT  11.689 1.392 12.517 1.416 ;
     RECT  11.593 90.384 12.517 90.408 ;
     RECT  12.373 97.632 12.517 100.824 ;
     RECT  11.333 39.888 12.581 40.392 ;
     RECT  12.517 1.008 12.589 1.416 ;
     RECT  12.517 97.344 12.805 100.824 ;
     RECT  12.589 0.96 12.913 1.416 ;
     RECT  12.581 39.888 12.913 40.44 ;
     RECT  12.805 96.768 12.913 100.824 ;
     RECT  12.373 86.64 12.977 86.76 ;
     RECT  12.913 96.768 12.985 101.544 ;
     RECT  12.337 82.704 13.093 82.776 ;
     RECT  12.977 86.544 13.093 86.76 ;
     RECT  12.985 96.768 13.093 102.168 ;
     RECT  12.757 71.616 13.129 71.64 ;
     RECT  13.093 96.768 13.165 102.648 ;
     RECT  12.913 0.912 13.208 1.416 ;
     RECT  11.545 2.88 13.208 2.904 ;
     RECT  11.401 6 13.208 6.024 ;
     RECT  12.913 39.456 13.208 40.44 ;
     RECT  12.337 41.76 13.208 64.968 ;
     RECT  12.716 70.08 13.208 70.104 ;
     RECT  13.129 71.616 13.208 71.976 ;
     RECT  13.045 73.488 13.208 73.512 ;
     RECT  12.757 75.12 13.208 75.144 ;
     RECT  12.301 77.232 13.208 77.256 ;
     RECT  12.337 80.832 13.208 80.856 ;
     RECT  13.093 82.704 13.208 83.256 ;
     RECT  13.093 85.968 13.208 86.76 ;
     RECT  12.613 88.368 13.208 88.392 ;
     RECT  12.517 90.384 13.208 91.32 ;
     RECT  13.052 93.84 13.208 93.864 ;
     RECT  13.165 96.768 13.208 102.84 ;
     RECT  13.208 0.912 13.504 102.84 ;
     RECT  13.504 41.76 13.565 45.432 ;
     RECT  13.504 71.952 13.565 71.976 ;
     RECT  13.504 76.368 13.645 76.392 ;
     RECT  13.504 39.504 13.667 39.912 ;
     RECT  13.504 79.824 13.667 79.848 ;
     RECT  13.504 46.8 13.673 64.392 ;
     RECT  13.504 90.816 13.673 92.904 ;
     RECT  13.504 0.912 13.705 3.576 ;
     RECT  13.565 42.816 13.715 45.432 ;
     RECT  13.504 65.376 13.715 66.216 ;
     RECT  13.504 93.984 13.853 94.728 ;
     RECT  13.705 0.528 13.877 3.576 ;
     RECT  13.504 82.272 13.933 83.256 ;
     RECT  13.673 91.776 13.948 92.904 ;
     RECT  13.877 0.144 14.051 3.576 ;
     RECT  13.504 96 14.065 102.84 ;
     RECT  14.065 96 14.195 103.464 ;
     RECT  13.948 91.776 14.243 91.8 ;
     RECT  13.853 93.984 14.249 94.584 ;
     RECT  13.948 92.88 14.291 92.904 ;
     RECT  14.195 96 14.321 100.968 ;
     RECT  13.933 82.272 14.38 82.296 ;
     RECT  14.051 2.88 14.533 3.576 ;
     RECT  13.565 41.76 14.573 41.784 ;
     RECT  13.504 7.872 14.641 7.896 ;
     RECT  14.249 93.984 14.681 94.008 ;
     RECT  13.715 42.816 14.713 42.84 ;
     RECT  13.715 43.872 14.713 45.432 ;
     RECT  14.195 102 14.741 103.464 ;
     RECT  13.673 46.8 14.749 64.152 ;
     RECT  14.677 77.28 14.764 77.304 ;
     RECT  13.715 65.376 14.819 65.4 ;
     RECT  13.504 85.104 14.819 85.128 ;
     RECT  13.667 39.888 14.821 39.912 ;
     RECT  14.321 96 14.821 100.872 ;
     RECT  14.821 39.888 14.861 40.056 ;
     RECT  14.713 42.816 14.893 45.432 ;
     RECT  14.828 78.576 14.915 79.176 ;
     RECT  13.504 6 14.965 6.024 ;
     RECT  14.917 80.88 15.004 80.904 ;
     RECT  14.924 76.08 15.011 76.104 ;
     RECT  14.965 74.64 15.037 74.664 ;
     RECT  14.893 42.768 15.041 45.432 ;
     RECT  14.051 0.144 15.073 1.416 ;
     RECT  14.965 5.664 15.107 6.024 ;
     RECT  15.041 43.584 15.113 45.432 ;
     RECT  15.037 74.592 15.121 74.664 ;
     RECT  14.741 102 15.181 103.512 ;
     RECT  15.121 74.64 15.185 74.664 ;
     RECT  14.533 2.88 15.203 3.96 ;
     RECT  15.203 2.88 15.293 3.432 ;
     RECT  14.749 46.608 15.293 64.152 ;
     RECT  14.641 7.392 15.347 7.896 ;
     RECT  15.181 101.904 15.347 103.512 ;
     RECT  15.107 5.664 15.395 5.688 ;
     RECT  15.361 78.048 15.445 78.072 ;
     RECT  15.073 0.144 15.469 1.704 ;
     RECT  14.821 95.76 15.541 100.872 ;
     RECT  15.5 67.488 15.587 67.512 ;
     RECT  15.541 68.64 15.628 68.664 ;
     RECT  15.26 94.176 15.661 94.296 ;
     RECT  15.347 101.952 15.685 103.512 ;
     RECT  15.293 46.752 15.697 64.152 ;
     RECT  14.965 90.912 15.821 90.936 ;
     RECT  15.74 69.888 15.827 69.912 ;
     RECT  15.829 94.512 15.865 94.68 ;
     RECT  15.821 90.912 15.905 91.272 ;
     RECT  15.836 71.856 15.923 71.88 ;
     RECT  15.469 0.144 15.941 2.328 ;
     RECT  14.915 79.152 15.941 79.176 ;
     RECT  15.685 88.416 15.971 88.44 ;
     RECT  15.865 94.512 15.971 94.776 ;
     RECT  15.877 24.528 15.977 24.552 ;
     RECT  15.971 94.656 16.045 94.776 ;
     RECT  15.541 95.76 16.045 100.92 ;
     RECT  15.113 43.68 16.049 45.432 ;
     RECT  15.973 90.528 16.057 90.552 ;
     RECT  16.045 94.656 16.121 100.92 ;
     RECT  16.076 84.816 16.163 84.84 ;
     RECT  15.685 101.952 16.163 103.56 ;
     RECT  16.213 65.328 16.3 65.688 ;
     RECT  15.829 37.632 16.355 37.656 ;
     RECT  16.049 43.68 16.409 45.24 ;
     RECT  16.364 82.032 16.451 82.056 ;
     RECT  14.861 40.032 16.508 40.056 ;
     RECT  16.117 86.592 16.513 86.616 ;
     RECT  15.697 46.8 16.549 64.152 ;
     RECT  16.3 65.328 16.549 65.4 ;
     RECT  16.513 86.448 16.549 86.616 ;
     RECT  16.508 39.696 16.595 40.056 ;
     RECT  16.121 94.896 16.693 100.92 ;
     RECT  16.163 101.952 16.693 102.984 ;
     RECT  16.405 85.296 16.733 85.416 ;
     RECT  16.693 92.832 16.78 92.856 ;
     RECT  15.293 3.408 16.835 3.432 ;
     RECT  16.693 4.512 16.837 4.536 ;
     RECT  16.733 85.392 16.837 85.416 ;
     RECT  16.549 86.448 16.837 86.664 ;
     RECT  16.837 85.392 16.841 86.664 ;
     RECT  15.347 7.872 16.873 7.896 ;
     RECT  15.637 8.976 16.873 9 ;
     RECT  16.409 43.68 16.892 44.472 ;
     RECT  16.841 85.392 16.924 85.656 ;
     RECT  16.801 66.72 16.94 66.744 ;
     RECT  16.892 43.344 16.979 44.472 ;
     RECT  16.837 88.368 16.979 88.392 ;
     RECT  16.885 71.184 16.985 71.208 ;
     RECT  16.94 66.72 17.021 67.224 ;
     RECT  17.021 67.2 17.027 67.224 ;
     RECT  16.94 91.728 17.027 91.752 ;
     RECT  15.941 0.144 17.075 1.704 ;
     RECT  16.837 3.936 17.123 4.536 ;
     RECT  16.924 85.392 17.123 85.416 ;
     RECT  16.693 94.896 17.153 102.984 ;
     RECT  17.075 1.584 17.161 1.704 ;
     RECT  16.549 46.8 17.164 65.4 ;
     RECT  17.164 46.8 17.165 64.968 ;
     RECT  17.153 94.896 17.171 103.512 ;
     RECT  17.171 94.896 17.173 95.16 ;
     RECT  17.132 41.28 17.219 41.304 ;
     RECT  17.161 1.584 17.233 2.04 ;
     RECT  16.979 43.872 17.267 44.472 ;
     RECT  17.189 91.776 17.273 91.8 ;
     RECT  15.925 6.816 17.305 6.84 ;
     RECT  16.873 7.872 17.305 9 ;
     RECT  17.173 94.896 17.309 94.92 ;
     RECT  17.233 1.584 17.377 2.232 ;
     RECT  17.077 76.608 17.453 76.632 ;
     RECT  17.171 96.288 17.477 103.512 ;
     RECT  17.413 80.64 17.5 80.664 ;
     RECT  17.305 6.816 17.507 9 ;
     RECT  17.413 90.576 17.507 90.6 ;
     RECT  17.377 1.584 17.521 2.28 ;
     RECT  17.477 96.288 17.561 103.56 ;
     RECT  17.305 72.672 17.797 72.696 ;
     RECT  17.075 0.144 17.845 0.552 ;
     RECT  17.797 74.544 17.845 74.568 ;
     RECT  17.561 96.288 17.987 103.512 ;
     RECT  17.507 8.976 17.989 9 ;
     RECT  17.987 96.288 18.131 102.12 ;
     RECT  17.267 44.352 18.205 44.472 ;
     RECT  17.845 0.096 18.229 0.552 ;
     RECT  17.521 1.584 18.229 2.856 ;
     RECT  16.595 40.032 18.229 40.056 ;
     RECT  18.205 44.352 18.236 45 ;
     RECT  18.236 44.352 18.241 45.048 ;
     RECT  17.165 46.8 18.241 47.208 ;
     RECT  17.66 67.488 18.241 67.512 ;
     RECT  17.797 71.616 18.313 71.64 ;
     RECT  17.797 72.672 18.313 72.984 ;
     RECT  18.421 92.832 18.493 92.856 ;
     RECT  18.229 0.096 18.556 2.856 ;
     RECT  18.556 0.144 18.608 2.856 ;
     RECT  17.123 3.936 18.608 4.248 ;
     RECT  18.469 5.616 18.608 5.64 ;
     RECT  17.507 6.816 18.608 7.896 ;
     RECT  17.989 8.976 18.608 9.816 ;
     RECT  17.701 11.952 18.608 11.976 ;
     RECT  17.845 35.328 18.608 35.352 ;
     RECT  18.277 38.784 18.608 38.808 ;
     RECT  18.229 39.888 18.608 40.056 ;
     RECT  18.385 42.768 18.608 42.792 ;
     RECT  18.241 44.352 18.608 47.208 ;
     RECT  17.165 48.192 18.608 64.968 ;
     RECT  18.241 66.672 18.608 67.512 ;
     RECT  18.313 71.616 18.608 72.984 ;
     RECT  17.845 74.544 18.608 75.288 ;
     RECT  17.737 80.16 18.608 80.184 ;
     RECT  18.053 82.656 18.608 82.68 ;
     RECT  17.941 84.816 18.608 84.84 ;
     RECT  18.373 86.352 18.608 86.376 ;
     RECT  18.229 90.912 18.608 90.936 ;
     RECT  18.493 92.832 18.608 93.24 ;
     RECT  18.131 96.288 18.608 102.072 ;
     RECT  18.608 0.144 18.899 102.072 ;
     RECT  18.899 0.144 18.904 101.544 ;
     RECT  17.987 103.152 18.997 103.512 ;
     RECT  18.904 0.144 19.043 5.112 ;
     RECT  18.904 71.328 19.043 71.352 ;
     RECT  18.904 90.816 19.043 92.568 ;
     RECT  19.043 91.44 19.081 92.568 ;
     RECT  18.904 41.904 19.091 41.928 ;
     RECT  19.081 91.44 19.117 92.28 ;
     RECT  18.904 6.816 19.139 6.84 ;
     RECT  19.117 91.44 19.139 91.464 ;
     RECT  18.904 72.96 19.145 72.984 ;
     RECT  18.904 94.032 19.187 95.16 ;
     RECT  18.904 39.888 19.261 39.96 ;
     RECT  18.904 86.064 19.261 86.664 ;
     RECT  19.043 0.144 19.331 2.856 ;
     RECT  18.904 44.976 19.331 45.576 ;
     RECT  18.904 46.704 19.361 64.968 ;
     RECT  19.187 94.224 19.397 95.16 ;
     RECT  18.904 8.976 19.433 9.816 ;
     RECT  19.361 48.192 19.433 64.968 ;
     RECT  18.904 84.528 19.475 84.552 ;
     RECT  18.904 82.608 19.613 83.256 ;
     RECT  19.397 94.224 19.649 94.248 ;
     RECT  19.433 48.192 19.721 49.272 ;
     RECT  19.043 3.888 19.763 5.112 ;
     RECT  18.904 69.36 19.811 69.384 ;
     RECT  19.763 3.936 19.859 5.112 ;
     RECT  18.997 103.152 19.859 103.56 ;
     RECT  18.904 74.064 19.865 74.088 ;
     RECT  19.859 103.152 19.9 103.32 ;
     RECT  18.904 96.336 19.916 101.544 ;
     RECT  19.916 96.048 19.933 101.544 ;
     RECT  19.9 102.672 19.933 103.32 ;
     RECT  19.868 77.136 19.955 77.16 ;
     RECT  19.933 96.048 19.955 103.32 ;
     RECT  19.955 96.048 20.003 103.224 ;
     RECT  19.613 83.232 20.017 83.256 ;
     RECT  19.261 86.64 20.041 86.664 ;
     RECT  19.964 70.752 20.051 70.776 ;
     RECT  20.003 96.048 20.051 102.696 ;
     RECT  19.361 46.704 20.099 47.16 ;
     RECT  20.069 41.04 20.153 41.064 ;
     RECT  20.099 46.8 20.153 47.16 ;
     RECT  20.041 90.576 20.185 90.6 ;
     RECT  19.721 48.432 20.189 49.272 ;
     RECT  20.153 46.944 20.225 47.16 ;
     RECT  19.859 3.936 20.291 5.016 ;
     RECT  20.185 90.576 20.297 91.272 ;
     RECT  20.041 86.64 20.3 87.288 ;
     RECT  20.3 86.64 20.387 87.96 ;
     RECT  19.331 0.144 20.401 1.752 ;
     RECT  19.331 2.832 20.401 2.856 ;
     RECT  20.357 85.488 20.441 85.512 ;
     RECT  20.396 79.056 20.483 79.08 ;
     RECT  20.225 46.992 20.496 47.16 ;
     RECT  20.297 91.104 20.531 91.272 ;
     RECT  20.051 96.048 20.54 101.544 ;
     RECT  20.401 0.144 20.579 2.856 ;
     RECT  19.331 45.552 20.588 45.576 ;
     RECT  20.533 76.608 20.62 76.632 ;
     RECT  20.54 95.136 20.627 101.544 ;
     RECT  19.261 39.888 20.645 39.912 ;
     RECT  20.588 45.552 20.675 45.672 ;
     RECT  20.675 45.552 20.723 45.576 ;
     RECT  20.645 39.36 20.729 39.912 ;
     RECT  20.653 94.608 20.737 94.632 ;
     RECT  20.684 80.88 20.771 80.904 ;
     RECT  20.496 47.136 20.837 47.16 ;
     RECT  20.761 41.616 20.845 41.64 ;
     RECT  20.387 87.216 20.909 87.24 ;
     RECT  20.051 102.624 21.005 102.696 ;
     RECT  20.579 2.736 21.011 2.856 ;
     RECT  20.189 48.768 21.013 49.272 ;
     RECT  19.433 50.256 21.013 64.152 ;
     RECT  21.005 102.624 21.089 103.512 ;
     RECT  21.077 38.784 21.161 38.808 ;
     RECT  21.109 69.696 21.196 69.72 ;
     RECT  20.291 3.984 21.253 5.016 ;
     RECT  20.531 91.104 21.277 91.128 ;
     RECT  21.193 92.784 21.277 92.808 ;
     RECT  21.205 80.016 21.292 80.04 ;
     RECT  21.253 3.984 21.301 5.16 ;
     RECT  18.904 7.872 21.377 7.896 ;
     RECT  21.301 3.936 21.413 5.16 ;
     RECT  21.157 83.28 21.449 83.304 ;
     RECT  21.011 2.784 21.589 2.856 ;
     RECT  21.413 3.936 21.589 5.016 ;
     RECT  19.433 9.792 21.589 9.816 ;
     RECT  21.493 13.104 21.593 13.128 ;
     RECT  21.089 102.624 21.635 103.464 ;
     RECT  20.627 95.712 21.661 101.448 ;
     RECT  21.661 95.712 21.692 101.496 ;
     RECT  20.579 0.144 21.701 1.752 ;
     RECT  20.965 93.888 21.769 93.912 ;
     RECT  21.013 48.768 21.773 64.152 ;
     RECT  21.692 94.896 21.779 101.496 ;
     RECT  21.769 92.928 21.781 93.912 ;
     RECT  21.779 94.992 21.805 101.496 ;
     RECT  21.589 2.784 21.827 5.016 ;
     RECT  21.637 76.464 21.829 76.488 ;
     RECT  21.829 76.464 21.881 76.728 ;
     RECT  21.637 91.152 21.881 91.176 ;
     RECT  21.781 92.928 21.881 94.008 ;
     RECT  21.881 76.704 21.916 76.728 ;
     RECT  21.827 3.408 21.923 5.016 ;
     RECT  21.773 49.248 21.949 64.152 ;
     RECT  21.949 49.248 22.061 64.968 ;
     RECT  22.057 78.672 22.069 78.696 ;
     RECT  21.589 9.648 22.115 9.816 ;
     RECT  21.877 8.496 22.117 8.52 ;
     RECT  22.069 78.672 22.156 79.08 ;
     RECT  22.117 8.496 22.205 8.568 ;
     RECT  22.021 82.608 22.205 82.632 ;
     RECT  22.093 81.264 22.211 81.288 ;
     RECT  21.805 85.296 22.211 85.32 ;
     RECT  21.805 94.992 22.211 102.072 ;
     RECT  22.156 78.672 22.241 78.696 ;
     RECT  21.635 103.248 22.301 103.464 ;
     RECT  22.205 8.496 22.307 8.52 ;
     RECT  22.211 96.336 22.313 102.072 ;
     RECT  22.211 94.992 22.355 95.016 ;
     RECT  22.021 66.48 22.373 66.504 ;
     RECT  22.301 103.248 22.385 103.512 ;
     RECT  22.373 66.48 22.405 67.272 ;
     RECT  22.213 87.984 22.421 88.008 ;
     RECT  22.405 65.904 22.451 67.272 ;
     RECT  22.451 67.248 22.457 67.272 ;
     RECT  22.157 72.96 22.508 72.984 ;
     RECT  22.385 103.248 22.565 103.464 ;
     RECT  22.508 7.248 22.595 7.272 ;
     RECT  22.061 49.248 22.595 64.152 ;
     RECT  22.508 72.96 22.595 73.416 ;
     RECT  21.881 92.928 22.604 93.432 ;
     RECT  22.604 91.728 22.691 93.432 ;
     RECT  22.565 103.248 22.691 103.368 ;
     RECT  21.923 4.992 22.741 5.016 ;
     RECT  22.597 71.472 22.787 71.496 ;
     RECT  22.669 72.48 22.787 72.504 ;
     RECT  22.313 96.624 22.813 102.072 ;
     RECT  22.309 38.208 22.835 38.232 ;
     RECT  22.693 37.056 22.853 37.08 ;
     RECT  22.741 4.992 22.885 5.112 ;
     RECT  22.813 82.128 22.897 82.152 ;
     RECT  22.691 92.544 22.931 93.432 ;
     RECT  22.549 90.528 22.993 90.6 ;
     RECT  22.885 4.56 23.027 5.112 ;
     RECT  22.933 2.304 23.065 2.328 ;
     RECT  21.923 3.408 23.065 3.432 ;
     RECT  22.813 96.624 23.267 103.08 ;
     RECT  23.267 96.624 23.276 101.496 ;
     RECT  23.317 75.84 23.324 75.864 ;
     RECT  21.701 0.144 23.353 1.128 ;
     RECT  23.065 2.304 23.353 3.432 ;
     RECT  22.993 90.528 23.413 91.368 ;
     RECT  22.595 50.16 23.509 64.152 ;
     RECT  22.451 65.904 23.509 65.928 ;
     RECT  23.276 96.48 23.509 101.496 ;
     RECT  23.353 0.144 23.533 3.432 ;
     RECT  23.027 4.56 23.533 5.016 ;
     RECT  23.269 95.328 23.564 95.352 ;
     RECT  23.509 96.336 23.564 101.496 ;
     RECT  22.931 93.408 23.633 93.432 ;
     RECT  23.641 78.672 23.677 78.696 ;
     RECT  23.633 93.408 23.708 94.056 ;
     RECT  23.564 95.328 23.708 101.496 ;
     RECT  23.267 102.624 23.749 103.08 ;
     RECT  23.065 45.024 23.785 45.048 ;
     RECT  23.756 71.472 23.893 71.496 ;
     RECT  23.461 85.344 23.929 85.368 ;
     RECT  23.749 102.624 23.939 103.32 ;
     RECT  23.533 0.144 24.008 5.016 ;
     RECT  22.115 9.792 24.008 9.816 ;
     RECT  20.729 39.888 24.008 39.912 ;
     RECT  23.785 45.024 24.008 45.624 ;
     RECT  23.509 50.16 24.008 65.928 ;
     RECT  23.929 69.024 24.008 69.048 ;
     RECT  23.893 71.472 24.008 72.456 ;
     RECT  23.929 73.536 24.008 73.56 ;
     RECT  23.324 74.976 24.008 75.864 ;
     RECT  23.677 78.576 24.008 78.696 ;
     RECT  23.317 82.416 24.008 82.44 ;
     RECT  23.929 85.104 24.008 85.368 ;
     RECT  23.852 87.168 24.008 87.192 ;
     RECT  23.413 90.048 24.008 91.368 ;
     RECT  23.708 93.408 24.008 101.496 ;
     RECT  23.939 103.056 24.083 103.32 ;
     RECT  24.008 0.144 24.304 101.496 ;
     RECT  24.304 92.832 24.401 94.632 ;
     RECT  24.401 92.832 24.419 92.856 ;
     RECT  24.304 0.144 24.421 4.584 ;
     RECT  24.304 42.768 24.437 42.792 ;
     RECT  24.304 50.544 24.437 64.968 ;
     RECT  24.304 67.968 24.437 69.72 ;
     RECT  24.304 43.92 24.445 45.144 ;
     RECT  24.304 46.176 24.467 46.872 ;
     RECT  24.304 84.96 24.467 85.272 ;
     RECT  24.304 90.768 24.467 91.368 ;
     RECT  24.401 93.984 24.467 94.632 ;
     RECT  24.421 0.096 24.473 4.584 ;
     RECT  24.467 46.176 24.481 46.776 ;
     RECT  24.083 103.296 24.497 103.32 ;
     RECT  24.481 46.752 24.509 46.776 ;
     RECT  24.473 0.096 24.515 1.704 ;
     RECT  24.304 66.72 24.515 66.84 ;
     RECT  24.304 73.536 24.515 73.56 ;
     RECT  24.304 87.408 24.515 88.968 ;
     RECT  24.467 94.608 24.515 94.632 ;
     RECT  24.445 45.12 24.545 45.144 ;
     RECT  24.445 43.92 24.553 44.136 ;
     RECT  24.437 50.544 24.556 53.544 ;
     RECT  24.304 10.848 24.563 10.872 ;
     RECT  24.304 22.752 24.563 22.776 ;
     RECT  24.304 26.784 24.563 26.808 ;
     RECT  24.304 34.752 24.563 34.872 ;
     RECT  24.304 39.888 24.563 40.152 ;
     RECT  24.515 66.72 24.581 66.744 ;
     RECT  24.437 67.968 24.581 68.424 ;
     RECT  24.304 5.664 24.611 6.84 ;
     RECT  24.304 38.784 24.611 38.808 ;
     RECT  24.553 44.016 24.611 44.136 ;
     RECT  24.304 77.424 24.611 77.448 ;
     RECT  24.467 90.768 24.611 90.792 ;
     RECT  24.611 44.112 24.659 44.136 ;
     RECT  24.515 87.408 24.659 88.392 ;
     RECT  24.611 5.664 24.707 6.792 ;
     RECT  24.467 85.248 24.797 85.272 ;
     RECT  24.556 50.736 24.833 53.544 ;
     RECT  24.707 5.664 24.851 6.264 ;
     RECT  24.473 2.832 24.941 4.584 ;
     RECT  24.659 88.368 24.985 88.392 ;
     RECT  24.304 9.792 25.013 9.816 ;
     RECT  24.941 2.832 25.043 4.536 ;
     RECT  24.833 50.736 25.049 50.76 ;
     RECT  24.497 103.296 25.081 103.512 ;
     RECT  24.304 82.416 25.085 82.68 ;
     RECT  24.304 14.976 25.121 15 ;
     RECT  24.581 67.968 25.139 67.992 ;
     RECT  24.437 69.696 25.139 69.72 ;
     RECT  25.081 102.672 25.186 103.512 ;
     RECT  24.437 54.576 25.229 64.968 ;
     RECT  24.851 6.24 25.235 6.264 ;
     RECT  24.304 95.76 25.333 101.496 ;
     RECT  25.186 102.624 25.333 103.512 ;
     RECT  25.333 95.76 25.429 103.512 ;
     RECT  25.333 86.64 25.445 87.144 ;
     RECT  24.515 0.144 25.505 1.704 ;
     RECT  25.429 92.544 25.516 92.568 ;
     RECT  25.429 94.992 25.516 103.512 ;
     RECT  25.429 31.872 25.517 31.896 ;
     RECT  25.516 95.76 25.585 103.512 ;
     RECT  25.505 0.144 25.589 1.752 ;
     RECT  24.833 51.888 25.589 53.544 ;
     RECT  25.445 87.12 25.661 87.144 ;
     RECT  25.285 89.472 25.661 89.496 ;
     RECT  25.043 4.512 25.667 4.536 ;
     RECT  25.58 74.64 25.667 75.192 ;
     RECT  25.441 80.496 25.667 80.52 ;
     RECT  25.477 42.192 25.697 42.216 ;
     RECT  25.585 95.76 25.733 103.56 ;
     RECT  25.729 40.992 25.813 41.016 ;
     RECT  25.813 94.08 25.837 94.68 ;
     RECT  25.589 51.936 25.877 53.544 ;
     RECT  24.304 79.392 25.907 79.416 ;
     RECT  25.733 96.144 26.003 103.56 ;
     RECT  25.043 2.832 26.051 3.384 ;
     RECT  26.003 97.488 26.051 103.56 ;
     RECT  25.837 93.984 26.057 94.68 ;
     RECT  25.873 71.04 26.108 71.064 ;
     RECT  25.085 82.656 26.129 82.68 ;
     RECT  26.053 3.408 26.137 3.432 ;
     RECT  26.089 47.328 26.173 47.352 ;
     RECT  26.003 96.144 26.188 96.168 ;
     RECT  26.108 71.04 26.195 71.544 ;
     RECT  25.589 0.144 26.197 1.704 ;
     RECT  24.563 39.888 26.197 39.912 ;
     RECT  26.149 3.936 26.236 3.96 ;
     RECT  26.195 71.04 26.243 71.064 ;
     RECT  25.981 87.792 26.243 87.816 ;
     RECT  26.057 94.656 26.243 94.68 ;
     RECT  26.189 84.288 26.273 84.312 ;
     RECT  26.261 93.504 26.345 93.528 ;
     RECT  26.269 50.736 26.417 50.76 ;
     RECT  26.341 47.904 26.425 47.928 ;
     RECT  25.877 52.368 26.449 53.544 ;
     RECT  26.437 78.048 26.449 78.072 ;
     RECT  26.389 65.136 26.476 65.16 ;
     RECT  26.197 39.888 26.485 39.96 ;
     RECT  26.449 78.048 26.524 78.696 ;
     RECT  26.051 97.488 26.531 103.512 ;
     RECT  26.449 52.368 26.561 53.592 ;
     RECT  26.524 78.672 26.561 78.696 ;
     RECT  26.485 39.36 26.569 39.96 ;
     RECT  26.485 90.528 26.569 90.552 ;
     RECT  26.485 92.832 26.579 92.856 ;
     RECT  26.557 86.064 26.588 86.088 ;
     RECT  26.521 43.92 26.605 43.944 ;
     RECT  26.588 85.104 26.641 86.088 ;
     RECT  26.437 37.056 26.669 37.08 ;
     RECT  26.641 85.104 26.675 85.128 ;
     RECT  26.561 52.704 26.773 53.592 ;
     RECT  25.229 54.576 26.773 64.152 ;
     RECT  26.569 39.888 26.779 39.96 ;
     RECT  26.773 52.704 26.813 64.152 ;
     RECT  26.773 75.36 26.885 75.384 ;
     RECT  26.017 5.664 26.963 5.688 ;
     RECT  26.197 0.096 26.965 1.704 ;
     RECT  26.965 0.096 27.059 2.328 ;
     RECT  27.059 2.304 27.065 2.328 ;
     RECT  26.773 95.136 27.133 95.16 ;
     RECT  27.157 47.28 27.281 47.352 ;
     RECT  27.233 71.76 27.317 71.784 ;
     RECT  26.531 99.168 27.346 103.512 ;
     RECT  26.813 53.664 27.347 64.152 ;
     RECT  27.277 88.464 27.361 88.488 ;
     RECT  27.281 47.328 27.389 47.352 ;
     RECT  27.301 4.272 27.421 4.296 ;
     RECT  27.349 73.536 27.433 73.56 ;
     RECT  27.346 99.168 27.443 103.56 ;
     RECT  27.377 94.128 27.461 94.152 ;
     RECT  27.404 92.064 27.491 92.088 ;
     RECT  27.589 93.36 27.637 93.384 ;
     RECT  26.531 97.488 27.644 98.088 ;
     RECT  27.443 99.168 27.644 103.512 ;
     RECT  27.637 93.072 27.673 93.384 ;
     RECT  27.596 86.88 27.683 86.904 ;
     RECT  27.133 95.136 27.709 95.832 ;
     RECT  27.673 92.352 27.749 93.384 ;
     RECT  27.749 92.352 27.757 92.856 ;
     RECT  27.709 95.136 27.781 96.36 ;
     RECT  27.701 52.656 27.785 52.68 ;
     RECT  27.673 47.856 27.923 47.88 ;
     RECT  27.781 95.088 27.923 96.36 ;
     RECT  27.781 68.352 27.925 68.376 ;
     RECT  27.347 53.904 27.929 64.152 ;
     RECT  27.565 82.656 27.929 82.68 ;
     RECT  27.923 95.76 27.997 96.36 ;
     RECT  27.644 97.488 27.997 103.512 ;
     RECT  27.421 3.936 28.001 4.296 ;
     RECT  26.779 39.888 28.001 39.912 ;
     RECT  27.997 95.76 28.009 103.512 ;
     RECT  28.009 95.76 28.067 95.832 ;
     RECT  27.277 2.736 28.097 2.76 ;
     RECT  28.009 96.864 28.163 103.512 ;
     RECT  27.059 0.096 28.181 1.176 ;
     RECT  28.097 2.736 28.181 2.856 ;
     RECT  27.929 54.528 28.181 64.152 ;
     RECT  28.067 95.808 28.211 95.832 ;
     RECT  27.961 6.24 28.259 6.264 ;
     RECT  28.181 54.624 28.289 64.152 ;
     RECT  27.757 92.832 28.307 92.856 ;
     RECT  27.925 68.352 28.361 69 ;
     RECT  28.309 5.712 28.433 5.736 ;
     RECT  28.249 78.672 28.433 78.696 ;
     RECT  28.181 0.144 28.748 1.176 ;
     RECT  28.393 2.256 28.748 2.28 ;
     RECT  28.573 42.192 28.753 42.216 ;
     RECT  28.421 85.488 28.897 85.512 ;
     RECT  28.163 96.912 28.941 103.512 ;
     RECT  28.941 96.912 29.009 103.464 ;
     RECT  28.741 92.928 29.029 92.952 ;
     RECT  28.997 94.416 29.041 94.44 ;
     RECT  28.405 3.408 29.077 3.48 ;
     RECT  28.573 4.512 29.077 4.536 ;
     RECT  28.861 74.784 29.113 74.808 ;
     RECT  28.897 46.704 29.125 46.728 ;
     RECT  29.077 83.424 29.125 83.448 ;
     RECT  29.077 80.976 29.149 81 ;
     RECT  29.125 82.656 29.149 83.448 ;
     RECT  29.041 94.416 29.149 94.824 ;
     RECT  28.556 50.784 29.173 50.808 ;
     RECT  29.149 94.368 29.173 94.824 ;
     RECT  29.113 74.784 29.221 74.952 ;
     RECT  29.029 92.928 29.221 93.384 ;
     RECT  29.173 94.368 29.221 94.968 ;
     RECT  28.933 37.056 29.249 37.08 ;
     RECT  29.173 52.032 29.249 52.056 ;
     RECT  28.717 78 29.269 78.024 ;
     RECT  29.221 92.928 29.269 94.968 ;
     RECT  29.269 92.448 29.329 95.688 ;
     RECT  28.748 0.144 29.408 2.28 ;
     RECT  29.077 3.408 29.408 4.536 ;
     RECT  29.269 6.24 29.408 6.264 ;
     RECT  28.429 7.392 29.408 7.416 ;
     RECT  27.829 9.648 29.408 9.672 ;
     RECT  29.269 24.384 29.408 24.408 ;
     RECT  29.077 27.888 29.408 27.912 ;
     RECT  29.221 31.008 29.408 31.032 ;
     RECT  29.029 32.448 29.408 32.472 ;
     RECT  29.249 36.816 29.408 37.08 ;
     RECT  28.753 42.096 29.408 42.216 ;
     RECT  29.125 45.024 29.408 45.048 ;
     RECT  29.125 46.608 29.408 46.728 ;
     RECT  29.141 48.48 29.408 48.504 ;
     RECT  29.173 50.688 29.408 50.808 ;
     RECT  29.249 51.792 29.408 52.056 ;
     RECT  28.289 54.672 29.408 64.152 ;
     RECT  28.361 68.352 29.408 68.376 ;
     RECT  29.077 72.096 29.408 72.12 ;
     RECT  29.221 74.688 29.408 74.952 ;
     RECT  29.269 77.04 29.408 78.024 ;
     RECT  28.652 79.968 29.408 79.992 ;
     RECT  29.149 80.976 29.408 83.448 ;
     RECT  28.897 84.96 29.408 85.512 ;
     RECT  28.033 86.64 29.408 86.664 ;
     RECT  28.885 90.528 29.408 90.552 ;
     RECT  29.329 92.4 29.408 95.688 ;
     RECT  29.009 96.912 29.408 101.688 ;
     RECT  29.408 0.144 29.704 101.688 ;
     RECT  29.704 24.384 29.801 24.408 ;
     RECT  29.704 83.76 29.801 83.784 ;
     RECT  29.704 56.304 29.873 64.152 ;
     RECT  29.704 90.096 29.909 92.856 ;
     RECT  29.704 100.896 30.013 101.688 ;
     RECT  29.009 103.296 30.013 103.464 ;
     RECT  29.704 27.936 30.025 27.96 ;
     RECT  29.873 56.4 30.035 64.152 ;
     RECT  29.704 72.672 30.061 73.56 ;
     RECT  29.704 95.712 30.161 95.784 ;
     RECT  30.035 56.544 30.179 64.152 ;
     RECT  29.909 90.624 30.227 92.856 ;
     RECT  30.161 95.76 30.323 95.784 ;
     RECT  29.704 84.816 30.364 85.464 ;
     RECT  29.704 0.144 30.371 4.008 ;
     RECT  29.704 71.232 30.46 71.256 ;
     RECT  30.371 3.408 30.485 4.008 ;
     RECT  30.371 0.144 30.611 2.28 ;
     RECT  29.704 5.712 30.629 5.736 ;
     RECT  29.704 65.568 30.629 65.64 ;
     RECT  30.061 72.672 30.652 72.696 ;
     RECT  30.227 92.352 30.652 92.856 ;
     RECT  30.013 100.896 30.659 103.464 ;
     RECT  30.364 85.44 30.665 85.464 ;
     RECT  30.227 90.624 30.701 91.176 ;
     RECT  30.611 1.68 30.707 2.28 ;
     RECT  30.701 90.72 30.737 91.176 ;
     RECT  30.668 45.024 30.755 45.048 ;
     RECT  29.704 94.56 30.757 94.584 ;
     RECT  29.704 96.912 30.757 99.816 ;
     RECT  30.659 100.896 30.757 102.024 ;
     RECT  29.704 87.936 30.769 87.96 ;
     RECT  30.757 94.464 30.769 94.728 ;
     RECT  30.629 65.616 30.803 65.64 ;
     RECT  30.769 94.464 30.805 94.776 ;
     RECT  30.757 96.912 30.805 102.024 ;
     RECT  30.805 94.08 30.889 94.776 ;
     RECT  30.652 92.352 30.899 92.376 ;
     RECT  30.889 94.464 30.899 94.776 ;
     RECT  30.659 103.248 30.899 103.464 ;
     RECT  30.179 56.592 30.917 64.152 ;
     RECT  30.611 0.144 30.947 0.648 ;
     RECT  30.805 82.896 30.953 82.92 ;
     RECT  30.908 76.176 30.995 76.2 ;
     RECT  30.899 94.704 30.995 94.776 ;
     RECT  30.899 103.296 31.085 103.464 ;
     RECT  31.052 53.52 31.139 53.544 ;
     RECT  31.121 83.184 31.205 83.832 ;
     RECT  31.129 32.448 31.235 32.472 ;
     RECT  30.737 91.152 31.235 91.176 ;
     RECT  30.805 96.864 31.237 102.024 ;
     RECT  30.769 87.936 31.277 88.92 ;
     RECT  31.237 78.624 31.321 78.648 ;
     RECT  30.917 57.6 31.333 64.152 ;
     RECT  30.485 3.408 31.345 3.432 ;
     RECT  31.085 103.296 31.345 103.512 ;
     RECT  31.265 25.104 31.349 25.128 ;
     RECT  31.141 47.328 31.385 47.352 ;
     RECT  31.301 91.68 31.385 91.704 ;
     RECT  31.333 4.56 31.421 4.584 ;
     RECT  30.707 1.68 31.523 1.704 ;
     RECT  31.345 2.832 31.537 3.432 ;
     RECT  31.484 54.288 31.571 54.312 ;
     RECT  31.345 103.296 31.571 103.56 ;
     RECT  31.237 96.336 31.58 102.024 ;
     RECT  31.58 96.048 31.612 102.024 ;
     RECT  31.612 97.392 31.619 102.024 ;
     RECT  31.612 96.048 31.667 96.072 ;
     RECT  31.489 50.736 31.673 50.76 ;
     RECT  31.597 89.328 31.745 89.496 ;
     RECT  31.676 3.936 31.763 3.96 ;
     RECT  31.333 57.6 31.765 64.584 ;
     RECT  31.765 57.6 31.859 64.68 ;
     RECT  30.995 94.752 31.861 94.776 ;
     RECT  31.633 71.712 31.907 71.736 ;
     RECT  31.861 94.752 31.948 95.016 ;
     RECT  31.861 39.888 31.961 39.912 ;
     RECT  31.765 48.48 31.961 48.504 ;
     RECT  31.859 57.84 31.961 64.68 ;
     RECT  31.205 83.184 31.961 83.784 ;
     RECT  31.961 58.272 31.985 64.68 ;
     RECT  31.985 58.272 31.997 64.92 ;
     RECT  30.947 0.144 32.021 0.552 ;
     RECT  31.961 83.76 32.051 83.784 ;
     RECT  32.021 0.144 32.06 0.6 ;
     RECT  31.745 89.328 32.099 89.352 ;
     RECT  31.909 91.776 32.108 91.8 ;
     RECT  32.06 75.648 32.147 75.672 ;
     RECT  31.957 94.56 32.173 94.68 ;
     RECT  32.108 91.776 32.177 92.328 ;
     RECT  32.177 92.304 32.195 92.328 ;
     RECT  31.997 58.32 32.209 64.92 ;
     RECT  32.137 86.64 32.249 86.664 ;
     RECT  32.245 34.512 32.393 34.536 ;
     RECT  32.341 38.16 32.428 38.184 ;
     RECT  32.06 0.144 32.429 1.272 ;
     RECT  32.209 58.32 32.429 64.968 ;
     RECT  32.389 23.376 32.473 23.4 ;
     RECT  32.281 45.552 32.483 45.576 ;
     RECT  32.317 54.768 32.483 54.936 ;
     RECT  32.389 79.152 32.483 79.176 ;
     RECT  32.173 93.936 32.483 94.68 ;
     RECT  30.917 56.592 32.485 56.616 ;
     RECT  32.485 53.52 32.492 53.544 ;
     RECT  31.619 97.488 32.497 102.024 ;
     RECT  31.571 103.296 32.497 103.512 ;
     RECT  32.483 54.768 32.524 54.792 ;
     RECT  32.437 38.784 32.537 38.808 ;
     RECT  32.437 92.832 32.537 92.856 ;
     RECT  32.485 73.728 32.572 73.752 ;
     RECT  32.492 52.944 32.573 53.544 ;
     RECT  32.485 55.92 32.573 56.616 ;
     RECT  32.573 52.944 32.579 53.016 ;
     RECT  31.537 2.832 32.581 2.904 ;
     RECT  32.497 97.488 32.581 103.512 ;
     RECT  32.483 94.608 32.601 94.68 ;
     RECT  32.485 82.704 32.629 82.728 ;
     RECT  32.569 87.792 32.653 87.816 ;
     RECT  32.581 97.008 32.677 103.512 ;
     RECT  32.581 2.304 32.717 2.904 ;
     RECT  32.629 82.272 32.717 82.728 ;
     RECT  32.641 27.888 32.725 27.912 ;
     RECT  32.425 67.248 32.749 67.272 ;
     RECT  32.677 80.928 32.761 80.952 ;
     RECT  32.725 88.752 32.812 88.92 ;
     RECT  31.633 69.408 32.821 69.432 ;
     RECT  32.533 7.44 32.861 7.464 ;
     RECT  32.429 58.464 32.867 64.968 ;
     RECT  32.813 84 32.897 84.024 ;
     RECT  32.821 45.024 32.905 45.048 ;
     RECT  32.867 59.04 32.915 64.968 ;
     RECT  32.857 5.664 32.941 5.688 ;
     RECT  32.717 82.464 32.969 82.728 ;
     RECT  32.485 75.888 33.005 75.912 ;
     RECT  32.969 82.464 33.005 82.632 ;
     RECT  32.924 26.208 33.011 26.232 ;
     RECT  32.929 46.752 33.041 46.776 ;
     RECT  32.601 94.608 33.041 94.632 ;
     RECT  32.965 28.464 33.049 28.488 ;
     RECT  32.821 69.408 33.059 69.816 ;
     RECT  33.059 69.792 33.077 69.816 ;
     RECT  33.001 23.952 33.085 23.976 ;
     RECT  32.812 88.896 33.1 88.92 ;
     RECT  33.037 50.16 33.121 50.184 ;
     RECT  32.857 74.544 33.181 74.712 ;
     RECT  32.749 67.248 33.217 67.416 ;
     RECT  32.677 96.912 33.221 103.512 ;
     RECT  32.717 2.88 33.253 2.904 ;
     RECT  33.181 90.624 33.253 90.648 ;
     RECT  33.181 74.544 33.293 74.808 ;
     RECT  33.073 76.08 33.293 76.392 ;
     RECT  32.579 52.992 33.329 53.016 ;
     RECT  33.217 66.72 33.365 67.416 ;
     RECT  33.293 74.544 33.365 74.712 ;
     RECT  33.061 95.808 33.397 95.832 ;
     RECT  33.397 95.712 33.461 95.832 ;
     RECT  32.429 0.144 33.473 1.176 ;
     RECT  32.573 56.592 33.473 56.616 ;
     RECT  33.397 86.64 33.481 86.664 ;
     RECT  33.404 31.296 33.491 31.32 ;
     RECT  33.445 94.08 33.532 94.104 ;
     RECT  33.461 95.664 33.533 95.832 ;
     RECT  33.221 96.912 33.533 96.984 ;
     RECT  33.533 95.664 33.545 96.984 ;
     RECT  33.217 7.392 33.587 7.416 ;
     RECT  33.5 23.184 33.587 23.208 ;
     RECT  32.915 59.184 33.617 64.968 ;
     RECT  33.365 74.544 33.617 74.664 ;
     RECT  33.617 59.28 33.625 64.968 ;
     RECT  32.713 78.672 33.637 78.696 ;
     RECT  33.253 90.624 33.637 91.176 ;
     RECT  33.005 82.608 33.653 82.632 ;
     RECT  33.637 89.856 33.683 91.176 ;
     RECT  33.221 98.064 33.779 103.512 ;
     RECT  33.493 41.616 33.797 41.64 ;
     RECT  33.473 0.144 33.827 1.128 ;
     RECT  33.74 11.04 33.827 11.064 ;
     RECT  33.625 59.904 33.827 64.968 ;
     RECT  33.683 89.856 33.833 90.408 ;
     RECT  33.637 6.288 33.877 6.312 ;
     RECT  33.637 78.096 33.925 78.792 ;
     RECT  33.779 103.296 34.181 103.512 ;
     RECT  34.181 103.296 34.265 103.56 ;
     RECT  34.189 86.112 34.297 86.136 ;
     RECT  33.253 2.88 34.405 3.432 ;
     RECT  33.98 70.8 34.405 70.824 ;
     RECT  34.009 84.912 34.441 84.936 ;
     RECT  34.405 70.128 34.453 70.824 ;
     RECT  34.405 2.832 34.477 3.432 ;
     RECT  33.937 80.928 34.585 80.952 ;
     RECT  34.364 94.608 34.585 94.632 ;
     RECT  34.585 94.032 34.597 94.632 ;
     RECT  33.545 96.048 34.597 96.984 ;
     RECT  33.877 6.288 34.604 6.36 ;
     RECT  34.357 92.352 34.645 92.376 ;
     RECT  34.469 54.72 34.652 54.744 ;
     RECT  33.827 0.144 34.685 0.6 ;
     RECT  33.365 67.392 34.693 67.416 ;
     RECT  34.597 94.032 34.693 96.984 ;
     RECT  33.779 98.064 34.693 99.768 ;
     RECT  34.441 84.336 34.765 84.936 ;
     RECT  34.265 103.296 34.789 103.512 ;
     RECT  34.297 86.064 34.801 86.136 ;
     RECT  34.585 1.68 34.808 1.704 ;
     RECT  34.477 2.784 34.808 3.432 ;
     RECT  34.645 4.56 34.808 4.584 ;
     RECT  34.604 5.904 34.808 6.36 ;
     RECT  34.508 11.856 34.808 11.88 ;
     RECT  34.021 17.088 34.808 17.112 ;
     RECT  34.597 24 34.808 24.024 ;
     RECT  34.597 25.056 34.808 25.08 ;
     RECT  34.597 28.848 34.808 28.872 ;
     RECT  34.453 30.72 34.808 30.744 ;
     RECT  33.932 50.4 34.808 50.424 ;
     RECT  34.652 54.72 34.808 55.32 ;
     RECT  34.225 56.448 34.808 56.472 ;
     RECT  34.213 57.936 34.808 57.96 ;
     RECT  33.827 60.384 34.808 64.968 ;
     RECT  34.693 67.392 34.808 68.328 ;
     RECT  34.453 69.456 34.808 70.824 ;
     RECT  34.22 72.432 34.808 72.456 ;
     RECT  33.617 74.64 34.808 74.664 ;
     RECT  33.293 76.368 34.808 76.392 ;
     RECT  33.925 78.096 34.808 79.176 ;
     RECT  34.585 80.928 34.808 81.768 ;
     RECT  34.765 84.336 34.808 84.984 ;
     RECT  34.801 86.064 34.808 86.616 ;
     RECT  33.613 87.648 34.808 87.672 ;
     RECT  34.597 88.944 34.808 88.968 ;
     RECT  33.833 90.288 34.808 90.408 ;
     RECT  34.645 91.92 34.808 92.376 ;
     RECT  34.693 94.032 34.808 99.768 ;
     RECT  33.779 100.848 34.808 102.024 ;
     RECT  34.808 1.68 35.104 102.024 ;
     RECT  35.104 33.072 35.219 33.624 ;
     RECT  35.104 81.6 35.237 85.176 ;
     RECT  35.219 33.072 35.245 33.096 ;
     RECT  35.104 44.448 35.267 44.472 ;
     RECT  35.104 49.296 35.267 49.32 ;
     RECT  35.104 52.992 35.267 53.016 ;
     RECT  35.237 81.6 35.267 85.128 ;
     RECT  35.104 86.592 35.267 88.872 ;
     RECT  35.104 90.48 35.267 102.024 ;
     RECT  35.267 93.36 35.273 102.024 ;
     RECT  35.267 86.592 35.28 86.712 ;
     RECT  35.104 78.624 35.309 78.696 ;
     RECT  35.273 93.36 35.309 94.056 ;
     RECT  35.104 42.768 35.315 43.464 ;
     RECT  35.104 74.832 35.315 74.856 ;
     RECT  35.267 81.6 35.315 82.776 ;
     RECT  35.267 83.808 35.315 85.128 ;
     RECT  35.267 90.48 35.315 91.752 ;
     RECT  35.104 30.768 35.345 30.792 ;
     RECT  35.104 50.544 35.345 50.76 ;
     RECT  35.315 83.808 35.345 84.984 ;
     RECT  35.315 82.752 35.353 82.776 ;
     RECT  35.315 90.48 35.356 91.128 ;
     RECT  35.104 6.096 35.363 6.84 ;
     RECT  35.104 13.056 35.363 13.08 ;
     RECT  35.104 46.704 35.363 46.728 ;
     RECT  35.28 86.688 35.363 86.712 ;
     RECT  35.315 42.768 35.411 42.984 ;
     RECT  34.685 0.096 35.489 0.6 ;
     RECT  35.345 50.544 35.5 50.616 ;
     RECT  35.363 6.096 35.507 6.12 ;
     RECT  35.489 0.144 35.509 0.6 ;
     RECT  35.104 1.68 35.509 3.96 ;
     RECT  35.273 95.088 35.516 102.024 ;
     RECT  34.789 103.056 35.516 103.512 ;
     RECT  35.104 65.568 35.525 65.592 ;
     RECT  35.345 83.808 35.561 84.36 ;
     RECT  35.5 50.592 35.597 50.616 ;
     RECT  35.516 95.088 35.66 103.512 ;
     RECT  35.66 95.088 35.699 103.56 ;
     RECT  35.104 71.808 35.705 72.648 ;
     RECT  35.104 69.84 35.741 70.824 ;
     RECT  35.315 81.6 35.741 81.768 ;
     RECT  35.267 87.696 35.741 88.872 ;
     RECT  35.699 96.336 35.747 103.56 ;
     RECT  35.104 19.344 35.749 19.368 ;
     RECT  35.104 58.08 35.777 58.104 ;
     RECT  35.104 60.672 35.777 64.344 ;
     RECT  35.356 90.48 35.777 91.08 ;
     RECT  35.104 10.272 35.813 10.296 ;
     RECT  35.747 96.336 35.836 103.512 ;
     RECT  35.104 17.088 35.857 17.112 ;
     RECT  35.836 96.432 35.884 103.512 ;
     RECT  35.509 0.144 35.891 3.96 ;
     RECT  35.309 78.624 35.939 78.648 ;
     RECT  35.104 23.904 35.993 23.928 ;
     RECT  35.741 81.744 36.076 81.768 ;
     RECT  35.884 96.72 36.131 103.512 ;
     RECT  35.891 0.144 36.281 2.904 ;
     RECT  35.891 3.936 36.371 3.96 ;
     RECT  35.777 91.056 36.373 91.08 ;
     RECT  35.777 60.672 36.389 60.696 ;
     RECT  35.705 72.624 36.421 72.648 ;
     RECT  36.281 0.144 36.461 2.856 ;
     RECT  36.421 72.624 36.461 72.936 ;
     RECT  36.373 91.056 36.461 91.944 ;
     RECT  36.449 74.688 36.469 74.712 ;
     RECT  35.741 87.696 36.497 87.72 ;
     RECT  36.449 30.816 36.533 30.84 ;
     RECT  36.469 74.064 36.533 74.712 ;
     RECT  36.313 5.664 36.563 5.688 ;
     RECT  36.533 74.064 36.569 74.088 ;
     RECT  36.457 14.016 36.611 14.04 ;
     RECT  36.469 58.704 36.677 58.872 ;
     RECT  35.309 94.032 36.677 94.056 ;
     RECT  36.131 96.72 36.713 102.696 ;
     RECT  35.741 70.8 36.748 70.824 ;
     RECT  36.805 19.68 36.893 19.704 ;
     RECT  36.677 58.848 36.893 58.872 ;
     RECT  36.908 93.36 36.995 93.432 ;
     RECT  35.699 95.088 36.995 95.208 ;
     RECT  36.421 18.24 37.001 18.264 ;
     RECT  36.713 96.72 37.045 96.888 ;
     RECT  36.997 40.464 37.081 40.488 ;
     RECT  36.461 91.056 37.093 91.08 ;
     RECT  35.561 83.808 37.109 83.832 ;
     RECT  36.889 56.448 37.139 56.472 ;
     RECT  36.713 98.064 37.169 102.696 ;
     RECT  35.104 80.256 37.177 80.28 ;
     RECT  36.097 88.992 37.177 89.016 ;
     RECT  37.177 80.256 37.217 80.568 ;
     RECT  37.177 88.992 37.217 89.496 ;
     RECT  37.093 90.624 37.217 91.08 ;
     RECT  37.217 90.624 37.235 90.648 ;
     RECT  35.777 61.824 37.253 64.344 ;
     RECT  37.141 94.608 37.253 94.68 ;
     RECT  37.141 96.432 37.321 96.6 ;
     RECT  37.045 78.624 37.325 78.648 ;
     RECT  37.253 94.608 37.325 94.632 ;
     RECT  37.253 61.824 37.379 62.088 ;
     RECT  37.321 95.76 37.405 96.6 ;
     RECT  37.393 92.256 37.477 92.28 ;
     RECT  37.169 98.064 37.477 103.464 ;
     RECT  36.461 2.304 37.501 2.856 ;
     RECT  37.501 2.256 37.573 2.856 ;
     RECT  36.461 72.912 37.573 72.936 ;
     RECT  36.995 93.408 37.645 93.432 ;
     RECT  36.709 15.984 37.649 16.008 ;
     RECT  37.573 2.16 37.667 2.856 ;
     RECT  37.573 72.384 37.667 72.936 ;
     RECT  37.379 61.824 37.715 61.848 ;
     RECT  37.645 93.408 37.729 94.584 ;
     RECT  36.461 0.144 37.753 1.128 ;
     RECT  37.621 70.656 37.757 70.68 ;
     RECT  37.709 15.408 37.793 15.528 ;
     RECT  37.667 2.304 37.859 2.856 ;
     RECT  37.477 98.064 37.859 103.512 ;
     RECT  37.729 93.408 37.907 93.432 ;
     RECT  37.859 2.304 37.973 2.328 ;
     RECT  37.859 102.624 38.003 103.512 ;
     RECT  38.041 91.68 38.125 91.704 ;
     RECT  38.003 103.488 38.153 103.512 ;
     RECT  37.793 15.504 38.189 15.528 ;
     RECT  37.667 72.912 38.189 72.936 ;
     RECT  37.753 0.144 38.195 1.176 ;
     RECT  37.859 98.064 38.195 101.64 ;
     RECT  38.195 0.144 38.297 0.312 ;
     RECT  37.217 89.472 38.297 89.496 ;
     RECT  37.253 63.12 38.333 64.344 ;
     RECT  38.245 93.312 38.333 93.336 ;
     RECT  38.195 98.064 38.339 98.232 ;
     RECT  38.297 0.288 38.369 0.312 ;
     RECT  37.405 96.288 38.369 96.6 ;
     RECT  38.333 63.792 38.441 64.344 ;
     RECT  37.217 80.544 38.441 80.568 ;
     RECT  38.195 99.504 38.524 101.208 ;
     RECT  37.729 94.56 38.657 94.584 ;
     RECT  38.524 99.504 38.801 100.68 ;
     RECT  38.801 99.504 38.837 99.528 ;
     RECT  38.581 97.008 38.86 97.272 ;
     RECT  38.86 97.008 38.881 97.032 ;
     RECT  38.441 63.888 39.089 63.912 ;
     RECT  38.801 100.512 39.196 100.68 ;
     RECT  39.196 100.512 39.197 100.632 ;
     RECT  39.049 74.736 39.233 74.76 ;
     RECT  39.197 100.608 40.208 100.632 ;
     RECT  40.208 2.148 40.312 100.992 ;
     RECT  40.312 2.418 40.4 100.992 ;
     RECT  40.4 2.418 40.504 101.262 ;
     RECT  45.608 2.148 45.712 100.992 ;
     RECT  45.712 2.418 45.8 100.992 ;
     RECT  45.8 2.418 45.904 101.262 ;
    LAYER M5 ;
     RECT  13.776 0.016 38.184 0.563 ;
     RECT  13.824 0.563 38.184 1.187 ;
     RECT  13.824 1.187 37.848 2.137 ;
     RECT  2.4 2.137 2.52 2.407 ;
     RECT  7.8 2.137 7.92 2.407 ;
     RECT  40.2 2.137 40.32 2.407 ;
     RECT  45.6 2.137 45.72 2.407 ;
     RECT  13.2 2.137 37.848 2.867 ;
     RECT  13.2 2.867 37.8 3.443 ;
     RECT  14.544 3.443 37.8 3.587 ;
     RECT  15.072 3.587 37.8 4.547 ;
     RECT  15.072 4.547 16.344 6.035 ;
     RECT  15.312 6.035 16.344 7.427 ;
     RECT  17.376 4.547 37.8 7.427 ;
     RECT  13.2 3.443 13.512 7.861 ;
     RECT  17.472 7.427 37.8 8.531 ;
     RECT  15.888 7.427 16.344 8.965 ;
     RECT  17.76 8.531 37.8 9.683 ;
     RECT  17.76 9.683 21.528 11.987 ;
     RECT  17.856 11.987 21.528 13.139 ;
     RECT  22.56 9.683 37.8 15.539 ;
     RECT  22.56 15.539 37.128 27.971 ;
     RECT  17.856 13.139 21.144 35.363 ;
     RECT  15.648 8.965 16.344 37.667 ;
     RECT  18 35.363 21.144 38.819 ;
     RECT  13.2 7.861 13.608 39.493 ;
     RECT  7.8 2.407 8.112 39.637 ;
     RECT  15.648 37.667 15.96 39.669 ;
     RECT  15.648 39.669 16.584 39.757 ;
     RECT  0.048 39.589 0.072 39.851 ;
     RECT  18 38.819 20.808 39.971 ;
     RECT  13.2 39.493 13.656 40.405 ;
     RECT  2.4 2.407 2.712 40.741 ;
     RECT  9.696 40.645 9.72 40.789 ;
     RECT  2.4 40.741 2.808 40.883 ;
     RECT  0.192 40.837 0.216 40.885 ;
     RECT  0.192 40.885 0.312 40.939 ;
     RECT  0.288 40.939 0.312 40.979 ;
     RECT  9.6 40.789 9.72 40.979 ;
     RECT  20.112 39.971 20.808 41.075 ;
     RECT  18 39.971 18.912 41.077 ;
     RECT  20.784 41.075 20.808 41.651 ;
     RECT  17.184 41.077 18.912 41.845 ;
     RECT  17.184 41.845 19.08 41.899 ;
     RECT  18 41.899 19.08 41.939 ;
     RECT  12.624 40.405 13.656 43.765 ;
     RECT  16.944 43.333 16.968 43.861 ;
     RECT  18 41.939 18.912 43.861 ;
     RECT  15.648 39.757 15.96 43.955 ;
     RECT  16.944 43.861 18.912 44.965 ;
     RECT  22.56 27.971 29.712 45.059 ;
     RECT  30.72 27.971 37.128 45.059 ;
     RECT  20.688 45.541 20.712 45.557 ;
     RECT  20.64 45.557 20.712 45.683 ;
     RECT  0.288 45.973 0.312 46.069 ;
     RECT  0.192 46.069 0.408 46.153 ;
     RECT  0.384 46.153 0.408 46.163 ;
     RECT  9.6 40.979 9.624 46.309 ;
     RECT  16.944 44.965 19.32 46.693 ;
     RECT  20.688 45.683 20.712 46.693 ;
     RECT  15.648 43.955 15.672 46.787 ;
     RECT  31.152 45.059 37.128 47.363 ;
     RECT  0.384 47.749 0.408 47.891 ;
     RECT  23.616 45.059 29.712 47.939 ;
     RECT  5.136 48.997 5.16 49.139 ;
     RECT  15.024 49.093 15.048 49.283 ;
     RECT  22.56 45.059 22.584 49.283 ;
     RECT  0.288 49.299 0.312 49.333 ;
     RECT  0.192 49.333 0.312 49.387 ;
     RECT  0.192 49.387 0.216 49.571 ;
     RECT  23.616 47.939 26.184 50.149 ;
     RECT  7.44 39.637 8.112 50.341 ;
     RECT  9.6 46.309 10.056 50.341 ;
     RECT  7.44 50.341 10.056 50.531 ;
     RECT  5.136 50.389 5.16 50.627 ;
     RECT  16.944 46.693 20.712 51.541 ;
     RECT  0.288 50.581 0.312 51.603 ;
     RECT  0.192 51.603 0.312 51.637 ;
     RECT  0.192 51.637 0.36 51.779 ;
     RECT  0.192 51.779 0.264 51.875 ;
     RECT  16.944 51.541 20.808 51.893 ;
     RECT  23.424 50.149 26.184 51.893 ;
     RECT  4.512 51.877 4.536 51.961 ;
     RECT  16.944 51.893 20.952 52.075 ;
     RECT  2.4 40.883 2.712 52.085 ;
     RECT  2.4 52.085 2.808 52.211 ;
     RECT  5.136 51.973 5.256 52.259 ;
     RECT  0.192 51.875 0.216 52.267 ;
     RECT  22.8 51.893 26.184 52.267 ;
     RECT  12.624 43.765 13.704 52.309 ;
     RECT  5.136 52.259 5.16 52.395 ;
     RECT  12.624 52.309 13.752 52.395 ;
     RECT  7.44 50.531 8.112 52.597 ;
     RECT  23.424 52.267 26.184 52.645 ;
     RECT  23.424 52.645 26.328 52.655 ;
     RECT  27.312 47.939 29.712 52.655 ;
     RECT  7.392 52.597 8.112 52.691 ;
     RECT  31.2 47.363 37.128 53.493 ;
     RECT  31.104 53.493 37.128 53.581 ;
     RECT  0.24 53.989 0.264 54.131 ;
     RECT  11.52 40.357 11.544 55.861 ;
     RECT  0.288 55.141 0.312 55.925 ;
     RECT  11.376 55.861 11.544 55.955 ;
     RECT  0.24 55.925 0.312 56.291 ;
     RECT  2.4 52.211 2.712 56.309 ;
     RECT  23.424 52.655 29.712 56.341 ;
     RECT  23.376 56.341 29.712 56.389 ;
     RECT  23.376 56.389 30.024 56.427 ;
     RECT  31.2 53.581 37.128 56.483 ;
     RECT  2.4 56.309 2.904 56.485 ;
     RECT  0.24 56.291 0.264 56.501 ;
     RECT  2.016 56.485 2.904 56.531 ;
     RECT  23.424 56.427 30.024 56.533 ;
     RECT  2.016 56.531 2.808 56.569 ;
     RECT  23.424 56.533 30.168 57.013 ;
     RECT  31.2 56.483 36.84 57.013 ;
     RECT  0.096 56.501 0.264 57.397 ;
     RECT  2.4 56.569 2.808 57.539 ;
     RECT  0.096 57.397 0.312 58.101 ;
     RECT  22.08 58.037 22.104 58.125 ;
     RECT  0.048 58.101 0.312 58.163 ;
     RECT  6.384 58.213 6.408 58.451 ;
     RECT  22.224 58.607 22.248 58.691 ;
     RECT  0.048 58.163 0.264 58.731 ;
     RECT  7.44 52.691 8.112 59.125 ;
     RECT  9.6 50.531 10.056 59.125 ;
     RECT  7.44 59.125 10.056 59.209 ;
     RECT  23.424 57.013 36.84 59.253 ;
     RECT  23.376 59.253 36.84 59.795 ;
     RECT  0.048 58.731 0.216 60.597 ;
     RECT  16.944 52.075 20.712 60.911 ;
     RECT  16.944 60.911 21.096 60.995 ;
     RECT  0.048 60.597 0.264 61.365 ;
     RECT  0.048 61.365 0.36 61.429 ;
     RECT  16.944 60.995 20.712 61.525 ;
     RECT  0.048 61.429 0.456 61.571 ;
     RECT  12.624 52.395 13.656 61.621 ;
     RECT  23.424 59.795 36.84 61.813 ;
     RECT  22.224 61.813 22.248 61.897 ;
     RECT  7.44 59.209 8.112 62.149 ;
     RECT  16.56 61.525 20.712 62.149 ;
     RECT  9.6 59.209 10.056 62.197 ;
     RECT  11.52 55.955 11.544 62.197 ;
     RECT  12.624 61.621 13.8 62.197 ;
     RECT  14.928 62.149 14.952 62.197 ;
     RECT  9.6 62.197 11.544 62.483 ;
     RECT  14.832 62.197 14.952 62.483 ;
     RECT  6.864 62.149 8.112 62.531 ;
     RECT  14.928 62.483 14.952 62.531 ;
     RECT  16.56 62.149 21.24 62.531 ;
     RECT  12.624 62.197 13.848 62.763 ;
     RECT  0.048 61.571 0.312 63.059 ;
     RECT  0.048 63.059 0.168 63.211 ;
     RECT  0.144 63.211 0.168 63.251 ;
     RECT  16.56 62.531 20.712 63.875 ;
     RECT  9.6 62.483 10.056 64.559 ;
     RECT  11.52 62.483 11.544 64.565 ;
     RECT  9.6 64.559 10.248 64.643 ;
     RECT  12.624 62.763 13.656 64.933 ;
     RECT  11.28 64.565 11.544 64.939 ;
     RECT  12.528 64.933 13.656 65.017 ;
     RECT  16.944 63.875 20.712 65.317 ;
     RECT  12.624 65.017 13.656 65.333 ;
     RECT  12.624 65.333 14.328 65.365 ;
     RECT  12.624 65.365 14.808 65.421 ;
     RECT  14.784 65.421 14.808 65.451 ;
     RECT  7.44 62.531 8.112 65.461 ;
     RECT  9.6 64.643 9.624 65.461 ;
     RECT  7.44 65.461 9.624 65.555 ;
     RECT  16.224 65.317 20.712 65.707 ;
     RECT  12.624 65.421 13.704 66.253 ;
     RECT  11.52 64.939 11.544 66.579 ;
     RECT  12.624 66.253 13.656 66.579 ;
     RECT  10.944 66.579 13.656 66.667 ;
     RECT  10.944 66.667 11.544 66.901 ;
     RECT  9.6 65.555 9.624 66.933 ;
     RECT  10.896 66.901 11.544 66.987 ;
     RECT  9.264 66.933 9.624 67.021 ;
     RECT  22.416 65.893 22.44 67.283 ;
     RECT  15.552 67.189 15.576 68.675 ;
     RECT  7.44 65.555 8.112 68.853 ;
     RECT  9.6 67.021 9.624 68.853 ;
     RECT  7.44 68.853 9.624 68.941 ;
     RECT  16.944 65.707 20.712 69.365 ;
     RECT  16.944 69.365 21.144 69.731 ;
     RECT  15.792 69.843 15.816 69.931 ;
     RECT  7.44 68.941 8.112 70.611 ;
     RECT  7.152 70.611 8.112 70.699 ;
     RECT  16.944 69.731 20.712 71.157 ;
     RECT  16.896 71.157 20.712 71.245 ;
     RECT  23.424 61.813 37.704 71.461 ;
     RECT  6.24 71.711 6.264 71.795 ;
     RECT  15.888 71.797 15.912 71.891 ;
     RECT  7.44 70.699 8.112 72.117 ;
     RECT  7.152 72.117 8.112 72.205 ;
     RECT  11.52 66.987 11.544 72.565 ;
     RECT  12.624 66.667 13.656 72.565 ;
     RECT  22.752 71.461 37.704 72.565 ;
     RECT  22.176 72.565 37.704 72.995 ;
     RECT  22.56 72.995 37.704 73.579 ;
     RECT  10.944 72.565 13.656 73.763 ;
     RECT  10.944 73.763 11.544 73.811 ;
     RECT  7.44 72.205 8.112 74.229 ;
     RECT  7.056 74.229 8.112 74.339 ;
     RECT  15.072 74.581 15.096 74.667 ;
     RECT  23.424 73.579 37.704 74.965 ;
     RECT  11.52 73.811 11.544 75.253 ;
     RECT  11.232 75.253 11.544 75.819 ;
     RECT  23.376 74.965 37.704 75.875 ;
     RECT  7.44 74.339 8.112 76.051 ;
     RECT  9.6 68.941 9.624 76.051 ;
     RECT  7.44 76.051 9.624 76.139 ;
     RECT  16.944 71.245 20.712 76.453 ;
     RECT  16.944 76.453 21.672 76.537 ;
     RECT  21.84 76.597 21.864 76.739 ;
     RECT  12.624 73.763 13.656 77.221 ;
     RECT  14.976 76.008 15 77.237 ;
     RECT  12.528 77.221 13.656 77.305 ;
     RECT  7.44 76.139 8.112 77.395 ;
     RECT  6.96 77.395 8.112 77.429 ;
     RECT  6.96 77.429 8.232 77.483 ;
     RECT  14.688 77.237 15 77.493 ;
     RECT  14.688 77.493 15.432 77.547 ;
     RECT  11.52 75.819 11.544 77.749 ;
     RECT  11.088 77.749 11.544 77.843 ;
     RECT  9.6 76.139 9.624 77.941 ;
     RECT  7.44 77.483 8.232 78.005 ;
     RECT  9.312 77.941 9.624 78.005 ;
     RECT  7.44 78.005 9.624 78.035 ;
     RECT  14.88 77.547 15.432 78.083 ;
     RECT  9.12 78.035 9.624 78.093 ;
     RECT  7.44 78.035 8.112 79.029 ;
     RECT  7.44 79.029 8.424 79.139 ;
     RECT  22.08 79.045 22.104 79.147 ;
     RECT  14.88 78.083 14.904 79.211 ;
     RECT  9.6 78.093 9.624 79.699 ;
     RECT  9.6 79.699 10.344 79.787 ;
     RECT  12.624 77.305 13.656 79.859 ;
     RECT  16.944 76.537 20.712 80.005 ;
     RECT  16.944 80.005 21.24 80.107 ;
     RECT  9.6 79.787 9.624 80.275 ;
     RECT  11.52 77.843 11.544 80.293 ;
     RECT  9.312 80.275 9.624 80.363 ;
     RECT  11.376 80.293 11.544 80.377 ;
     RECT  11.52 80.377 11.544 80.821 ;
     RECT  12.624 79.859 13.512 80.821 ;
     RECT  14.928 80.851 14.952 80.939 ;
     RECT  16.944 80.107 20.76 80.939 ;
     RECT  11.52 80.821 13.512 81.003 ;
     RECT  22.176 81.205 22.2 81.299 ;
     RECT  7.44 79.139 8.112 81.445 ;
     RECT  16.944 80.939 20.712 82.003 ;
     RECT  23.424 75.875 37.704 82.079 ;
     RECT  16.416 82.003 20.712 82.091 ;
     RECT  12.624 81.003 13.512 82.101 ;
     RECT  22.848 82.079 37.704 82.163 ;
     RECT  7.296 81.445 8.112 82.293 ;
     RECT  9.6 80.363 9.624 82.293 ;
     RECT  7.296 82.293 9.624 82.403 ;
     RECT  7.296 82.403 8.112 82.404 ;
     RECT  12.624 82.101 14.328 82.603 ;
     RECT  11.52 81.003 11.544 82.655 ;
     RECT  12.624 82.603 13.896 82.655 ;
     RECT  16.944 82.091 20.712 82.691 ;
     RECT  11.52 82.655 13.896 82.979 ;
     RECT  18.6 82.691 20.712 83.231 ;
     RECT  18.6 83.231 21.192 83.267 ;
     RECT  12.624 82.979 13.896 83.307 ;
     RECT  20.4 83.267 21.192 83.315 ;
     RECT  23.424 82.163 37.704 83.843 ;
     RECT  9.36 82.403 9.624 84.181 ;
     RECT  11.52 82.979 11.544 84.469 ;
     RECT  18.6 83.267 19.272 84.469 ;
     RECT  20.4 83.315 20.712 84.469 ;
     RECT  18.6 84.469 20.712 84.563 ;
     RECT  16.944 82.691 17.256 84.789 ;
     RECT  18.6 84.563 19.272 84.789 ;
     RECT  7.44 82.404 8.112 84.853 ;
     RECT  16.128 84.789 19.272 84.877 ;
     RECT  7.392 84.853 8.112 84.937 ;
     RECT  14.784 85.093 14.808 85.177 ;
     RECT  10.848 84.469 11.544 85.301 ;
     RECT  12.624 83.307 13.512 85.301 ;
     RECT  22.176 85.237 22.2 85.331 ;
     RECT  16.656 84.877 17.256 85.355 ;
     RECT  10.848 85.301 13.512 85.365 ;
     RECT  9.12 84.181 9.624 85.379 ;
     RECT  23.424 83.843 30.36 85.429 ;
     RECT  23.424 85.429 30.648 85.513 ;
     RECT  10.8 85.365 13.512 85.523 ;
     RECT  20.4 84.563 20.712 85.523 ;
     RECT  23.424 85.513 30.36 85.523 ;
     RECT  23.424 85.523 27.72 86.099 ;
     RECT  9.6 85.379 9.624 86.197 ;
     RECT  18.6 84.877 19.272 86.325 ;
     RECT  18.384 86.325 19.272 86.413 ;
     RECT  16.848 85.355 17.256 86.547 ;
     RECT  20.688 85.523 20.712 86.629 ;
     RECT  9.6 86.197 10.248 86.635 ;
     RECT  16.128 86.547 17.256 86.635 ;
     RECT  11.52 85.523 13.512 86.819 ;
     RECT  11.52 86.819 11.544 87.839 ;
     RECT  7.44 84.937 8.112 87.861 ;
     RECT  9.6 86.635 9.624 87.861 ;
     RECT  11.424 87.839 11.544 87.923 ;
     RECT  7.44 87.861 9.624 87.949 ;
     RECT  20.352 86.629 20.712 87.979 ;
     RECT  22.224 87.925 22.248 88.019 ;
     RECT  12.624 86.819 13.512 88.403 ;
     RECT  16.944 86.635 17.256 88.403 ;
     RECT  15.936 88.367 15.96 88.451 ;
     RECT  27.312 86.099 27.72 88.499 ;
     RECT  31.824 83.843 37.704 88.931 ;
     RECT  31.824 88.931 32.088 89.771 ;
     RECT  7.44 87.949 8.112 89.845 ;
     RECT  7.008 89.845 8.112 89.951 ;
     RECT  9.6 87.949 9.624 89.951 ;
     RECT  7.008 89.951 9.624 90.035 ;
     RECT  11.52 87.923 11.544 90.083 ;
     RECT  7.008 90.035 8.112 90.091 ;
     RECT  5.664 90.037 5.688 90.131 ;
     RECT  13.2 88.403 13.512 90.373 ;
     RECT  23.424 86.099 26.328 90.517 ;
     RECT  29.184 85.523 30.36 90.517 ;
     RECT  17.232 88.403 17.256 90.565 ;
     RECT  12.288 90.373 13.512 90.603 ;
     RECT  15.984 90.517 16.008 90.603 ;
     RECT  22.56 90.517 26.52 90.603 ;
     RECT  28.896 90.517 30.36 90.603 ;
     RECT  9.6 90.035 9.624 90.613 ;
     RECT  29.184 90.603 30.36 90.613 ;
     RECT  9.6 90.613 10.44 90.707 ;
     RECT  29.184 90.613 30.504 90.851 ;
     RECT  17.232 90.565 17.496 90.901 ;
     RECT  18.6 86.413 19.272 90.901 ;
     RECT  20.688 87.979 20.712 91.093 ;
     RECT  31.824 89.771 31.848 91.125 ;
     RECT  20.688 91.093 21.24 91.141 ;
     RECT  20.688 91.141 21.672 91.189 ;
     RECT  31.2 91.125 31.848 91.213 ;
     RECT  20.496 91.189 21.672 91.243 ;
     RECT  20.496 91.243 20.712 91.283 ;
     RECT  12.528 90.603 13.512 91.331 ;
     RECT  13.2 91.331 13.512 91.509 ;
     RECT  15.36 90.901 15.864 91.563 ;
     RECT  31.344 91.213 31.848 91.573 ;
     RECT  33.072 88.931 37.704 91.669 ;
     RECT  17.232 90.901 19.272 91.701 ;
     RECT  23.184 90.603 26.328 91.701 ;
     RECT  33.072 91.669 38.088 91.755 ;
     RECT  16.992 91.701 19.272 91.789 ;
     RECT  13.2 91.509 14.232 91.811 ;
     RECT  17.232 91.789 19.272 91.811 ;
     RECT  33.072 91.755 37.704 91.955 ;
     RECT  27.696 88.499 27.72 92.021 ;
     RECT  22.656 91.701 26.328 92.075 ;
     RECT  7.44 90.091 8.112 92.085 ;
     RECT  27.456 92.021 27.72 92.109 ;
     RECT  7.44 92.085 8.232 92.195 ;
     RECT  31.344 91.573 31.944 92.277 ;
     RECT  33.072 91.955 35.592 92.277 ;
     RECT  29.184 90.851 30.216 92.341 ;
     RECT  31.344 92.277 35.592 92.341 ;
     RECT  29.184 92.341 35.592 92.387 ;
     RECT  20.688 91.283 20.712 92.773 ;
     RECT  17.472 91.811 19.272 92.821 ;
     RECT  22.896 92.075 26.328 92.821 ;
     RECT  27.648 92.109 27.72 92.821 ;
     RECT  29.184 92.387 33.576 92.821 ;
     RECT  20.688 92.773 21.24 92.857 ;
     RECT  13.2 91.811 13.896 92.869 ;
     RECT  22.896 92.821 26.568 92.907 ;
     RECT  27.648 92.821 33.576 92.907 ;
     RECT  28.752 92.907 33.576 92.971 ;
     RECT  22.896 92.907 26.328 93.061 ;
     RECT  27.648 92.907 27.672 93.163 ;
     RECT  37.2 91.955 37.704 93.267 ;
     RECT  37.2 93.267 38.28 93.301 ;
     RECT  36.96 93.301 38.28 93.395 ;
     RECT  7.44 92.195 8.112 93.429 ;
     RECT  5.664 93.397 5.688 93.483 ;
     RECT  21.888 93.061 26.328 93.483 ;
     RECT  37.104 93.395 38.28 93.483 ;
     RECT  23.088 93.483 26.328 93.539 ;
     RECT  13.2 92.869 14.28 93.829 ;
     RECT  20.688 92.857 20.712 93.843 ;
     RECT  11.52 93.843 11.544 93.931 ;
     RECT  20.688 93.843 21.816 93.931 ;
     RECT  13.104 93.829 14.28 94.019 ;
     RECT  30.864 92.971 33.576 94.069 ;
     RECT  27.6 93.349 27.624 94.117 ;
     RECT  15.36 91.563 15.384 94.127 ;
     RECT  15.36 94.127 15.624 94.133 ;
     RECT  16.704 92.821 19.272 94.175 ;
     RECT  6.864 93.429 8.112 94.197 ;
     RECT  16.704 94.175 19.416 94.259 ;
     RECT  15.312 94.133 15.624 94.307 ;
     RECT  6.864 94.197 8.52 94.355 ;
     RECT  29.04 92.971 29.832 94.451 ;
     RECT  29.088 94.451 29.832 94.453 ;
     RECT  30.816 94.069 33.576 94.453 ;
     RECT  15.36 94.307 15.624 94.501 ;
     RECT  16.704 94.259 19.368 94.501 ;
     RECT  13.104 94.019 14.136 94.547 ;
     RECT  29.088 94.453 33.576 94.595 ;
     RECT  37.2 93.483 38.28 94.595 ;
     RECT  29.184 94.595 33.576 94.597 ;
     RECT  34.608 92.387 35.592 94.597 ;
     RECT  20.688 93.931 20.712 94.643 ;
     RECT  23.088 93.539 26.136 94.645 ;
     RECT  15.36 94.501 19.368 94.787 ;
     RECT  29.184 94.597 35.592 94.979 ;
     RECT  6.864 94.355 8.112 94.981 ;
     RECT  21.744 93.931 21.816 94.981 ;
     RECT  23.088 94.645 26.232 94.981 ;
     RECT  27.408 94.117 27.624 95.077 ;
     RECT  29.232 94.979 35.592 95.077 ;
     RECT  21.744 94.981 26.232 95.087 ;
     RECT  27.408 95.077 27.912 95.087 ;
     RECT  9.6 90.707 9.624 95.125 ;
     RECT  6.48 94.981 8.112 95.147 ;
     RECT  21.744 95.087 27.912 95.147 ;
     RECT  22.128 95.147 27.912 95.171 ;
     RECT  37.2 94.595 37.368 95.173 ;
     RECT  29.232 95.077 35.976 95.174 ;
     RECT  9.6 95.125 9.768 95.211 ;
     RECT  22.128 95.171 26.232 95.211 ;
     RECT  29.232 95.174 35.928 95.211 ;
     RECT  7.44 95.147 8.112 95.219 ;
     RECT  27.312 95.171 27.912 95.411 ;
     RECT  11.712 95.541 11.736 95.651 ;
     RECT  20.592 95.125 20.616 95.701 ;
     RECT  15.36 94.787 15.384 95.749 ;
     RECT  16.704 94.787 19.368 95.749 ;
     RECT  27.408 95.411 27.912 95.749 ;
     RECT  29.232 95.211 31.848 95.787 ;
     RECT  27.408 95.749 28.056 95.797 ;
     RECT  33.072 95.211 35.928 95.843 ;
     RECT  29.28 95.787 31.848 95.915 ;
     RECT  20.592 95.701 20.76 95.955 ;
     RECT  13.104 94.547 13.512 95.989 ;
     RECT  15.36 95.749 19.368 96.019 ;
     RECT  20.592 95.955 21.048 96.019 ;
     RECT  36.96 95.173 37.368 96.277 ;
     RECT  13.104 95.989 14.232 96.325 ;
     RECT  9.6 95.211 9.624 96.371 ;
     RECT  7.8 95.219 8.112 96.373 ;
     RECT  15.36 96.019 21.048 96.431 ;
     RECT  22.176 95.211 26.232 96.431 ;
     RECT  7.8 96.373 8.376 96.555 ;
     RECT  6.24 96.479 6.264 96.563 ;
     RECT  13.104 96.325 14.376 96.565 ;
     RECT  15.36 96.431 26.232 96.565 ;
     RECT  36.96 96.277 38.232 96.619 ;
     RECT  33.408 95.843 35.928 96.805 ;
     RECT  36.96 96.619 37.032 96.805 ;
     RECT  29.4 95.915 31.848 96.885 ;
     RECT  33.408 96.805 37.032 96.885 ;
     RECT  38.208 96.619 38.232 96.885 ;
     RECT  27.408 95.797 28.2 96.901 ;
     RECT  29.4 96.885 37.032 96.901 ;
     RECT  38.208 96.885 38.808 96.997 ;
     RECT  27.408 96.901 37.032 97.067 ;
     RECT  38.208 96.997 38.856 97.081 ;
     RECT  38.208 97.081 38.808 97.283 ;
     RECT  10.608 97.205 10.632 97.293 ;
     RECT  27.408 97.067 36.696 97.439 ;
     RECT  13.104 96.565 26.232 97.477 ;
     RECT  27.36 97.439 36.696 97.477 ;
     RECT  7.8 96.555 8.112 97.717 ;
     RECT  7.8 97.717 8.904 97.811 ;
     RECT  13.104 97.477 36.696 97.957 ;
     RECT  38.208 97.283 38.328 98.015 ;
     RECT  12.336 97.957 36.696 98.037 ;
     RECT  12.048 98.037 36.696 98.041 ;
     RECT  13.104 98.041 36.696 98.053 ;
     RECT  37.92 98.015 38.328 98.053 ;
     RECT  12.048 98.041 12.072 98.125 ;
     RECT  13.104 98.053 38.328 98.283 ;
     RECT  7.8 97.811 8.112 98.613 ;
     RECT  7.392 98.613 8.112 98.701 ;
     RECT  13.104 98.283 38.232 99.203 ;
     RECT  10.848 99.541 10.872 99.627 ;
     RECT  11.952 99.551 11.976 99.635 ;
     RECT  13.2 99.203 38.232 100.463 ;
     RECT  13.104 100.463 38.808 100.547 ;
     RECT  13.2 100.547 38.808 100.645 ;
     RECT  13.2 100.645 39.144 100.907 ;
     RECT  2.4 57.539 2.712 101.003 ;
     RECT  7.8 98.701 8.112 101.003 ;
     RECT  13.2 100.907 38.472 101.003 ;
     RECT  40.2 2.407 40.512 101.003 ;
     RECT  45.6 2.407 45.912 101.003 ;
     RECT  13.392 101.003 38.472 101.227 ;
     RECT  2.592 101.003 2.712 101.273 ;
     RECT  7.992 101.003 8.112 101.273 ;
     RECT  13.392 101.227 38.232 101.273 ;
     RECT  40.392 101.003 40.512 101.273 ;
     RECT  45.792 101.003 45.912 101.273 ;
     RECT  13.824 101.273 38.232 103.632 ;
    LAYER M6 ;
     RECT  0.037 58.112 0.133 58.144 ;
     RECT  0.085 60.608 0.133 60.64 ;
     RECT  0.037 63.168 0.133 63.2 ;
     RECT  0.133 62.976 0.179 63.2 ;
     RECT  0.037 39.808 0.181 39.84 ;
     RECT  0.133 58.112 0.181 58.72 ;
     RECT  0.085 56.512 0.229 56.544 ;
     RECT  0.181 57.92 0.275 58.72 ;
     RECT  0.133 60.608 0.275 61.408 ;
     RECT  0.181 39.808 0.323 40.928 ;
     RECT  0.181 49.344 0.323 49.376 ;
     RECT  0.179 62.976 0.323 63.008 ;
     RECT  0.181 51.648 0.371 52.256 ;
     RECT  0.275 61.056 0.371 61.408 ;
     RECT  0.181 46.08 0.419 46.112 ;
     RECT  0.323 39.808 2.16 39.84 ;
     RECT  0.371 52.224 2.16 52.256 ;
     RECT  0.229 55.936 2.16 56.544 ;
     RECT  0.275 57.92 2.16 58.144 ;
     RECT  0.371 61.056 2.16 61.088 ;
     RECT  2.16 51.129 5.125 52.256 ;
     RECT  2.16 88.929 5.653 89.601 ;
     RECT  2.16 94.329 5.653 95.001 ;
     RECT  2.16 72.729 6.229 73.401 ;
     RECT  5.653 93.44 6.453 95.001 ;
     RECT  6.453 93.44 6.526 95.136 ;
     RECT  6.526 93.44 6.899 95.001 ;
     RECT  2.16 78.129 6.949 78.801 ;
     RECT  6.229 71.744 7.045 73.401 ;
     RECT  7.045 71.744 7.141 74.272 ;
     RECT  7.141 70.656 7.211 74.272 ;
     RECT  2.16 83.529 7.285 84.201 ;
     RECT  5.125 51.129 7.381 52.384 ;
     RECT  7.285 82.304 7.381 84.201 ;
     RECT  2.16 99.729 7.381 100.401 ;
     RECT  2.16 67.329 7.669 68.001 ;
     RECT  5.653 88.929 7.669 90.08 ;
     RECT  6.229 96.512 7.989 96.544 ;
     RECT  7.381 98.624 7.989 100.401 ;
     RECT  7.989 96.512 8.043 100.401 ;
     RECT  7.669 88.929 8.107 90.464 ;
     RECT  8.053 92.096 8.243 92.128 ;
     RECT  8.043 96.512 8.341 97.76 ;
     RECT  8.341 96.384 8.387 97.76 ;
     RECT  6.949 77.44 8.389 78.801 ;
     RECT  6.899 94.329 8.485 95.001 ;
     RECT  8.389 77.44 8.555 79.072 ;
     RECT  8.107 88.929 8.725 90.016 ;
     RECT  8.387 97.728 8.915 97.76 ;
     RECT  8.501 76.096 9.011 76.128 ;
     RECT  7.669 65.664 9.013 65.696 ;
     RECT  7.669 67.329 9.013 68.384 ;
     RECT  2.16 55.936 9.061 58.144 ;
     RECT  9.013 65.472 9.077 65.696 ;
     RECT  9.013 67.329 9.077 68.896 ;
     RECT  9.077 65.472 9.131 68.896 ;
     RECT  7.381 82.304 9.155 84.896 ;
     RECT  8.555 77.952 9.301 79.072 ;
     RECT  9.301 77.952 9.387 80.352 ;
     RECT  9.155 82.304 9.387 84.201 ;
     RECT  9.387 83.264 9.395 84.201 ;
     RECT  8.485 94.208 9.71 95.001 ;
     RECT  8.387 96.384 9.71 96.416 ;
     RECT  9.71 94.208 9.717 96.416 ;
     RECT  9.717 94.208 9.771 97.248 ;
     RECT  9.771 94.208 9.779 95.2 ;
     RECT  8.725 87.872 10.213 90.016 ;
     RECT  9.387 78.016 10.355 79.776 ;
     RECT  10.213 86.208 10.357 90.016 ;
     RECT  10.357 86.208 10.451 90.656 ;
     RECT  10.451 86.208 10.539 89.601 ;
     RECT  9.771 97.216 10.643 97.248 ;
     RECT  9.395 83.529 10.789 84.201 ;
     RECT  10.539 86.208 10.789 86.24 ;
     RECT  8.043 99.729 10.837 100.401 ;
     RECT  10.837 99.584 10.869 100.401 ;
     RECT  9.131 66.944 10.933 68.001 ;
     RECT  7.211 72.729 10.933 73.401 ;
     RECT  10.355 78.016 11.077 78.801 ;
     RECT  11.077 77.76 11.179 78.801 ;
     RECT  11.125 75.776 11.221 75.808 ;
     RECT  11.221 75.264 11.267 75.808 ;
     RECT  10.213 64.576 11.269 64.608 ;
     RECT  9.061 55.936 11.365 59.168 ;
     RECT  10.539 87.872 11.459 89.601 ;
     RECT  9.779 94.208 11.49 95.001 ;
     RECT  11.49 93.888 11.509 95.001 ;
     RECT  11.509 93.888 11.563 96.864 ;
     RECT  11.269 64.576 11.701 64.928 ;
     RECT  10.933 66.624 11.701 68.001 ;
     RECT  10.933 72.729 11.701 73.568 ;
     RECT  11.563 94.208 11.747 96.864 ;
     RECT  10.789 83.529 11.829 86.24 ;
     RECT  11.365 80.32 11.883 80.352 ;
     RECT  11.747 96.832 12.021 96.864 ;
     RECT  12.021 96.832 12.094 98.08 ;
     RECT  11.701 64.576 12.149 68.001 ;
     RECT  11.829 82.88 12.179 86.24 ;
     RECT  12.149 64.384 12.203 68.001 ;
     RECT  11.459 88.929 12.277 89.601 ;
     RECT  10.869 99.584 12.341 100.512 ;
     RECT  12.277 88.929 12.346 91.232 ;
     RECT  12.179 82.88 12.373 84.201 ;
     RECT  12.094 96.832 12.395 98.016 ;
     RECT  12.373 82.688 12.405 84.201 ;
     RECT  12.398 80.96 12.467 80.992 ;
     RECT  11.179 78.016 12.517 78.801 ;
     RECT  12.346 91.2 12.563 91.232 ;
     RECT  2.16 61.056 12.642 62.601 ;
     RECT  11.701 72.576 12.757 73.568 ;
     RECT  11.267 75.264 12.757 75.296 ;
     RECT  12.757 75.072 12.803 75.296 ;
     RECT  12.757 70.08 12.843 70.112 ;
     RECT  12.757 71.552 12.843 73.568 ;
     RECT  12.803 75.072 12.843 75.104 ;
     RECT  12.203 64.384 13.091 65.696 ;
     RECT  12.843 72.729 13.091 73.568 ;
     RECT  2.16 39.808 13.093 41.001 ;
     RECT  12.642 61.056 13.093 62.752 ;
     RECT  12.179 85.952 13.139 86.24 ;
     RECT  13.093 39.808 13.163 42.656 ;
     RECT  13.163 42.624 13.291 42.656 ;
     RECT  13.093 61.056 13.291 63.2 ;
     RECT  12.341 99.584 13.493 100.64 ;
     RECT  13.091 64.96 13.621 65.696 ;
     RECT  12.203 67.329 13.621 68.001 ;
     RECT  13.621 64.96 13.675 68.001 ;
     RECT  13.675 65.344 13.715 68.001 ;
     RECT  12.395 96.832 13.749 97.184 ;
     RECT  13.861 91.776 13.931 92.32 ;
     RECT  13.139 86.208 13.941 86.24 ;
     RECT  13.749 96.832 13.986 97.44 ;
     RECT  13.493 98.816 13.986 100.96 ;
     RECT  13.931 91.776 13.995 91.808 ;
     RECT  13.986 96.832 14.005 100.96 ;
     RECT  11.747 94.208 14.069 95.001 ;
     RECT  14.069 94.144 14.197 95.001 ;
     RECT  14.005 96.832 14.197 101.472 ;
     RECT  14.197 94.144 14.251 101.472 ;
     RECT  14.251 94.144 14.291 100.96 ;
     RECT  12.405 82.56 14.293 84.201 ;
     RECT  13.715 65.344 14.339 65.696 ;
     RECT  14.293 82.112 14.339 84.201 ;
     RECT  14.339 83.529 14.773 84.201 ;
     RECT  13.941 86.208 14.773 86.368 ;
     RECT  12.517 77.248 14.869 78.801 ;
     RECT  14.339 82.112 14.901 82.144 ;
     RECT  14.869 77.248 14.955 79.2 ;
     RECT  14.901 80.896 14.955 82.144 ;
     RECT  14.955 77.248 14.965 78.801 ;
     RECT  14.955 80.896 14.974 80.928 ;
     RECT  13.091 72.729 15.061 73.401 ;
     RECT  14.197 103.424 15.093 103.456 ;
     RECT  15.061 72.729 15.147 74.656 ;
     RECT  14.965 76.032 15.147 78.801 ;
     RECT  15.147 76.608 15.443 78.801 ;
     RECT  13.715 67.329 15.541 68.001 ;
     RECT  15.093 103.168 15.637 103.456 ;
     RECT  14.291 94.144 15.659 100.896 ;
     RECT  15.637 103.168 15.723 103.584 ;
     RECT  12.346 88.929 15.797 89.601 ;
     RECT  14.197 91.52 15.797 91.552 ;
     RECT  15.781 69.888 15.861 69.92 ;
     RECT  15.147 72.729 15.861 73.401 ;
     RECT  15.861 69.888 15.915 73.401 ;
     RECT  15.797 88.929 15.925 91.552 ;
     RECT  15.915 71.168 15.934 73.401 ;
     RECT  13.291 61.056 15.979 62.752 ;
     RECT  15.925 88.384 16.019 91.552 ;
     RECT  14.773 83.529 16.117 86.368 ;
     RECT  16.019 88.384 16.171 89.601 ;
     RECT  16.117 83.529 16.186 86.624 ;
     RECT  16.405 82.048 16.491 82.08 ;
     RECT  13.163 39.808 16.549 41.001 ;
     RECT  15.723 103.168 16.565 103.456 ;
     RECT  15.659 94.208 16.629 100.896 ;
     RECT  16.565 102.912 16.693 103.456 ;
     RECT  16.693 102.784 16.757 103.456 ;
     RECT  15.443 76.608 17.013 76.64 ;
     RECT  16.949 91.712 17.027 91.744 ;
     RECT  15.443 78.016 17.067 78.801 ;
     RECT  16.549 39.68 17.077 41.001 ;
     RECT  14.339 65.408 17.077 65.696 ;
     RECT  17.013 76.48 17.123 76.64 ;
     RECT  17.077 39.68 17.131 41.12 ;
     RECT  17.131 39.808 17.173 41.12 ;
     RECT  16.437 80.64 17.459 80.672 ;
     RECT  16.629 94.208 17.699 101.344 ;
     RECT  17.077 64.832 17.701 65.696 ;
     RECT  15.541 67.2 17.701 68.001 ;
     RECT  17.701 64.832 17.771 68.001 ;
     RECT  15.934 72.729 17.797 73.401 ;
     RECT  15.934 71.168 17.843 71.2 ;
     RECT  11.365 55.872 18.037 59.168 ;
     RECT  15.979 61.056 18.037 62.601 ;
     RECT  17.699 96.32 18.133 101.344 ;
     RECT  16.757 102.72 18.133 103.456 ;
     RECT  16.186 83.529 18.419 86.368 ;
     RECT  18.402 92.864 18.475 92.896 ;
     RECT  18.133 96.32 18.869 103.456 ;
     RECT  17.699 94.208 18.933 95.001 ;
     RECT  18.419 83.529 18.997 85.408 ;
     RECT  18.869 71.296 19.043 71.328 ;
     RECT  18.805 91.136 19.043 91.168 ;
     RECT  18.869 92.544 19.043 92.576 ;
     RECT  17.771 64.832 19.115 64.992 ;
     RECT  19.045 92.288 19.115 92.32 ;
     RECT  18.933 94.016 19.333 95.001 ;
     RECT  18.869 96.32 19.333 103.584 ;
     RECT  19.333 94.016 19.371 103.584 ;
     RECT  17.797 72.729 19.427 74.08 ;
     RECT  18.997 83.264 19.445 85.408 ;
     RECT  17.845 0.192 19.523 0.224 ;
     RECT  19.445 82.624 19.523 85.408 ;
     RECT  17.123 76.48 19.909 76.512 ;
     RECT  17.067 78.129 19.909 78.801 ;
     RECT  19.765 70.72 20.051 70.752 ;
     RECT  16.171 88.929 20.341 89.601 ;
     RECT  19.909 76.48 20.437 78.801 ;
     RECT  20.437 76.48 20.587 79.136 ;
     RECT  2.16 45.729 20.629 46.401 ;
     RECT  7.381 51.129 20.661 52.64 ;
     RECT  17.173 39.808 20.715 41.888 ;
     RECT  20.629 45.568 20.715 46.401 ;
     RECT  20.661 50.752 20.843 52.64 ;
     RECT  18.037 55.872 20.843 62.601 ;
     RECT  19.371 94.016 20.917 101.216 ;
     RECT  20.917 93.888 20.981 101.216 ;
     RECT  19.371 102.528 20.981 103.584 ;
     RECT  20.843 60.928 21.107 62.601 ;
     RECT  20.587 78.129 21.109 79.136 ;
     RECT  20.725 80.896 21.109 80.928 ;
     RECT  19.523 83.529 21.109 85.408 ;
     RECT  19.746 69.376 21.155 69.408 ;
     RECT  20.981 93.888 21.173 103.584 ;
     RECT  21.109 83.264 21.203 85.408 ;
     RECT  20.485 91.2 21.205 91.232 ;
     RECT  21.109 78.129 21.251 80.928 ;
     RECT  21.173 92.8 21.251 103.584 ;
     RECT  20.587 76.48 21.683 76.64 ;
     RECT  21.683 76.608 21.875 76.64 ;
     RECT  21.251 78.129 22.115 79.136 ;
     RECT  19.427 72.729 22.165 73.401 ;
     RECT  20.715 39.808 22.251 41.001 ;
     RECT  20.341 87.936 22.259 89.601 ;
     RECT  22.259 88.929 22.389 89.601 ;
     RECT  21.205 91.136 22.389 91.232 ;
     RECT  22.165 72.576 22.549 73.401 ;
     RECT  19.115 64.832 22.581 64.864 ;
     RECT  22.389 88.929 22.595 91.232 ;
     RECT  22.581 64.576 22.635 64.864 ;
     RECT  22.549 72.576 22.635 73.568 ;
     RECT  21.251 93.12 22.645 103.584 ;
     RECT  22.635 72.576 22.741 73.401 ;
     RECT  22.165 81.216 22.837 81.248 ;
     RECT  22.837 81.216 22.891 82.144 ;
     RECT  22.891 82.112 22.906 82.144 ;
     RECT  22.645 91.712 23.123 103.584 ;
     RECT  20.843 55.872 23.342 59.168 ;
     RECT  23.342 55.872 23.411 59.296 ;
     RECT  22.741 72.448 23.797 73.401 ;
     RECT  23.123 92.864 24.275 103.584 ;
     RECT  23.893 91.136 24.299 91.168 ;
     RECT  24.275 92.864 24.371 103.456 ;
     RECT  17.771 67.329 24.373 68.001 ;
     RECT  24.371 92.864 24.419 101.216 ;
     RECT  2.16 2.529 24.437 3.201 ;
     RECT  24.277 0.384 24.467 0.416 ;
     RECT  22.115 78.129 24.565 78.801 ;
     RECT  22.595 88.929 24.565 89.601 ;
     RECT  23.893 87.168 24.613 87.2 ;
     RECT  24.613 87.168 24.683 87.456 ;
     RECT  24.565 88.929 24.683 90.784 ;
     RECT  24.437 2.529 24.995 3.808 ;
     RECT  22.635 64.576 25.077 64.608 ;
     RECT  24.373 67.329 25.15 68.128 ;
     RECT  25.077 69.632 25.15 69.664 ;
     RECT  25.429 92.544 25.515 92.576 ;
     RECT  23.797 71.552 25.621 73.401 ;
     RECT  25.589 75.2 25.621 75.232 ;
     RECT  22.251 40.329 25.765 41.001 ;
     RECT  20.843 51.129 25.781 52.64 ;
     RECT  25.765 40.329 25.835 41.12 ;
     RECT  24.565 77.44 25.845 78.801 ;
     RECT  25.621 80.512 25.845 80.544 ;
     RECT  23.411 55.872 25.861 59.168 ;
     RECT  25.845 77.44 25.899 80.544 ;
     RECT  24.419 94.016 25.907 101.216 ;
     RECT  25.899 78.016 25.918 80.544 ;
     RECT  25.907 94.329 26.091 101.216 ;
     RECT  26.091 94.329 26.155 96.16 ;
     RECT  25.621 71.552 26.165 75.232 ;
     RECT  26.165 71.552 26.197 75.36 ;
     RECT  24.683 87.168 26.197 87.2 ;
     RECT  24.683 88.929 26.197 89.601 ;
     RECT  26.197 71.04 26.219 75.36 ;
     RECT  25.861 55.808 26.243 59.168 ;
     RECT  24.371 102.592 26.357 103.456 ;
     RECT  25.077 64.576 26.435 65.184 ;
     RECT  25.918 78.016 26.483 78.801 ;
     RECT  26.197 87.168 26.485 89.601 ;
     RECT  26.243 55.872 26.629 59.168 ;
     RECT  26.629 55.872 26.677 59.296 ;
     RECT  21.107 61.056 26.677 62.601 ;
     RECT  26.091 97.472 26.725 101.216 ;
     RECT  26.357 102.592 26.725 103.584 ;
     RECT  26.725 97.472 26.795 103.584 ;
     RECT  26.219 75.328 26.819 75.36 ;
     RECT  26.795 102.72 27.107 103.584 ;
     RECT  27.107 102.912 27.251 103.584 ;
     RECT  25.781 51.129 27.301 52.704 ;
     RECT  26.677 55.872 27.395 62.601 ;
     RECT  26.219 71.04 27.395 73.568 ;
     RECT  26.533 92.864 27.426 92.896 ;
     RECT  27.251 103.424 27.435 103.584 ;
     RECT  27.426 92.032 27.445 92.896 ;
     RECT  27.435 103.424 27.491 103.456 ;
     RECT  27.445 92.032 27.499 92.96 ;
     RECT  27.499 92.864 27.618 92.96 ;
     RECT  26.155 94.329 27.618 95.392 ;
     RECT  26.485 87.168 27.683 90.592 ;
     RECT  27.618 92.864 27.691 95.392 ;
     RECT  27.301 51.129 27.779 53.792 ;
     RECT  26.435 64.576 28.213 64.608 ;
     RECT  27.691 92.864 28.331 92.96 ;
     RECT  27.779 51.129 28.597 51.801 ;
     RECT  26.483 78.129 28.693 78.801 ;
     RECT  25.918 80.512 28.693 80.544 ;
     RECT  28.693 78.129 28.718 80.544 ;
     RECT  28.718 78.016 28.725 80.544 ;
     RECT  28.725 78.016 28.779 81.824 ;
     RECT  25.835 40.329 28.789 41.001 ;
     RECT  26.795 97.472 28.789 101.088 ;
     RECT  28.597 50.752 28.843 51.801 ;
     RECT  28.789 40.329 28.858 42.144 ;
     RECT  27.683 87.808 28.931 90.592 ;
     RECT  28.789 97.152 28.971 101.088 ;
     RECT  28.917 103.296 28.981 103.328 ;
     RECT  29.077 0.384 29.109 0.416 ;
     RECT  27.395 61.056 29.123 62.601 ;
     RECT  21.203 83.529 29.123 85.408 ;
     RECT  29.109 0.256 29.163 0.416 ;
     RECT  29.029 32.448 29.163 32.48 ;
     RECT  27.395 55.872 29.163 59.168 ;
     RECT  29.163 0.256 29.182 0.288 ;
     RECT  29.123 61.184 29.221 62.601 ;
     RECT  28.213 63.936 29.221 64.608 ;
     RECT  27.691 94.329 29.221 95.392 ;
     RECT  28.843 51.129 29.269 51.801 ;
     RECT  28.779 78.016 29.269 78.801 ;
     RECT  29.123 83.529 29.269 85.152 ;
     RECT  29.221 94.329 29.269 95.776 ;
     RECT  28.971 97.152 29.269 97.952 ;
     RECT  28.971 99.729 29.269 101.088 ;
     RECT  27.779 53.76 29.301 53.792 ;
     RECT  29.269 99.729 29.493 101.472 ;
     RECT  28.981 103.296 29.493 103.456 ;
     RECT  29.269 6.208 29.547 6.24 ;
     RECT  29.493 99.729 29.555 103.456 ;
     RECT  27.877 47.808 29.611 47.84 ;
     RECT  29.269 51.129 29.611 51.936 ;
     RECT  29.269 94.329 29.611 97.952 ;
     RECT  29.555 102.592 29.795 103.456 ;
     RECT  28.931 87.808 29.843 90.08 ;
     RECT  29.795 103.168 29.893 103.456 ;
     RECT  29.611 96.896 29.995 97.952 ;
     RECT  29.995 97.408 30.059 97.952 ;
     RECT  28.779 80.512 30.133 81.824 ;
     RECT  29.269 83.2 30.133 85.152 ;
     RECT  29.269 76.992 30.197 78.801 ;
     RECT  30.197 75.904 30.251 78.801 ;
     RECT  27.395 71.04 30.379 73.401 ;
     RECT  30.379 71.04 30.419 71.264 ;
     RECT  29.221 61.184 30.446 64.608 ;
     RECT  30.446 61.184 30.507 65.568 ;
     RECT  28.331 92.928 30.611 92.96 ;
     RECT  30.133 80.512 30.613 85.152 ;
     RECT  30.613 80.512 30.699 85.472 ;
     RECT  30.507 64.576 30.757 65.568 ;
     RECT  29.843 87.808 30.763 89.601 ;
     RECT  29.555 99.729 30.965 100.512 ;
     RECT  29.611 94.329 31.093 95.392 ;
     RECT  30.181 91.584 31.189 91.616 ;
     RECT  30.965 99.729 31.221 100.896 ;
     RECT  30.251 78.129 31.237 78.801 ;
     RECT  31.189 91.136 31.333 91.616 ;
     RECT  30.059 97.408 31.477 97.504 ;
     RECT  31.221 99.584 31.477 100.896 ;
     RECT  29.301 53.504 31.525 53.792 ;
     RECT  29.893 103.168 31.531 103.584 ;
     RECT  31.525 53.504 31.595 54.304 ;
     RECT  31.093 94.208 31.621 95.392 ;
     RECT  31.477 96.832 31.621 97.504 ;
     RECT  31.621 94.208 31.733 97.504 ;
     RECT  31.477 99.008 31.733 100.896 ;
     RECT  29.611 51.129 31.797 51.801 ;
     RECT  31.595 53.504 31.797 53.792 ;
     RECT  30.507 61.184 31.797 62.88 ;
     RECT  30.757 64.576 31.797 65.632 ;
     RECT  31.531 103.168 31.797 103.456 ;
     RECT  31.797 51.129 31.851 53.792 ;
     RECT  30.419 71.04 31.861 71.072 ;
     RECT  30.379 72.576 31.861 73.401 ;
     RECT  31.797 61.184 31.907 65.632 ;
     RECT  31.797 103.04 31.955 103.456 ;
     RECT  30.763 88.064 32.034 89.601 ;
     RECT  30.251 75.904 32.101 76.064 ;
     RECT  32.034 88.064 32.107 89.76 ;
     RECT  31.333 91.136 32.149 91.744 ;
     RECT  25.15 67.329 32.181 68.001 ;
     RECT  31.907 64.96 32.235 65.632 ;
     RECT  31.861 71.04 32.235 73.401 ;
     RECT  32.149 91.136 32.235 92.32 ;
     RECT  31.733 94.208 32.235 100.896 ;
     RECT  29.163 55.936 32.339 59.168 ;
     RECT  20.715 45.729 32.437 46.401 ;
     RECT  31.237 78.129 32.437 78.944 ;
     RECT  32.235 71.744 32.485 73.401 ;
     RECT  32.339 55.936 32.491 58.208 ;
     RECT  32.235 91.136 32.491 91.616 ;
     RECT  32.437 45.568 32.506 46.401 ;
     RECT  31.851 51.129 32.531 53.536 ;
     RECT  32.491 55.936 32.531 58.144 ;
     RECT  32.485 71.744 32.555 73.696 ;
     RECT  32.101 75.584 32.555 76.064 ;
     RECT  32.235 94.208 32.619 95.2 ;
     RECT  30.699 81.6 32.675 84.201 ;
     RECT  32.235 96.576 32.811 100.896 ;
     RECT  32.811 98.56 32.885 100.896 ;
     RECT  32.885 98.56 32.939 100.96 ;
     RECT  32.181 67.329 33.013 68.32 ;
     RECT  32.555 76.032 33.251 76.064 ;
     RECT  32.491 91.136 33.299 91.168 ;
     RECT  31.955 103.168 33.323 103.456 ;
     RECT  32.811 96.576 33.387 96.992 ;
     RECT  32.619 94.208 33.445 95.136 ;
     RECT  33.323 103.296 33.445 103.456 ;
     RECT  33.445 103.296 33.491 103.584 ;
     RECT  33.445 94.08 33.515 95.136 ;
     RECT  33.491 103.424 33.515 103.584 ;
     RECT  33.387 96.576 33.683 96.608 ;
     RECT  32.531 51.129 33.931 53.024 ;
     RECT  32.437 78.129 33.971 79.2 ;
     RECT  33.515 94.329 34.069 95.136 ;
     RECT  32.939 99.2 34.163 100.96 ;
     RECT  34.163 99.2 34.259 100.401 ;
     RECT  32.555 72.576 34.261 73.401 ;
     RECT  33.013 67.329 34.499 69.472 ;
     RECT  2.16 24.129 34.597 24.801 ;
     RECT  32.531 56.529 34.693 58.144 ;
     RECT  32.675 81.6 34.693 81.632 ;
     RECT  34.499 67.329 34.739 68.32 ;
     RECT  34.069 94.329 34.795 96.288 ;
     RECT  34.597 24 34.859 25.056 ;
     RECT  34.693 56.384 34.869 58.144 ;
     RECT  34.869 56.384 34.923 58.848 ;
     RECT  34.859 24.129 34.987 25.056 ;
     RECT  31.907 61.184 34.997 62.601 ;
     RECT  32.675 83.529 34.997 84.201 ;
     RECT  32.107 88.064 35.061 89.601 ;
     RECT  33.931 50.432 35.189 53.024 ;
     RECT  34.997 60.992 35.219 62.601 ;
     RECT  34.997 83.529 35.219 85.088 ;
     RECT  35.125 92.992 35.219 93.024 ;
     RECT  35.061 88.064 35.221 90.848 ;
     RECT  35.189 49.344 35.267 53.024 ;
     RECT  35.221 88.064 35.267 91.168 ;
     RECT  34.885 0.256 35.315 0.288 ;
     RECT  34.923 56.529 35.363 58.848 ;
     RECT  34.693 81.6 35.363 81.76 ;
     RECT  35.267 88.064 35.363 89.601 ;
     RECT  35.219 61.184 35.411 62.601 ;
     RECT  35.267 50.432 35.459 51.801 ;
     RECT  33.515 103.424 35.461 103.456 ;
     RECT  34.259 99.729 35.557 100.401 ;
     RECT  35.189 97.152 35.573 97.184 ;
     RECT  34.261 72.448 35.699 73.401 ;
     RECT  35.461 103.296 35.701 103.456 ;
     RECT  35.573 97.152 35.829 97.44 ;
     RECT  35.557 99.584 35.829 100.401 ;
     RECT  35.699 72.576 35.939 73.401 ;
     RECT  35.267 91.136 35.939 91.168 ;
     RECT  34.795 94.329 35.987 95.136 ;
     RECT  35.701 103.232 35.989 103.456 ;
     RECT  35.363 81.728 36.035 81.76 ;
     RECT  35.829 97.152 36.133 100.512 ;
     RECT  36.133 97.152 36.395 100.704 ;
     RECT  36.395 98.496 36.398 100.704 ;
     RECT  35.363 58.816 36.515 58.848 ;
     RECT  35.269 74.816 36.515 74.848 ;
     RECT  35.989 103.168 36.515 103.456 ;
     RECT  36.398 98.496 36.533 100.832 ;
     RECT  35.987 94.329 36.949 95.001 ;
     RECT  36.757 96.832 36.981 97.056 ;
     RECT  36.949 93.312 37.429 95.001 ;
     RECT  37.429 92.288 37.498 95.001 ;
     RECT  34.021 70.784 37.667 70.816 ;
     RECT  36.533 98.496 37.813 100.896 ;
     RECT  36.981 96.576 37.877 97.056 ;
     RECT  37.813 98.496 37.877 100.96 ;
     RECT  37.877 96.576 37.941 100.96 ;
     RECT  37.941 96.576 37.955 101.216 ;
     RECT  36.515 103.424 37.995 103.456 ;
     RECT  38.053 91.712 38.123 91.744 ;
     RECT  38.005 103.296 38.123 103.328 ;
     RECT  37.955 96.896 38.206 101.216 ;
     RECT  37.498 93.312 38.291 95.001 ;
     RECT  38.206 96.896 38.379 98.272 ;
     RECT  38.206 99.729 38.483 101.216 ;
     RECT  38.379 96.896 38.627 97.184 ;
     RECT  38.627 96.896 38.819 97.056 ;
     RECT  38.819 97.024 38.867 97.056 ;
     RECT  38.483 99.729 39.155 100.896 ;
     RECT  24.995 2.529 50.49 3.201 ;
     RECT  2.16 7.929 50.49 8.601 ;
     RECT  2.16 13.329 50.49 14.001 ;
     RECT  2.16 18.729 50.49 19.401 ;
     RECT  34.987 24.129 50.49 24.801 ;
     RECT  2.16 29.529 50.49 30.201 ;
     RECT  2.16 34.929 50.49 35.601 ;
     RECT  28.858 40.329 50.49 41.001 ;
     RECT  32.506 45.729 50.49 46.401 ;
     RECT  35.459 51.129 50.49 51.801 ;
     RECT  35.363 56.529 50.49 57.201 ;
     RECT  35.411 61.929 50.49 62.601 ;
     RECT  34.739 67.329 50.49 68.001 ;
     RECT  35.939 72.729 50.49 73.401 ;
     RECT  33.971 78.129 50.49 78.801 ;
     RECT  35.219 83.529 50.49 84.201 ;
     RECT  35.363 88.929 50.49 89.601 ;
     RECT  38.291 94.329 50.49 95.001 ;
     RECT  39.155 99.729 50.49 100.401 ;
    LAYER M7 ;
     RECT  29.12 0.245 29.152 0.427 ;
     RECT  34.816 23.989 34.848 25.013 ;
     RECT  29.504 6.197 29.536 32.437 ;
     RECT  17.088 39.669 17.12 41.131 ;
     RECT  29.12 32.437 29.536 42.101 ;
     RECT  13.12 42.229 13.152 42.613 ;
     RECT  28.8 42.101 29.536 47.797 ;
     RECT  34.816 25.013 34.976 49.333 ;
     RECT  34.816 49.333 35.232 50.421 ;
     RECT  33.984 50.421 35.232 50.475 ;
     RECT  20.672 41.845 20.704 50.741 ;
     RECT  20.672 50.741 20.832 50.795 ;
     RECT  28.8 47.797 29.6 50.795 ;
     RECT  24.448 3.765 24.48 51.947 ;
     RECT  29.12 50.795 29.6 51.947 ;
     RECT  18.816 51.893 19.104 52.075 ;
     RECT  25.792 41.077 25.824 52.661 ;
     RECT  25.792 52.661 26.016 52.715 ;
     RECT  32.448 45.557 32.48 52.981 ;
     RECT  33.984 50.475 34.976 53.035 ;
     RECT  31.808 52.981 32.48 53.493 ;
     RECT  31.552 53.493 32.48 54.315 ;
     RECT  25.984 52.715 26.016 55.797 ;
     RECT  22.208 39.797 22.24 56.373 ;
     RECT  29.12 51.947 29.536 56.427 ;
     RECT  29.12 56.427 29.472 57.323 ;
     RECT  25.984 55.797 26.08 57.771 ;
     RECT  31.808 54.315 32.48 58.219 ;
     RECT  25.984 57.771 26.016 59.253 ;
     RECT  22.208 56.373 23.392 59.307 ;
     RECT  20.8 50.795 20.832 59.947 ;
     RECT  25.984 59.253 26.72 60.459 ;
     RECT  34.816 53.035 34.976 60.981 ;
     RECT  34.816 60.981 35.04 61.493 ;
     RECT  34.816 61.493 35.232 61.803 ;
     RECT  13.12 42.613 13.28 62.709 ;
     RECT  15.936 61.813 15.968 62.763 ;
     RECT  29.44 57.323 29.472 62.837 ;
     RECT  12.672 62.709 13.28 63.211 ;
     RECT  31.808 58.219 32.288 63.723 ;
     RECT  29.44 62.837 29.6 63.733 ;
     RECT  12.672 63.211 12.704 64.373 ;
     RECT  12.16 64.373 12.704 64.427 ;
     RECT  22.208 59.307 22.24 64.565 ;
     RECT  19.072 52.075 19.104 64.949 ;
     RECT  25.984 60.459 26.016 64.949 ;
     RECT  18.88 64.949 19.104 65.003 ;
     RECT  29.44 63.733 30.496 65.579 ;
     RECT  12.16 64.427 12.192 65.653 ;
     RECT  18.88 65.003 18.912 66.037 ;
     RECT  13.632 64.949 13.664 66.219 ;
     RECT  11.712 65.653 12.192 66.987 ;
     RECT  17.728 66.037 18.912 67.243 ;
     RECT  9.088 65.461 9.12 68.907 ;
     RECT  18.88 67.243 18.912 69.365 ;
     RECT  25.088 64.949 26.016 69.675 ;
     RECT  11.712 66.987 11.744 70.069 ;
     RECT  18.88 69.365 19.808 70.763 ;
     RECT  29.44 65.579 29.472 71.221 ;
     RECT  18.88 70.763 18.912 71.339 ;
     RECT  25.984 69.675 26.016 71.541 ;
     RECT  11.712 70.069 12.832 71.595 ;
     RECT  32.192 63.723 32.288 71.733 ;
     RECT  15.872 69.877 15.904 71.851 ;
     RECT  11.712 71.595 11.744 72.619 ;
     RECT  22.208 64.565 22.624 72.619 ;
     RECT  29.44 71.221 30.368 72.619 ;
     RECT  32.192 71.733 32.544 72.619 ;
     RECT  7.168 70.645 7.2 74.283 ;
     RECT  12.8 73.525 12.832 75.115 ;
     RECT  25.984 71.541 26.208 75.189 ;
     RECT  25.6 75.189 26.208 75.371 ;
     RECT  29.44 72.619 29.472 75.893 ;
     RECT  15.104 74.613 15.136 76.075 ;
     RECT  32.256 72.619 32.544 76.075 ;
     RECT  8.512 76.085 8.544 77.483 ;
     RECT  25.6 75.371 26.016 77.483 ;
     RECT  11.136 75.765 11.168 77.803 ;
     RECT  29.44 75.893 30.24 78.005 ;
     RECT  20.544 76.597 20.576 79.093 ;
     RECT  20.544 79.093 21.152 79.147 ;
     RECT  25.856 77.483 26.016 79.403 ;
     RECT  28.736 78.005 30.24 80.501 ;
     RECT  17.024 76.469 17.056 80.629 ;
     RECT  11.84 80.309 11.872 80.949 ;
     RECT  22.592 72.619 22.624 81.205 ;
     RECT  28.736 80.501 30.688 81.835 ;
     RECT  14.912 79.157 14.944 82.155 ;
     RECT  22.592 81.205 22.88 82.155 ;
     RECT  32.256 76.075 32.288 82.293 ;
     RECT  11.84 80.949 12.448 82.731 ;
     RECT  32 82.293 32.288 82.731 ;
     RECT  9.344 77.941 9.376 83.307 ;
     RECT  13.888 82.549 13.92 83.307 ;
     RECT  21.12 79.147 21.152 83.307 ;
     RECT  32 82.731 32.032 83.435 ;
     RECT  25.984 79.403 26.016 84.331 ;
     RECT  19.456 82.613 19.488 84.523 ;
     RECT  16.448 80.629 17.056 84.971 ;
     RECT  35.008 61.803 35.232 85.099 ;
     RECT  11.84 82.731 11.872 85.355 ;
     RECT  22.592 82.155 22.624 85.419 ;
     RECT  16.448 84.971 16.672 86.379 ;
     RECT  29.44 81.835 30.688 87.797 ;
     RECT  10.496 86.581 10.528 87.915 ;
     RECT  29.44 87.797 30.752 88.107 ;
     RECT  16.128 86.581 16.16 88.427 ;
     RECT  32.192 88.053 32.224 88.757 ;
     RECT  32.192 88.757 33.056 89.717 ;
     RECT  29.44 88.107 29.472 90.091 ;
     RECT  10.368 89.973 10.4 90.667 ;
     RECT  24.64 87.157 24.672 90.795 ;
     RECT  35.072 85.099 35.232 90.859 ;
     RECT  22.4 90.549 22.432 91.125 ;
     RECT  32.064 89.717 33.056 91.125 ;
     RECT  12.288 90.549 12.32 91.243 ;
     RECT  15.808 90.549 15.84 91.243 ;
     RECT  21.248 91.125 22.432 91.701 ;
     RECT  13.952 86.197 13.984 91.819 ;
     RECT  8.064 90.421 8.096 92.139 ;
     RECT  18.816 91.125 18.848 92.277 ;
     RECT  38.08 91.701 38.112 92.277 ;
     RECT  21.248 91.701 22.752 92.533 ;
     RECT  24.256 91.125 24.288 92.533 ;
     RECT  26.496 90.549 27.488 92.533 ;
     RECT  21.248 92.533 22.944 92.789 ;
     RECT  18.816 92.277 19.104 92.853 ;
     RECT  21.184 92.789 22.944 92.853 ;
     RECT  24.256 92.533 27.488 92.853 ;
     RECT  35.136 90.859 35.232 93.035 ;
     RECT  37.44 92.277 38.112 93.429 ;
     RECT  21.184 92.853 28.32 93.877 ;
     RECT  18.432 92.853 19.104 94.005 ;
     RECT  20.928 93.877 28.32 94.005 ;
     RECT  31.232 91.125 33.056 94.069 ;
     RECT  13.888 92.277 13.92 94.133 ;
     RECT  13.888 94.133 15.648 94.251 ;
     RECT  31.232 94.069 33.504 95.093 ;
     RECT  16.96 91.701 16.992 95.157 ;
     RECT  30.848 95.093 33.504 95.221 ;
     RECT  18.432 94.005 28.32 95.733 ;
     RECT  30.72 95.221 33.504 95.733 ;
     RECT  14.08 94.251 15.648 96.181 ;
     RECT  16.96 95.157 17.12 96.181 ;
     RECT  18.432 95.733 33.504 96.245 ;
     RECT  35.2 93.035 35.232 96.245 ;
     RECT  9.728 95.157 9.76 96.373 ;
     RECT  6.464 95.093 6.496 96.555 ;
     RECT  14.08 96.181 17.12 96.565 ;
     RECT  18.432 96.245 35.232 96.565 ;
     RECT  37.12 93.429 38.112 96.565 ;
     RECT  11.52 93.877 11.552 96.821 ;
     RECT  36.992 96.565 38.112 96.821 ;
     RECT  11.52 96.821 12.064 96.875 ;
     RECT  14.08 96.565 35.232 97.141 ;
     RECT  36.8 96.821 38.112 97.141 ;
     RECT  8.512 96.373 9.76 97.259 ;
     RECT  8.512 97.259 8.544 97.717 ;
     RECT  8 97.717 8.544 97.771 ;
     RECT  12.032 96.875 12.064 97.973 ;
     RECT  13.632 97.141 38.112 97.973 ;
     RECT  12.032 97.973 38.112 98.091 ;
     RECT  12.352 98.091 38.112 98.229 ;
     RECT  8 97.771 8.032 98.667 ;
     RECT  10.88 99.573 10.912 100.523 ;
     RECT  12.352 98.229 38.368 100.651 ;
     RECT  13.504 100.651 38.112 100.971 ;
     RECT  14.208 100.971 38.112 101.099 ;
     RECT  28.928 101.099 38.112 103.339 ;
     RECT  14.208 101.099 27.104 103.413 ;
     RECT  14.208 103.413 27.424 103.467 ;
     RECT  28.992 103.339 37.984 103.467 ;
     RECT  15.68 103.467 15.712 103.595 ;
     RECT  18.88 103.467 18.912 103.595 ;
     RECT  21.632 103.467 21.664 103.595 ;
     RECT  26.368 103.467 27.424 103.595 ;
     RECT  29.952 103.467 31.52 103.595 ;
     RECT  33.472 103.467 33.504 103.595 ;
  END
END ot_qwen_die_station
END LIBRARY
